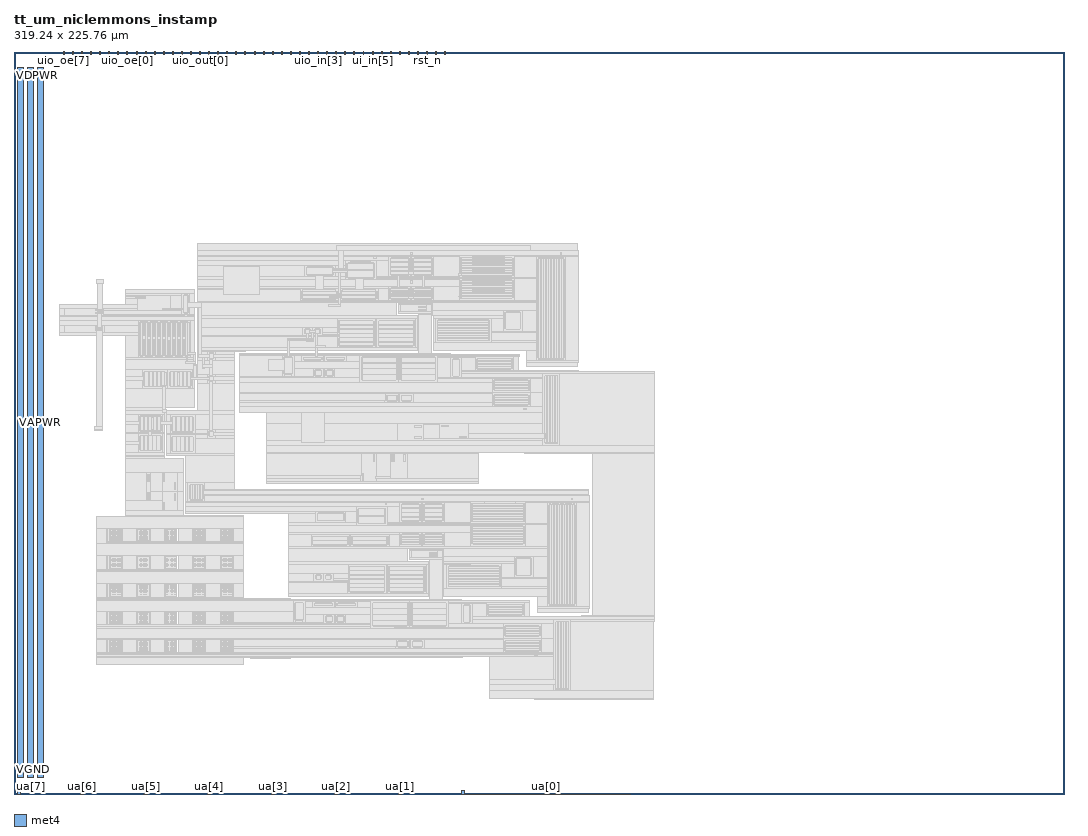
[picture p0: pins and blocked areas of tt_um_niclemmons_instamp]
MACRO tt_um_niclemmons_instamp
  CLASS BLOCK ;
  FOREIGN tt_um_niclemmons_instamp ;
  ORIGIN 0.000 0.000 ;
  SIZE 319.240 BY 225.760 ;
  PIN clk
    DIRECTION INPUT ;
    USE SIGNAL ;
    PORT
      LAYER met4 ;
        RECT 128.190 224.760 128.490 225.760 ;
    END
  END clk
  PIN ena
    DIRECTION INPUT ;
    USE SIGNAL ;
    PORT
      LAYER met4 ;
        RECT 130.950 224.760 131.250 225.760 ;
    END
  END ena
  PIN rst_n
    DIRECTION INPUT ;
    USE SIGNAL ;
    PORT
      LAYER met4 ;
        RECT 125.430 224.760 125.730 225.760 ;
    END
  END rst_n
  PIN ua[0]
    DIRECTION INOUT ;
    USE SIGNAL ;
    ANTENNADIFFAREA 69.599998 ;
    PORT
      LAYER met4 ;
        RECT 136.170 0.000 137.070 1.000 ;
        RECT 136.270 -0.020 187.300 0.000 ;
        RECT 185.690 -0.060 187.300 -0.020 ;
    END
  END ua[0]
  PIN ua[1]
    DIRECTION INOUT ;
    USE SIGNAL ;
    ANTENNAGATEAREA 60.000000 ;
    PORT
      LAYER met4 ;
        RECT 116.850 0.000 117.750 1.000 ;
    END
  END ua[1]
  PIN ua[2]
    DIRECTION INOUT ;
    USE SIGNAL ;
    ANTENNAGATEAREA 60.000000 ;
    PORT
      LAYER met4 ;
        RECT 97.530 0.000 98.430 1.000 ;
    END
  END ua[2]
  PIN ua[3]
    DIRECTION INOUT ;
    USE SIGNAL ;
    ANTENNAGATEAREA 60.000000 ;
    PORT
      LAYER met4 ;
        RECT 78.210 0.000 79.110 1.000 ;
    END
  END ua[3]
  PIN ua[4]
    DIRECTION INOUT ;
    USE SIGNAL ;
    ANTENNAGATEAREA 60.000000 ;
    PORT
      LAYER met4 ;
        RECT 58.890 0.000 59.790 1.000 ;
        RECT 58.850 -0.110 59.820 0.000 ;
    END
  END ua[4]
  PIN ua[5]
    DIRECTION INOUT ;
    USE SIGNAL ;
    ANTENNAGATEAREA 45.000000 ;
    ANTENNADIFFAREA 3.480000 ;
    PORT
      LAYER met4 ;
        RECT 39.570 0.000 40.470 1.000 ;
        RECT 39.510 -0.020 40.370 0.000 ;
    END
  END ua[5]
  PIN ua[6]
    DIRECTION INOUT ;
    USE SIGNAL ;
    PORT
      LAYER met4 ;
        RECT 20.250 0.000 21.150 1.000 ;
    END
  END ua[6]
  PIN ua[7]
    DIRECTION INOUT ;
    USE SIGNAL ;
    PORT
      LAYER met4 ;
        RECT 0.930 0.000 1.830 1.000 ;
    END
  END ua[7]
  PIN ui_in[0]
    DIRECTION INPUT ;
    USE SIGNAL ;
    PORT
      LAYER met4 ;
        RECT 122.670 224.760 122.970 225.760 ;
    END
  END ui_in[0]
  PIN ui_in[1]
    DIRECTION INPUT ;
    USE SIGNAL ;
    PORT
      LAYER met4 ;
        RECT 119.910 224.760 120.210 225.760 ;
    END
  END ui_in[1]
  PIN ui_in[2]
    DIRECTION INPUT ;
    USE SIGNAL ;
    PORT
      LAYER met4 ;
        RECT 117.150 224.760 117.450 225.760 ;
    END
  END ui_in[2]
  PIN ui_in[3]
    DIRECTION INPUT ;
    USE SIGNAL ;
    PORT
      LAYER met4 ;
        RECT 114.390 224.760 114.690 225.760 ;
    END
  END ui_in[3]
  PIN ui_in[4]
    DIRECTION INPUT ;
    USE SIGNAL ;
    PORT
      LAYER met4 ;
        RECT 111.630 224.760 111.930 225.760 ;
    END
  END ui_in[4]
  PIN ui_in[5]
    DIRECTION INPUT ;
    USE SIGNAL ;
    PORT
      LAYER met4 ;
        RECT 108.870 224.760 109.170 225.760 ;
    END
  END ui_in[5]
  PIN ui_in[6]
    DIRECTION INPUT ;
    USE SIGNAL ;
    PORT
      LAYER met4 ;
        RECT 106.110 224.760 106.410 225.760 ;
    END
  END ui_in[6]
  PIN ui_in[7]
    DIRECTION INPUT ;
    USE SIGNAL ;
    PORT
      LAYER met4 ;
        RECT 103.350 224.760 103.650 225.760 ;
    END
  END ui_in[7]
  PIN uio_in[0]
    DIRECTION INPUT ;
    USE SIGNAL ;
    PORT
      LAYER met4 ;
        RECT 100.590 224.760 100.890 225.760 ;
    END
  END uio_in[0]
  PIN uio_in[1]
    DIRECTION INPUT ;
    USE SIGNAL ;
    PORT
      LAYER met4 ;
        RECT 97.830 224.760 98.130 225.760 ;
    END
  END uio_in[1]
  PIN uio_in[2]
    DIRECTION INPUT ;
    USE SIGNAL ;
    PORT
      LAYER met4 ;
        RECT 95.070 224.760 95.370 225.760 ;
    END
  END uio_in[2]
  PIN uio_in[3]
    DIRECTION INPUT ;
    USE SIGNAL ;
    PORT
      LAYER met4 ;
        RECT 92.310 224.760 92.610 225.760 ;
    END
  END uio_in[3]
  PIN uio_in[4]
    DIRECTION INPUT ;
    USE SIGNAL ;
    PORT
      LAYER met4 ;
        RECT 89.550 224.760 89.850 225.760 ;
    END
  END uio_in[4]
  PIN uio_in[5]
    DIRECTION INPUT ;
    USE SIGNAL ;
    PORT
      LAYER met4 ;
        RECT 86.790 224.760 87.090 225.760 ;
    END
  END uio_in[5]
  PIN uio_in[6]
    DIRECTION INPUT ;
    USE SIGNAL ;
    PORT
      LAYER met4 ;
        RECT 84.030 224.760 84.330 225.760 ;
    END
  END uio_in[6]
  PIN uio_in[7]
    DIRECTION INPUT ;
    USE SIGNAL ;
    PORT
      LAYER met4 ;
        RECT 81.270 224.760 81.570 225.760 ;
    END
  END uio_in[7]
  PIN uio_oe[0]
    DIRECTION OUTPUT ;
    USE SIGNAL ;
    ANTENNAGATEAREA 668.222473 ;
    ANTENNADIFFAREA 820.115173 ;
    PORT
      LAYER met4 ;
        RECT 34.350 224.760 34.650 225.760 ;
    END
  END uio_oe[0]
  PIN uio_oe[1]
    DIRECTION OUTPUT ;
    USE SIGNAL ;
    ANTENNAGATEAREA 668.222473 ;
    ANTENNADIFFAREA 820.115173 ;
    PORT
      LAYER met4 ;
        RECT 31.590 224.760 31.890 225.760 ;
    END
  END uio_oe[1]
  PIN uio_oe[2]
    DIRECTION OUTPUT ;
    USE SIGNAL ;
    ANTENNAGATEAREA 668.222473 ;
    ANTENNADIFFAREA 820.115173 ;
    PORT
      LAYER met4 ;
        RECT 28.830 224.760 29.130 225.760 ;
    END
  END uio_oe[2]
  PIN uio_oe[3]
    DIRECTION OUTPUT ;
    USE SIGNAL ;
    ANTENNAGATEAREA 668.222473 ;
    ANTENNADIFFAREA 820.115173 ;
    PORT
      LAYER met4 ;
        RECT 26.070 224.760 26.370 225.760 ;
    END
  END uio_oe[3]
  PIN uio_oe[4]
    DIRECTION OUTPUT ;
    USE SIGNAL ;
    ANTENNAGATEAREA 668.222473 ;
    ANTENNADIFFAREA 820.115173 ;
    PORT
      LAYER met4 ;
        RECT 23.310 224.760 23.610 225.760 ;
    END
  END uio_oe[4]
  PIN uio_oe[5]
    DIRECTION OUTPUT ;
    USE SIGNAL ;
    ANTENNAGATEAREA 668.222473 ;
    ANTENNADIFFAREA 820.115173 ;
    PORT
      LAYER met4 ;
        RECT 20.550 224.760 20.850 225.760 ;
    END
  END uio_oe[5]
  PIN uio_oe[6]
    DIRECTION OUTPUT ;
    USE SIGNAL ;
    ANTENNAGATEAREA 668.222473 ;
    ANTENNADIFFAREA 820.115173 ;
    PORT
      LAYER met4 ;
        RECT 17.790 224.760 18.090 225.760 ;
    END
  END uio_oe[6]
  PIN uio_oe[7]
    DIRECTION OUTPUT ;
    USE SIGNAL ;
    ANTENNAGATEAREA 668.222473 ;
    ANTENNADIFFAREA 820.115173 ;
    PORT
      LAYER met4 ;
        RECT 15.030 224.760 15.330 225.760 ;
    END
  END uio_oe[7]
  PIN uio_out[0]
    DIRECTION OUTPUT ;
    USE SIGNAL ;
    ANTENNAGATEAREA 668.222473 ;
    ANTENNADIFFAREA 820.115173 ;
    PORT
      LAYER met4 ;
        RECT 56.430 224.760 56.730 225.760 ;
    END
  END uio_out[0]
  PIN uio_out[1]
    DIRECTION OUTPUT ;
    USE SIGNAL ;
    ANTENNAGATEAREA 668.222473 ;
    ANTENNADIFFAREA 820.115173 ;
    PORT
      LAYER met4 ;
        RECT 53.670 224.760 53.970 225.760 ;
    END
  END uio_out[1]
  PIN uio_out[2]
    DIRECTION OUTPUT ;
    USE SIGNAL ;
    ANTENNAGATEAREA 668.222473 ;
    ANTENNADIFFAREA 820.115173 ;
    PORT
      LAYER met4 ;
        RECT 50.910 224.760 51.210 225.760 ;
    END
  END uio_out[2]
  PIN uio_out[3]
    DIRECTION OUTPUT ;
    USE SIGNAL ;
    ANTENNAGATEAREA 668.222473 ;
    ANTENNADIFFAREA 820.115173 ;
    PORT
      LAYER met4 ;
        RECT 48.150 224.760 48.450 225.760 ;
    END
  END uio_out[3]
  PIN uio_out[4]
    DIRECTION OUTPUT ;
    USE SIGNAL ;
    ANTENNAGATEAREA 668.222473 ;
    ANTENNADIFFAREA 820.115173 ;
    PORT
      LAYER met4 ;
        RECT 45.390 224.760 45.690 225.760 ;
    END
  END uio_out[4]
  PIN uio_out[5]
    DIRECTION OUTPUT ;
    USE SIGNAL ;
    ANTENNAGATEAREA 668.222473 ;
    ANTENNADIFFAREA 820.115173 ;
    PORT
      LAYER met4 ;
        RECT 42.630 224.760 42.930 225.760 ;
    END
  END uio_out[5]
  PIN uio_out[6]
    DIRECTION OUTPUT ;
    USE SIGNAL ;
    ANTENNAGATEAREA 668.222473 ;
    ANTENNADIFFAREA 820.115173 ;
    PORT
      LAYER met4 ;
        RECT 39.870 224.760 40.170 225.760 ;
    END
  END uio_out[6]
  PIN uio_out[7]
    DIRECTION OUTPUT ;
    USE SIGNAL ;
    ANTENNAGATEAREA 668.222473 ;
    ANTENNADIFFAREA 820.115173 ;
    PORT
      LAYER met4 ;
        RECT 37.110 224.760 37.410 225.760 ;
    END
  END uio_out[7]
  PIN uo_out[0]
    DIRECTION OUTPUT ;
    USE SIGNAL ;
    ANTENNAGATEAREA 668.222473 ;
    ANTENNADIFFAREA 820.115173 ;
    PORT
      LAYER met4 ;
        RECT 78.510 224.760 78.810 225.760 ;
    END
  END uo_out[0]
  PIN uo_out[1]
    DIRECTION OUTPUT ;
    USE SIGNAL ;
    ANTENNAGATEAREA 668.222473 ;
    ANTENNADIFFAREA 820.115173 ;
    PORT
      LAYER met4 ;
        RECT 75.750 224.760 76.050 225.760 ;
    END
  END uo_out[1]
  PIN uo_out[2]
    DIRECTION OUTPUT ;
    USE SIGNAL ;
    ANTENNAGATEAREA 668.222473 ;
    ANTENNADIFFAREA 820.115173 ;
    PORT
      LAYER met4 ;
        RECT 72.990 224.760 73.290 225.760 ;
    END
  END uo_out[2]
  PIN uo_out[3]
    DIRECTION OUTPUT ;
    USE SIGNAL ;
    ANTENNAGATEAREA 668.222473 ;
    ANTENNADIFFAREA 820.115173 ;
    PORT
      LAYER met4 ;
        RECT 70.230 224.760 70.530 225.760 ;
    END
  END uo_out[3]
  PIN uo_out[4]
    DIRECTION OUTPUT ;
    USE SIGNAL ;
    ANTENNAGATEAREA 668.222473 ;
    ANTENNADIFFAREA 820.115173 ;
    PORT
      LAYER met4 ;
        RECT 67.470 224.760 67.770 225.760 ;
    END
  END uo_out[4]
  PIN uo_out[5]
    DIRECTION OUTPUT ;
    USE SIGNAL ;
    ANTENNAGATEAREA 668.222473 ;
    ANTENNADIFFAREA 820.115173 ;
    PORT
      LAYER met4 ;
        RECT 64.710 224.760 65.010 225.760 ;
    END
  END uo_out[5]
  PIN uo_out[6]
    DIRECTION OUTPUT ;
    USE SIGNAL ;
    ANTENNAGATEAREA 668.222473 ;
    ANTENNADIFFAREA 820.115173 ;
    PORT
      LAYER met4 ;
        RECT 61.950 224.760 62.250 225.760 ;
    END
  END uo_out[6]
  PIN uo_out[7]
    DIRECTION OUTPUT ;
    USE SIGNAL ;
    ANTENNAGATEAREA 668.222473 ;
    ANTENNADIFFAREA 820.115173 ;
    PORT
      LAYER met4 ;
        RECT 59.190 224.760 59.490 225.760 ;
    END
  END uo_out[7]
  PIN VDPWR
    DIRECTION INOUT ;
    USE POWER ;
    PORT
      LAYER met4 ;
        RECT 1.000 5.000 3.000 220.760 ;
    END
  END VDPWR
  PIN VGND
    DIRECTION INOUT ;
    USE GROUND ;
    PORT
      LAYER met4 ;
        RECT 4.000 5.000 6.000 220.760 ;
    END
  END VGND
  PIN VAPWR
    DIRECTION INOUT ;
    USE POWER ;
    PORT
      LAYER met4 ;
        RECT 7.000 5.000 9.000 220.760 ;
    END
  END VAPWR
  OBS
      LAYER nwell ;
        RECT 87.760 156.750 98.230 161.330 ;
        RECT 100.230 155.830 110.700 162.700 ;
        RECT 113.290 156.600 128.280 164.050 ;
      LAYER pwell ;
        RECT 14.880 145.220 27.720 148.060 ;
        RECT 37.030 146.530 48.020 151.860 ;
        RECT 50.540 145.200 53.840 152.780 ;
      LAYER nwell ;
        RECT 86.340 149.320 111.330 154.190 ;
        RECT 113.260 149.405 128.250 154.855 ;
        RECT 134.885 149.535 152.855 164.225 ;
      LAYER pwell ;
        RECT 117.170 146.230 125.910 149.070 ;
        RECT 14.940 140.020 27.780 142.860 ;
        RECT 37.230 132.240 54.020 144.540 ;
      LAYER nwell ;
        RECT 87.270 138.830 94.260 142.410 ;
        RECT 58.220 131.220 61.800 135.190 ;
        RECT 97.590 135.060 122.580 145.090 ;
        RECT 127.630 136.670 145.600 145.280 ;
        RECT 148.140 140.090 155.110 147.670 ;
      LAYER pwell ;
        RECT 38.565 122.905 54.835 129.485 ;
      LAYER nwell ;
        RECT 58.210 124.340 61.790 128.310 ;
      LAYER pwell ;
        RECT 81.100 126.620 85.680 133.920 ;
        RECT 87.020 130.980 101.530 133.780 ;
        RECT 90.480 126.080 97.990 129.880 ;
        RECT 104.710 124.750 129.220 133.920 ;
        RECT 132.330 125.940 136.410 133.240 ;
        RECT 139.760 128.210 152.340 133.380 ;
      LAYER nwell ;
        RECT 158.220 131.100 168.410 164.070 ;
      LAYER pwell ;
        RECT 112.340 118.410 121.850 122.210 ;
        RECT 144.960 117.190 157.540 126.880 ;
        RECT 37.190 103.430 45.650 115.940 ;
      LAYER nwell ;
        RECT 46.935 102.915 55.675 115.905 ;
        RECT 58.175 107.565 61.755 111.535 ;
      LAYER pwell ;
        RECT 116.280 107.120 124.760 112.980 ;
        RECT 129.090 107.610 138.550 112.940 ;
        RECT 160.330 105.620 166.290 128.200 ;
        RECT 39.870 88.800 41.880 98.120 ;
        RECT 44.670 85.760 50.000 98.150 ;
      LAYER nwell ;
        RECT 52.300 88.260 58.540 95.230 ;
      LAYER pwell ;
        RECT 105.110 94.570 110.440 104.030 ;
        RECT 114.090 95.620 119.950 104.100 ;
        RECT 27.590 81.385 34.290 82.150 ;
        RECT 27.590 76.215 28.355 81.385 ;
        RECT 33.525 76.215 34.290 81.385 ;
        RECT 27.590 75.450 34.290 76.215 ;
        RECT 36.030 81.385 42.730 82.150 ;
        RECT 36.030 76.215 36.795 81.385 ;
        RECT 41.965 76.215 42.730 81.385 ;
        RECT 36.030 75.450 42.730 76.215 ;
        RECT 44.470 81.385 51.170 82.150 ;
        RECT 44.470 76.215 45.235 81.385 ;
        RECT 50.405 76.215 51.170 81.385 ;
        RECT 44.470 75.450 51.170 76.215 ;
        RECT 52.910 81.385 59.610 82.150 ;
        RECT 52.910 76.215 53.675 81.385 ;
        RECT 58.845 76.215 59.610 81.385 ;
        RECT 52.910 75.450 59.610 76.215 ;
        RECT 61.350 81.385 68.050 82.150 ;
      LAYER nwell ;
        RECT 91.070 82.010 101.540 86.590 ;
      LAYER pwell ;
        RECT 61.350 76.215 62.115 81.385 ;
        RECT 67.285 76.215 68.050 81.385 ;
      LAYER nwell ;
        RECT 103.540 81.090 114.010 87.960 ;
        RECT 116.600 81.860 131.590 89.310 ;
      LAYER pwell ;
        RECT 61.350 75.450 68.050 76.215 ;
      LAYER nwell ;
        RECT 89.650 74.580 114.640 79.450 ;
        RECT 116.570 74.665 131.560 80.115 ;
        RECT 138.195 74.795 156.165 89.485 ;
      LAYER pwell ;
        RECT 27.590 72.945 34.290 73.710 ;
        RECT 27.590 67.775 28.355 72.945 ;
        RECT 33.525 67.775 34.290 72.945 ;
        RECT 27.590 67.010 34.290 67.775 ;
        RECT 36.030 72.945 42.730 73.710 ;
        RECT 36.030 67.775 36.795 72.945 ;
        RECT 41.965 67.775 42.730 72.945 ;
        RECT 36.030 67.010 42.730 67.775 ;
        RECT 44.470 72.945 51.170 73.710 ;
        RECT 44.470 67.775 45.235 72.945 ;
        RECT 50.405 67.775 51.170 72.945 ;
        RECT 44.470 67.010 51.170 67.775 ;
        RECT 52.910 72.945 59.610 73.710 ;
        RECT 52.910 67.775 53.675 72.945 ;
        RECT 58.845 67.775 59.610 72.945 ;
        RECT 52.910 67.010 59.610 67.775 ;
        RECT 61.350 72.945 68.050 73.710 ;
        RECT 61.350 67.775 62.115 72.945 ;
        RECT 67.285 67.775 68.050 72.945 ;
        RECT 120.480 71.490 129.220 74.330 ;
        RECT 61.350 67.010 68.050 67.775 ;
        RECT 27.590 64.505 34.290 65.270 ;
        RECT 27.590 59.335 28.355 64.505 ;
        RECT 33.525 59.335 34.290 64.505 ;
        RECT 27.590 58.570 34.290 59.335 ;
        RECT 36.030 64.505 42.730 65.270 ;
        RECT 36.030 59.335 36.795 64.505 ;
        RECT 41.965 59.335 42.730 64.505 ;
        RECT 36.030 58.570 42.730 59.335 ;
        RECT 44.470 64.505 51.170 65.270 ;
        RECT 44.470 59.335 45.235 64.505 ;
        RECT 50.405 59.335 51.170 64.505 ;
        RECT 44.470 58.570 51.170 59.335 ;
        RECT 52.910 64.505 59.610 65.270 ;
        RECT 52.910 59.335 53.675 64.505 ;
        RECT 58.845 59.335 59.610 64.505 ;
        RECT 52.910 58.570 59.610 59.335 ;
        RECT 61.350 64.505 68.050 65.270 ;
        RECT 61.350 59.335 62.115 64.505 ;
        RECT 67.285 59.335 68.050 64.505 ;
      LAYER nwell ;
        RECT 90.580 64.090 97.570 67.670 ;
        RECT 100.900 60.320 125.890 70.350 ;
        RECT 130.940 61.930 148.910 70.540 ;
        RECT 151.450 65.350 158.420 72.930 ;
      LAYER pwell ;
        RECT 61.350 58.570 68.050 59.335 ;
        RECT 27.590 56.065 34.290 56.830 ;
        RECT 27.590 50.895 28.355 56.065 ;
        RECT 33.525 50.895 34.290 56.065 ;
        RECT 27.590 50.130 34.290 50.895 ;
        RECT 36.030 56.065 42.730 56.830 ;
        RECT 36.030 50.895 36.795 56.065 ;
        RECT 41.965 50.895 42.730 56.065 ;
        RECT 36.030 50.130 42.730 50.895 ;
        RECT 44.470 56.065 51.170 56.830 ;
        RECT 44.470 50.895 45.235 56.065 ;
        RECT 50.405 50.895 51.170 56.065 ;
        RECT 44.470 50.130 51.170 50.895 ;
        RECT 52.910 56.065 59.610 56.830 ;
        RECT 52.910 50.895 53.675 56.065 ;
        RECT 58.845 50.895 59.610 56.065 ;
        RECT 52.910 50.130 59.610 50.895 ;
        RECT 61.350 56.065 68.050 56.830 ;
        RECT 61.350 50.895 62.115 56.065 ;
        RECT 67.285 50.895 68.050 56.065 ;
        RECT 84.410 51.880 88.990 59.180 ;
        RECT 90.330 56.240 104.840 59.040 ;
        RECT 93.790 51.340 101.300 55.140 ;
        RECT 61.350 50.130 68.050 50.895 ;
        RECT 108.020 50.010 132.530 59.180 ;
        RECT 135.640 51.200 139.720 58.500 ;
        RECT 143.070 53.470 155.650 58.640 ;
      LAYER nwell ;
        RECT 161.530 56.360 171.720 89.330 ;
      LAYER pwell ;
        RECT 27.590 47.625 34.290 48.390 ;
        RECT 27.590 42.455 28.355 47.625 ;
        RECT 33.525 42.455 34.290 47.625 ;
        RECT 27.590 41.690 34.290 42.455 ;
        RECT 36.030 47.625 42.730 48.390 ;
        RECT 36.030 42.455 36.795 47.625 ;
        RECT 41.965 42.455 42.730 47.625 ;
        RECT 36.030 41.690 42.730 42.455 ;
        RECT 44.470 47.625 51.170 48.390 ;
        RECT 44.470 42.455 45.235 47.625 ;
        RECT 50.405 42.455 51.170 47.625 ;
        RECT 44.470 41.690 51.170 42.455 ;
        RECT 52.910 47.625 59.610 48.390 ;
        RECT 52.910 42.455 53.675 47.625 ;
        RECT 58.845 42.455 59.610 47.625 ;
        RECT 52.910 41.690 59.610 42.455 ;
        RECT 61.350 47.625 68.050 48.390 ;
        RECT 61.350 42.455 62.115 47.625 ;
        RECT 67.285 42.455 68.050 47.625 ;
        RECT 115.650 43.670 125.160 47.470 ;
        RECT 61.350 41.690 68.050 42.455 ;
        RECT 148.270 42.450 160.850 52.140 ;
        RECT 163.640 30.880 169.600 53.460 ;
      LAYER li1 ;
        RECT 55.800 167.340 85.940 167.480 ;
        RECT 55.800 165.390 171.430 167.340 ;
        RECT 55.800 163.590 171.520 165.390 ;
        RECT 55.800 163.400 135.590 163.590 ;
        RECT 55.800 162.060 113.850 163.400 ;
        RECT 114.755 162.820 119.795 162.990 ;
        RECT 55.800 160.710 100.820 162.060 ;
        RECT 101.695 161.470 109.235 161.640 ;
        RECT 101.310 161.390 101.480 161.410 ;
        RECT 55.800 157.350 88.400 160.710 ;
        RECT 92.170 160.270 94.020 160.710 ;
        RECT 89.225 160.100 96.765 160.270 ;
        RECT 92.170 160.080 94.020 160.100 ;
        RECT 88.840 158.040 89.010 160.040 ;
        RECT 96.980 158.040 97.150 160.040 ;
        RECT 89.225 157.810 96.765 157.980 ;
        RECT 97.600 157.350 100.800 160.710 ;
        RECT 101.080 159.410 101.480 161.390 ;
        RECT 109.450 159.410 109.620 161.410 ;
        RECT 101.080 159.120 101.450 159.410 ;
        RECT 101.695 159.180 109.235 159.350 ;
        RECT 25.050 155.260 27.290 156.480 ;
        RECT 55.800 156.400 100.820 157.350 ;
        RECT 101.080 157.140 101.480 159.120 ;
        RECT 101.310 157.120 101.480 157.140 ;
        RECT 109.450 157.120 109.620 159.120 ;
        RECT 110.130 157.230 113.850 162.060 ;
        RECT 114.370 161.760 114.540 162.760 ;
        RECT 120.010 162.690 120.180 162.760 ;
        RECT 120.010 161.760 120.380 162.690 ;
        RECT 114.755 161.530 119.795 161.700 ;
        RECT 120.020 161.470 120.380 161.760 ;
        RECT 114.370 160.470 114.540 161.470 ;
        RECT 120.010 160.470 120.380 161.470 ;
        RECT 114.755 160.240 119.795 160.410 ;
        RECT 120.020 160.180 120.380 160.470 ;
        RECT 114.370 159.180 114.540 160.180 ;
        RECT 120.010 159.180 120.380 160.180 ;
        RECT 114.755 158.950 119.795 159.120 ;
        RECT 120.020 158.890 120.380 159.180 ;
        RECT 114.370 157.890 114.540 158.890 ;
        RECT 120.010 157.950 120.380 158.890 ;
        RECT 120.010 157.890 120.180 157.950 ;
        RECT 114.755 157.660 119.795 157.830 ;
        RECT 120.700 157.230 120.870 163.400 ;
        RECT 121.775 162.820 126.815 162.990 ;
        RECT 121.390 162.710 121.560 162.760 ;
        RECT 121.130 161.760 121.560 162.710 ;
        RECT 127.030 161.760 127.200 162.760 ;
        RECT 121.130 161.470 121.490 161.760 ;
        RECT 121.775 161.530 126.815 161.700 ;
        RECT 121.130 160.470 121.560 161.470 ;
        RECT 127.030 160.470 127.200 161.470 ;
        RECT 121.130 160.180 121.490 160.470 ;
        RECT 121.775 160.240 126.815 160.410 ;
        RECT 121.130 159.180 121.560 160.180 ;
        RECT 127.030 159.180 127.200 160.180 ;
        RECT 121.130 158.890 121.490 159.180 ;
        RECT 121.775 158.950 126.815 159.120 ;
        RECT 121.130 157.970 121.560 158.890 ;
        RECT 121.390 157.890 121.560 157.970 ;
        RECT 127.030 157.890 127.200 158.890 ;
        RECT 121.775 157.660 126.815 157.830 ;
        RECT 127.650 157.230 135.590 163.400 ;
        RECT 139.610 163.165 149.210 163.590 ;
        RECT 152.230 163.510 171.520 163.590 ;
        RECT 135.860 157.650 136.140 163.130 ;
        RECT 136.350 162.995 151.390 163.165 ;
        RECT 139.610 162.960 149.210 162.995 ;
        RECT 151.605 162.435 151.775 162.935 ;
        RECT 136.350 162.205 151.390 162.375 ;
        RECT 151.605 161.645 151.775 162.145 ;
        RECT 136.350 161.415 151.390 161.585 ;
        RECT 151.605 160.855 151.775 161.355 ;
        RECT 136.350 160.625 151.390 160.795 ;
        RECT 151.605 160.065 151.775 160.565 ;
        RECT 136.350 159.835 151.390 160.005 ;
        RECT 151.605 159.275 151.775 159.775 ;
        RECT 136.350 159.045 151.390 159.215 ;
        RECT 151.605 158.485 151.775 158.985 ;
        RECT 136.350 158.255 151.390 158.425 ;
        RECT 151.605 157.695 151.775 158.195 ;
        RECT 136.350 157.465 151.390 157.635 ;
        RECT 101.695 156.890 109.235 157.060 ;
        RECT 110.130 156.965 135.590 157.230 ;
        RECT 152.230 156.965 158.850 163.510 ;
        RECT 159.500 162.850 167.140 163.220 ;
        RECT 159.510 162.820 160.010 162.850 ;
        RECT 160.300 162.820 160.800 162.850 ;
        RECT 161.090 162.820 161.590 162.850 ;
        RECT 161.880 162.820 162.380 162.850 ;
        RECT 162.670 162.820 163.170 162.850 ;
        RECT 163.460 162.820 163.960 162.850 ;
        RECT 164.250 162.820 164.750 162.850 ;
        RECT 165.040 162.820 165.540 162.850 ;
        RECT 165.830 162.820 166.330 162.850 ;
        RECT 166.620 162.820 167.120 162.850 ;
        RECT 110.130 156.795 158.850 156.965 ;
        RECT 110.130 156.400 135.590 156.795 ;
        RECT 55.800 154.230 135.590 156.400 ;
        RECT 55.800 153.580 113.850 154.230 ;
        RECT 114.725 153.625 119.765 153.795 ;
        RECT 55.800 153.400 87.000 153.580 ;
        RECT 33.940 152.220 54.900 153.400 ;
        RECT 33.940 151.460 51.020 152.220 ;
        RECT 51.690 151.680 52.690 151.850 ;
        RECT 33.940 151.140 40.020 151.460 ;
        RECT 33.940 150.690 40.100 151.140 ;
        RECT 33.940 148.700 37.580 150.690 ;
        RECT 37.780 150.530 40.100 150.690 ;
        RECT 13.860 148.680 15.250 148.700 ;
        RECT 28.290 148.680 37.580 148.700 ;
        RECT 13.860 147.640 37.580 148.680 ;
        RECT 13.860 145.590 15.250 147.640 ;
        RECT 24.730 146.880 26.890 147.230 ;
        RECT 27.330 146.910 37.580 147.640 ;
        RECT 45.030 147.360 47.190 147.710 ;
        RECT 47.600 146.910 51.020 151.460 ;
        RECT 24.730 146.050 26.890 146.400 ;
        RECT 27.330 145.640 51.020 146.910 ;
        RECT 51.460 146.470 51.630 151.510 ;
        RECT 52.750 146.470 52.920 151.510 ;
        RECT 51.690 146.130 52.690 146.300 ;
        RECT 53.280 145.640 54.900 152.220 ;
        RECT 27.330 145.590 54.900 145.640 ;
        RECT 13.860 145.030 54.900 145.590 ;
        RECT 55.790 149.880 87.000 153.400 ;
        RECT 87.805 152.960 97.845 153.130 ;
        RECT 98.150 152.900 98.400 152.930 ;
        RECT 87.420 151.900 87.590 152.900 ;
        RECT 98.060 151.900 98.400 152.900 ;
        RECT 87.805 151.670 97.845 151.840 ;
        RECT 98.150 151.610 98.400 151.900 ;
        RECT 87.420 150.610 87.590 151.610 ;
        RECT 98.060 150.630 98.400 151.610 ;
        RECT 98.060 150.610 98.230 150.630 ;
        RECT 87.805 150.380 97.845 150.550 ;
        RECT 98.750 149.950 98.920 153.580 ;
        RECT 99.825 152.960 109.865 153.130 ;
        RECT 99.180 152.900 99.570 152.950 ;
        RECT 110.170 152.900 110.420 152.930 ;
        RECT 99.180 151.900 99.610 152.900 ;
        RECT 110.080 151.900 110.420 152.900 ;
        RECT 99.180 151.610 99.570 151.900 ;
        RECT 99.825 151.670 109.865 151.840 ;
        RECT 110.170 151.610 110.420 151.900 ;
        RECT 99.180 150.610 99.610 151.610 ;
        RECT 110.080 150.630 110.420 151.610 ;
        RECT 110.080 150.610 110.250 150.630 ;
        RECT 99.180 150.560 99.570 150.610 ;
        RECT 99.825 150.380 109.865 150.550 ;
        RECT 110.740 149.965 113.850 153.580 ;
        RECT 120.020 153.565 120.240 153.650 ;
        RECT 114.340 153.065 114.510 153.565 ;
        RECT 119.980 153.065 120.240 153.565 ;
        RECT 114.725 152.835 119.765 153.005 ;
        RECT 120.020 152.775 120.240 153.065 ;
        RECT 114.340 152.275 114.510 152.775 ;
        RECT 119.980 152.275 120.240 152.775 ;
        RECT 114.725 152.045 119.765 152.215 ;
        RECT 120.020 151.985 120.240 152.275 ;
        RECT 114.340 151.485 114.510 151.985 ;
        RECT 119.980 151.485 120.240 151.985 ;
        RECT 114.725 151.255 119.765 151.425 ;
        RECT 120.020 151.195 120.240 151.485 ;
        RECT 114.340 150.695 114.510 151.195 ;
        RECT 119.980 150.695 120.240 151.195 ;
        RECT 120.020 150.670 120.240 150.695 ;
        RECT 114.725 150.465 119.765 150.635 ;
        RECT 120.670 149.970 120.840 154.230 ;
        RECT 121.250 153.565 121.470 153.700 ;
        RECT 121.745 153.625 126.785 153.795 ;
        RECT 121.250 153.065 121.530 153.565 ;
        RECT 127.000 153.065 127.170 153.565 ;
        RECT 121.250 152.775 121.470 153.065 ;
        RECT 121.745 152.835 126.785 153.005 ;
        RECT 121.250 152.275 121.530 152.775 ;
        RECT 127.000 152.275 127.170 152.775 ;
        RECT 121.250 151.985 121.470 152.275 ;
        RECT 121.745 152.045 126.785 152.215 ;
        RECT 121.250 151.485 121.530 151.985 ;
        RECT 127.000 151.485 127.170 151.985 ;
        RECT 121.250 151.195 121.470 151.485 ;
        RECT 121.745 151.255 126.785 151.425 ;
        RECT 121.250 150.720 121.530 151.195 ;
        RECT 121.360 150.695 121.530 150.720 ;
        RECT 127.000 150.695 127.170 151.195 ;
        RECT 121.745 150.465 126.785 150.635 ;
        RECT 127.650 150.120 135.590 154.230 ;
        RECT 135.830 156.065 136.110 156.270 ;
        RECT 136.350 156.125 151.390 156.295 ;
        RECT 135.830 155.565 136.135 156.065 ;
        RECT 151.605 155.565 151.775 156.065 ;
        RECT 135.830 155.275 136.110 155.565 ;
        RECT 136.350 155.335 151.390 155.505 ;
        RECT 135.830 154.775 136.135 155.275 ;
        RECT 151.605 154.775 151.775 155.275 ;
        RECT 135.830 154.485 136.110 154.775 ;
        RECT 136.350 154.545 151.390 154.715 ;
        RECT 135.830 153.985 136.135 154.485 ;
        RECT 151.605 153.985 151.775 154.485 ;
        RECT 135.830 153.695 136.110 153.985 ;
        RECT 136.350 153.755 151.390 153.925 ;
        RECT 135.830 153.195 136.135 153.695 ;
        RECT 151.605 153.195 151.775 153.695 ;
        RECT 135.830 152.905 136.110 153.195 ;
        RECT 136.350 152.965 151.390 153.135 ;
        RECT 135.830 152.405 136.135 152.905 ;
        RECT 151.605 152.405 151.775 152.905 ;
        RECT 135.830 152.115 136.110 152.405 ;
        RECT 136.350 152.175 151.390 152.345 ;
        RECT 135.830 151.615 136.135 152.115 ;
        RECT 151.605 151.615 151.775 152.115 ;
        RECT 135.830 151.325 136.110 151.615 ;
        RECT 136.350 151.385 151.390 151.555 ;
        RECT 135.830 150.825 136.135 151.325 ;
        RECT 151.605 150.825 151.775 151.325 ;
        RECT 135.830 150.790 136.110 150.825 ;
        RECT 136.350 150.595 151.390 150.765 ;
        RECT 152.230 150.140 158.850 156.795 ;
        RECT 148.350 150.120 158.850 150.140 ;
        RECT 127.650 150.010 158.850 150.120 ;
        RECT 126.400 149.970 158.850 150.010 ;
        RECT 117.190 149.965 158.850 149.970 ;
        RECT 110.740 149.950 158.850 149.965 ;
        RECT 97.470 149.900 158.850 149.950 ;
        RECT 87.250 149.880 158.850 149.900 ;
        RECT 55.790 149.290 158.850 149.880 ;
        RECT 55.790 145.540 116.350 149.290 ;
        RECT 116.940 148.710 127.070 149.080 ;
        RECT 116.940 146.630 117.530 148.710 ;
        RECT 122.920 147.890 125.080 148.240 ;
        RECT 122.920 147.060 125.080 147.410 ;
        RECT 125.540 146.630 127.070 148.710 ;
        RECT 116.940 146.150 127.070 146.630 ;
        RECT 116.950 145.980 127.070 146.150 ;
        RECT 122.970 145.930 127.070 145.980 ;
        RECT 127.370 147.010 158.850 149.290 ;
        RECT 13.860 144.070 54.890 145.030 ;
        RECT 55.790 144.500 122.710 145.540 ;
        RECT 55.790 144.480 117.530 144.500 ;
        RECT 13.860 142.510 37.710 144.070 ;
        RECT 38.530 143.620 38.910 143.670 ;
        RECT 38.500 143.450 38.980 143.620 ;
        RECT 40.030 143.450 40.510 143.620 ;
        RECT 41.560 143.450 42.040 143.620 ;
        RECT 43.090 143.450 43.570 143.620 ;
        RECT 44.620 143.450 45.100 143.620 ;
        RECT 46.150 143.450 46.630 143.620 ;
        RECT 47.680 143.450 48.160 143.620 ;
        RECT 49.210 143.450 49.690 143.620 ;
        RECT 50.740 143.450 51.220 143.620 ;
        RECT 52.270 143.450 52.750 143.620 ;
        RECT 13.860 140.420 15.290 142.510 ;
        RECT 24.790 141.680 26.950 142.030 ;
        RECT 24.790 140.850 26.950 141.200 ;
        RECT 27.430 140.420 37.710 142.510 ;
        RECT 13.820 139.530 37.710 140.420 ;
        RECT 13.820 139.510 28.680 139.530 ;
        RECT 33.940 132.730 37.710 139.530 ;
        RECT 38.160 133.390 38.330 143.390 ;
        RECT 39.150 133.390 39.320 143.390 ;
        RECT 39.690 133.390 39.860 143.390 ;
        RECT 40.680 133.390 40.850 143.390 ;
        RECT 41.220 133.390 41.390 143.390 ;
        RECT 42.210 133.390 42.380 143.390 ;
        RECT 42.750 133.390 42.920 143.390 ;
        RECT 43.740 133.390 43.910 143.390 ;
        RECT 44.280 133.390 44.450 143.390 ;
        RECT 45.270 133.390 45.440 143.390 ;
        RECT 45.810 133.390 45.980 143.390 ;
        RECT 46.800 133.390 46.970 143.390 ;
        RECT 47.340 133.390 47.510 143.390 ;
        RECT 48.330 133.390 48.500 143.390 ;
        RECT 48.870 133.390 49.040 143.390 ;
        RECT 49.860 133.390 50.030 143.390 ;
        RECT 50.400 133.390 50.570 143.390 ;
        RECT 51.390 133.390 51.560 143.390 ;
        RECT 51.930 133.390 52.100 143.390 ;
        RECT 52.920 133.390 53.090 143.390 ;
        RECT 38.500 133.160 38.980 133.330 ;
        RECT 40.030 133.160 40.510 133.330 ;
        RECT 41.560 133.160 42.040 133.330 ;
        RECT 43.090 133.160 43.570 133.330 ;
        RECT 44.620 133.160 45.100 133.330 ;
        RECT 46.150 133.160 46.630 133.330 ;
        RECT 47.680 133.160 48.160 133.330 ;
        RECT 49.210 133.160 49.690 133.330 ;
        RECT 50.740 133.160 51.220 133.330 ;
        RECT 52.270 133.160 52.750 133.330 ;
        RECT 38.520 132.730 38.950 133.160 ;
        RECT 53.520 132.730 54.850 144.070 ;
        RECT 33.940 132.220 54.850 132.730 ;
        RECT 55.790 141.780 98.250 144.480 ;
        RECT 99.055 143.860 109.095 144.030 ;
        RECT 55.790 139.470 87.840 141.780 ;
        RECT 88.750 141.350 89.760 141.780 ;
        RECT 88.735 141.180 89.775 141.350 ;
        RECT 88.350 140.120 88.520 141.120 ;
        RECT 89.990 140.120 90.160 141.120 ;
        RECT 88.735 139.890 89.775 140.060 ;
        RECT 90.680 139.470 90.850 141.780 ;
        RECT 91.770 141.350 92.780 141.780 ;
        RECT 91.755 141.180 92.795 141.350 ;
        RECT 91.370 140.120 91.540 141.120 ;
        RECT 93.010 140.120 93.180 141.120 ;
        RECT 93.680 140.350 98.250 141.780 ;
        RECT 91.755 139.890 92.795 140.060 ;
        RECT 93.680 139.760 98.240 140.350 ;
        RECT 93.680 139.470 98.250 139.760 ;
        RECT 55.790 139.050 98.250 139.470 ;
        RECT 55.790 135.650 98.230 139.050 ;
        RECT 98.430 136.310 98.840 143.840 ;
        RECT 109.310 142.800 109.480 143.800 ;
        RECT 99.055 142.570 109.095 142.740 ;
        RECT 109.310 141.510 109.480 142.510 ;
        RECT 99.055 141.280 109.095 141.450 ;
        RECT 109.310 140.220 109.480 141.220 ;
        RECT 99.055 139.990 109.095 140.160 ;
        RECT 109.310 138.930 109.480 139.930 ;
        RECT 99.055 138.700 109.095 138.870 ;
        RECT 109.310 137.640 109.480 138.640 ;
        RECT 99.055 137.410 109.095 137.580 ;
        RECT 109.310 136.350 109.480 137.350 ;
        RECT 99.055 136.120 109.095 136.290 ;
        RECT 110.000 135.650 110.170 144.480 ;
        RECT 110.430 144.460 117.530 144.480 ;
        RECT 111.075 143.860 121.115 144.030 ;
        RECT 121.390 143.800 121.680 143.820 ;
        RECT 110.690 142.800 110.860 143.800 ;
        RECT 121.330 142.800 121.680 143.800 ;
        RECT 111.075 142.570 121.115 142.740 ;
        RECT 121.390 142.510 121.680 142.800 ;
        RECT 110.690 141.510 110.860 142.510 ;
        RECT 121.330 141.510 121.680 142.510 ;
        RECT 111.075 141.280 121.115 141.450 ;
        RECT 121.390 141.220 121.680 141.510 ;
        RECT 110.690 140.220 110.860 141.220 ;
        RECT 121.330 140.220 121.680 141.220 ;
        RECT 111.075 139.990 121.115 140.160 ;
        RECT 121.390 139.930 121.680 140.220 ;
        RECT 110.690 138.930 110.860 139.930 ;
        RECT 121.330 138.930 121.680 139.930 ;
        RECT 111.075 138.700 121.115 138.870 ;
        RECT 121.390 138.640 121.680 138.930 ;
        RECT 110.690 137.640 110.860 138.640 ;
        RECT 121.330 137.640 121.680 138.640 ;
        RECT 111.075 137.410 121.115 137.580 ;
        RECT 121.390 137.350 121.680 137.640 ;
        RECT 110.690 136.350 110.860 137.350 ;
        RECT 121.330 136.370 121.680 137.350 ;
        RECT 121.330 136.350 121.500 136.370 ;
        RECT 111.075 136.120 121.115 136.290 ;
        RECT 122.000 135.650 122.710 144.500 ;
        RECT 55.790 134.870 122.710 135.650 ;
        RECT 55.790 134.780 85.940 134.870 ;
        RECT 55.790 134.650 70.410 134.780 ;
        RECT 55.790 134.570 67.080 134.650 ;
        RECT 33.940 129.000 54.840 132.220 ;
        RECT 33.940 126.910 39.070 129.000 ;
        RECT 39.715 128.385 40.715 128.555 ;
        RECT 41.005 128.385 42.005 128.555 ;
        RECT 42.295 128.385 43.295 128.555 ;
        RECT 43.585 128.385 44.585 128.555 ;
        RECT 44.875 128.385 45.875 128.555 ;
        RECT 39.485 128.190 39.655 128.215 ;
        RECT 39.390 126.910 39.655 128.190 ;
        RECT 33.940 125.800 39.655 126.910 ;
        RECT 33.940 123.410 39.070 125.800 ;
        RECT 39.390 124.190 39.655 125.800 ;
        RECT 39.485 124.175 39.655 124.190 ;
        RECT 40.775 124.175 40.945 128.215 ;
        RECT 42.065 124.175 42.235 128.215 ;
        RECT 43.355 124.175 43.525 128.215 ;
        RECT 44.645 124.175 44.815 128.215 ;
        RECT 45.935 124.175 46.105 128.215 ;
        RECT 39.715 123.835 40.715 124.005 ;
        RECT 41.005 123.835 42.005 124.005 ;
        RECT 42.295 123.835 43.295 124.005 ;
        RECT 43.585 123.835 44.585 124.005 ;
        RECT 44.875 123.835 45.875 124.005 ;
        RECT 46.615 123.410 46.785 129.000 ;
        RECT 47.525 128.385 48.525 128.555 ;
        RECT 48.815 128.385 49.815 128.555 ;
        RECT 50.105 128.385 51.105 128.555 ;
        RECT 51.395 128.385 52.395 128.555 ;
        RECT 52.685 128.385 53.685 128.555 ;
        RECT 47.295 124.175 47.465 128.215 ;
        RECT 48.585 124.175 48.755 128.215 ;
        RECT 49.875 124.175 50.045 128.215 ;
        RECT 51.165 124.175 51.335 128.215 ;
        RECT 52.455 124.175 52.625 128.215 ;
        RECT 53.745 124.175 53.915 128.215 ;
        RECT 47.525 123.835 48.525 124.005 ;
        RECT 48.815 123.835 49.815 124.005 ;
        RECT 50.105 123.835 51.105 124.005 ;
        RECT 51.395 123.835 52.395 124.005 ;
        RECT 52.685 123.835 53.685 124.005 ;
        RECT 54.350 123.410 54.840 129.000 ;
        RECT 33.940 117.620 54.840 123.410 ;
        RECT 55.790 131.930 58.870 134.570 ;
        RECT 59.510 133.940 60.510 134.110 ;
        RECT 59.280 132.685 59.450 133.725 ;
        RECT 60.570 133.700 60.740 133.725 ;
        RECT 61.180 133.700 67.080 134.570 ;
        RECT 60.560 132.690 67.080 133.700 ;
        RECT 60.570 132.685 60.740 132.690 ;
        RECT 59.510 132.300 60.510 132.470 ;
        RECT 61.180 131.930 67.080 132.690 ;
        RECT 55.790 127.650 67.080 131.930 ;
        RECT 55.790 124.940 58.870 127.650 ;
        RECT 59.500 127.060 60.500 127.230 ;
        RECT 59.270 125.805 59.440 126.845 ;
        RECT 60.560 126.810 60.730 126.845 ;
        RECT 61.180 126.810 67.080 127.650 ;
        RECT 60.550 125.800 67.080 126.810 ;
        RECT 59.500 125.420 60.500 125.590 ;
        RECT 61.180 124.940 67.080 125.800 ;
        RECT 33.940 116.720 45.710 117.620 ;
        RECT 55.790 116.740 67.080 124.940 ;
        RECT 55.020 116.720 67.080 116.740 ;
        RECT 33.940 115.480 45.770 116.720 ;
        RECT 33.940 113.130 37.710 115.480 ;
        RECT 38.340 114.840 39.340 115.010 ;
        RECT 39.630 114.840 40.630 115.010 ;
        RECT 40.920 114.840 41.920 115.010 ;
        RECT 42.210 114.840 43.210 115.010 ;
        RECT 43.500 114.840 44.500 115.010 ;
        RECT 38.110 114.650 38.280 114.670 ;
        RECT 38.050 114.630 38.290 114.650 ;
        RECT 37.930 113.130 38.290 114.630 ;
        RECT 33.940 112.420 38.290 113.130 ;
        RECT 33.940 109.770 37.710 112.420 ;
        RECT 37.930 110.650 38.290 112.420 ;
        RECT 37.930 110.630 38.280 110.650 ;
        RECT 39.400 110.630 39.570 114.670 ;
        RECT 40.690 110.630 40.860 114.670 ;
        RECT 41.980 110.630 42.150 114.670 ;
        RECT 43.270 110.630 43.440 114.670 ;
        RECT 44.560 110.630 44.730 114.670 ;
        RECT 38.340 110.290 39.340 110.460 ;
        RECT 39.630 110.290 40.630 110.460 ;
        RECT 40.920 110.290 41.920 110.460 ;
        RECT 42.210 110.290 43.210 110.460 ;
        RECT 43.500 110.290 44.500 110.460 ;
        RECT 45.160 109.770 45.770 115.480 ;
        RECT 33.940 109.600 45.770 109.770 ;
        RECT 33.940 107.040 37.710 109.600 ;
        RECT 38.340 108.910 39.340 109.080 ;
        RECT 39.630 108.910 40.630 109.080 ;
        RECT 40.920 108.910 41.920 109.080 ;
        RECT 42.210 108.910 43.210 109.080 ;
        RECT 43.500 108.910 44.500 109.080 ;
        RECT 38.010 107.040 38.310 108.740 ;
        RECT 33.940 106.330 38.310 107.040 ;
        RECT 33.940 103.900 37.710 106.330 ;
        RECT 38.010 104.740 38.310 106.330 ;
        RECT 38.040 104.730 38.310 104.740 ;
        RECT 38.110 104.700 38.280 104.730 ;
        RECT 39.400 104.700 39.570 108.740 ;
        RECT 40.690 104.700 40.860 108.740 ;
        RECT 41.980 104.700 42.150 108.740 ;
        RECT 43.270 104.700 43.440 108.740 ;
        RECT 44.560 104.700 44.730 108.740 ;
        RECT 38.340 104.360 39.340 104.530 ;
        RECT 39.630 104.360 40.630 104.530 ;
        RECT 40.920 104.360 41.920 104.530 ;
        RECT 42.210 104.360 43.210 104.530 ;
        RECT 43.500 104.360 44.500 104.530 ;
        RECT 45.160 103.900 45.770 109.600 ;
        RECT 46.450 115.290 67.080 116.720 ;
        RECT 68.690 134.010 80.770 134.050 ;
        RECT 122.970 134.010 127.060 145.930 ;
        RECT 127.370 145.380 148.750 147.010 ;
        RECT 150.600 146.610 152.880 147.010 ;
        RECT 149.605 146.440 153.645 146.610 ;
        RECT 150.600 146.430 152.880 146.440 ;
        RECT 127.400 144.700 148.750 145.380 ;
        RECT 127.400 144.610 135.590 144.700 ;
        RECT 127.400 137.230 128.190 144.610 ;
        RECT 129.095 144.050 144.135 144.220 ;
        RECT 128.710 143.490 128.880 143.990 ;
        RECT 144.350 143.930 144.520 143.990 ;
        RECT 129.095 143.260 144.135 143.430 ;
        RECT 128.710 142.700 128.880 143.200 ;
        RECT 129.095 142.470 144.135 142.640 ;
        RECT 128.710 141.910 128.880 142.410 ;
        RECT 129.095 141.680 144.135 141.850 ;
        RECT 128.710 141.120 128.880 141.620 ;
        RECT 129.095 140.890 144.135 141.060 ;
        RECT 128.710 140.330 128.880 140.830 ;
        RECT 129.095 140.100 144.135 140.270 ;
        RECT 128.710 139.540 128.880 140.040 ;
        RECT 129.095 139.310 144.135 139.480 ;
        RECT 128.710 138.750 128.880 139.250 ;
        RECT 129.095 138.520 144.135 138.690 ;
        RECT 128.710 137.960 128.880 138.460 ;
        RECT 144.330 137.970 144.680 143.930 ;
        RECT 145.040 140.710 148.750 144.700 ;
        RECT 149.220 141.380 149.390 146.380 ;
        RECT 153.860 141.380 154.030 146.380 ;
        RECT 149.605 141.150 153.645 141.320 ;
        RECT 154.540 140.710 158.850 147.010 ;
        RECT 145.040 140.330 158.850 140.710 ;
        RECT 144.350 137.960 144.520 137.970 ;
        RECT 129.095 137.730 144.135 137.900 ;
        RECT 145.040 137.850 158.800 140.330 ;
        RECT 145.040 137.230 158.840 137.850 ;
        RECT 127.400 134.880 158.840 137.230 ;
        RECT 127.400 134.850 153.010 134.880 ;
        RECT 155.890 134.850 158.840 134.880 ;
        RECT 68.690 133.990 81.620 134.010 ;
        RECT 104.640 133.990 132.840 134.010 ;
        RECT 68.690 133.720 132.840 133.990 ;
        RECT 68.690 133.460 153.550 133.720 ;
        RECT 68.690 133.440 105.240 133.460 ;
        RECT 68.690 127.030 81.620 133.440 ;
        RECT 85.240 133.370 105.150 133.440 ;
        RECT 82.370 132.830 84.410 133.000 ;
        RECT 82.030 127.770 82.200 132.770 ;
        RECT 84.580 127.770 84.750 132.770 ;
        RECT 85.240 131.390 87.510 133.370 ;
        RECT 88.290 132.690 93.330 132.860 ;
        RECT 87.950 132.130 88.120 132.630 ;
        RECT 93.500 132.130 93.670 132.630 ;
        RECT 88.290 131.900 93.330 132.070 ;
        RECT 94.190 131.420 94.360 133.370 ;
        RECT 95.220 132.690 100.260 132.860 ;
        RECT 94.880 132.130 95.050 132.630 ;
        RECT 100.430 132.130 100.600 132.630 ;
        RECT 95.220 131.900 100.260 132.070 ;
        RECT 101.090 131.420 105.150 133.370 ;
        RECT 106.120 133.000 115.980 133.060 ;
        RECT 105.980 132.830 116.020 133.000 ;
        RECT 116.200 132.770 116.600 132.880 ;
        RECT 90.700 131.390 105.190 131.420 ;
        RECT 85.240 129.450 105.190 131.390 ;
        RECT 105.640 131.270 105.810 132.770 ;
        RECT 116.190 131.270 116.600 132.770 ;
        RECT 105.980 131.040 116.020 131.210 ;
        RECT 116.200 130.980 116.600 131.270 ;
        RECT 105.640 129.480 105.810 130.980 ;
        RECT 116.190 129.480 116.600 130.980 ;
        RECT 82.370 127.640 84.410 127.710 ;
        RECT 82.360 127.540 84.410 127.640 ;
        RECT 82.360 127.030 84.380 127.540 ;
        RECT 85.240 127.030 90.910 129.450 ;
        RECT 91.750 128.790 93.290 128.960 ;
        RECT 91.410 127.230 91.580 128.730 ;
        RECT 93.460 127.230 93.630 128.730 ;
        RECT 91.750 127.150 93.290 127.170 ;
        RECT 68.690 126.590 90.910 127.030 ;
        RECT 91.740 126.880 93.310 127.150 ;
        RECT 91.920 126.590 93.090 126.880 ;
        RECT 94.150 126.590 94.320 129.450 ;
        RECT 95.180 128.790 96.720 128.960 ;
        RECT 94.840 127.230 95.010 128.730 ;
        RECT 96.890 127.230 97.060 128.730 ;
        RECT 95.180 127.150 96.720 127.170 ;
        RECT 95.170 126.880 96.740 127.150 ;
        RECT 95.350 126.590 96.520 126.880 ;
        RECT 97.510 126.590 105.180 129.450 ;
        RECT 105.980 129.250 116.020 129.420 ;
        RECT 116.200 129.190 116.600 129.480 ;
        RECT 105.640 127.690 105.810 129.190 ;
        RECT 116.190 127.690 116.600 129.190 ;
        RECT 105.980 127.460 116.020 127.630 ;
        RECT 116.200 127.400 116.600 127.690 ;
        RECT 68.690 125.170 105.180 126.590 ;
        RECT 105.640 125.900 105.810 127.400 ;
        RECT 116.190 125.950 116.600 127.400 ;
        RECT 116.190 125.900 116.360 125.950 ;
        RECT 105.980 125.670 116.020 125.840 ;
        RECT 116.880 125.260 117.050 133.460 ;
        RECT 118.000 133.000 127.860 133.030 ;
        RECT 117.270 132.770 117.670 132.880 ;
        RECT 117.910 132.830 127.950 133.000 ;
        RECT 128.740 132.930 153.550 133.460 ;
        RECT 118.000 132.820 127.860 132.830 ;
        RECT 128.740 132.800 140.260 132.930 ;
        RECT 117.270 131.270 117.740 132.770 ;
        RECT 128.120 131.270 128.290 132.770 ;
        RECT 117.270 130.980 117.670 131.270 ;
        RECT 117.910 131.040 127.950 131.210 ;
        RECT 117.270 129.480 117.740 130.980 ;
        RECT 128.120 129.480 128.290 130.980 ;
        RECT 117.270 129.190 117.670 129.480 ;
        RECT 117.910 129.250 127.950 129.420 ;
        RECT 117.270 127.690 117.740 129.190 ;
        RECT 128.120 127.690 128.290 129.190 ;
        RECT 117.270 127.400 117.670 127.690 ;
        RECT 117.910 127.460 127.950 127.630 ;
        RECT 117.270 125.950 117.740 127.400 ;
        RECT 117.570 125.900 117.740 125.950 ;
        RECT 128.120 125.900 128.290 127.400 ;
        RECT 128.740 126.480 132.800 132.800 ;
        RECT 133.600 132.150 135.140 132.320 ;
        RECT 133.260 127.090 133.430 132.090 ;
        RECT 135.310 127.090 135.480 132.090 ;
        RECT 135.960 128.620 140.240 132.800 ;
        RECT 141.030 132.290 151.070 132.460 ;
        RECT 151.320 132.230 151.660 132.280 ;
        RECT 140.690 131.730 140.860 132.230 ;
        RECT 151.240 131.730 151.660 132.230 ;
        RECT 141.030 131.500 151.070 131.670 ;
        RECT 151.320 131.440 151.660 131.730 ;
        RECT 140.690 130.940 140.860 131.440 ;
        RECT 151.240 130.940 151.660 131.440 ;
        RECT 141.030 130.710 151.070 130.880 ;
        RECT 151.320 130.650 151.660 130.940 ;
        RECT 140.690 130.150 140.860 130.650 ;
        RECT 151.240 130.150 151.660 130.650 ;
        RECT 141.030 129.920 151.070 130.090 ;
        RECT 151.320 129.860 151.660 130.150 ;
        RECT 140.690 129.360 140.860 129.860 ;
        RECT 151.240 129.360 151.660 129.860 ;
        RECT 151.320 129.350 151.660 129.360 ;
        RECT 141.030 129.130 151.070 129.300 ;
        RECT 151.920 128.650 153.520 132.930 ;
        RECT 155.890 131.710 158.800 134.850 ;
        RECT 159.280 132.565 159.450 162.605 ;
        RECT 160.070 132.565 160.240 162.605 ;
        RECT 160.860 132.565 161.030 162.605 ;
        RECT 161.650 132.565 161.820 162.605 ;
        RECT 162.440 132.565 162.610 162.605 ;
        RECT 163.230 132.565 163.400 162.605 ;
        RECT 164.020 132.565 164.190 162.605 ;
        RECT 164.810 132.565 164.980 162.605 ;
        RECT 165.600 132.565 165.770 162.605 ;
        RECT 166.390 132.565 166.560 162.605 ;
        RECT 167.180 132.565 167.350 162.605 ;
        RECT 159.510 132.180 160.010 132.350 ;
        RECT 160.300 132.180 160.800 132.350 ;
        RECT 161.090 132.180 161.590 132.350 ;
        RECT 161.880 132.180 162.380 132.350 ;
        RECT 162.670 132.180 163.170 132.350 ;
        RECT 163.460 132.180 163.960 132.350 ;
        RECT 164.250 132.180 164.750 132.350 ;
        RECT 165.040 132.180 165.540 132.350 ;
        RECT 165.830 132.180 166.330 132.350 ;
        RECT 166.620 132.180 167.120 132.350 ;
        RECT 167.820 131.710 171.520 163.510 ;
        RECT 155.890 131.250 171.520 131.710 ;
        RECT 155.890 129.990 171.350 131.250 ;
        RECT 141.250 128.620 145.390 128.630 ;
        RECT 151.920 128.620 171.620 128.650 ;
        RECT 135.960 128.570 171.620 128.620 ;
        RECT 135.960 127.740 194.790 128.570 ;
        RECT 133.600 126.990 135.140 127.030 ;
        RECT 133.590 126.480 135.140 126.990 ;
        RECT 135.960 126.480 160.770 127.740 ;
        RECT 161.480 127.100 161.980 127.270 ;
        RECT 162.270 127.100 162.770 127.270 ;
        RECT 163.060 127.100 163.560 127.270 ;
        RECT 163.850 127.100 164.350 127.270 ;
        RECT 164.640 127.100 165.140 127.270 ;
        RECT 128.740 126.450 160.770 126.480 ;
        RECT 117.910 125.670 127.950 125.840 ;
        RECT 128.740 125.260 145.390 126.450 ;
        RECT 146.230 125.790 156.270 125.960 ;
        RECT 156.460 125.730 156.820 125.780 ;
        RECT 112.510 125.170 145.390 125.260 ;
        RECT 145.890 125.230 146.060 125.730 ;
        RECT 156.440 125.230 156.820 125.730 ;
        RECT 68.690 122.120 145.390 125.170 ;
        RECT 146.230 125.000 156.270 125.170 ;
        RECT 156.460 124.940 156.820 125.230 ;
        RECT 145.890 124.440 146.060 124.940 ;
        RECT 156.440 124.440 156.820 124.940 ;
        RECT 146.230 124.210 156.270 124.380 ;
        RECT 156.460 124.150 156.820 124.440 ;
        RECT 145.890 123.650 146.060 124.150 ;
        RECT 156.440 123.650 156.820 124.150 ;
        RECT 146.230 123.420 156.270 123.590 ;
        RECT 156.460 123.360 156.820 123.650 ;
        RECT 145.890 122.860 146.060 123.360 ;
        RECT 156.440 122.860 156.820 123.360 ;
        RECT 156.460 122.810 156.820 122.860 ;
        RECT 146.230 122.630 156.270 122.800 ;
        RECT 157.020 122.120 160.770 126.450 ;
        RECT 68.690 121.950 160.770 122.120 ;
        RECT 68.690 121.700 145.390 121.950 ;
        RECT 68.690 119.590 112.860 121.700 ;
        RECT 113.610 121.120 116.150 121.290 ;
        RECT 68.690 118.910 112.780 119.590 ;
        RECT 113.270 119.560 113.440 121.060 ;
        RECT 116.320 119.560 116.490 121.060 ;
        RECT 113.610 119.450 116.150 119.500 ;
        RECT 113.600 119.220 116.160 119.450 ;
        RECT 114.210 118.910 115.440 119.220 ;
        RECT 117.010 118.910 117.180 121.700 ;
        RECT 118.040 121.120 120.580 121.290 ;
        RECT 117.700 119.560 117.870 121.060 ;
        RECT 120.750 119.560 120.920 121.060 ;
        RECT 118.040 119.450 120.580 119.500 ;
        RECT 118.030 119.220 120.590 119.450 ;
        RECT 118.640 118.910 119.870 119.220 ;
        RECT 121.440 118.910 145.390 121.700 ;
        RECT 146.230 121.270 156.270 121.440 ;
        RECT 156.470 121.210 156.830 121.310 ;
        RECT 145.890 120.710 146.060 121.210 ;
        RECT 156.440 120.710 156.830 121.210 ;
        RECT 146.230 120.480 156.270 120.650 ;
        RECT 156.470 120.420 156.830 120.710 ;
        RECT 145.890 119.920 146.060 120.420 ;
        RECT 156.440 119.920 156.830 120.420 ;
        RECT 146.230 119.690 156.270 119.860 ;
        RECT 156.470 119.630 156.830 119.920 ;
        RECT 145.890 119.130 146.060 119.630 ;
        RECT 156.440 119.130 156.830 119.630 ;
        RECT 68.690 117.720 145.390 118.910 ;
        RECT 146.230 118.900 156.270 119.070 ;
        RECT 156.470 118.840 156.830 119.130 ;
        RECT 145.890 118.340 146.060 118.840 ;
        RECT 156.440 118.340 156.830 118.840 ;
        RECT 146.230 118.110 156.270 118.280 ;
        RECT 157.020 117.720 160.770 121.950 ;
        RECT 68.690 116.030 160.770 117.720 ;
        RECT 46.450 109.495 47.540 115.290 ;
        RECT 48.225 114.655 49.225 114.825 ;
        RECT 49.515 114.655 50.515 114.825 ;
        RECT 50.805 114.655 51.805 114.825 ;
        RECT 52.095 114.655 53.095 114.825 ;
        RECT 53.385 114.655 54.385 114.825 ;
        RECT 47.995 110.400 48.165 114.440 ;
        RECT 49.285 110.400 49.455 114.440 ;
        RECT 50.575 110.400 50.745 114.440 ;
        RECT 51.865 110.400 52.035 114.440 ;
        RECT 53.155 110.400 53.325 114.440 ;
        RECT 54.445 110.400 54.615 114.440 ;
        RECT 55.060 110.890 67.080 115.290 ;
        RECT 48.225 110.015 49.225 110.185 ;
        RECT 49.515 110.015 50.515 110.185 ;
        RECT 50.805 110.015 51.805 110.185 ;
        RECT 52.095 110.015 53.095 110.185 ;
        RECT 53.385 110.015 54.385 110.185 ;
        RECT 55.060 109.495 58.870 110.890 ;
        RECT 59.465 110.285 60.465 110.455 ;
        RECT 46.450 109.325 58.870 109.495 ;
        RECT 33.940 102.920 45.800 103.900 ;
        RECT 46.450 103.480 47.540 109.325 ;
        RECT 48.225 108.635 49.225 108.805 ;
        RECT 49.515 108.635 50.515 108.805 ;
        RECT 50.805 108.635 51.805 108.805 ;
        RECT 52.095 108.635 53.095 108.805 ;
        RECT 53.385 108.635 54.385 108.805 ;
        RECT 47.995 104.380 48.165 108.420 ;
        RECT 49.285 104.380 49.455 108.420 ;
        RECT 50.575 104.380 50.745 108.420 ;
        RECT 51.865 104.380 52.035 108.420 ;
        RECT 53.155 104.380 53.325 108.420 ;
        RECT 54.445 104.380 54.615 108.420 ;
        RECT 55.060 108.180 58.870 109.325 ;
        RECT 59.235 109.030 59.405 110.070 ;
        RECT 60.525 110.050 60.695 110.070 ;
        RECT 61.180 110.050 67.080 110.890 ;
        RECT 60.525 109.040 67.080 110.050 ;
        RECT 60.525 109.030 60.695 109.040 ;
        RECT 59.465 108.645 60.465 108.815 ;
        RECT 61.180 108.180 67.080 109.040 ;
        RECT 48.225 103.995 49.225 104.165 ;
        RECT 49.515 103.995 50.515 104.165 ;
        RECT 50.805 103.995 51.805 104.165 ;
        RECT 52.095 103.995 53.095 104.165 ;
        RECT 53.385 103.995 54.385 104.165 ;
        RECT 55.060 103.480 67.080 108.180 ;
        RECT 33.940 102.650 45.820 102.920 ;
        RECT 46.450 102.790 67.080 103.480 ;
        RECT 33.940 102.000 45.770 102.650 ;
        RECT 33.940 97.800 51.450 102.000 ;
        RECT 33.940 97.760 45.820 97.800 ;
        RECT 33.940 89.160 40.230 97.760 ;
        RECT 40.700 95.130 41.050 97.290 ;
        RECT 41.510 92.040 45.070 97.760 ;
        RECT 45.500 95.160 45.850 97.320 ;
        RECT 48.820 92.520 49.170 94.680 ;
        RECT 49.630 92.040 51.450 97.800 ;
        RECT 41.510 91.870 51.450 92.040 ;
        RECT 40.700 89.630 41.050 91.790 ;
        RECT 41.510 89.160 45.070 91.870 ;
        RECT 48.820 89.230 49.170 91.390 ;
        RECT 33.940 86.110 45.070 89.160 ;
        RECT 45.500 86.590 45.850 88.750 ;
        RECT 49.630 86.110 51.450 91.870 ;
        RECT 33.940 84.740 51.450 86.110 ;
        RECT 52.220 94.590 67.080 102.790 ;
        RECT 52.220 88.990 52.890 94.590 ;
        RECT 53.590 93.980 54.090 94.150 ;
        RECT 54.380 93.980 54.880 94.150 ;
        RECT 55.170 93.980 55.670 94.150 ;
        RECT 55.960 93.980 56.460 94.150 ;
        RECT 56.750 93.980 57.250 94.150 ;
        RECT 53.360 89.725 53.530 93.765 ;
        RECT 54.150 89.725 54.320 93.765 ;
        RECT 54.940 89.725 55.110 93.765 ;
        RECT 55.730 89.725 55.900 93.765 ;
        RECT 56.520 89.725 56.690 93.765 ;
        RECT 57.310 93.740 57.480 93.765 ;
        RECT 57.290 92.220 57.710 93.740 ;
        RECT 57.890 92.600 67.080 94.590 ;
        RECT 76.820 112.530 160.770 116.030 ;
        RECT 76.820 112.510 129.470 112.530 ;
        RECT 76.820 107.470 116.680 112.510 ;
        RECT 124.380 112.370 129.470 112.510 ;
        RECT 121.770 111.460 123.930 112.150 ;
        RECT 121.770 107.950 123.930 108.640 ;
        RECT 124.380 108.030 129.440 112.370 ;
        RECT 129.920 111.760 132.080 112.110 ;
        RECT 138.200 109.500 160.770 112.530 ;
        RECT 161.250 109.500 161.420 126.930 ;
        RECT 135.560 108.440 137.720 108.790 ;
        RECT 124.380 108.000 137.380 108.030 ;
        RECT 138.200 108.000 161.470 109.500 ;
        RECT 124.380 107.990 161.470 108.000 ;
        RECT 124.380 107.470 160.770 107.990 ;
        RECT 76.820 106.090 160.770 107.470 ;
        RECT 161.250 106.890 161.420 107.990 ;
        RECT 162.040 106.890 162.210 126.930 ;
        RECT 162.830 106.890 163.000 126.930 ;
        RECT 163.620 106.890 163.790 126.930 ;
        RECT 164.410 106.890 164.580 126.930 ;
        RECT 165.200 106.890 165.370 126.930 ;
        RECT 161.460 106.440 165.200 106.720 ;
        RECT 165.830 106.090 194.790 127.740 ;
        RECT 76.820 103.890 194.790 106.090 ;
        RECT 76.820 103.670 141.290 103.890 ;
        RECT 76.820 103.600 114.530 103.670 ;
        RECT 76.820 96.800 105.510 103.600 ;
        RECT 109.260 101.040 109.610 103.200 ;
        RECT 76.820 95.870 105.460 96.800 ;
        RECT 76.820 95.050 105.480 95.870 ;
        RECT 105.940 95.400 106.290 97.560 ;
        RECT 110.080 96.560 114.530 103.600 ;
        RECT 114.920 101.110 115.610 103.270 ;
        RECT 118.430 101.110 119.120 103.270 ;
        RECT 110.030 96.010 114.530 96.560 ;
        RECT 119.520 96.010 141.290 103.670 ;
        RECT 155.090 103.400 194.790 103.890 ;
        RECT 110.030 95.890 141.290 96.010 ;
        RECT 110.090 95.050 141.290 95.890 ;
        RECT 76.820 94.470 141.290 95.050 ;
        RECT 76.820 94.380 97.100 94.470 ;
        RECT 57.890 92.220 174.740 92.600 ;
        RECT 57.290 91.150 174.740 92.220 ;
        RECT 57.290 89.750 57.710 91.150 ;
        RECT 57.890 90.650 174.740 91.150 ;
        RECT 57.310 89.725 57.480 89.750 ;
        RECT 53.590 89.340 54.090 89.510 ;
        RECT 54.380 89.340 54.880 89.510 ;
        RECT 55.170 89.340 55.670 89.510 ;
        RECT 55.960 89.340 56.460 89.510 ;
        RECT 56.750 89.340 57.250 89.510 ;
        RECT 57.890 88.990 174.830 90.650 ;
        RECT 52.220 88.850 174.830 88.990 ;
        RECT 52.220 88.660 138.900 88.850 ;
        RECT 52.220 87.320 117.160 88.660 ;
        RECT 118.065 88.080 123.105 88.250 ;
        RECT 52.220 85.970 104.130 87.320 ;
        RECT 105.005 86.730 112.545 86.900 ;
        RECT 104.620 86.650 104.790 86.670 ;
        RECT 52.220 85.390 91.710 85.970 ;
        RECT 95.480 85.530 97.330 85.970 ;
        RECT 52.220 85.320 67.080 85.390 ;
        RECT 33.940 84.660 51.900 84.740 ;
        RECT 33.940 84.430 69.740 84.660 ;
        RECT 25.000 80.860 69.740 84.430 ;
        RECT 25.000 76.180 28.215 80.860 ;
        RECT 28.535 80.845 69.740 80.860 ;
        RECT 28.535 76.755 28.895 80.845 ;
        RECT 29.205 77.065 32.675 80.535 ;
        RECT 32.880 76.890 37.370 80.845 ;
        RECT 41.425 80.840 69.740 80.845 ;
        RECT 37.645 77.065 41.115 80.535 ;
        RECT 41.425 76.890 45.820 80.840 ;
        RECT 46.085 77.065 49.555 80.535 ;
        RECT 49.865 76.890 54.230 80.840 ;
        RECT 54.525 77.065 57.995 80.535 ;
        RECT 58.305 76.890 62.720 80.840 ;
        RECT 62.965 77.065 66.435 80.535 ;
        RECT 66.745 76.890 69.740 80.840 ;
        RECT 32.880 76.755 69.740 76.890 ;
        RECT 28.535 76.395 69.740 76.755 ;
        RECT 32.880 76.180 69.740 76.395 ;
        RECT 25.000 72.410 69.740 76.180 ;
        RECT 25.000 68.310 28.215 72.410 ;
        RECT 28.535 72.405 69.740 72.410 ;
        RECT 28.535 68.315 28.895 72.405 ;
        RECT 29.205 68.625 32.675 72.095 ;
        RECT 32.880 68.315 37.370 72.405 ;
        RECT 37.645 68.625 41.115 72.095 ;
        RECT 41.425 68.315 45.820 72.405 ;
        RECT 46.085 68.625 49.555 72.095 ;
        RECT 49.865 68.315 54.230 72.405 ;
        RECT 54.525 68.625 57.995 72.095 ;
        RECT 58.305 68.315 62.720 72.405 ;
        RECT 62.965 68.625 66.435 72.095 ;
        RECT 66.745 68.315 69.740 72.405 ;
        RECT 28.535 68.310 69.740 68.315 ;
        RECT 25.000 67.955 69.740 68.310 ;
        RECT 25.000 67.700 62.720 67.955 ;
        RECT 66.770 67.700 69.740 67.955 ;
        RECT 25.000 63.920 69.740 67.700 ;
        RECT 25.000 59.860 28.215 63.920 ;
        RECT 28.535 59.875 28.895 63.920 ;
        RECT 29.205 60.185 32.675 63.655 ;
        RECT 32.880 59.875 37.370 63.920 ;
        RECT 37.645 60.185 41.115 63.655 ;
        RECT 41.425 59.875 45.820 63.920 ;
        RECT 46.085 60.185 49.555 63.655 ;
        RECT 49.865 59.875 54.230 63.920 ;
        RECT 54.525 60.185 57.995 63.655 ;
        RECT 58.305 59.875 62.720 63.920 ;
        RECT 62.965 60.185 66.435 63.655 ;
        RECT 66.745 59.875 69.740 63.920 ;
        RECT 83.490 82.610 91.710 85.390 ;
        RECT 92.535 85.360 100.075 85.530 ;
        RECT 95.480 85.340 97.330 85.360 ;
        RECT 92.150 83.300 92.320 85.300 ;
        RECT 100.290 83.300 100.460 85.300 ;
        RECT 92.535 83.070 100.075 83.240 ;
        RECT 100.910 82.610 104.110 85.970 ;
        RECT 104.390 84.670 104.790 86.650 ;
        RECT 112.760 84.670 112.930 86.670 ;
        RECT 104.390 84.380 104.760 84.670 ;
        RECT 105.005 84.440 112.545 84.610 ;
        RECT 83.490 81.660 104.130 82.610 ;
        RECT 104.390 82.400 104.790 84.380 ;
        RECT 104.620 82.380 104.790 82.400 ;
        RECT 112.760 82.380 112.930 84.380 ;
        RECT 113.440 82.490 117.160 87.320 ;
        RECT 117.680 87.020 117.850 88.020 ;
        RECT 123.320 87.950 123.490 88.020 ;
        RECT 123.320 87.020 123.690 87.950 ;
        RECT 118.065 86.790 123.105 86.960 ;
        RECT 123.330 86.730 123.690 87.020 ;
        RECT 117.680 85.730 117.850 86.730 ;
        RECT 123.320 85.730 123.690 86.730 ;
        RECT 118.065 85.500 123.105 85.670 ;
        RECT 123.330 85.440 123.690 85.730 ;
        RECT 117.680 84.440 117.850 85.440 ;
        RECT 123.320 84.440 123.690 85.440 ;
        RECT 118.065 84.210 123.105 84.380 ;
        RECT 123.330 84.150 123.690 84.440 ;
        RECT 117.680 83.150 117.850 84.150 ;
        RECT 123.320 83.210 123.690 84.150 ;
        RECT 123.320 83.150 123.490 83.210 ;
        RECT 118.065 82.920 123.105 83.090 ;
        RECT 124.010 82.490 124.180 88.660 ;
        RECT 125.085 88.080 130.125 88.250 ;
        RECT 124.700 87.970 124.870 88.020 ;
        RECT 124.440 87.020 124.870 87.970 ;
        RECT 130.340 87.020 130.510 88.020 ;
        RECT 124.440 86.730 124.800 87.020 ;
        RECT 125.085 86.790 130.125 86.960 ;
        RECT 124.440 85.730 124.870 86.730 ;
        RECT 130.340 85.730 130.510 86.730 ;
        RECT 124.440 85.440 124.800 85.730 ;
        RECT 125.085 85.500 130.125 85.670 ;
        RECT 124.440 84.440 124.870 85.440 ;
        RECT 130.340 84.440 130.510 85.440 ;
        RECT 124.440 84.150 124.800 84.440 ;
        RECT 125.085 84.210 130.125 84.380 ;
        RECT 124.440 83.230 124.870 84.150 ;
        RECT 124.700 83.150 124.870 83.230 ;
        RECT 130.340 83.150 130.510 84.150 ;
        RECT 125.085 82.920 130.125 83.090 ;
        RECT 130.960 82.490 138.900 88.660 ;
        RECT 142.920 88.425 152.520 88.850 ;
        RECT 155.540 88.770 174.830 88.850 ;
        RECT 139.170 82.910 139.450 88.390 ;
        RECT 139.660 88.255 154.700 88.425 ;
        RECT 142.920 88.220 152.520 88.255 ;
        RECT 154.915 87.695 155.085 88.195 ;
        RECT 139.660 87.465 154.700 87.635 ;
        RECT 154.915 86.905 155.085 87.405 ;
        RECT 139.660 86.675 154.700 86.845 ;
        RECT 154.915 86.115 155.085 86.615 ;
        RECT 139.660 85.885 154.700 86.055 ;
        RECT 154.915 85.325 155.085 85.825 ;
        RECT 139.660 85.095 154.700 85.265 ;
        RECT 154.915 84.535 155.085 85.035 ;
        RECT 139.660 84.305 154.700 84.475 ;
        RECT 154.915 83.745 155.085 84.245 ;
        RECT 139.660 83.515 154.700 83.685 ;
        RECT 154.915 82.955 155.085 83.455 ;
        RECT 139.660 82.725 154.700 82.895 ;
        RECT 105.005 82.150 112.545 82.320 ;
        RECT 113.440 82.225 138.900 82.490 ;
        RECT 155.540 82.225 162.160 88.770 ;
        RECT 162.810 88.110 170.450 88.480 ;
        RECT 162.820 88.080 163.320 88.110 ;
        RECT 163.610 88.080 164.110 88.110 ;
        RECT 164.400 88.080 164.900 88.110 ;
        RECT 165.190 88.080 165.690 88.110 ;
        RECT 165.980 88.080 166.480 88.110 ;
        RECT 166.770 88.080 167.270 88.110 ;
        RECT 167.560 88.080 168.060 88.110 ;
        RECT 168.350 88.080 168.850 88.110 ;
        RECT 169.140 88.080 169.640 88.110 ;
        RECT 169.930 88.080 170.430 88.110 ;
        RECT 113.440 82.055 162.160 82.225 ;
        RECT 113.440 81.660 138.900 82.055 ;
        RECT 83.490 79.490 138.900 81.660 ;
        RECT 83.490 78.840 117.160 79.490 ;
        RECT 118.035 78.885 123.075 79.055 ;
        RECT 83.490 75.140 90.310 78.840 ;
        RECT 91.115 78.220 101.155 78.390 ;
        RECT 101.460 78.160 101.710 78.190 ;
        RECT 90.730 77.160 90.900 78.160 ;
        RECT 101.370 77.160 101.710 78.160 ;
        RECT 91.115 76.930 101.155 77.100 ;
        RECT 101.460 76.870 101.710 77.160 ;
        RECT 90.730 75.870 90.900 76.870 ;
        RECT 101.370 75.890 101.710 76.870 ;
        RECT 101.370 75.870 101.540 75.890 ;
        RECT 91.115 75.640 101.155 75.810 ;
        RECT 102.060 75.210 102.230 78.840 ;
        RECT 103.135 78.220 113.175 78.390 ;
        RECT 102.490 78.160 102.880 78.210 ;
        RECT 113.480 78.160 113.730 78.190 ;
        RECT 102.490 77.160 102.920 78.160 ;
        RECT 113.390 77.160 113.730 78.160 ;
        RECT 102.490 76.870 102.880 77.160 ;
        RECT 103.135 76.930 113.175 77.100 ;
        RECT 113.480 76.870 113.730 77.160 ;
        RECT 102.490 75.870 102.920 76.870 ;
        RECT 113.390 75.890 113.730 76.870 ;
        RECT 113.390 75.870 113.560 75.890 ;
        RECT 102.490 75.820 102.880 75.870 ;
        RECT 103.135 75.640 113.175 75.810 ;
        RECT 114.050 75.225 117.160 78.840 ;
        RECT 123.330 78.825 123.550 78.910 ;
        RECT 117.650 78.325 117.820 78.825 ;
        RECT 123.290 78.325 123.550 78.825 ;
        RECT 118.035 78.095 123.075 78.265 ;
        RECT 123.330 78.035 123.550 78.325 ;
        RECT 117.650 77.535 117.820 78.035 ;
        RECT 123.290 77.535 123.550 78.035 ;
        RECT 118.035 77.305 123.075 77.475 ;
        RECT 123.330 77.245 123.550 77.535 ;
        RECT 117.650 76.745 117.820 77.245 ;
        RECT 123.290 76.745 123.550 77.245 ;
        RECT 118.035 76.515 123.075 76.685 ;
        RECT 123.330 76.455 123.550 76.745 ;
        RECT 117.650 75.955 117.820 76.455 ;
        RECT 123.290 75.955 123.550 76.455 ;
        RECT 123.330 75.930 123.550 75.955 ;
        RECT 118.035 75.725 123.075 75.895 ;
        RECT 123.980 75.230 124.150 79.490 ;
        RECT 124.560 78.825 124.780 78.960 ;
        RECT 125.055 78.885 130.095 79.055 ;
        RECT 124.560 78.325 124.840 78.825 ;
        RECT 130.310 78.325 130.480 78.825 ;
        RECT 124.560 78.035 124.780 78.325 ;
        RECT 125.055 78.095 130.095 78.265 ;
        RECT 124.560 77.535 124.840 78.035 ;
        RECT 130.310 77.535 130.480 78.035 ;
        RECT 124.560 77.245 124.780 77.535 ;
        RECT 125.055 77.305 130.095 77.475 ;
        RECT 124.560 76.745 124.840 77.245 ;
        RECT 130.310 76.745 130.480 77.245 ;
        RECT 124.560 76.455 124.780 76.745 ;
        RECT 125.055 76.515 130.095 76.685 ;
        RECT 124.560 75.980 124.840 76.455 ;
        RECT 124.670 75.955 124.840 75.980 ;
        RECT 130.310 75.955 130.480 76.455 ;
        RECT 125.055 75.725 130.095 75.895 ;
        RECT 130.960 75.380 138.900 79.490 ;
        RECT 139.140 81.325 139.420 81.530 ;
        RECT 139.660 81.385 154.700 81.555 ;
        RECT 139.140 80.825 139.445 81.325 ;
        RECT 154.915 80.825 155.085 81.325 ;
        RECT 139.140 80.535 139.420 80.825 ;
        RECT 139.660 80.595 154.700 80.765 ;
        RECT 139.140 80.035 139.445 80.535 ;
        RECT 154.915 80.035 155.085 80.535 ;
        RECT 139.140 79.745 139.420 80.035 ;
        RECT 139.660 79.805 154.700 79.975 ;
        RECT 139.140 79.245 139.445 79.745 ;
        RECT 154.915 79.245 155.085 79.745 ;
        RECT 139.140 78.955 139.420 79.245 ;
        RECT 139.660 79.015 154.700 79.185 ;
        RECT 139.140 78.455 139.445 78.955 ;
        RECT 154.915 78.455 155.085 78.955 ;
        RECT 139.140 78.165 139.420 78.455 ;
        RECT 139.660 78.225 154.700 78.395 ;
        RECT 139.140 77.665 139.445 78.165 ;
        RECT 154.915 77.665 155.085 78.165 ;
        RECT 139.140 77.375 139.420 77.665 ;
        RECT 139.660 77.435 154.700 77.605 ;
        RECT 139.140 76.875 139.445 77.375 ;
        RECT 154.915 76.875 155.085 77.375 ;
        RECT 139.140 76.585 139.420 76.875 ;
        RECT 139.660 76.645 154.700 76.815 ;
        RECT 139.140 76.085 139.445 76.585 ;
        RECT 154.915 76.085 155.085 76.585 ;
        RECT 139.140 76.050 139.420 76.085 ;
        RECT 139.660 75.855 154.700 76.025 ;
        RECT 155.540 75.400 162.160 82.055 ;
        RECT 151.660 75.380 162.160 75.400 ;
        RECT 130.960 75.270 162.160 75.380 ;
        RECT 129.710 75.230 162.160 75.270 ;
        RECT 120.500 75.225 162.160 75.230 ;
        RECT 114.050 75.210 162.160 75.225 ;
        RECT 100.780 75.160 162.160 75.210 ;
        RECT 90.560 75.140 162.160 75.160 ;
        RECT 83.490 74.550 162.160 75.140 ;
        RECT 83.490 70.800 119.660 74.550 ;
        RECT 120.250 73.970 130.380 74.340 ;
        RECT 120.250 71.890 120.840 73.970 ;
        RECT 126.230 73.150 128.390 73.500 ;
        RECT 126.230 72.320 128.390 72.670 ;
        RECT 128.850 71.890 130.380 73.970 ;
        RECT 120.250 71.410 130.380 71.890 ;
        RECT 120.260 71.240 130.380 71.410 ;
        RECT 126.280 71.190 130.380 71.240 ;
        RECT 130.680 72.270 162.160 74.550 ;
        RECT 83.490 69.760 126.020 70.800 ;
        RECT 83.490 69.740 120.840 69.760 ;
        RECT 83.490 67.040 101.560 69.740 ;
        RECT 102.365 69.120 112.405 69.290 ;
        RECT 83.490 64.730 91.150 67.040 ;
        RECT 92.060 66.610 93.070 67.040 ;
        RECT 92.045 66.440 93.085 66.610 ;
        RECT 91.660 65.380 91.830 66.380 ;
        RECT 93.300 65.380 93.470 66.380 ;
        RECT 92.045 65.150 93.085 65.320 ;
        RECT 93.990 64.730 94.160 67.040 ;
        RECT 95.080 66.610 96.090 67.040 ;
        RECT 95.065 66.440 96.105 66.610 ;
        RECT 94.680 65.380 94.850 66.380 ;
        RECT 96.320 65.380 96.490 66.380 ;
        RECT 96.990 65.610 101.560 67.040 ;
        RECT 95.065 65.150 96.105 65.320 ;
        RECT 96.990 65.020 101.550 65.610 ;
        RECT 96.990 64.730 101.560 65.020 ;
        RECT 83.490 64.310 101.560 64.730 ;
        RECT 83.490 60.910 101.540 64.310 ;
        RECT 101.740 61.570 102.150 69.100 ;
        RECT 112.620 68.060 112.790 69.060 ;
        RECT 102.365 67.830 112.405 68.000 ;
        RECT 112.620 66.770 112.790 67.770 ;
        RECT 102.365 66.540 112.405 66.710 ;
        RECT 112.620 65.480 112.790 66.480 ;
        RECT 102.365 65.250 112.405 65.420 ;
        RECT 112.620 64.190 112.790 65.190 ;
        RECT 102.365 63.960 112.405 64.130 ;
        RECT 112.620 62.900 112.790 63.900 ;
        RECT 102.365 62.670 112.405 62.840 ;
        RECT 112.620 61.610 112.790 62.610 ;
        RECT 102.365 61.380 112.405 61.550 ;
        RECT 113.310 60.910 113.480 69.740 ;
        RECT 113.740 69.720 120.840 69.740 ;
        RECT 114.385 69.120 124.425 69.290 ;
        RECT 124.700 69.060 124.990 69.080 ;
        RECT 114.000 68.060 114.170 69.060 ;
        RECT 124.640 68.060 124.990 69.060 ;
        RECT 114.385 67.830 124.425 68.000 ;
        RECT 124.700 67.770 124.990 68.060 ;
        RECT 114.000 66.770 114.170 67.770 ;
        RECT 124.640 66.770 124.990 67.770 ;
        RECT 114.385 66.540 124.425 66.710 ;
        RECT 124.700 66.480 124.990 66.770 ;
        RECT 114.000 65.480 114.170 66.480 ;
        RECT 124.640 65.480 124.990 66.480 ;
        RECT 114.385 65.250 124.425 65.420 ;
        RECT 124.700 65.190 124.990 65.480 ;
        RECT 114.000 64.190 114.170 65.190 ;
        RECT 124.640 64.190 124.990 65.190 ;
        RECT 114.385 63.960 124.425 64.130 ;
        RECT 124.700 63.900 124.990 64.190 ;
        RECT 114.000 62.900 114.170 63.900 ;
        RECT 124.640 62.900 124.990 63.900 ;
        RECT 114.385 62.670 124.425 62.840 ;
        RECT 124.700 62.610 124.990 62.900 ;
        RECT 114.000 61.610 114.170 62.610 ;
        RECT 124.640 61.630 124.990 62.610 ;
        RECT 124.640 61.610 124.810 61.630 ;
        RECT 114.385 61.380 124.425 61.550 ;
        RECT 125.310 60.910 126.020 69.760 ;
        RECT 83.490 60.130 126.020 60.910 ;
        RECT 28.535 59.860 69.740 59.875 ;
        RECT 25.000 59.515 69.740 59.860 ;
        RECT 25.000 59.270 62.720 59.515 ;
        RECT 66.770 59.380 69.740 59.515 ;
        RECT 66.770 59.310 79.060 59.380 ;
        RECT 66.770 59.270 84.080 59.310 ;
        RECT 126.280 59.270 130.370 71.190 ;
        RECT 130.680 70.640 152.060 72.270 ;
        RECT 153.910 71.870 156.190 72.270 ;
        RECT 152.915 71.700 156.955 71.870 ;
        RECT 153.910 71.690 156.190 71.700 ;
        RECT 130.710 69.960 152.060 70.640 ;
        RECT 130.710 69.870 138.900 69.960 ;
        RECT 130.710 62.490 131.500 69.870 ;
        RECT 132.405 69.310 147.445 69.480 ;
        RECT 132.020 68.750 132.190 69.250 ;
        RECT 147.660 69.190 147.830 69.250 ;
        RECT 132.405 68.520 147.445 68.690 ;
        RECT 132.020 67.960 132.190 68.460 ;
        RECT 132.405 67.730 147.445 67.900 ;
        RECT 132.020 67.170 132.190 67.670 ;
        RECT 132.405 66.940 147.445 67.110 ;
        RECT 132.020 66.380 132.190 66.880 ;
        RECT 132.405 66.150 147.445 66.320 ;
        RECT 132.020 65.590 132.190 66.090 ;
        RECT 132.405 65.360 147.445 65.530 ;
        RECT 132.020 64.800 132.190 65.300 ;
        RECT 132.405 64.570 147.445 64.740 ;
        RECT 132.020 64.010 132.190 64.510 ;
        RECT 132.405 63.780 147.445 63.950 ;
        RECT 132.020 63.220 132.190 63.720 ;
        RECT 147.640 63.230 147.990 69.190 ;
        RECT 148.350 65.970 152.060 69.960 ;
        RECT 152.530 66.640 152.700 71.640 ;
        RECT 157.170 66.640 157.340 71.640 ;
        RECT 152.915 66.410 156.955 66.580 ;
        RECT 157.850 65.970 162.160 72.270 ;
        RECT 148.350 65.590 162.160 65.970 ;
        RECT 147.660 63.220 147.830 63.230 ;
        RECT 132.405 62.990 147.445 63.160 ;
        RECT 148.350 63.110 162.110 65.590 ;
        RECT 148.350 62.490 162.150 63.110 ;
        RECT 130.710 60.140 162.150 62.490 ;
        RECT 130.710 60.110 156.320 60.140 ;
        RECT 159.200 60.110 162.150 60.140 ;
        RECT 25.000 59.250 84.930 59.270 ;
        RECT 107.950 59.250 136.150 59.270 ;
        RECT 25.000 58.980 136.150 59.250 ;
        RECT 25.000 58.720 156.860 58.980 ;
        RECT 25.000 58.700 108.550 58.720 ;
        RECT 25.000 55.510 84.930 58.700 ;
        RECT 88.550 58.630 108.460 58.700 ;
        RECT 85.680 58.090 87.720 58.260 ;
        RECT 25.000 51.450 28.215 55.510 ;
        RECT 28.535 51.450 28.895 55.510 ;
        RECT 29.205 51.745 32.675 55.215 ;
        RECT 32.880 51.450 37.370 55.510 ;
        RECT 37.645 51.745 41.115 55.215 ;
        RECT 41.425 51.450 45.820 55.510 ;
        RECT 46.085 51.745 49.555 55.215 ;
        RECT 49.865 51.450 54.230 55.510 ;
        RECT 54.525 51.745 57.995 55.215 ;
        RECT 58.305 51.450 62.720 55.510 ;
        RECT 62.965 51.745 66.435 55.215 ;
        RECT 66.745 52.290 84.930 55.510 ;
        RECT 85.340 53.030 85.510 58.030 ;
        RECT 87.890 53.030 88.060 58.030 ;
        RECT 88.550 56.650 90.820 58.630 ;
        RECT 91.600 57.950 96.640 58.120 ;
        RECT 91.260 57.390 91.430 57.890 ;
        RECT 96.810 57.390 96.980 57.890 ;
        RECT 91.600 57.160 96.640 57.330 ;
        RECT 97.500 56.680 97.670 58.630 ;
        RECT 98.530 57.950 103.570 58.120 ;
        RECT 98.190 57.390 98.360 57.890 ;
        RECT 103.740 57.390 103.910 57.890 ;
        RECT 98.530 57.160 103.570 57.330 ;
        RECT 104.400 56.680 108.460 58.630 ;
        RECT 109.430 58.260 119.290 58.320 ;
        RECT 109.290 58.090 119.330 58.260 ;
        RECT 119.510 58.030 119.910 58.140 ;
        RECT 94.010 56.650 108.500 56.680 ;
        RECT 88.550 54.710 108.500 56.650 ;
        RECT 108.950 56.530 109.120 58.030 ;
        RECT 119.500 56.530 119.910 58.030 ;
        RECT 109.290 56.300 119.330 56.470 ;
        RECT 119.510 56.240 119.910 56.530 ;
        RECT 108.950 54.740 109.120 56.240 ;
        RECT 119.500 54.740 119.910 56.240 ;
        RECT 85.680 52.900 87.720 52.970 ;
        RECT 85.670 52.800 87.720 52.900 ;
        RECT 85.670 52.290 87.690 52.800 ;
        RECT 88.550 52.290 94.220 54.710 ;
        RECT 95.060 54.050 96.600 54.220 ;
        RECT 94.720 52.490 94.890 53.990 ;
        RECT 96.770 52.490 96.940 53.990 ;
        RECT 95.060 52.410 96.600 52.430 ;
        RECT 66.745 51.850 94.220 52.290 ;
        RECT 95.050 52.140 96.620 52.410 ;
        RECT 95.230 51.850 96.400 52.140 ;
        RECT 97.460 51.850 97.630 54.710 ;
        RECT 98.490 54.050 100.030 54.220 ;
        RECT 98.150 52.490 98.320 53.990 ;
        RECT 100.200 52.490 100.370 53.990 ;
        RECT 98.490 52.410 100.030 52.430 ;
        RECT 98.480 52.140 100.050 52.410 ;
        RECT 98.660 51.850 99.830 52.140 ;
        RECT 100.820 51.850 108.490 54.710 ;
        RECT 109.290 54.510 119.330 54.680 ;
        RECT 119.510 54.450 119.910 54.740 ;
        RECT 108.950 52.950 109.120 54.450 ;
        RECT 119.500 52.950 119.910 54.450 ;
        RECT 109.290 52.720 119.330 52.890 ;
        RECT 119.510 52.660 119.910 52.950 ;
        RECT 25.000 51.435 62.720 51.450 ;
        RECT 66.745 51.435 108.490 51.850 ;
        RECT 25.000 51.075 108.490 51.435 ;
        RECT 108.950 51.160 109.120 52.660 ;
        RECT 119.500 51.210 119.910 52.660 ;
        RECT 119.500 51.160 119.670 51.210 ;
        RECT 25.000 50.790 62.720 51.075 ;
        RECT 66.770 50.790 108.490 51.075 ;
        RECT 109.290 50.930 119.330 51.100 ;
        RECT 25.000 50.430 108.490 50.790 ;
        RECT 120.190 50.520 120.360 58.720 ;
        RECT 121.310 58.260 131.170 58.290 ;
        RECT 120.580 58.030 120.980 58.140 ;
        RECT 121.220 58.090 131.260 58.260 ;
        RECT 132.050 58.190 156.860 58.720 ;
        RECT 121.310 58.080 131.170 58.090 ;
        RECT 132.050 58.060 143.570 58.190 ;
        RECT 120.580 56.530 121.050 58.030 ;
        RECT 131.430 56.530 131.600 58.030 ;
        RECT 120.580 56.240 120.980 56.530 ;
        RECT 121.220 56.300 131.260 56.470 ;
        RECT 120.580 54.740 121.050 56.240 ;
        RECT 131.430 54.740 131.600 56.240 ;
        RECT 120.580 54.450 120.980 54.740 ;
        RECT 121.220 54.510 131.260 54.680 ;
        RECT 120.580 52.950 121.050 54.450 ;
        RECT 131.430 52.950 131.600 54.450 ;
        RECT 120.580 52.660 120.980 52.950 ;
        RECT 121.220 52.720 131.260 52.890 ;
        RECT 120.580 51.210 121.050 52.660 ;
        RECT 120.880 51.160 121.050 51.210 ;
        RECT 131.430 51.160 131.600 52.660 ;
        RECT 132.050 51.740 136.110 58.060 ;
        RECT 136.910 57.410 138.450 57.580 ;
        RECT 136.570 52.350 136.740 57.350 ;
        RECT 138.620 52.350 138.790 57.350 ;
        RECT 139.270 53.880 143.550 58.060 ;
        RECT 144.340 57.550 154.380 57.720 ;
        RECT 154.630 57.490 154.970 57.540 ;
        RECT 144.000 56.990 144.170 57.490 ;
        RECT 154.550 56.990 154.970 57.490 ;
        RECT 144.340 56.760 154.380 56.930 ;
        RECT 154.630 56.700 154.970 56.990 ;
        RECT 144.000 56.200 144.170 56.700 ;
        RECT 154.550 56.200 154.970 56.700 ;
        RECT 144.340 55.970 154.380 56.140 ;
        RECT 154.630 55.910 154.970 56.200 ;
        RECT 144.000 55.410 144.170 55.910 ;
        RECT 154.550 55.410 154.970 55.910 ;
        RECT 144.340 55.180 154.380 55.350 ;
        RECT 154.630 55.120 154.970 55.410 ;
        RECT 144.000 54.620 144.170 55.120 ;
        RECT 154.550 54.620 154.970 55.120 ;
        RECT 154.630 54.610 154.970 54.620 ;
        RECT 144.340 54.390 154.380 54.560 ;
        RECT 155.230 53.910 156.830 58.190 ;
        RECT 159.200 56.970 162.110 60.110 ;
        RECT 162.590 57.825 162.760 87.865 ;
        RECT 163.380 57.825 163.550 87.865 ;
        RECT 164.170 57.825 164.340 87.865 ;
        RECT 164.960 57.825 165.130 87.865 ;
        RECT 165.750 57.825 165.920 87.865 ;
        RECT 166.540 57.825 166.710 87.865 ;
        RECT 167.330 57.825 167.500 87.865 ;
        RECT 168.120 57.825 168.290 87.865 ;
        RECT 168.910 57.825 169.080 87.865 ;
        RECT 169.700 57.825 169.870 87.865 ;
        RECT 170.490 57.825 170.660 87.865 ;
        RECT 162.820 57.440 163.320 57.610 ;
        RECT 163.610 57.440 164.110 57.610 ;
        RECT 164.400 57.440 164.900 57.610 ;
        RECT 165.190 57.440 165.690 57.610 ;
        RECT 165.980 57.440 166.480 57.610 ;
        RECT 166.770 57.440 167.270 57.610 ;
        RECT 167.560 57.440 168.060 57.610 ;
        RECT 168.350 57.440 168.850 57.610 ;
        RECT 169.140 57.440 169.640 57.610 ;
        RECT 169.930 57.440 170.430 57.610 ;
        RECT 171.130 56.970 174.830 88.770 ;
        RECT 159.200 56.510 174.830 56.970 ;
        RECT 159.200 55.250 174.660 56.510 ;
        RECT 175.890 54.140 194.790 103.400 ;
        RECT 172.590 53.910 194.790 54.140 ;
        RECT 144.560 53.880 148.700 53.890 ;
        RECT 155.230 53.880 194.790 53.910 ;
        RECT 139.270 53.000 194.790 53.880 ;
        RECT 136.910 52.250 138.450 52.290 ;
        RECT 136.900 51.740 138.450 52.250 ;
        RECT 139.270 51.740 164.080 53.000 ;
        RECT 164.790 52.360 165.290 52.530 ;
        RECT 165.580 52.360 166.080 52.530 ;
        RECT 166.370 52.360 166.870 52.530 ;
        RECT 167.160 52.360 167.660 52.530 ;
        RECT 167.950 52.360 168.450 52.530 ;
        RECT 169.140 52.440 194.790 53.000 ;
        RECT 132.050 51.710 164.080 51.740 ;
        RECT 121.220 50.930 131.260 51.100 ;
        RECT 132.050 50.520 148.700 51.710 ;
        RECT 149.540 51.050 159.580 51.220 ;
        RECT 159.770 50.990 160.130 51.040 ;
        RECT 115.820 50.430 148.700 50.520 ;
        RECT 149.200 50.490 149.370 50.990 ;
        RECT 159.750 50.490 160.130 50.990 ;
        RECT 25.000 47.380 148.700 50.430 ;
        RECT 149.540 50.260 159.580 50.430 ;
        RECT 159.770 50.200 160.130 50.490 ;
        RECT 149.200 49.700 149.370 50.200 ;
        RECT 159.750 49.700 160.130 50.200 ;
        RECT 149.540 49.470 159.580 49.640 ;
        RECT 159.770 49.410 160.130 49.700 ;
        RECT 149.200 48.910 149.370 49.410 ;
        RECT 159.750 48.910 160.130 49.410 ;
        RECT 149.540 48.680 159.580 48.850 ;
        RECT 159.770 48.620 160.130 48.910 ;
        RECT 149.200 48.120 149.370 48.620 ;
        RECT 159.750 48.120 160.130 48.620 ;
        RECT 159.770 48.070 160.130 48.120 ;
        RECT 149.540 47.890 159.580 48.060 ;
        RECT 160.330 47.380 164.080 51.710 ;
        RECT 25.000 47.210 164.080 47.380 ;
        RECT 25.000 47.060 148.700 47.210 ;
        RECT 25.000 43.040 28.215 47.060 ;
        RECT 28.535 43.040 28.895 47.060 ;
        RECT 29.205 43.305 32.675 46.775 ;
        RECT 32.880 43.040 37.370 47.060 ;
        RECT 37.645 43.305 41.115 46.775 ;
        RECT 41.425 43.040 45.820 47.060 ;
        RECT 46.085 43.305 49.555 46.775 ;
        RECT 49.865 43.040 54.230 47.060 ;
        RECT 54.525 43.305 57.995 46.775 ;
        RECT 58.305 43.040 62.720 47.060 ;
        RECT 66.745 46.960 148.700 47.060 ;
        RECT 62.965 43.305 66.435 46.775 ;
        RECT 66.745 44.850 116.170 46.960 ;
        RECT 116.920 46.380 119.460 46.550 ;
        RECT 66.745 44.170 116.090 44.850 ;
        RECT 116.580 44.820 116.750 46.320 ;
        RECT 119.630 44.820 119.800 46.320 ;
        RECT 116.920 44.710 119.460 44.760 ;
        RECT 116.910 44.480 119.470 44.710 ;
        RECT 117.520 44.170 118.750 44.480 ;
        RECT 120.320 44.170 120.490 46.960 ;
        RECT 121.350 46.380 123.890 46.550 ;
        RECT 121.010 44.820 121.180 46.320 ;
        RECT 124.060 44.820 124.230 46.320 ;
        RECT 121.350 44.710 123.890 44.760 ;
        RECT 121.340 44.480 123.900 44.710 ;
        RECT 121.950 44.170 123.180 44.480 ;
        RECT 124.750 44.170 148.700 46.960 ;
        RECT 149.540 46.530 159.580 46.700 ;
        RECT 159.780 46.470 160.140 46.570 ;
        RECT 149.200 45.970 149.370 46.470 ;
        RECT 159.750 45.970 160.140 46.470 ;
        RECT 149.540 45.740 159.580 45.910 ;
        RECT 159.780 45.680 160.140 45.970 ;
        RECT 149.200 45.180 149.370 45.680 ;
        RECT 159.750 45.180 160.140 45.680 ;
        RECT 149.540 44.950 159.580 45.120 ;
        RECT 159.780 44.890 160.140 45.180 ;
        RECT 149.200 44.390 149.370 44.890 ;
        RECT 159.750 44.390 160.140 44.890 ;
        RECT 25.000 42.995 62.720 43.040 ;
        RECT 66.745 42.995 148.700 44.170 ;
        RECT 149.540 44.160 159.580 44.330 ;
        RECT 159.780 44.100 160.140 44.390 ;
        RECT 149.200 43.600 149.370 44.100 ;
        RECT 159.750 43.600 160.140 44.100 ;
        RECT 149.540 43.370 159.580 43.540 ;
        RECT 25.000 42.980 148.700 42.995 ;
        RECT 160.330 42.980 164.080 47.210 ;
        RECT 25.000 42.635 164.080 42.980 ;
        RECT 25.000 42.460 62.720 42.635 ;
        RECT 66.770 42.460 164.080 42.635 ;
        RECT 25.000 41.680 164.080 42.460 ;
        RECT 25.000 41.640 136.250 41.680 ;
        RECT 25.000 41.590 95.340 41.640 ;
        RECT 25.000 41.350 84.080 41.590 ;
        RECT 25.000 39.350 69.740 41.350 ;
        RECT 72.000 41.290 84.080 41.350 ;
        RECT 144.560 34.760 164.080 41.680 ;
        RECT 164.560 34.760 164.730 52.190 ;
        RECT 144.560 33.250 164.780 34.760 ;
        RECT 144.560 31.350 164.080 33.250 ;
        RECT 164.560 32.150 164.730 33.250 ;
        RECT 165.350 32.150 165.520 52.190 ;
        RECT 166.140 32.150 166.310 52.190 ;
        RECT 166.930 32.150 167.100 52.190 ;
        RECT 167.720 32.150 167.890 52.190 ;
        RECT 168.510 32.150 168.680 52.190 ;
        RECT 164.770 31.700 168.510 31.980 ;
        RECT 169.140 31.350 194.570 52.440 ;
        RECT 144.560 29.150 194.570 31.350 ;
        RECT 158.400 28.660 194.570 29.150 ;
        RECT 172.590 28.650 194.570 28.660 ;
      LAYER mcon ;
        RECT 120.600 164.150 121.170 164.570 ;
        RECT 166.230 164.180 166.580 164.680 ;
        RECT 109.540 162.790 110.050 163.360 ;
        RECT 114.835 162.820 119.715 162.990 ;
        RECT 101.775 161.470 109.155 161.640 ;
        RECT 89.305 160.100 96.685 160.270 ;
        RECT 25.530 155.610 26.850 156.110 ;
        RECT 65.790 153.770 72.390 158.400 ;
        RECT 88.840 158.120 89.010 159.960 ;
        RECT 96.980 158.120 97.150 159.960 ;
        RECT 89.305 157.810 96.685 157.980 ;
        RECT 101.310 159.490 101.480 161.330 ;
        RECT 109.450 159.490 109.620 161.330 ;
        RECT 101.775 159.180 109.155 159.350 ;
        RECT 101.310 157.200 101.480 159.040 ;
        RECT 109.450 157.200 109.620 159.040 ;
        RECT 114.370 161.840 114.540 162.680 ;
        RECT 120.010 161.840 120.180 162.680 ;
        RECT 114.835 161.530 119.715 161.700 ;
        RECT 114.370 160.550 114.540 161.390 ;
        RECT 120.010 160.550 120.180 161.390 ;
        RECT 114.835 160.240 119.715 160.410 ;
        RECT 114.370 159.260 114.540 160.100 ;
        RECT 120.010 159.260 120.180 160.100 ;
        RECT 114.835 158.950 119.715 159.120 ;
        RECT 114.370 157.970 114.540 158.810 ;
        RECT 120.010 157.970 120.180 158.810 ;
        RECT 114.835 157.660 119.715 157.830 ;
        RECT 121.855 162.820 126.735 162.990 ;
        RECT 121.390 161.840 121.560 162.680 ;
        RECT 127.030 161.840 127.200 162.680 ;
        RECT 121.855 161.530 126.735 161.700 ;
        RECT 121.390 160.550 121.560 161.390 ;
        RECT 127.030 160.550 127.200 161.390 ;
        RECT 121.855 160.240 126.735 160.410 ;
        RECT 121.390 159.260 121.560 160.100 ;
        RECT 127.030 159.260 127.200 160.100 ;
        RECT 121.855 158.950 126.735 159.120 ;
        RECT 121.390 157.970 121.560 158.810 ;
        RECT 127.030 157.970 127.200 158.810 ;
        RECT 121.855 157.660 126.735 157.830 ;
        RECT 136.430 162.995 151.310 163.165 ;
        RECT 135.965 162.515 136.135 162.855 ;
        RECT 151.605 162.515 151.775 162.855 ;
        RECT 136.430 162.205 151.310 162.375 ;
        RECT 135.965 161.725 136.135 162.065 ;
        RECT 151.605 161.725 151.775 162.065 ;
        RECT 136.430 161.415 151.310 161.585 ;
        RECT 135.965 160.935 136.135 161.275 ;
        RECT 151.605 160.935 151.775 161.275 ;
        RECT 136.430 160.625 151.310 160.795 ;
        RECT 135.965 160.145 136.135 160.485 ;
        RECT 151.605 160.145 151.775 160.485 ;
        RECT 136.430 159.835 151.310 160.005 ;
        RECT 135.965 159.355 136.135 159.695 ;
        RECT 151.605 159.355 151.775 159.695 ;
        RECT 136.430 159.045 151.310 159.215 ;
        RECT 135.965 158.565 136.135 158.905 ;
        RECT 151.605 158.565 151.775 158.905 ;
        RECT 136.430 158.255 151.310 158.425 ;
        RECT 135.965 157.775 136.135 158.115 ;
        RECT 151.605 157.775 151.775 158.115 ;
        RECT 136.430 157.465 151.310 157.635 ;
        RECT 101.775 156.890 109.155 157.060 ;
        RECT 159.590 162.820 159.930 162.990 ;
        RECT 160.380 162.820 160.720 162.990 ;
        RECT 161.170 162.820 161.510 162.990 ;
        RECT 161.960 162.820 162.300 162.990 ;
        RECT 162.750 162.820 163.090 162.990 ;
        RECT 163.540 162.820 163.880 162.990 ;
        RECT 164.330 162.820 164.670 162.990 ;
        RECT 165.120 162.820 165.460 162.990 ;
        RECT 165.910 162.820 166.250 162.990 ;
        RECT 166.700 162.820 167.040 162.990 ;
        RECT 114.805 153.625 119.685 153.795 ;
        RECT 51.770 151.680 52.610 151.850 ;
        RECT 37.950 150.760 39.935 150.950 ;
        RECT 24.815 146.960 26.800 147.150 ;
        RECT 45.115 147.440 47.100 147.630 ;
        RECT 24.815 146.130 26.800 146.320 ;
        RECT 51.460 146.550 51.630 151.430 ;
        RECT 52.750 146.550 52.920 151.430 ;
        RECT 51.770 146.130 52.610 146.300 ;
        RECT 87.885 152.960 97.765 153.130 ;
        RECT 87.420 151.980 87.590 152.820 ;
        RECT 98.060 151.980 98.230 152.820 ;
        RECT 87.885 151.670 97.765 151.840 ;
        RECT 87.420 150.690 87.590 151.530 ;
        RECT 98.060 150.690 98.230 151.530 ;
        RECT 87.885 150.380 97.765 150.550 ;
        RECT 99.905 152.960 109.785 153.130 ;
        RECT 99.440 151.980 99.610 152.820 ;
        RECT 110.080 151.980 110.250 152.820 ;
        RECT 99.905 151.670 109.785 151.840 ;
        RECT 99.440 150.690 99.610 151.530 ;
        RECT 110.080 150.690 110.250 151.530 ;
        RECT 99.905 150.380 109.785 150.550 ;
        RECT 114.340 153.145 114.510 153.485 ;
        RECT 119.980 153.145 120.150 153.485 ;
        RECT 114.805 152.835 119.685 153.005 ;
        RECT 114.340 152.355 114.510 152.695 ;
        RECT 119.980 152.355 120.150 152.695 ;
        RECT 114.805 152.045 119.685 152.215 ;
        RECT 114.340 151.565 114.510 151.905 ;
        RECT 119.980 151.565 120.150 151.905 ;
        RECT 114.805 151.255 119.685 151.425 ;
        RECT 114.340 150.775 114.510 151.115 ;
        RECT 119.980 150.775 120.150 151.115 ;
        RECT 114.805 150.465 119.685 150.635 ;
        RECT 121.825 153.625 126.705 153.795 ;
        RECT 121.360 153.145 121.530 153.485 ;
        RECT 127.000 153.145 127.170 153.485 ;
        RECT 121.825 152.835 126.705 153.005 ;
        RECT 121.360 152.355 121.530 152.695 ;
        RECT 127.000 152.355 127.170 152.695 ;
        RECT 121.825 152.045 126.705 152.215 ;
        RECT 121.360 151.565 121.530 151.905 ;
        RECT 127.000 151.565 127.170 151.905 ;
        RECT 121.825 151.255 126.705 151.425 ;
        RECT 121.360 150.775 121.530 151.115 ;
        RECT 127.000 150.775 127.170 151.115 ;
        RECT 121.825 150.465 126.705 150.635 ;
        RECT 136.430 156.125 151.310 156.295 ;
        RECT 135.965 155.645 136.135 155.985 ;
        RECT 151.605 155.645 151.775 155.985 ;
        RECT 136.430 155.335 151.310 155.505 ;
        RECT 135.965 154.855 136.135 155.195 ;
        RECT 151.605 154.855 151.775 155.195 ;
        RECT 136.430 154.545 151.310 154.715 ;
        RECT 135.965 154.065 136.135 154.405 ;
        RECT 151.605 154.065 151.775 154.405 ;
        RECT 136.430 153.755 151.310 153.925 ;
        RECT 135.965 153.275 136.135 153.615 ;
        RECT 151.605 153.275 151.775 153.615 ;
        RECT 136.430 152.965 151.310 153.135 ;
        RECT 135.965 152.485 136.135 152.825 ;
        RECT 151.605 152.485 151.775 152.825 ;
        RECT 136.430 152.175 151.310 152.345 ;
        RECT 135.965 151.695 136.135 152.035 ;
        RECT 151.605 151.695 151.775 152.035 ;
        RECT 136.430 151.385 151.310 151.555 ;
        RECT 135.965 150.905 136.135 151.245 ;
        RECT 151.605 150.905 151.775 151.245 ;
        RECT 136.430 150.595 151.310 150.765 ;
        RECT 123.005 147.970 124.990 148.160 ;
        RECT 123.005 147.140 124.990 147.330 ;
        RECT 38.580 143.450 38.900 143.620 ;
        RECT 40.110 143.450 40.430 143.620 ;
        RECT 41.640 143.450 41.960 143.620 ;
        RECT 43.170 143.450 43.490 143.620 ;
        RECT 44.700 143.450 45.020 143.620 ;
        RECT 46.230 143.450 46.550 143.620 ;
        RECT 47.760 143.450 48.080 143.620 ;
        RECT 49.290 143.450 49.610 143.620 ;
        RECT 50.820 143.450 51.140 143.620 ;
        RECT 52.350 143.450 52.670 143.620 ;
        RECT 24.875 141.760 26.860 141.950 ;
        RECT 24.875 140.930 26.860 141.120 ;
        RECT 38.160 133.470 38.330 143.310 ;
        RECT 39.150 133.470 39.320 143.310 ;
        RECT 39.690 133.470 39.860 143.310 ;
        RECT 40.680 133.470 40.850 143.310 ;
        RECT 41.220 133.470 41.390 143.310 ;
        RECT 42.210 133.470 42.380 143.310 ;
        RECT 42.750 133.470 42.920 143.310 ;
        RECT 43.740 133.470 43.910 143.310 ;
        RECT 44.280 133.470 44.450 143.310 ;
        RECT 45.270 133.470 45.440 143.310 ;
        RECT 45.810 133.470 45.980 143.310 ;
        RECT 46.800 133.470 46.970 143.310 ;
        RECT 47.340 133.470 47.510 143.310 ;
        RECT 48.330 133.470 48.500 143.310 ;
        RECT 48.870 133.470 49.040 143.310 ;
        RECT 49.860 133.470 50.030 143.310 ;
        RECT 50.400 133.470 50.570 143.310 ;
        RECT 51.390 133.470 51.560 143.310 ;
        RECT 51.930 133.470 52.100 143.310 ;
        RECT 52.920 133.470 53.090 143.310 ;
        RECT 38.580 133.160 38.900 133.330 ;
        RECT 40.110 133.160 40.430 133.330 ;
        RECT 41.640 133.160 41.960 133.330 ;
        RECT 43.170 133.160 43.490 133.330 ;
        RECT 44.700 133.160 45.020 133.330 ;
        RECT 46.230 133.160 46.550 133.330 ;
        RECT 47.760 133.160 48.080 133.330 ;
        RECT 49.290 133.160 49.610 133.330 ;
        RECT 50.820 133.160 51.140 133.330 ;
        RECT 52.350 133.160 52.670 133.330 ;
        RECT 99.135 143.860 109.015 144.030 ;
        RECT 88.815 141.180 89.695 141.350 ;
        RECT 88.350 140.200 88.520 141.040 ;
        RECT 89.990 140.200 90.160 141.040 ;
        RECT 88.815 139.890 89.695 140.060 ;
        RECT 91.835 141.180 92.715 141.350 ;
        RECT 91.370 140.200 91.540 141.040 ;
        RECT 93.010 140.200 93.180 141.040 ;
        RECT 98.670 142.880 98.840 143.720 ;
        RECT 109.310 142.880 109.480 143.720 ;
        RECT 99.135 142.570 109.015 142.740 ;
        RECT 98.670 141.590 98.840 142.430 ;
        RECT 109.310 141.590 109.480 142.430 ;
        RECT 99.135 141.280 109.015 141.450 ;
        RECT 91.835 139.890 92.715 140.060 ;
        RECT 98.670 140.300 98.840 141.140 ;
        RECT 109.310 140.300 109.480 141.140 ;
        RECT 99.135 139.990 109.015 140.160 ;
        RECT 98.670 139.010 98.840 139.850 ;
        RECT 109.310 139.010 109.480 139.850 ;
        RECT 99.135 138.700 109.015 138.870 ;
        RECT 98.670 137.720 98.840 138.560 ;
        RECT 109.310 137.720 109.480 138.560 ;
        RECT 99.135 137.410 109.015 137.580 ;
        RECT 98.670 136.430 98.840 137.270 ;
        RECT 109.310 136.430 109.480 137.270 ;
        RECT 99.135 136.120 109.015 136.290 ;
        RECT 111.155 143.860 121.035 144.030 ;
        RECT 110.690 142.880 110.860 143.720 ;
        RECT 121.330 142.880 121.500 143.720 ;
        RECT 111.155 142.570 121.035 142.740 ;
        RECT 110.690 141.590 110.860 142.430 ;
        RECT 121.330 141.590 121.500 142.430 ;
        RECT 111.155 141.280 121.035 141.450 ;
        RECT 110.690 140.300 110.860 141.140 ;
        RECT 121.330 140.300 121.500 141.140 ;
        RECT 111.155 139.990 121.035 140.160 ;
        RECT 110.690 139.010 110.860 139.850 ;
        RECT 121.330 139.010 121.500 139.850 ;
        RECT 111.155 138.700 121.035 138.870 ;
        RECT 110.690 137.720 110.860 138.560 ;
        RECT 121.330 137.720 121.500 138.560 ;
        RECT 111.155 137.410 121.035 137.580 ;
        RECT 110.690 136.430 110.860 137.270 ;
        RECT 121.330 136.430 121.500 137.270 ;
        RECT 111.155 136.120 121.035 136.290 ;
        RECT 39.795 128.385 40.635 128.555 ;
        RECT 41.085 128.385 41.925 128.555 ;
        RECT 42.375 128.385 43.215 128.555 ;
        RECT 43.665 128.385 44.505 128.555 ;
        RECT 44.955 128.385 45.795 128.555 ;
        RECT 39.485 124.255 39.655 128.135 ;
        RECT 40.775 124.255 40.945 128.135 ;
        RECT 42.065 124.255 42.235 128.135 ;
        RECT 43.355 124.255 43.525 128.135 ;
        RECT 44.645 124.255 44.815 128.135 ;
        RECT 45.935 124.255 46.105 128.135 ;
        RECT 39.795 123.835 40.635 124.005 ;
        RECT 41.085 123.835 41.925 124.005 ;
        RECT 42.375 123.835 43.215 124.005 ;
        RECT 43.665 123.835 44.505 124.005 ;
        RECT 44.955 123.835 45.795 124.005 ;
        RECT 47.605 128.385 48.445 128.555 ;
        RECT 48.895 128.385 49.735 128.555 ;
        RECT 50.185 128.385 51.025 128.555 ;
        RECT 51.475 128.385 52.315 128.555 ;
        RECT 52.765 128.385 53.605 128.555 ;
        RECT 47.295 124.255 47.465 128.135 ;
        RECT 48.585 124.255 48.755 128.135 ;
        RECT 49.875 124.255 50.045 128.135 ;
        RECT 51.165 124.255 51.335 128.135 ;
        RECT 52.455 124.255 52.625 128.135 ;
        RECT 53.745 124.255 53.915 128.135 ;
        RECT 47.605 123.835 48.445 124.005 ;
        RECT 48.895 123.835 49.735 124.005 ;
        RECT 50.185 123.835 51.025 124.005 ;
        RECT 51.475 123.835 52.315 124.005 ;
        RECT 52.765 123.835 53.605 124.005 ;
        RECT 59.590 133.940 60.430 134.110 ;
        RECT 59.280 132.765 59.450 133.645 ;
        RECT 60.570 132.765 60.740 133.645 ;
        RECT 59.590 132.300 60.430 132.470 ;
        RECT 59.580 127.060 60.420 127.230 ;
        RECT 59.270 125.885 59.440 126.765 ;
        RECT 60.560 125.885 60.730 126.765 ;
        RECT 59.580 125.420 60.420 125.590 ;
        RECT 38.420 114.840 39.260 115.010 ;
        RECT 39.710 114.840 40.550 115.010 ;
        RECT 41.000 114.840 41.840 115.010 ;
        RECT 42.290 114.840 43.130 115.010 ;
        RECT 43.580 114.840 44.420 115.010 ;
        RECT 38.110 110.710 38.280 114.590 ;
        RECT 39.400 110.710 39.570 114.590 ;
        RECT 40.690 110.710 40.860 114.590 ;
        RECT 41.980 110.710 42.150 114.590 ;
        RECT 43.270 110.710 43.440 114.590 ;
        RECT 44.560 110.710 44.730 114.590 ;
        RECT 38.420 110.290 39.260 110.460 ;
        RECT 39.710 110.290 40.550 110.460 ;
        RECT 41.000 110.290 41.840 110.460 ;
        RECT 42.290 110.290 43.130 110.460 ;
        RECT 43.580 110.290 44.420 110.460 ;
        RECT 38.420 108.910 39.260 109.080 ;
        RECT 39.710 108.910 40.550 109.080 ;
        RECT 41.000 108.910 41.840 109.080 ;
        RECT 42.290 108.910 43.130 109.080 ;
        RECT 43.580 108.910 44.420 109.080 ;
        RECT 38.110 104.780 38.280 108.660 ;
        RECT 39.400 104.780 39.570 108.660 ;
        RECT 40.690 104.780 40.860 108.660 ;
        RECT 41.980 104.780 42.150 108.660 ;
        RECT 43.270 104.780 43.440 108.660 ;
        RECT 44.560 104.780 44.730 108.660 ;
        RECT 38.420 104.360 39.260 104.530 ;
        RECT 39.710 104.360 40.550 104.530 ;
        RECT 41.000 104.360 41.840 104.530 ;
        RECT 42.290 104.360 43.130 104.530 ;
        RECT 43.580 104.360 44.420 104.530 ;
        RECT 149.685 146.440 153.565 146.610 ;
        RECT 129.175 144.050 144.055 144.220 ;
        RECT 128.710 143.570 128.880 143.910 ;
        RECT 144.350 143.570 144.520 143.910 ;
        RECT 129.175 143.260 144.055 143.430 ;
        RECT 128.710 142.780 128.880 143.120 ;
        RECT 144.350 142.780 144.520 143.120 ;
        RECT 129.175 142.470 144.055 142.640 ;
        RECT 128.710 141.990 128.880 142.330 ;
        RECT 144.350 141.990 144.520 142.330 ;
        RECT 129.175 141.680 144.055 141.850 ;
        RECT 128.710 141.200 128.880 141.540 ;
        RECT 144.350 141.200 144.520 141.540 ;
        RECT 129.175 140.890 144.055 141.060 ;
        RECT 128.710 140.410 128.880 140.750 ;
        RECT 144.350 140.410 144.520 140.750 ;
        RECT 129.175 140.100 144.055 140.270 ;
        RECT 128.710 139.620 128.880 139.960 ;
        RECT 144.350 139.620 144.520 139.960 ;
        RECT 129.175 139.310 144.055 139.480 ;
        RECT 128.710 138.830 128.880 139.170 ;
        RECT 144.350 138.830 144.520 139.170 ;
        RECT 129.175 138.520 144.055 138.690 ;
        RECT 128.710 138.040 128.880 138.380 ;
        RECT 144.350 138.040 144.520 138.380 ;
        RECT 149.220 141.460 149.390 146.300 ;
        RECT 153.860 141.460 154.030 146.300 ;
        RECT 149.685 141.150 153.565 141.320 ;
        RECT 129.175 137.730 144.055 137.900 ;
        RECT 82.450 132.830 84.330 133.000 ;
        RECT 82.030 127.850 82.200 132.690 ;
        RECT 84.580 127.850 84.750 132.690 ;
        RECT 88.370 132.690 93.250 132.860 ;
        RECT 87.950 132.210 88.120 132.550 ;
        RECT 93.500 132.210 93.670 132.550 ;
        RECT 88.370 131.900 93.250 132.070 ;
        RECT 95.300 132.690 100.180 132.860 ;
        RECT 94.880 132.210 95.050 132.550 ;
        RECT 100.430 132.210 100.600 132.550 ;
        RECT 95.300 131.900 100.180 132.070 ;
        RECT 106.120 132.850 115.980 133.060 ;
        RECT 105.640 131.350 105.810 132.690 ;
        RECT 116.190 131.350 116.360 132.690 ;
        RECT 106.060 131.040 115.940 131.210 ;
        RECT 105.640 129.560 105.810 130.900 ;
        RECT 116.190 129.560 116.360 130.900 ;
        RECT 82.450 127.540 84.330 127.710 ;
        RECT 91.830 128.790 93.210 128.960 ;
        RECT 91.410 127.310 91.580 128.650 ;
        RECT 93.460 127.310 93.630 128.650 ;
        RECT 91.830 127.000 93.210 127.170 ;
        RECT 95.260 128.790 96.640 128.960 ;
        RECT 94.840 127.310 95.010 128.650 ;
        RECT 96.890 127.310 97.060 128.650 ;
        RECT 95.260 127.000 96.640 127.170 ;
        RECT 106.060 129.250 115.940 129.420 ;
        RECT 105.640 127.770 105.810 129.110 ;
        RECT 116.190 127.770 116.360 129.110 ;
        RECT 106.060 127.460 115.940 127.630 ;
        RECT 105.640 125.980 105.810 127.320 ;
        RECT 116.190 125.980 116.360 127.320 ;
        RECT 106.060 125.670 115.940 125.840 ;
        RECT 117.570 131.350 117.740 132.690 ;
        RECT 128.120 131.350 128.290 132.690 ;
        RECT 117.990 131.040 127.870 131.210 ;
        RECT 117.570 129.560 117.740 130.900 ;
        RECT 128.120 129.560 128.290 130.900 ;
        RECT 117.990 129.250 127.870 129.420 ;
        RECT 117.570 127.770 117.740 129.110 ;
        RECT 128.120 127.770 128.290 129.110 ;
        RECT 117.990 127.460 127.870 127.630 ;
        RECT 117.570 125.980 117.740 127.320 ;
        RECT 128.120 125.980 128.290 127.320 ;
        RECT 133.680 132.150 135.060 132.320 ;
        RECT 133.260 127.170 133.430 132.010 ;
        RECT 135.310 127.170 135.480 132.010 ;
        RECT 141.110 132.290 150.990 132.460 ;
        RECT 140.690 131.810 140.860 132.150 ;
        RECT 151.240 131.810 151.410 132.150 ;
        RECT 141.110 131.500 150.990 131.670 ;
        RECT 140.690 131.020 140.860 131.360 ;
        RECT 151.240 131.020 151.410 131.360 ;
        RECT 141.110 130.710 150.990 130.880 ;
        RECT 140.690 130.230 140.860 130.570 ;
        RECT 151.240 130.230 151.410 130.570 ;
        RECT 141.110 129.920 150.990 130.090 ;
        RECT 140.690 129.440 140.860 129.780 ;
        RECT 151.240 129.440 151.410 129.780 ;
        RECT 141.110 129.130 150.990 129.300 ;
        RECT 159.280 132.645 159.450 162.525 ;
        RECT 160.070 132.645 160.240 162.525 ;
        RECT 160.860 132.645 161.030 162.525 ;
        RECT 161.650 132.645 161.820 162.525 ;
        RECT 162.440 132.645 162.610 162.525 ;
        RECT 163.230 132.645 163.400 162.525 ;
        RECT 164.020 132.645 164.190 162.525 ;
        RECT 164.810 132.645 164.980 162.525 ;
        RECT 165.600 132.645 165.770 162.525 ;
        RECT 166.390 132.645 166.560 162.525 ;
        RECT 167.180 132.645 167.350 162.525 ;
        RECT 159.590 132.180 159.930 132.350 ;
        RECT 160.380 132.180 160.720 132.350 ;
        RECT 161.170 132.180 161.510 132.350 ;
        RECT 161.960 132.180 162.300 132.350 ;
        RECT 162.750 132.180 163.090 132.350 ;
        RECT 163.540 132.180 163.880 132.350 ;
        RECT 164.330 132.180 164.670 132.350 ;
        RECT 165.120 132.180 165.460 132.350 ;
        RECT 165.910 132.180 166.250 132.350 ;
        RECT 166.700 132.180 167.040 132.350 ;
        RECT 133.680 126.860 135.060 127.030 ;
        RECT 161.560 127.100 161.900 127.270 ;
        RECT 162.350 127.100 162.690 127.270 ;
        RECT 163.140 127.100 163.480 127.270 ;
        RECT 163.930 127.100 164.270 127.270 ;
        RECT 164.720 127.100 165.060 127.270 ;
        RECT 117.990 125.670 127.870 125.840 ;
        RECT 146.310 125.790 156.190 125.960 ;
        RECT 145.890 125.310 146.060 125.650 ;
        RECT 156.440 125.310 156.610 125.650 ;
        RECT 146.310 125.000 156.190 125.170 ;
        RECT 145.890 124.520 146.060 124.860 ;
        RECT 156.440 124.520 156.610 124.860 ;
        RECT 146.310 124.210 156.190 124.380 ;
        RECT 145.890 123.730 146.060 124.070 ;
        RECT 156.440 123.730 156.610 124.070 ;
        RECT 146.310 123.420 156.190 123.590 ;
        RECT 145.890 122.940 146.060 123.280 ;
        RECT 156.440 122.940 156.610 123.280 ;
        RECT 146.310 122.630 156.190 122.800 ;
        RECT 113.690 121.120 116.070 121.290 ;
        RECT 113.270 119.640 113.440 120.980 ;
        RECT 116.320 119.640 116.490 120.980 ;
        RECT 113.690 119.330 116.070 119.500 ;
        RECT 118.120 121.120 120.500 121.290 ;
        RECT 117.700 119.640 117.870 120.980 ;
        RECT 120.750 119.640 120.920 120.980 ;
        RECT 118.120 119.330 120.500 119.500 ;
        RECT 146.310 121.270 156.190 121.440 ;
        RECT 145.890 120.790 146.060 121.130 ;
        RECT 156.440 120.790 156.610 121.130 ;
        RECT 146.310 120.480 156.190 120.650 ;
        RECT 145.890 120.000 146.060 120.340 ;
        RECT 156.440 120.000 156.610 120.340 ;
        RECT 146.310 119.690 156.190 119.860 ;
        RECT 145.890 119.210 146.060 119.550 ;
        RECT 156.440 119.210 156.610 119.550 ;
        RECT 146.310 118.900 156.190 119.070 ;
        RECT 145.890 118.420 146.060 118.760 ;
        RECT 156.440 118.420 156.610 118.760 ;
        RECT 146.310 118.110 156.190 118.280 ;
        RECT 154.950 116.930 155.850 117.270 ;
        RECT 48.305 114.655 49.145 114.825 ;
        RECT 49.595 114.655 50.435 114.825 ;
        RECT 50.885 114.655 51.725 114.825 ;
        RECT 52.175 114.655 53.015 114.825 ;
        RECT 53.465 114.655 54.305 114.825 ;
        RECT 47.995 110.480 48.165 114.360 ;
        RECT 49.285 110.480 49.455 114.360 ;
        RECT 50.575 110.480 50.745 114.360 ;
        RECT 51.865 110.480 52.035 114.360 ;
        RECT 53.155 110.480 53.325 114.360 ;
        RECT 54.445 110.480 54.615 114.360 ;
        RECT 48.305 110.015 49.145 110.185 ;
        RECT 49.595 110.015 50.435 110.185 ;
        RECT 50.885 110.015 51.725 110.185 ;
        RECT 52.175 110.015 53.015 110.185 ;
        RECT 53.465 110.015 54.305 110.185 ;
        RECT 59.545 110.285 60.385 110.455 ;
        RECT 48.305 108.635 49.145 108.805 ;
        RECT 49.595 108.635 50.435 108.805 ;
        RECT 50.885 108.635 51.725 108.805 ;
        RECT 52.175 108.635 53.015 108.805 ;
        RECT 53.465 108.635 54.305 108.805 ;
        RECT 47.995 104.460 48.165 108.340 ;
        RECT 49.285 104.460 49.455 108.340 ;
        RECT 50.575 104.460 50.745 108.340 ;
        RECT 51.865 104.460 52.035 108.340 ;
        RECT 53.155 104.460 53.325 108.340 ;
        RECT 54.445 104.460 54.615 108.340 ;
        RECT 59.235 109.110 59.405 109.990 ;
        RECT 60.525 109.110 60.695 109.990 ;
        RECT 59.545 108.645 60.385 108.815 ;
        RECT 48.305 103.995 49.145 104.165 ;
        RECT 49.595 103.995 50.435 104.165 ;
        RECT 50.885 103.995 51.725 104.165 ;
        RECT 52.175 103.995 53.015 104.165 ;
        RECT 53.465 103.995 54.305 104.165 ;
        RECT 40.780 95.215 40.970 97.200 ;
        RECT 45.580 95.245 45.770 97.235 ;
        RECT 48.900 92.610 49.090 94.595 ;
        RECT 40.780 89.720 40.970 91.705 ;
        RECT 48.900 89.315 49.090 91.305 ;
        RECT 45.580 86.680 45.770 88.665 ;
        RECT 53.670 93.980 54.010 94.150 ;
        RECT 54.460 93.980 54.800 94.150 ;
        RECT 55.250 93.980 55.590 94.150 ;
        RECT 56.040 93.980 56.380 94.150 ;
        RECT 56.830 93.980 57.170 94.150 ;
        RECT 53.360 89.805 53.530 93.685 ;
        RECT 54.150 89.805 54.320 93.685 ;
        RECT 54.940 89.805 55.110 93.685 ;
        RECT 55.730 89.805 55.900 93.685 ;
        RECT 56.520 89.805 56.690 93.685 ;
        RECT 57.310 89.805 57.480 93.685 ;
        RECT 87.510 107.000 94.550 115.880 ;
        RECT 121.855 111.540 123.840 112.070 ;
        RECT 121.855 108.030 123.840 108.560 ;
        RECT 130.010 111.840 131.995 112.030 ;
        RECT 135.645 108.520 137.630 108.710 ;
        RECT 161.250 106.970 161.420 126.850 ;
        RECT 162.040 106.970 162.210 126.850 ;
        RECT 162.830 106.970 163.000 126.850 ;
        RECT 163.620 106.970 163.790 126.850 ;
        RECT 164.410 106.970 164.580 126.850 ;
        RECT 165.200 106.970 165.370 126.850 ;
        RECT 161.560 106.550 161.900 106.720 ;
        RECT 162.350 106.550 162.690 106.720 ;
        RECT 163.140 106.550 163.480 106.720 ;
        RECT 163.930 106.550 164.270 106.720 ;
        RECT 164.720 106.550 165.060 106.720 ;
        RECT 109.340 101.125 109.530 103.110 ;
        RECT 106.020 95.490 106.210 97.475 ;
        RECT 115.000 101.195 115.530 103.180 ;
        RECT 118.510 101.195 119.040 103.180 ;
        RECT 53.670 89.340 54.010 89.510 ;
        RECT 54.460 89.340 54.800 89.510 ;
        RECT 55.250 89.340 55.590 89.510 ;
        RECT 56.040 89.340 56.380 89.510 ;
        RECT 56.830 89.340 57.170 89.510 ;
        RECT 123.910 89.410 124.480 89.830 ;
        RECT 169.540 89.440 169.890 89.940 ;
        RECT 112.850 88.050 113.360 88.620 ;
        RECT 118.145 88.080 123.025 88.250 ;
        RECT 105.085 86.730 112.465 86.900 ;
        RECT 29.570 80.000 29.740 80.170 ;
        RECT 30.070 80.000 30.240 80.170 ;
        RECT 30.570 80.000 30.740 80.170 ;
        RECT 31.070 80.000 31.240 80.170 ;
        RECT 31.570 80.000 31.740 80.170 ;
        RECT 32.070 80.000 32.240 80.170 ;
        RECT 29.570 79.500 29.740 79.670 ;
        RECT 30.070 79.500 30.240 79.670 ;
        RECT 30.570 79.500 30.740 79.670 ;
        RECT 31.070 79.500 31.240 79.670 ;
        RECT 31.570 79.500 31.740 79.670 ;
        RECT 32.070 79.500 32.240 79.670 ;
        RECT 29.570 79.000 29.740 79.170 ;
        RECT 30.070 79.000 30.240 79.170 ;
        RECT 30.570 79.000 30.740 79.170 ;
        RECT 31.070 79.000 31.240 79.170 ;
        RECT 31.570 79.000 31.740 79.170 ;
        RECT 32.070 79.000 32.240 79.170 ;
        RECT 29.570 78.500 29.740 78.670 ;
        RECT 30.070 78.500 30.240 78.670 ;
        RECT 30.570 78.500 30.740 78.670 ;
        RECT 31.070 78.500 31.240 78.670 ;
        RECT 31.570 78.500 31.740 78.670 ;
        RECT 32.070 78.500 32.240 78.670 ;
        RECT 29.570 78.000 29.740 78.170 ;
        RECT 30.070 78.000 30.240 78.170 ;
        RECT 30.570 78.000 30.740 78.170 ;
        RECT 31.070 78.000 31.240 78.170 ;
        RECT 31.570 78.000 31.740 78.170 ;
        RECT 32.070 78.000 32.240 78.170 ;
        RECT 29.570 77.500 29.740 77.670 ;
        RECT 30.070 77.500 30.240 77.670 ;
        RECT 30.570 77.500 30.740 77.670 ;
        RECT 31.070 77.500 31.240 77.670 ;
        RECT 31.570 77.500 31.740 77.670 ;
        RECT 32.070 77.500 32.240 77.670 ;
        RECT 38.010 80.000 38.180 80.170 ;
        RECT 38.510 80.000 38.680 80.170 ;
        RECT 39.010 80.000 39.180 80.170 ;
        RECT 39.510 80.000 39.680 80.170 ;
        RECT 40.010 80.000 40.180 80.170 ;
        RECT 40.510 80.000 40.680 80.170 ;
        RECT 38.010 79.500 38.180 79.670 ;
        RECT 38.510 79.500 38.680 79.670 ;
        RECT 39.010 79.500 39.180 79.670 ;
        RECT 39.510 79.500 39.680 79.670 ;
        RECT 40.010 79.500 40.180 79.670 ;
        RECT 40.510 79.500 40.680 79.670 ;
        RECT 38.010 79.000 38.180 79.170 ;
        RECT 38.510 79.000 38.680 79.170 ;
        RECT 39.010 79.000 39.180 79.170 ;
        RECT 39.510 79.000 39.680 79.170 ;
        RECT 40.010 79.000 40.180 79.170 ;
        RECT 40.510 79.000 40.680 79.170 ;
        RECT 38.010 78.500 38.180 78.670 ;
        RECT 38.510 78.500 38.680 78.670 ;
        RECT 39.010 78.500 39.180 78.670 ;
        RECT 39.510 78.500 39.680 78.670 ;
        RECT 40.010 78.500 40.180 78.670 ;
        RECT 40.510 78.500 40.680 78.670 ;
        RECT 38.010 78.000 38.180 78.170 ;
        RECT 38.510 78.000 38.680 78.170 ;
        RECT 39.010 78.000 39.180 78.170 ;
        RECT 39.510 78.000 39.680 78.170 ;
        RECT 40.010 78.000 40.180 78.170 ;
        RECT 40.510 78.000 40.680 78.170 ;
        RECT 38.010 77.500 38.180 77.670 ;
        RECT 38.510 77.500 38.680 77.670 ;
        RECT 39.010 77.500 39.180 77.670 ;
        RECT 39.510 77.500 39.680 77.670 ;
        RECT 40.010 77.500 40.180 77.670 ;
        RECT 40.510 77.500 40.680 77.670 ;
        RECT 46.450 80.000 46.620 80.170 ;
        RECT 46.950 80.000 47.120 80.170 ;
        RECT 47.450 80.000 47.620 80.170 ;
        RECT 47.950 80.000 48.120 80.170 ;
        RECT 48.450 80.000 48.620 80.170 ;
        RECT 48.950 80.000 49.120 80.170 ;
        RECT 46.450 79.500 46.620 79.670 ;
        RECT 46.950 79.500 47.120 79.670 ;
        RECT 47.450 79.500 47.620 79.670 ;
        RECT 47.950 79.500 48.120 79.670 ;
        RECT 48.450 79.500 48.620 79.670 ;
        RECT 48.950 79.500 49.120 79.670 ;
        RECT 46.450 79.000 46.620 79.170 ;
        RECT 46.950 79.000 47.120 79.170 ;
        RECT 47.450 79.000 47.620 79.170 ;
        RECT 47.950 79.000 48.120 79.170 ;
        RECT 48.450 79.000 48.620 79.170 ;
        RECT 48.950 79.000 49.120 79.170 ;
        RECT 46.450 78.500 46.620 78.670 ;
        RECT 46.950 78.500 47.120 78.670 ;
        RECT 47.450 78.500 47.620 78.670 ;
        RECT 47.950 78.500 48.120 78.670 ;
        RECT 48.450 78.500 48.620 78.670 ;
        RECT 48.950 78.500 49.120 78.670 ;
        RECT 46.450 78.000 46.620 78.170 ;
        RECT 46.950 78.000 47.120 78.170 ;
        RECT 47.450 78.000 47.620 78.170 ;
        RECT 47.950 78.000 48.120 78.170 ;
        RECT 48.450 78.000 48.620 78.170 ;
        RECT 48.950 78.000 49.120 78.170 ;
        RECT 46.450 77.500 46.620 77.670 ;
        RECT 46.950 77.500 47.120 77.670 ;
        RECT 47.450 77.500 47.620 77.670 ;
        RECT 47.950 77.500 48.120 77.670 ;
        RECT 48.450 77.500 48.620 77.670 ;
        RECT 48.950 77.500 49.120 77.670 ;
        RECT 54.890 80.000 55.060 80.170 ;
        RECT 55.390 80.000 55.560 80.170 ;
        RECT 55.890 80.000 56.060 80.170 ;
        RECT 56.390 80.000 56.560 80.170 ;
        RECT 56.890 80.000 57.060 80.170 ;
        RECT 57.390 80.000 57.560 80.170 ;
        RECT 54.890 79.500 55.060 79.670 ;
        RECT 55.390 79.500 55.560 79.670 ;
        RECT 55.890 79.500 56.060 79.670 ;
        RECT 56.390 79.500 56.560 79.670 ;
        RECT 56.890 79.500 57.060 79.670 ;
        RECT 57.390 79.500 57.560 79.670 ;
        RECT 54.890 79.000 55.060 79.170 ;
        RECT 55.390 79.000 55.560 79.170 ;
        RECT 55.890 79.000 56.060 79.170 ;
        RECT 56.390 79.000 56.560 79.170 ;
        RECT 56.890 79.000 57.060 79.170 ;
        RECT 57.390 79.000 57.560 79.170 ;
        RECT 54.890 78.500 55.060 78.670 ;
        RECT 55.390 78.500 55.560 78.670 ;
        RECT 55.890 78.500 56.060 78.670 ;
        RECT 56.390 78.500 56.560 78.670 ;
        RECT 56.890 78.500 57.060 78.670 ;
        RECT 57.390 78.500 57.560 78.670 ;
        RECT 54.890 78.000 55.060 78.170 ;
        RECT 55.390 78.000 55.560 78.170 ;
        RECT 55.890 78.000 56.060 78.170 ;
        RECT 56.390 78.000 56.560 78.170 ;
        RECT 56.890 78.000 57.060 78.170 ;
        RECT 57.390 78.000 57.560 78.170 ;
        RECT 54.890 77.500 55.060 77.670 ;
        RECT 55.390 77.500 55.560 77.670 ;
        RECT 55.890 77.500 56.060 77.670 ;
        RECT 56.390 77.500 56.560 77.670 ;
        RECT 56.890 77.500 57.060 77.670 ;
        RECT 57.390 77.500 57.560 77.670 ;
        RECT 63.330 80.000 63.500 80.170 ;
        RECT 63.830 80.000 64.000 80.170 ;
        RECT 64.330 80.000 64.500 80.170 ;
        RECT 64.830 80.000 65.000 80.170 ;
        RECT 65.330 80.000 65.500 80.170 ;
        RECT 65.830 80.000 66.000 80.170 ;
        RECT 63.330 79.500 63.500 79.670 ;
        RECT 63.830 79.500 64.000 79.670 ;
        RECT 64.330 79.500 64.500 79.670 ;
        RECT 64.830 79.500 65.000 79.670 ;
        RECT 65.330 79.500 65.500 79.670 ;
        RECT 65.830 79.500 66.000 79.670 ;
        RECT 63.330 79.000 63.500 79.170 ;
        RECT 63.830 79.000 64.000 79.170 ;
        RECT 64.330 79.000 64.500 79.170 ;
        RECT 64.830 79.000 65.000 79.170 ;
        RECT 65.330 79.000 65.500 79.170 ;
        RECT 65.830 79.000 66.000 79.170 ;
        RECT 63.330 78.500 63.500 78.670 ;
        RECT 63.830 78.500 64.000 78.670 ;
        RECT 64.330 78.500 64.500 78.670 ;
        RECT 64.830 78.500 65.000 78.670 ;
        RECT 65.330 78.500 65.500 78.670 ;
        RECT 65.830 78.500 66.000 78.670 ;
        RECT 63.330 78.000 63.500 78.170 ;
        RECT 63.830 78.000 64.000 78.170 ;
        RECT 64.330 78.000 64.500 78.170 ;
        RECT 64.830 78.000 65.000 78.170 ;
        RECT 65.330 78.000 65.500 78.170 ;
        RECT 65.830 78.000 66.000 78.170 ;
        RECT 63.330 77.500 63.500 77.670 ;
        RECT 63.830 77.500 64.000 77.670 ;
        RECT 64.330 77.500 64.500 77.670 ;
        RECT 64.830 77.500 65.000 77.670 ;
        RECT 65.330 77.500 65.500 77.670 ;
        RECT 65.830 77.500 66.000 77.670 ;
        RECT 29.570 71.560 29.740 71.730 ;
        RECT 30.070 71.560 30.240 71.730 ;
        RECT 30.570 71.560 30.740 71.730 ;
        RECT 31.070 71.560 31.240 71.730 ;
        RECT 31.570 71.560 31.740 71.730 ;
        RECT 32.070 71.560 32.240 71.730 ;
        RECT 29.570 71.060 29.740 71.230 ;
        RECT 30.070 71.060 30.240 71.230 ;
        RECT 30.570 71.060 30.740 71.230 ;
        RECT 31.070 71.060 31.240 71.230 ;
        RECT 31.570 71.060 31.740 71.230 ;
        RECT 32.070 71.060 32.240 71.230 ;
        RECT 29.570 70.560 29.740 70.730 ;
        RECT 30.070 70.560 30.240 70.730 ;
        RECT 30.570 70.560 30.740 70.730 ;
        RECT 31.070 70.560 31.240 70.730 ;
        RECT 31.570 70.560 31.740 70.730 ;
        RECT 32.070 70.560 32.240 70.730 ;
        RECT 29.570 70.060 29.740 70.230 ;
        RECT 30.070 70.060 30.240 70.230 ;
        RECT 30.570 70.060 30.740 70.230 ;
        RECT 31.070 70.060 31.240 70.230 ;
        RECT 31.570 70.060 31.740 70.230 ;
        RECT 32.070 70.060 32.240 70.230 ;
        RECT 29.570 69.560 29.740 69.730 ;
        RECT 30.070 69.560 30.240 69.730 ;
        RECT 30.570 69.560 30.740 69.730 ;
        RECT 31.070 69.560 31.240 69.730 ;
        RECT 31.570 69.560 31.740 69.730 ;
        RECT 32.070 69.560 32.240 69.730 ;
        RECT 29.570 69.060 29.740 69.230 ;
        RECT 30.070 69.060 30.240 69.230 ;
        RECT 30.570 69.060 30.740 69.230 ;
        RECT 31.070 69.060 31.240 69.230 ;
        RECT 31.570 69.060 31.740 69.230 ;
        RECT 32.070 69.060 32.240 69.230 ;
        RECT 38.010 71.560 38.180 71.730 ;
        RECT 38.510 71.560 38.680 71.730 ;
        RECT 39.010 71.560 39.180 71.730 ;
        RECT 39.510 71.560 39.680 71.730 ;
        RECT 40.010 71.560 40.180 71.730 ;
        RECT 40.510 71.560 40.680 71.730 ;
        RECT 38.010 71.060 38.180 71.230 ;
        RECT 38.510 71.060 38.680 71.230 ;
        RECT 39.010 71.060 39.180 71.230 ;
        RECT 39.510 71.060 39.680 71.230 ;
        RECT 40.010 71.060 40.180 71.230 ;
        RECT 40.510 71.060 40.680 71.230 ;
        RECT 38.010 70.560 38.180 70.730 ;
        RECT 38.510 70.560 38.680 70.730 ;
        RECT 39.010 70.560 39.180 70.730 ;
        RECT 39.510 70.560 39.680 70.730 ;
        RECT 40.010 70.560 40.180 70.730 ;
        RECT 40.510 70.560 40.680 70.730 ;
        RECT 38.010 70.060 38.180 70.230 ;
        RECT 38.510 70.060 38.680 70.230 ;
        RECT 39.010 70.060 39.180 70.230 ;
        RECT 39.510 70.060 39.680 70.230 ;
        RECT 40.010 70.060 40.180 70.230 ;
        RECT 40.510 70.060 40.680 70.230 ;
        RECT 38.010 69.560 38.180 69.730 ;
        RECT 38.510 69.560 38.680 69.730 ;
        RECT 39.010 69.560 39.180 69.730 ;
        RECT 39.510 69.560 39.680 69.730 ;
        RECT 40.010 69.560 40.180 69.730 ;
        RECT 40.510 69.560 40.680 69.730 ;
        RECT 38.010 69.060 38.180 69.230 ;
        RECT 38.510 69.060 38.680 69.230 ;
        RECT 39.010 69.060 39.180 69.230 ;
        RECT 39.510 69.060 39.680 69.230 ;
        RECT 40.010 69.060 40.180 69.230 ;
        RECT 40.510 69.060 40.680 69.230 ;
        RECT 46.450 71.560 46.620 71.730 ;
        RECT 46.950 71.560 47.120 71.730 ;
        RECT 47.450 71.560 47.620 71.730 ;
        RECT 47.950 71.560 48.120 71.730 ;
        RECT 48.450 71.560 48.620 71.730 ;
        RECT 48.950 71.560 49.120 71.730 ;
        RECT 46.450 71.060 46.620 71.230 ;
        RECT 46.950 71.060 47.120 71.230 ;
        RECT 47.450 71.060 47.620 71.230 ;
        RECT 47.950 71.060 48.120 71.230 ;
        RECT 48.450 71.060 48.620 71.230 ;
        RECT 48.950 71.060 49.120 71.230 ;
        RECT 46.450 70.560 46.620 70.730 ;
        RECT 46.950 70.560 47.120 70.730 ;
        RECT 47.450 70.560 47.620 70.730 ;
        RECT 47.950 70.560 48.120 70.730 ;
        RECT 48.450 70.560 48.620 70.730 ;
        RECT 48.950 70.560 49.120 70.730 ;
        RECT 46.450 70.060 46.620 70.230 ;
        RECT 46.950 70.060 47.120 70.230 ;
        RECT 47.450 70.060 47.620 70.230 ;
        RECT 47.950 70.060 48.120 70.230 ;
        RECT 48.450 70.060 48.620 70.230 ;
        RECT 48.950 70.060 49.120 70.230 ;
        RECT 46.450 69.560 46.620 69.730 ;
        RECT 46.950 69.560 47.120 69.730 ;
        RECT 47.450 69.560 47.620 69.730 ;
        RECT 47.950 69.560 48.120 69.730 ;
        RECT 48.450 69.560 48.620 69.730 ;
        RECT 48.950 69.560 49.120 69.730 ;
        RECT 46.450 69.060 46.620 69.230 ;
        RECT 46.950 69.060 47.120 69.230 ;
        RECT 47.450 69.060 47.620 69.230 ;
        RECT 47.950 69.060 48.120 69.230 ;
        RECT 48.450 69.060 48.620 69.230 ;
        RECT 48.950 69.060 49.120 69.230 ;
        RECT 54.890 71.560 55.060 71.730 ;
        RECT 55.390 71.560 55.560 71.730 ;
        RECT 55.890 71.560 56.060 71.730 ;
        RECT 56.390 71.560 56.560 71.730 ;
        RECT 56.890 71.560 57.060 71.730 ;
        RECT 57.390 71.560 57.560 71.730 ;
        RECT 54.890 71.060 55.060 71.230 ;
        RECT 55.390 71.060 55.560 71.230 ;
        RECT 55.890 71.060 56.060 71.230 ;
        RECT 56.390 71.060 56.560 71.230 ;
        RECT 56.890 71.060 57.060 71.230 ;
        RECT 57.390 71.060 57.560 71.230 ;
        RECT 54.890 70.560 55.060 70.730 ;
        RECT 55.390 70.560 55.560 70.730 ;
        RECT 55.890 70.560 56.060 70.730 ;
        RECT 56.390 70.560 56.560 70.730 ;
        RECT 56.890 70.560 57.060 70.730 ;
        RECT 57.390 70.560 57.560 70.730 ;
        RECT 54.890 70.060 55.060 70.230 ;
        RECT 55.390 70.060 55.560 70.230 ;
        RECT 55.890 70.060 56.060 70.230 ;
        RECT 56.390 70.060 56.560 70.230 ;
        RECT 56.890 70.060 57.060 70.230 ;
        RECT 57.390 70.060 57.560 70.230 ;
        RECT 54.890 69.560 55.060 69.730 ;
        RECT 55.390 69.560 55.560 69.730 ;
        RECT 55.890 69.560 56.060 69.730 ;
        RECT 56.390 69.560 56.560 69.730 ;
        RECT 56.890 69.560 57.060 69.730 ;
        RECT 57.390 69.560 57.560 69.730 ;
        RECT 54.890 69.060 55.060 69.230 ;
        RECT 55.390 69.060 55.560 69.230 ;
        RECT 55.890 69.060 56.060 69.230 ;
        RECT 56.390 69.060 56.560 69.230 ;
        RECT 56.890 69.060 57.060 69.230 ;
        RECT 57.390 69.060 57.560 69.230 ;
        RECT 63.330 71.560 63.500 71.730 ;
        RECT 63.830 71.560 64.000 71.730 ;
        RECT 64.330 71.560 64.500 71.730 ;
        RECT 64.830 71.560 65.000 71.730 ;
        RECT 65.330 71.560 65.500 71.730 ;
        RECT 65.830 71.560 66.000 71.730 ;
        RECT 63.330 71.060 63.500 71.230 ;
        RECT 63.830 71.060 64.000 71.230 ;
        RECT 64.330 71.060 64.500 71.230 ;
        RECT 64.830 71.060 65.000 71.230 ;
        RECT 65.330 71.060 65.500 71.230 ;
        RECT 65.830 71.060 66.000 71.230 ;
        RECT 63.330 70.560 63.500 70.730 ;
        RECT 63.830 70.560 64.000 70.730 ;
        RECT 64.330 70.560 64.500 70.730 ;
        RECT 64.830 70.560 65.000 70.730 ;
        RECT 65.330 70.560 65.500 70.730 ;
        RECT 65.830 70.560 66.000 70.730 ;
        RECT 63.330 70.060 63.500 70.230 ;
        RECT 63.830 70.060 64.000 70.230 ;
        RECT 64.330 70.060 64.500 70.230 ;
        RECT 64.830 70.060 65.000 70.230 ;
        RECT 65.330 70.060 65.500 70.230 ;
        RECT 65.830 70.060 66.000 70.230 ;
        RECT 63.330 69.560 63.500 69.730 ;
        RECT 63.830 69.560 64.000 69.730 ;
        RECT 64.330 69.560 64.500 69.730 ;
        RECT 64.830 69.560 65.000 69.730 ;
        RECT 65.330 69.560 65.500 69.730 ;
        RECT 65.830 69.560 66.000 69.730 ;
        RECT 63.330 69.060 63.500 69.230 ;
        RECT 63.830 69.060 64.000 69.230 ;
        RECT 64.330 69.060 64.500 69.230 ;
        RECT 64.830 69.060 65.000 69.230 ;
        RECT 65.330 69.060 65.500 69.230 ;
        RECT 65.830 69.060 66.000 69.230 ;
        RECT 29.570 63.120 29.740 63.290 ;
        RECT 30.070 63.120 30.240 63.290 ;
        RECT 30.570 63.120 30.740 63.290 ;
        RECT 31.070 63.120 31.240 63.290 ;
        RECT 31.570 63.120 31.740 63.290 ;
        RECT 32.070 63.120 32.240 63.290 ;
        RECT 29.570 62.620 29.740 62.790 ;
        RECT 30.070 62.620 30.240 62.790 ;
        RECT 30.570 62.620 30.740 62.790 ;
        RECT 31.070 62.620 31.240 62.790 ;
        RECT 31.570 62.620 31.740 62.790 ;
        RECT 32.070 62.620 32.240 62.790 ;
        RECT 29.570 62.120 29.740 62.290 ;
        RECT 30.070 62.120 30.240 62.290 ;
        RECT 30.570 62.120 30.740 62.290 ;
        RECT 31.070 62.120 31.240 62.290 ;
        RECT 31.570 62.120 31.740 62.290 ;
        RECT 32.070 62.120 32.240 62.290 ;
        RECT 29.570 61.620 29.740 61.790 ;
        RECT 30.070 61.620 30.240 61.790 ;
        RECT 30.570 61.620 30.740 61.790 ;
        RECT 31.070 61.620 31.240 61.790 ;
        RECT 31.570 61.620 31.740 61.790 ;
        RECT 32.070 61.620 32.240 61.790 ;
        RECT 29.570 61.120 29.740 61.290 ;
        RECT 30.070 61.120 30.240 61.290 ;
        RECT 30.570 61.120 30.740 61.290 ;
        RECT 31.070 61.120 31.240 61.290 ;
        RECT 31.570 61.120 31.740 61.290 ;
        RECT 32.070 61.120 32.240 61.290 ;
        RECT 29.570 60.620 29.740 60.790 ;
        RECT 30.070 60.620 30.240 60.790 ;
        RECT 30.570 60.620 30.740 60.790 ;
        RECT 31.070 60.620 31.240 60.790 ;
        RECT 31.570 60.620 31.740 60.790 ;
        RECT 32.070 60.620 32.240 60.790 ;
        RECT 38.010 63.120 38.180 63.290 ;
        RECT 38.510 63.120 38.680 63.290 ;
        RECT 39.010 63.120 39.180 63.290 ;
        RECT 39.510 63.120 39.680 63.290 ;
        RECT 40.010 63.120 40.180 63.290 ;
        RECT 40.510 63.120 40.680 63.290 ;
        RECT 38.010 62.620 38.180 62.790 ;
        RECT 38.510 62.620 38.680 62.790 ;
        RECT 39.010 62.620 39.180 62.790 ;
        RECT 39.510 62.620 39.680 62.790 ;
        RECT 40.010 62.620 40.180 62.790 ;
        RECT 40.510 62.620 40.680 62.790 ;
        RECT 38.010 62.120 38.180 62.290 ;
        RECT 38.510 62.120 38.680 62.290 ;
        RECT 39.010 62.120 39.180 62.290 ;
        RECT 39.510 62.120 39.680 62.290 ;
        RECT 40.010 62.120 40.180 62.290 ;
        RECT 40.510 62.120 40.680 62.290 ;
        RECT 38.010 61.620 38.180 61.790 ;
        RECT 38.510 61.620 38.680 61.790 ;
        RECT 39.010 61.620 39.180 61.790 ;
        RECT 39.510 61.620 39.680 61.790 ;
        RECT 40.010 61.620 40.180 61.790 ;
        RECT 40.510 61.620 40.680 61.790 ;
        RECT 38.010 61.120 38.180 61.290 ;
        RECT 38.510 61.120 38.680 61.290 ;
        RECT 39.010 61.120 39.180 61.290 ;
        RECT 39.510 61.120 39.680 61.290 ;
        RECT 40.010 61.120 40.180 61.290 ;
        RECT 40.510 61.120 40.680 61.290 ;
        RECT 38.010 60.620 38.180 60.790 ;
        RECT 38.510 60.620 38.680 60.790 ;
        RECT 39.010 60.620 39.180 60.790 ;
        RECT 39.510 60.620 39.680 60.790 ;
        RECT 40.010 60.620 40.180 60.790 ;
        RECT 40.510 60.620 40.680 60.790 ;
        RECT 46.450 63.120 46.620 63.290 ;
        RECT 46.950 63.120 47.120 63.290 ;
        RECT 47.450 63.120 47.620 63.290 ;
        RECT 47.950 63.120 48.120 63.290 ;
        RECT 48.450 63.120 48.620 63.290 ;
        RECT 48.950 63.120 49.120 63.290 ;
        RECT 46.450 62.620 46.620 62.790 ;
        RECT 46.950 62.620 47.120 62.790 ;
        RECT 47.450 62.620 47.620 62.790 ;
        RECT 47.950 62.620 48.120 62.790 ;
        RECT 48.450 62.620 48.620 62.790 ;
        RECT 48.950 62.620 49.120 62.790 ;
        RECT 46.450 62.120 46.620 62.290 ;
        RECT 46.950 62.120 47.120 62.290 ;
        RECT 47.450 62.120 47.620 62.290 ;
        RECT 47.950 62.120 48.120 62.290 ;
        RECT 48.450 62.120 48.620 62.290 ;
        RECT 48.950 62.120 49.120 62.290 ;
        RECT 46.450 61.620 46.620 61.790 ;
        RECT 46.950 61.620 47.120 61.790 ;
        RECT 47.450 61.620 47.620 61.790 ;
        RECT 47.950 61.620 48.120 61.790 ;
        RECT 48.450 61.620 48.620 61.790 ;
        RECT 48.950 61.620 49.120 61.790 ;
        RECT 46.450 61.120 46.620 61.290 ;
        RECT 46.950 61.120 47.120 61.290 ;
        RECT 47.450 61.120 47.620 61.290 ;
        RECT 47.950 61.120 48.120 61.290 ;
        RECT 48.450 61.120 48.620 61.290 ;
        RECT 48.950 61.120 49.120 61.290 ;
        RECT 46.450 60.620 46.620 60.790 ;
        RECT 46.950 60.620 47.120 60.790 ;
        RECT 47.450 60.620 47.620 60.790 ;
        RECT 47.950 60.620 48.120 60.790 ;
        RECT 48.450 60.620 48.620 60.790 ;
        RECT 48.950 60.620 49.120 60.790 ;
        RECT 54.890 63.120 55.060 63.290 ;
        RECT 55.390 63.120 55.560 63.290 ;
        RECT 55.890 63.120 56.060 63.290 ;
        RECT 56.390 63.120 56.560 63.290 ;
        RECT 56.890 63.120 57.060 63.290 ;
        RECT 57.390 63.120 57.560 63.290 ;
        RECT 54.890 62.620 55.060 62.790 ;
        RECT 55.390 62.620 55.560 62.790 ;
        RECT 55.890 62.620 56.060 62.790 ;
        RECT 56.390 62.620 56.560 62.790 ;
        RECT 56.890 62.620 57.060 62.790 ;
        RECT 57.390 62.620 57.560 62.790 ;
        RECT 54.890 62.120 55.060 62.290 ;
        RECT 55.390 62.120 55.560 62.290 ;
        RECT 55.890 62.120 56.060 62.290 ;
        RECT 56.390 62.120 56.560 62.290 ;
        RECT 56.890 62.120 57.060 62.290 ;
        RECT 57.390 62.120 57.560 62.290 ;
        RECT 54.890 61.620 55.060 61.790 ;
        RECT 55.390 61.620 55.560 61.790 ;
        RECT 55.890 61.620 56.060 61.790 ;
        RECT 56.390 61.620 56.560 61.790 ;
        RECT 56.890 61.620 57.060 61.790 ;
        RECT 57.390 61.620 57.560 61.790 ;
        RECT 54.890 61.120 55.060 61.290 ;
        RECT 55.390 61.120 55.560 61.290 ;
        RECT 55.890 61.120 56.060 61.290 ;
        RECT 56.390 61.120 56.560 61.290 ;
        RECT 56.890 61.120 57.060 61.290 ;
        RECT 57.390 61.120 57.560 61.290 ;
        RECT 54.890 60.620 55.060 60.790 ;
        RECT 55.390 60.620 55.560 60.790 ;
        RECT 55.890 60.620 56.060 60.790 ;
        RECT 56.390 60.620 56.560 60.790 ;
        RECT 56.890 60.620 57.060 60.790 ;
        RECT 57.390 60.620 57.560 60.790 ;
        RECT 63.330 63.120 63.500 63.290 ;
        RECT 63.830 63.120 64.000 63.290 ;
        RECT 64.330 63.120 64.500 63.290 ;
        RECT 64.830 63.120 65.000 63.290 ;
        RECT 65.330 63.120 65.500 63.290 ;
        RECT 65.830 63.120 66.000 63.290 ;
        RECT 63.330 62.620 63.500 62.790 ;
        RECT 63.830 62.620 64.000 62.790 ;
        RECT 64.330 62.620 64.500 62.790 ;
        RECT 64.830 62.620 65.000 62.790 ;
        RECT 65.330 62.620 65.500 62.790 ;
        RECT 65.830 62.620 66.000 62.790 ;
        RECT 63.330 62.120 63.500 62.290 ;
        RECT 63.830 62.120 64.000 62.290 ;
        RECT 64.330 62.120 64.500 62.290 ;
        RECT 64.830 62.120 65.000 62.290 ;
        RECT 65.330 62.120 65.500 62.290 ;
        RECT 65.830 62.120 66.000 62.290 ;
        RECT 63.330 61.620 63.500 61.790 ;
        RECT 63.830 61.620 64.000 61.790 ;
        RECT 64.330 61.620 64.500 61.790 ;
        RECT 64.830 61.620 65.000 61.790 ;
        RECT 65.330 61.620 65.500 61.790 ;
        RECT 65.830 61.620 66.000 61.790 ;
        RECT 63.330 61.120 63.500 61.290 ;
        RECT 63.830 61.120 64.000 61.290 ;
        RECT 64.330 61.120 64.500 61.290 ;
        RECT 64.830 61.120 65.000 61.290 ;
        RECT 65.330 61.120 65.500 61.290 ;
        RECT 65.830 61.120 66.000 61.290 ;
        RECT 63.330 60.620 63.500 60.790 ;
        RECT 63.830 60.620 64.000 60.790 ;
        RECT 64.330 60.620 64.500 60.790 ;
        RECT 64.830 60.620 65.000 60.790 ;
        RECT 65.330 60.620 65.500 60.790 ;
        RECT 65.830 60.620 66.000 60.790 ;
        RECT 92.615 85.360 99.995 85.530 ;
        RECT 92.150 83.380 92.320 85.220 ;
        RECT 100.290 83.380 100.460 85.220 ;
        RECT 92.615 83.070 99.995 83.240 ;
        RECT 104.620 84.750 104.790 86.590 ;
        RECT 112.760 84.750 112.930 86.590 ;
        RECT 105.085 84.440 112.465 84.610 ;
        RECT 104.620 82.460 104.790 84.300 ;
        RECT 112.760 82.460 112.930 84.300 ;
        RECT 117.680 87.100 117.850 87.940 ;
        RECT 123.320 87.100 123.490 87.940 ;
        RECT 118.145 86.790 123.025 86.960 ;
        RECT 117.680 85.810 117.850 86.650 ;
        RECT 123.320 85.810 123.490 86.650 ;
        RECT 118.145 85.500 123.025 85.670 ;
        RECT 117.680 84.520 117.850 85.360 ;
        RECT 123.320 84.520 123.490 85.360 ;
        RECT 118.145 84.210 123.025 84.380 ;
        RECT 117.680 83.230 117.850 84.070 ;
        RECT 123.320 83.230 123.490 84.070 ;
        RECT 118.145 82.920 123.025 83.090 ;
        RECT 125.165 88.080 130.045 88.250 ;
        RECT 124.700 87.100 124.870 87.940 ;
        RECT 130.340 87.100 130.510 87.940 ;
        RECT 125.165 86.790 130.045 86.960 ;
        RECT 124.700 85.810 124.870 86.650 ;
        RECT 130.340 85.810 130.510 86.650 ;
        RECT 125.165 85.500 130.045 85.670 ;
        RECT 124.700 84.520 124.870 85.360 ;
        RECT 130.340 84.520 130.510 85.360 ;
        RECT 125.165 84.210 130.045 84.380 ;
        RECT 124.700 83.230 124.870 84.070 ;
        RECT 130.340 83.230 130.510 84.070 ;
        RECT 125.165 82.920 130.045 83.090 ;
        RECT 139.740 88.255 154.620 88.425 ;
        RECT 139.275 87.775 139.445 88.115 ;
        RECT 154.915 87.775 155.085 88.115 ;
        RECT 139.740 87.465 154.620 87.635 ;
        RECT 139.275 86.985 139.445 87.325 ;
        RECT 154.915 86.985 155.085 87.325 ;
        RECT 139.740 86.675 154.620 86.845 ;
        RECT 139.275 86.195 139.445 86.535 ;
        RECT 154.915 86.195 155.085 86.535 ;
        RECT 139.740 85.885 154.620 86.055 ;
        RECT 139.275 85.405 139.445 85.745 ;
        RECT 154.915 85.405 155.085 85.745 ;
        RECT 139.740 85.095 154.620 85.265 ;
        RECT 139.275 84.615 139.445 84.955 ;
        RECT 154.915 84.615 155.085 84.955 ;
        RECT 139.740 84.305 154.620 84.475 ;
        RECT 139.275 83.825 139.445 84.165 ;
        RECT 154.915 83.825 155.085 84.165 ;
        RECT 139.740 83.515 154.620 83.685 ;
        RECT 139.275 83.035 139.445 83.375 ;
        RECT 154.915 83.035 155.085 83.375 ;
        RECT 139.740 82.725 154.620 82.895 ;
        RECT 105.085 82.150 112.465 82.320 ;
        RECT 162.900 88.080 163.240 88.250 ;
        RECT 163.690 88.080 164.030 88.250 ;
        RECT 164.480 88.080 164.820 88.250 ;
        RECT 165.270 88.080 165.610 88.250 ;
        RECT 166.060 88.080 166.400 88.250 ;
        RECT 166.850 88.080 167.190 88.250 ;
        RECT 167.640 88.080 167.980 88.250 ;
        RECT 168.430 88.080 168.770 88.250 ;
        RECT 169.220 88.080 169.560 88.250 ;
        RECT 170.010 88.080 170.350 88.250 ;
        RECT 118.115 78.885 122.995 79.055 ;
        RECT 91.195 78.220 101.075 78.390 ;
        RECT 90.730 77.240 90.900 78.080 ;
        RECT 101.370 77.240 101.540 78.080 ;
        RECT 91.195 76.930 101.075 77.100 ;
        RECT 90.730 75.950 90.900 76.790 ;
        RECT 101.370 75.950 101.540 76.790 ;
        RECT 91.195 75.640 101.075 75.810 ;
        RECT 103.215 78.220 113.095 78.390 ;
        RECT 102.750 77.240 102.920 78.080 ;
        RECT 113.390 77.240 113.560 78.080 ;
        RECT 103.215 76.930 113.095 77.100 ;
        RECT 102.750 75.950 102.920 76.790 ;
        RECT 113.390 75.950 113.560 76.790 ;
        RECT 103.215 75.640 113.095 75.810 ;
        RECT 117.650 78.405 117.820 78.745 ;
        RECT 123.290 78.405 123.460 78.745 ;
        RECT 118.115 78.095 122.995 78.265 ;
        RECT 117.650 77.615 117.820 77.955 ;
        RECT 123.290 77.615 123.460 77.955 ;
        RECT 118.115 77.305 122.995 77.475 ;
        RECT 117.650 76.825 117.820 77.165 ;
        RECT 123.290 76.825 123.460 77.165 ;
        RECT 118.115 76.515 122.995 76.685 ;
        RECT 117.650 76.035 117.820 76.375 ;
        RECT 123.290 76.035 123.460 76.375 ;
        RECT 118.115 75.725 122.995 75.895 ;
        RECT 125.135 78.885 130.015 79.055 ;
        RECT 124.670 78.405 124.840 78.745 ;
        RECT 130.310 78.405 130.480 78.745 ;
        RECT 125.135 78.095 130.015 78.265 ;
        RECT 124.670 77.615 124.840 77.955 ;
        RECT 130.310 77.615 130.480 77.955 ;
        RECT 125.135 77.305 130.015 77.475 ;
        RECT 124.670 76.825 124.840 77.165 ;
        RECT 130.310 76.825 130.480 77.165 ;
        RECT 125.135 76.515 130.015 76.685 ;
        RECT 124.670 76.035 124.840 76.375 ;
        RECT 130.310 76.035 130.480 76.375 ;
        RECT 125.135 75.725 130.015 75.895 ;
        RECT 139.740 81.385 154.620 81.555 ;
        RECT 139.275 80.905 139.445 81.245 ;
        RECT 154.915 80.905 155.085 81.245 ;
        RECT 139.740 80.595 154.620 80.765 ;
        RECT 139.275 80.115 139.445 80.455 ;
        RECT 154.915 80.115 155.085 80.455 ;
        RECT 139.740 79.805 154.620 79.975 ;
        RECT 139.275 79.325 139.445 79.665 ;
        RECT 154.915 79.325 155.085 79.665 ;
        RECT 139.740 79.015 154.620 79.185 ;
        RECT 139.275 78.535 139.445 78.875 ;
        RECT 154.915 78.535 155.085 78.875 ;
        RECT 139.740 78.225 154.620 78.395 ;
        RECT 139.275 77.745 139.445 78.085 ;
        RECT 154.915 77.745 155.085 78.085 ;
        RECT 139.740 77.435 154.620 77.605 ;
        RECT 139.275 76.955 139.445 77.295 ;
        RECT 154.915 76.955 155.085 77.295 ;
        RECT 139.740 76.645 154.620 76.815 ;
        RECT 139.275 76.165 139.445 76.505 ;
        RECT 154.915 76.165 155.085 76.505 ;
        RECT 139.740 75.855 154.620 76.025 ;
        RECT 126.315 73.230 128.300 73.420 ;
        RECT 126.315 72.400 128.300 72.590 ;
        RECT 102.445 69.120 112.325 69.290 ;
        RECT 92.125 66.440 93.005 66.610 ;
        RECT 91.660 65.460 91.830 66.300 ;
        RECT 93.300 65.460 93.470 66.300 ;
        RECT 92.125 65.150 93.005 65.320 ;
        RECT 95.145 66.440 96.025 66.610 ;
        RECT 94.680 65.460 94.850 66.300 ;
        RECT 96.320 65.460 96.490 66.300 ;
        RECT 101.980 68.140 102.150 68.980 ;
        RECT 112.620 68.140 112.790 68.980 ;
        RECT 102.445 67.830 112.325 68.000 ;
        RECT 101.980 66.850 102.150 67.690 ;
        RECT 112.620 66.850 112.790 67.690 ;
        RECT 102.445 66.540 112.325 66.710 ;
        RECT 95.145 65.150 96.025 65.320 ;
        RECT 101.980 65.560 102.150 66.400 ;
        RECT 112.620 65.560 112.790 66.400 ;
        RECT 102.445 65.250 112.325 65.420 ;
        RECT 101.980 64.270 102.150 65.110 ;
        RECT 112.620 64.270 112.790 65.110 ;
        RECT 102.445 63.960 112.325 64.130 ;
        RECT 101.980 62.980 102.150 63.820 ;
        RECT 112.620 62.980 112.790 63.820 ;
        RECT 102.445 62.670 112.325 62.840 ;
        RECT 101.980 61.690 102.150 62.530 ;
        RECT 112.620 61.690 112.790 62.530 ;
        RECT 102.445 61.380 112.325 61.550 ;
        RECT 114.465 69.120 124.345 69.290 ;
        RECT 114.000 68.140 114.170 68.980 ;
        RECT 124.640 68.140 124.810 68.980 ;
        RECT 114.465 67.830 124.345 68.000 ;
        RECT 114.000 66.850 114.170 67.690 ;
        RECT 124.640 66.850 124.810 67.690 ;
        RECT 114.465 66.540 124.345 66.710 ;
        RECT 114.000 65.560 114.170 66.400 ;
        RECT 124.640 65.560 124.810 66.400 ;
        RECT 114.465 65.250 124.345 65.420 ;
        RECT 114.000 64.270 114.170 65.110 ;
        RECT 124.640 64.270 124.810 65.110 ;
        RECT 114.465 63.960 124.345 64.130 ;
        RECT 114.000 62.980 114.170 63.820 ;
        RECT 124.640 62.980 124.810 63.820 ;
        RECT 114.465 62.670 124.345 62.840 ;
        RECT 114.000 61.690 114.170 62.530 ;
        RECT 124.640 61.690 124.810 62.530 ;
        RECT 114.465 61.380 124.345 61.550 ;
        RECT 152.995 71.700 156.875 71.870 ;
        RECT 132.485 69.310 147.365 69.480 ;
        RECT 132.020 68.830 132.190 69.170 ;
        RECT 147.660 68.830 147.830 69.170 ;
        RECT 132.485 68.520 147.365 68.690 ;
        RECT 132.020 68.040 132.190 68.380 ;
        RECT 147.660 68.040 147.830 68.380 ;
        RECT 132.485 67.730 147.365 67.900 ;
        RECT 132.020 67.250 132.190 67.590 ;
        RECT 147.660 67.250 147.830 67.590 ;
        RECT 132.485 66.940 147.365 67.110 ;
        RECT 132.020 66.460 132.190 66.800 ;
        RECT 147.660 66.460 147.830 66.800 ;
        RECT 132.485 66.150 147.365 66.320 ;
        RECT 132.020 65.670 132.190 66.010 ;
        RECT 147.660 65.670 147.830 66.010 ;
        RECT 132.485 65.360 147.365 65.530 ;
        RECT 132.020 64.880 132.190 65.220 ;
        RECT 147.660 64.880 147.830 65.220 ;
        RECT 132.485 64.570 147.365 64.740 ;
        RECT 132.020 64.090 132.190 64.430 ;
        RECT 147.660 64.090 147.830 64.430 ;
        RECT 132.485 63.780 147.365 63.950 ;
        RECT 132.020 63.300 132.190 63.640 ;
        RECT 147.660 63.300 147.830 63.640 ;
        RECT 152.530 66.720 152.700 71.560 ;
        RECT 157.170 66.720 157.340 71.560 ;
        RECT 152.995 66.410 156.875 66.580 ;
        RECT 132.485 62.990 147.365 63.160 ;
        RECT 85.760 58.090 87.640 58.260 ;
        RECT 29.570 54.680 29.740 54.850 ;
        RECT 30.070 54.680 30.240 54.850 ;
        RECT 30.570 54.680 30.740 54.850 ;
        RECT 31.070 54.680 31.240 54.850 ;
        RECT 31.570 54.680 31.740 54.850 ;
        RECT 32.070 54.680 32.240 54.850 ;
        RECT 29.570 54.180 29.740 54.350 ;
        RECT 30.070 54.180 30.240 54.350 ;
        RECT 30.570 54.180 30.740 54.350 ;
        RECT 31.070 54.180 31.240 54.350 ;
        RECT 31.570 54.180 31.740 54.350 ;
        RECT 32.070 54.180 32.240 54.350 ;
        RECT 29.570 53.680 29.740 53.850 ;
        RECT 30.070 53.680 30.240 53.850 ;
        RECT 30.570 53.680 30.740 53.850 ;
        RECT 31.070 53.680 31.240 53.850 ;
        RECT 31.570 53.680 31.740 53.850 ;
        RECT 32.070 53.680 32.240 53.850 ;
        RECT 29.570 53.180 29.740 53.350 ;
        RECT 30.070 53.180 30.240 53.350 ;
        RECT 30.570 53.180 30.740 53.350 ;
        RECT 31.070 53.180 31.240 53.350 ;
        RECT 31.570 53.180 31.740 53.350 ;
        RECT 32.070 53.180 32.240 53.350 ;
        RECT 29.570 52.680 29.740 52.850 ;
        RECT 30.070 52.680 30.240 52.850 ;
        RECT 30.570 52.680 30.740 52.850 ;
        RECT 31.070 52.680 31.240 52.850 ;
        RECT 31.570 52.680 31.740 52.850 ;
        RECT 32.070 52.680 32.240 52.850 ;
        RECT 29.570 52.180 29.740 52.350 ;
        RECT 30.070 52.180 30.240 52.350 ;
        RECT 30.570 52.180 30.740 52.350 ;
        RECT 31.070 52.180 31.240 52.350 ;
        RECT 31.570 52.180 31.740 52.350 ;
        RECT 32.070 52.180 32.240 52.350 ;
        RECT 38.010 54.680 38.180 54.850 ;
        RECT 38.510 54.680 38.680 54.850 ;
        RECT 39.010 54.680 39.180 54.850 ;
        RECT 39.510 54.680 39.680 54.850 ;
        RECT 40.010 54.680 40.180 54.850 ;
        RECT 40.510 54.680 40.680 54.850 ;
        RECT 38.010 54.180 38.180 54.350 ;
        RECT 38.510 54.180 38.680 54.350 ;
        RECT 39.010 54.180 39.180 54.350 ;
        RECT 39.510 54.180 39.680 54.350 ;
        RECT 40.010 54.180 40.180 54.350 ;
        RECT 40.510 54.180 40.680 54.350 ;
        RECT 38.010 53.680 38.180 53.850 ;
        RECT 38.510 53.680 38.680 53.850 ;
        RECT 39.010 53.680 39.180 53.850 ;
        RECT 39.510 53.680 39.680 53.850 ;
        RECT 40.010 53.680 40.180 53.850 ;
        RECT 40.510 53.680 40.680 53.850 ;
        RECT 38.010 53.180 38.180 53.350 ;
        RECT 38.510 53.180 38.680 53.350 ;
        RECT 39.010 53.180 39.180 53.350 ;
        RECT 39.510 53.180 39.680 53.350 ;
        RECT 40.010 53.180 40.180 53.350 ;
        RECT 40.510 53.180 40.680 53.350 ;
        RECT 38.010 52.680 38.180 52.850 ;
        RECT 38.510 52.680 38.680 52.850 ;
        RECT 39.010 52.680 39.180 52.850 ;
        RECT 39.510 52.680 39.680 52.850 ;
        RECT 40.010 52.680 40.180 52.850 ;
        RECT 40.510 52.680 40.680 52.850 ;
        RECT 38.010 52.180 38.180 52.350 ;
        RECT 38.510 52.180 38.680 52.350 ;
        RECT 39.010 52.180 39.180 52.350 ;
        RECT 39.510 52.180 39.680 52.350 ;
        RECT 40.010 52.180 40.180 52.350 ;
        RECT 40.510 52.180 40.680 52.350 ;
        RECT 46.450 54.680 46.620 54.850 ;
        RECT 46.950 54.680 47.120 54.850 ;
        RECT 47.450 54.680 47.620 54.850 ;
        RECT 47.950 54.680 48.120 54.850 ;
        RECT 48.450 54.680 48.620 54.850 ;
        RECT 48.950 54.680 49.120 54.850 ;
        RECT 46.450 54.180 46.620 54.350 ;
        RECT 46.950 54.180 47.120 54.350 ;
        RECT 47.450 54.180 47.620 54.350 ;
        RECT 47.950 54.180 48.120 54.350 ;
        RECT 48.450 54.180 48.620 54.350 ;
        RECT 48.950 54.180 49.120 54.350 ;
        RECT 46.450 53.680 46.620 53.850 ;
        RECT 46.950 53.680 47.120 53.850 ;
        RECT 47.450 53.680 47.620 53.850 ;
        RECT 47.950 53.680 48.120 53.850 ;
        RECT 48.450 53.680 48.620 53.850 ;
        RECT 48.950 53.680 49.120 53.850 ;
        RECT 46.450 53.180 46.620 53.350 ;
        RECT 46.950 53.180 47.120 53.350 ;
        RECT 47.450 53.180 47.620 53.350 ;
        RECT 47.950 53.180 48.120 53.350 ;
        RECT 48.450 53.180 48.620 53.350 ;
        RECT 48.950 53.180 49.120 53.350 ;
        RECT 46.450 52.680 46.620 52.850 ;
        RECT 46.950 52.680 47.120 52.850 ;
        RECT 47.450 52.680 47.620 52.850 ;
        RECT 47.950 52.680 48.120 52.850 ;
        RECT 48.450 52.680 48.620 52.850 ;
        RECT 48.950 52.680 49.120 52.850 ;
        RECT 46.450 52.180 46.620 52.350 ;
        RECT 46.950 52.180 47.120 52.350 ;
        RECT 47.450 52.180 47.620 52.350 ;
        RECT 47.950 52.180 48.120 52.350 ;
        RECT 48.450 52.180 48.620 52.350 ;
        RECT 48.950 52.180 49.120 52.350 ;
        RECT 54.890 54.680 55.060 54.850 ;
        RECT 55.390 54.680 55.560 54.850 ;
        RECT 55.890 54.680 56.060 54.850 ;
        RECT 56.390 54.680 56.560 54.850 ;
        RECT 56.890 54.680 57.060 54.850 ;
        RECT 57.390 54.680 57.560 54.850 ;
        RECT 54.890 54.180 55.060 54.350 ;
        RECT 55.390 54.180 55.560 54.350 ;
        RECT 55.890 54.180 56.060 54.350 ;
        RECT 56.390 54.180 56.560 54.350 ;
        RECT 56.890 54.180 57.060 54.350 ;
        RECT 57.390 54.180 57.560 54.350 ;
        RECT 54.890 53.680 55.060 53.850 ;
        RECT 55.390 53.680 55.560 53.850 ;
        RECT 55.890 53.680 56.060 53.850 ;
        RECT 56.390 53.680 56.560 53.850 ;
        RECT 56.890 53.680 57.060 53.850 ;
        RECT 57.390 53.680 57.560 53.850 ;
        RECT 54.890 53.180 55.060 53.350 ;
        RECT 55.390 53.180 55.560 53.350 ;
        RECT 55.890 53.180 56.060 53.350 ;
        RECT 56.390 53.180 56.560 53.350 ;
        RECT 56.890 53.180 57.060 53.350 ;
        RECT 57.390 53.180 57.560 53.350 ;
        RECT 54.890 52.680 55.060 52.850 ;
        RECT 55.390 52.680 55.560 52.850 ;
        RECT 55.890 52.680 56.060 52.850 ;
        RECT 56.390 52.680 56.560 52.850 ;
        RECT 56.890 52.680 57.060 52.850 ;
        RECT 57.390 52.680 57.560 52.850 ;
        RECT 54.890 52.180 55.060 52.350 ;
        RECT 55.390 52.180 55.560 52.350 ;
        RECT 55.890 52.180 56.060 52.350 ;
        RECT 56.390 52.180 56.560 52.350 ;
        RECT 56.890 52.180 57.060 52.350 ;
        RECT 57.390 52.180 57.560 52.350 ;
        RECT 63.330 54.680 63.500 54.850 ;
        RECT 63.830 54.680 64.000 54.850 ;
        RECT 64.330 54.680 64.500 54.850 ;
        RECT 64.830 54.680 65.000 54.850 ;
        RECT 65.330 54.680 65.500 54.850 ;
        RECT 65.830 54.680 66.000 54.850 ;
        RECT 63.330 54.180 63.500 54.350 ;
        RECT 63.830 54.180 64.000 54.350 ;
        RECT 64.330 54.180 64.500 54.350 ;
        RECT 64.830 54.180 65.000 54.350 ;
        RECT 65.330 54.180 65.500 54.350 ;
        RECT 65.830 54.180 66.000 54.350 ;
        RECT 63.330 53.680 63.500 53.850 ;
        RECT 63.830 53.680 64.000 53.850 ;
        RECT 64.330 53.680 64.500 53.850 ;
        RECT 64.830 53.680 65.000 53.850 ;
        RECT 65.330 53.680 65.500 53.850 ;
        RECT 65.830 53.680 66.000 53.850 ;
        RECT 63.330 53.180 63.500 53.350 ;
        RECT 63.830 53.180 64.000 53.350 ;
        RECT 64.330 53.180 64.500 53.350 ;
        RECT 64.830 53.180 65.000 53.350 ;
        RECT 65.330 53.180 65.500 53.350 ;
        RECT 65.830 53.180 66.000 53.350 ;
        RECT 63.330 52.680 63.500 52.850 ;
        RECT 63.830 52.680 64.000 52.850 ;
        RECT 64.330 52.680 64.500 52.850 ;
        RECT 64.830 52.680 65.000 52.850 ;
        RECT 65.330 52.680 65.500 52.850 ;
        RECT 65.830 52.680 66.000 52.850 ;
        RECT 63.330 52.180 63.500 52.350 ;
        RECT 63.830 52.180 64.000 52.350 ;
        RECT 64.330 52.180 64.500 52.350 ;
        RECT 64.830 52.180 65.000 52.350 ;
        RECT 65.330 52.180 65.500 52.350 ;
        RECT 65.830 52.180 66.000 52.350 ;
        RECT 85.340 53.110 85.510 57.950 ;
        RECT 87.890 53.110 88.060 57.950 ;
        RECT 91.680 57.950 96.560 58.120 ;
        RECT 91.260 57.470 91.430 57.810 ;
        RECT 96.810 57.470 96.980 57.810 ;
        RECT 91.680 57.160 96.560 57.330 ;
        RECT 98.610 57.950 103.490 58.120 ;
        RECT 98.190 57.470 98.360 57.810 ;
        RECT 103.740 57.470 103.910 57.810 ;
        RECT 98.610 57.160 103.490 57.330 ;
        RECT 109.430 58.110 119.290 58.320 ;
        RECT 108.950 56.610 109.120 57.950 ;
        RECT 119.500 56.610 119.670 57.950 ;
        RECT 109.370 56.300 119.250 56.470 ;
        RECT 108.950 54.820 109.120 56.160 ;
        RECT 119.500 54.820 119.670 56.160 ;
        RECT 85.760 52.800 87.640 52.970 ;
        RECT 95.140 54.050 96.520 54.220 ;
        RECT 94.720 52.570 94.890 53.910 ;
        RECT 96.770 52.570 96.940 53.910 ;
        RECT 95.140 52.260 96.520 52.430 ;
        RECT 98.570 54.050 99.950 54.220 ;
        RECT 98.150 52.570 98.320 53.910 ;
        RECT 100.200 52.570 100.370 53.910 ;
        RECT 98.570 52.260 99.950 52.430 ;
        RECT 109.370 54.510 119.250 54.680 ;
        RECT 108.950 53.030 109.120 54.370 ;
        RECT 119.500 53.030 119.670 54.370 ;
        RECT 109.370 52.720 119.250 52.890 ;
        RECT 108.950 51.240 109.120 52.580 ;
        RECT 119.500 51.240 119.670 52.580 ;
        RECT 109.370 50.930 119.250 51.100 ;
        RECT 120.880 56.610 121.050 57.950 ;
        RECT 131.430 56.610 131.600 57.950 ;
        RECT 121.300 56.300 131.180 56.470 ;
        RECT 120.880 54.820 121.050 56.160 ;
        RECT 131.430 54.820 131.600 56.160 ;
        RECT 121.300 54.510 131.180 54.680 ;
        RECT 120.880 53.030 121.050 54.370 ;
        RECT 131.430 53.030 131.600 54.370 ;
        RECT 121.300 52.720 131.180 52.890 ;
        RECT 120.880 51.240 121.050 52.580 ;
        RECT 131.430 51.240 131.600 52.580 ;
        RECT 136.990 57.410 138.370 57.580 ;
        RECT 136.570 52.430 136.740 57.270 ;
        RECT 138.620 52.430 138.790 57.270 ;
        RECT 144.420 57.550 154.300 57.720 ;
        RECT 144.000 57.070 144.170 57.410 ;
        RECT 154.550 57.070 154.720 57.410 ;
        RECT 144.420 56.760 154.300 56.930 ;
        RECT 144.000 56.280 144.170 56.620 ;
        RECT 154.550 56.280 154.720 56.620 ;
        RECT 144.420 55.970 154.300 56.140 ;
        RECT 144.000 55.490 144.170 55.830 ;
        RECT 154.550 55.490 154.720 55.830 ;
        RECT 144.420 55.180 154.300 55.350 ;
        RECT 144.000 54.700 144.170 55.040 ;
        RECT 154.550 54.700 154.720 55.040 ;
        RECT 144.420 54.390 154.300 54.560 ;
        RECT 162.590 57.905 162.760 87.785 ;
        RECT 163.380 57.905 163.550 87.785 ;
        RECT 164.170 57.905 164.340 87.785 ;
        RECT 164.960 57.905 165.130 87.785 ;
        RECT 165.750 57.905 165.920 87.785 ;
        RECT 166.540 57.905 166.710 87.785 ;
        RECT 167.330 57.905 167.500 87.785 ;
        RECT 168.120 57.905 168.290 87.785 ;
        RECT 168.910 57.905 169.080 87.785 ;
        RECT 169.700 57.905 169.870 87.785 ;
        RECT 170.490 57.905 170.660 87.785 ;
        RECT 162.900 57.440 163.240 57.610 ;
        RECT 163.690 57.440 164.030 57.610 ;
        RECT 164.480 57.440 164.820 57.610 ;
        RECT 165.270 57.440 165.610 57.610 ;
        RECT 166.060 57.440 166.400 57.610 ;
        RECT 166.850 57.440 167.190 57.610 ;
        RECT 167.640 57.440 167.980 57.610 ;
        RECT 168.430 57.440 168.770 57.610 ;
        RECT 169.220 57.440 169.560 57.610 ;
        RECT 170.010 57.440 170.350 57.610 ;
        RECT 136.990 52.120 138.370 52.290 ;
        RECT 164.870 52.360 165.210 52.530 ;
        RECT 165.660 52.360 166.000 52.530 ;
        RECT 166.450 52.360 166.790 52.530 ;
        RECT 167.240 52.360 167.580 52.530 ;
        RECT 168.030 52.360 168.370 52.530 ;
        RECT 121.300 50.930 131.180 51.100 ;
        RECT 149.620 51.050 159.500 51.220 ;
        RECT 149.200 50.570 149.370 50.910 ;
        RECT 159.750 50.570 159.920 50.910 ;
        RECT 149.620 50.260 159.500 50.430 ;
        RECT 149.200 49.780 149.370 50.120 ;
        RECT 159.750 49.780 159.920 50.120 ;
        RECT 149.620 49.470 159.500 49.640 ;
        RECT 149.200 48.990 149.370 49.330 ;
        RECT 159.750 48.990 159.920 49.330 ;
        RECT 149.620 48.680 159.500 48.850 ;
        RECT 149.200 48.200 149.370 48.540 ;
        RECT 159.750 48.200 159.920 48.540 ;
        RECT 149.620 47.890 159.500 48.060 ;
        RECT 29.570 46.240 29.740 46.410 ;
        RECT 30.070 46.240 30.240 46.410 ;
        RECT 30.570 46.240 30.740 46.410 ;
        RECT 31.070 46.240 31.240 46.410 ;
        RECT 31.570 46.240 31.740 46.410 ;
        RECT 32.070 46.240 32.240 46.410 ;
        RECT 29.570 45.740 29.740 45.910 ;
        RECT 30.070 45.740 30.240 45.910 ;
        RECT 30.570 45.740 30.740 45.910 ;
        RECT 31.070 45.740 31.240 45.910 ;
        RECT 31.570 45.740 31.740 45.910 ;
        RECT 32.070 45.740 32.240 45.910 ;
        RECT 29.570 45.240 29.740 45.410 ;
        RECT 30.070 45.240 30.240 45.410 ;
        RECT 30.570 45.240 30.740 45.410 ;
        RECT 31.070 45.240 31.240 45.410 ;
        RECT 31.570 45.240 31.740 45.410 ;
        RECT 32.070 45.240 32.240 45.410 ;
        RECT 29.570 44.740 29.740 44.910 ;
        RECT 30.070 44.740 30.240 44.910 ;
        RECT 30.570 44.740 30.740 44.910 ;
        RECT 31.070 44.740 31.240 44.910 ;
        RECT 31.570 44.740 31.740 44.910 ;
        RECT 32.070 44.740 32.240 44.910 ;
        RECT 29.570 44.240 29.740 44.410 ;
        RECT 30.070 44.240 30.240 44.410 ;
        RECT 30.570 44.240 30.740 44.410 ;
        RECT 31.070 44.240 31.240 44.410 ;
        RECT 31.570 44.240 31.740 44.410 ;
        RECT 32.070 44.240 32.240 44.410 ;
        RECT 29.570 43.740 29.740 43.910 ;
        RECT 30.070 43.740 30.240 43.910 ;
        RECT 30.570 43.740 30.740 43.910 ;
        RECT 31.070 43.740 31.240 43.910 ;
        RECT 31.570 43.740 31.740 43.910 ;
        RECT 32.070 43.740 32.240 43.910 ;
        RECT 38.010 46.240 38.180 46.410 ;
        RECT 38.510 46.240 38.680 46.410 ;
        RECT 39.010 46.240 39.180 46.410 ;
        RECT 39.510 46.240 39.680 46.410 ;
        RECT 40.010 46.240 40.180 46.410 ;
        RECT 40.510 46.240 40.680 46.410 ;
        RECT 38.010 45.740 38.180 45.910 ;
        RECT 38.510 45.740 38.680 45.910 ;
        RECT 39.010 45.740 39.180 45.910 ;
        RECT 39.510 45.740 39.680 45.910 ;
        RECT 40.010 45.740 40.180 45.910 ;
        RECT 40.510 45.740 40.680 45.910 ;
        RECT 38.010 45.240 38.180 45.410 ;
        RECT 38.510 45.240 38.680 45.410 ;
        RECT 39.010 45.240 39.180 45.410 ;
        RECT 39.510 45.240 39.680 45.410 ;
        RECT 40.010 45.240 40.180 45.410 ;
        RECT 40.510 45.240 40.680 45.410 ;
        RECT 38.010 44.740 38.180 44.910 ;
        RECT 38.510 44.740 38.680 44.910 ;
        RECT 39.010 44.740 39.180 44.910 ;
        RECT 39.510 44.740 39.680 44.910 ;
        RECT 40.010 44.740 40.180 44.910 ;
        RECT 40.510 44.740 40.680 44.910 ;
        RECT 38.010 44.240 38.180 44.410 ;
        RECT 38.510 44.240 38.680 44.410 ;
        RECT 39.010 44.240 39.180 44.410 ;
        RECT 39.510 44.240 39.680 44.410 ;
        RECT 40.010 44.240 40.180 44.410 ;
        RECT 40.510 44.240 40.680 44.410 ;
        RECT 38.010 43.740 38.180 43.910 ;
        RECT 38.510 43.740 38.680 43.910 ;
        RECT 39.010 43.740 39.180 43.910 ;
        RECT 39.510 43.740 39.680 43.910 ;
        RECT 40.010 43.740 40.180 43.910 ;
        RECT 40.510 43.740 40.680 43.910 ;
        RECT 46.450 46.240 46.620 46.410 ;
        RECT 46.950 46.240 47.120 46.410 ;
        RECT 47.450 46.240 47.620 46.410 ;
        RECT 47.950 46.240 48.120 46.410 ;
        RECT 48.450 46.240 48.620 46.410 ;
        RECT 48.950 46.240 49.120 46.410 ;
        RECT 46.450 45.740 46.620 45.910 ;
        RECT 46.950 45.740 47.120 45.910 ;
        RECT 47.450 45.740 47.620 45.910 ;
        RECT 47.950 45.740 48.120 45.910 ;
        RECT 48.450 45.740 48.620 45.910 ;
        RECT 48.950 45.740 49.120 45.910 ;
        RECT 46.450 45.240 46.620 45.410 ;
        RECT 46.950 45.240 47.120 45.410 ;
        RECT 47.450 45.240 47.620 45.410 ;
        RECT 47.950 45.240 48.120 45.410 ;
        RECT 48.450 45.240 48.620 45.410 ;
        RECT 48.950 45.240 49.120 45.410 ;
        RECT 46.450 44.740 46.620 44.910 ;
        RECT 46.950 44.740 47.120 44.910 ;
        RECT 47.450 44.740 47.620 44.910 ;
        RECT 47.950 44.740 48.120 44.910 ;
        RECT 48.450 44.740 48.620 44.910 ;
        RECT 48.950 44.740 49.120 44.910 ;
        RECT 46.450 44.240 46.620 44.410 ;
        RECT 46.950 44.240 47.120 44.410 ;
        RECT 47.450 44.240 47.620 44.410 ;
        RECT 47.950 44.240 48.120 44.410 ;
        RECT 48.450 44.240 48.620 44.410 ;
        RECT 48.950 44.240 49.120 44.410 ;
        RECT 46.450 43.740 46.620 43.910 ;
        RECT 46.950 43.740 47.120 43.910 ;
        RECT 47.450 43.740 47.620 43.910 ;
        RECT 47.950 43.740 48.120 43.910 ;
        RECT 48.450 43.740 48.620 43.910 ;
        RECT 48.950 43.740 49.120 43.910 ;
        RECT 54.890 46.240 55.060 46.410 ;
        RECT 55.390 46.240 55.560 46.410 ;
        RECT 55.890 46.240 56.060 46.410 ;
        RECT 56.390 46.240 56.560 46.410 ;
        RECT 56.890 46.240 57.060 46.410 ;
        RECT 57.390 46.240 57.560 46.410 ;
        RECT 54.890 45.740 55.060 45.910 ;
        RECT 55.390 45.740 55.560 45.910 ;
        RECT 55.890 45.740 56.060 45.910 ;
        RECT 56.390 45.740 56.560 45.910 ;
        RECT 56.890 45.740 57.060 45.910 ;
        RECT 57.390 45.740 57.560 45.910 ;
        RECT 54.890 45.240 55.060 45.410 ;
        RECT 55.390 45.240 55.560 45.410 ;
        RECT 55.890 45.240 56.060 45.410 ;
        RECT 56.390 45.240 56.560 45.410 ;
        RECT 56.890 45.240 57.060 45.410 ;
        RECT 57.390 45.240 57.560 45.410 ;
        RECT 54.890 44.740 55.060 44.910 ;
        RECT 55.390 44.740 55.560 44.910 ;
        RECT 55.890 44.740 56.060 44.910 ;
        RECT 56.390 44.740 56.560 44.910 ;
        RECT 56.890 44.740 57.060 44.910 ;
        RECT 57.390 44.740 57.560 44.910 ;
        RECT 54.890 44.240 55.060 44.410 ;
        RECT 55.390 44.240 55.560 44.410 ;
        RECT 55.890 44.240 56.060 44.410 ;
        RECT 56.390 44.240 56.560 44.410 ;
        RECT 56.890 44.240 57.060 44.410 ;
        RECT 57.390 44.240 57.560 44.410 ;
        RECT 54.890 43.740 55.060 43.910 ;
        RECT 55.390 43.740 55.560 43.910 ;
        RECT 55.890 43.740 56.060 43.910 ;
        RECT 56.390 43.740 56.560 43.910 ;
        RECT 56.890 43.740 57.060 43.910 ;
        RECT 57.390 43.740 57.560 43.910 ;
        RECT 63.330 46.240 63.500 46.410 ;
        RECT 63.830 46.240 64.000 46.410 ;
        RECT 64.330 46.240 64.500 46.410 ;
        RECT 64.830 46.240 65.000 46.410 ;
        RECT 65.330 46.240 65.500 46.410 ;
        RECT 65.830 46.240 66.000 46.410 ;
        RECT 63.330 45.740 63.500 45.910 ;
        RECT 63.830 45.740 64.000 45.910 ;
        RECT 64.330 45.740 64.500 45.910 ;
        RECT 64.830 45.740 65.000 45.910 ;
        RECT 65.330 45.740 65.500 45.910 ;
        RECT 65.830 45.740 66.000 45.910 ;
        RECT 63.330 45.240 63.500 45.410 ;
        RECT 63.830 45.240 64.000 45.410 ;
        RECT 64.330 45.240 64.500 45.410 ;
        RECT 64.830 45.240 65.000 45.410 ;
        RECT 65.330 45.240 65.500 45.410 ;
        RECT 65.830 45.240 66.000 45.410 ;
        RECT 63.330 44.740 63.500 44.910 ;
        RECT 63.830 44.740 64.000 44.910 ;
        RECT 64.330 44.740 64.500 44.910 ;
        RECT 64.830 44.740 65.000 44.910 ;
        RECT 65.330 44.740 65.500 44.910 ;
        RECT 65.830 44.740 66.000 44.910 ;
        RECT 63.330 44.240 63.500 44.410 ;
        RECT 63.830 44.240 64.000 44.410 ;
        RECT 64.330 44.240 64.500 44.410 ;
        RECT 64.830 44.240 65.000 44.410 ;
        RECT 65.330 44.240 65.500 44.410 ;
        RECT 65.830 44.240 66.000 44.410 ;
        RECT 63.330 43.740 63.500 43.910 ;
        RECT 63.830 43.740 64.000 43.910 ;
        RECT 64.330 43.740 64.500 43.910 ;
        RECT 64.830 43.740 65.000 43.910 ;
        RECT 65.330 43.740 65.500 43.910 ;
        RECT 65.830 43.740 66.000 43.910 ;
        RECT 117.000 46.380 119.380 46.550 ;
        RECT 116.580 44.900 116.750 46.240 ;
        RECT 119.630 44.900 119.800 46.240 ;
        RECT 117.000 44.590 119.380 44.760 ;
        RECT 121.430 46.380 123.810 46.550 ;
        RECT 121.010 44.900 121.180 46.240 ;
        RECT 124.060 44.900 124.230 46.240 ;
        RECT 121.430 44.590 123.810 44.760 ;
        RECT 149.620 46.530 159.500 46.700 ;
        RECT 149.200 46.050 149.370 46.390 ;
        RECT 159.750 46.050 159.920 46.390 ;
        RECT 149.620 45.740 159.500 45.910 ;
        RECT 149.200 45.260 149.370 45.600 ;
        RECT 159.750 45.260 159.920 45.600 ;
        RECT 149.620 44.950 159.500 45.120 ;
        RECT 149.200 44.470 149.370 44.810 ;
        RECT 159.750 44.470 159.920 44.810 ;
        RECT 149.620 44.160 159.500 44.330 ;
        RECT 149.200 43.680 149.370 44.020 ;
        RECT 159.750 43.680 159.920 44.020 ;
        RECT 149.620 43.370 159.500 43.540 ;
        RECT 158.260 42.190 159.160 42.530 ;
        RECT 164.560 32.230 164.730 52.110 ;
        RECT 165.350 32.230 165.520 52.110 ;
        RECT 166.140 32.230 166.310 52.110 ;
        RECT 166.930 32.230 167.100 52.110 ;
        RECT 167.720 32.230 167.890 52.110 ;
        RECT 168.510 32.230 168.680 52.110 ;
        RECT 164.870 31.810 165.210 31.980 ;
        RECT 165.660 31.810 166.000 31.980 ;
        RECT 166.450 31.810 166.790 31.980 ;
        RECT 167.240 31.810 167.580 31.980 ;
        RECT 168.030 31.810 168.370 31.980 ;
      LAYER met1 ;
        RECT 98.170 165.320 157.140 166.660 ;
        RECT 25.050 155.260 27.290 156.480 ;
        RECT 25.310 147.180 26.960 155.260 ;
        RECT 63.710 151.940 74.730 160.230 ;
        RECT 89.245 160.070 96.745 160.300 ;
        RECT 88.810 158.060 89.040 160.020 ;
        RECT 96.950 159.900 97.180 160.020 ;
        RECT 98.650 159.900 100.210 165.320 ;
        RECT 120.460 164.040 121.300 164.690 ;
        RECT 109.420 162.710 110.150 163.480 ;
        RECT 139.510 163.195 149.240 163.340 ;
        RECT 114.790 163.020 119.750 163.100 ;
        RECT 121.810 163.020 126.770 163.100 ;
        RECT 114.775 162.790 119.775 163.020 ;
        RECT 121.795 162.790 126.795 163.020 ;
        RECT 136.370 162.965 151.370 163.195 ;
        RECT 139.510 162.950 149.240 162.965 ;
        RECT 114.790 162.750 119.750 162.790 ;
        RECT 121.810 162.750 126.770 162.790 ;
        RECT 114.340 161.780 114.570 162.740 ;
        RECT 102.330 161.670 108.400 161.760 ;
        RECT 114.780 161.730 119.740 161.820 ;
        RECT 119.980 161.780 120.210 162.740 ;
        RECT 121.360 161.780 121.590 162.740 ;
        RECT 121.800 161.730 126.760 161.820 ;
        RECT 127.000 161.780 127.230 162.740 ;
        RECT 135.935 162.455 136.165 162.915 ;
        RECT 139.510 162.405 149.240 162.550 ;
        RECT 151.575 162.455 151.805 162.915 ;
        RECT 136.370 162.175 151.370 162.405 ;
        RECT 139.510 162.160 149.240 162.175 ;
        RECT 101.715 161.440 109.215 161.670 ;
        RECT 114.775 161.500 119.775 161.730 ;
        RECT 121.795 161.500 126.795 161.730 ;
        RECT 135.935 161.665 136.165 162.125 ;
        RECT 139.530 161.615 149.260 161.750 ;
        RECT 151.575 161.665 151.805 162.125 ;
        RECT 114.780 161.470 119.740 161.500 ;
        RECT 121.800 161.470 126.760 161.500 ;
        RECT 101.280 159.900 101.510 161.390 ;
        RECT 96.950 159.430 101.510 159.900 ;
        RECT 96.950 159.100 101.490 159.430 ;
        RECT 102.300 159.380 108.370 159.460 ;
        RECT 109.420 159.430 109.650 161.390 ;
        RECT 114.340 160.490 114.570 161.450 ;
        RECT 114.790 160.440 119.760 160.530 ;
        RECT 119.980 160.490 120.210 161.450 ;
        RECT 121.360 160.490 121.590 161.450 ;
        RECT 121.810 160.440 126.780 160.530 ;
        RECT 127.000 160.490 127.230 161.450 ;
        RECT 136.370 161.385 151.370 161.615 ;
        RECT 139.530 161.360 149.260 161.385 ;
        RECT 135.935 160.875 136.165 161.335 ;
        RECT 139.500 160.825 149.230 160.940 ;
        RECT 151.575 160.875 151.805 161.335 ;
        RECT 136.370 160.595 151.370 160.825 ;
        RECT 139.500 160.550 149.230 160.595 ;
        RECT 114.775 160.210 119.775 160.440 ;
        RECT 121.795 160.210 126.795 160.440 ;
        RECT 114.790 160.190 119.760 160.210 ;
        RECT 121.810 160.190 126.780 160.210 ;
        RECT 101.715 159.150 109.215 159.380 ;
        RECT 114.340 159.200 114.570 160.160 ;
        RECT 114.790 159.150 119.760 159.240 ;
        RECT 119.980 159.200 120.210 160.160 ;
        RECT 121.360 159.200 121.590 160.160 ;
        RECT 121.810 159.150 126.780 159.240 ;
        RECT 127.000 159.200 127.230 160.160 ;
        RECT 135.935 160.085 136.165 160.545 ;
        RECT 139.480 160.035 149.210 160.170 ;
        RECT 151.575 160.085 151.805 160.545 ;
        RECT 136.370 159.805 151.370 160.035 ;
        RECT 139.480 159.780 149.210 159.805 ;
        RECT 135.935 159.295 136.165 159.755 ;
        RECT 139.450 159.245 149.180 159.330 ;
        RECT 151.575 159.295 151.805 159.755 ;
        RECT 96.950 158.650 101.510 159.100 ;
        RECT 96.950 158.060 97.180 158.650 ;
        RECT 89.245 157.780 96.745 158.010 ;
        RECT 91.670 153.280 94.090 157.780 ;
        RECT 87.390 151.920 87.620 152.880 ;
        RECT 87.780 152.850 97.850 153.280 ;
        RECT 91.670 152.840 94.090 152.850 ;
        RECT 98.030 152.260 98.260 152.880 ;
        RECT 98.540 152.260 99.140 158.650 ;
        RECT 101.280 157.140 101.510 158.650 ;
        RECT 102.500 157.090 108.570 157.160 ;
        RECT 109.420 157.140 109.650 159.100 ;
        RECT 114.775 158.920 119.775 159.150 ;
        RECT 121.795 158.920 126.795 159.150 ;
        RECT 136.370 159.015 151.370 159.245 ;
        RECT 114.790 158.880 119.760 158.920 ;
        RECT 121.810 158.880 126.780 158.920 ;
        RECT 114.340 157.910 114.570 158.870 ;
        RECT 119.980 158.720 120.210 158.870 ;
        RECT 121.360 158.720 121.590 158.870 ;
        RECT 119.980 157.950 121.590 158.720 ;
        RECT 119.980 157.910 120.210 157.950 ;
        RECT 114.790 157.860 119.740 157.910 ;
        RECT 114.775 157.630 119.775 157.860 ;
        RECT 114.790 157.570 119.740 157.630 ;
        RECT 101.715 156.860 109.215 157.090 ;
        RECT 103.800 153.280 106.260 156.860 ;
        RECT 116.660 153.930 117.350 157.570 ;
        RECT 120.560 156.240 120.990 157.950 ;
        RECT 121.360 157.910 121.590 157.950 ;
        RECT 127.000 157.910 127.230 158.870 ;
        RECT 135.935 158.505 136.165 158.965 ;
        RECT 139.450 158.940 149.180 159.015 ;
        RECT 139.430 158.455 149.160 158.580 ;
        RECT 151.575 158.505 151.805 158.965 ;
        RECT 136.370 158.225 151.370 158.455 ;
        RECT 139.430 158.190 149.160 158.225 ;
        RECT 135.935 158.170 136.165 158.175 ;
        RECT 135.170 158.160 136.180 158.170 ;
        RECT 121.810 157.860 126.760 157.910 ;
        RECT 121.795 157.630 126.795 157.860 ;
        RECT 135.060 157.670 136.180 158.160 ;
        RECT 121.810 157.570 126.760 157.630 ;
        RECT 120.530 155.330 121.040 156.240 ;
        RECT 124.160 153.930 124.850 157.570 ;
        RECT 135.060 157.060 135.420 157.670 ;
        RECT 139.460 157.665 149.190 157.780 ;
        RECT 151.575 157.715 151.805 158.175 ;
        RECT 136.370 157.435 151.370 157.665 ;
        RECT 139.460 157.390 149.190 157.435 ;
        RECT 142.860 157.060 146.060 157.390 ;
        RECT 135.060 156.670 146.060 157.060 ;
        RECT 142.860 156.470 146.060 156.670 ;
        RECT 139.510 156.325 149.240 156.470 ;
        RECT 136.370 156.095 151.370 156.325 ;
        RECT 139.510 156.080 149.240 156.095 ;
        RECT 135.935 155.585 136.165 156.045 ;
        RECT 139.510 155.535 149.240 155.680 ;
        RECT 151.575 155.585 151.805 156.045 ;
        RECT 136.370 155.305 151.370 155.535 ;
        RECT 139.510 155.290 149.240 155.305 ;
        RECT 135.935 154.795 136.165 155.255 ;
        RECT 139.530 154.745 149.260 154.880 ;
        RECT 151.575 154.795 151.805 155.255 ;
        RECT 136.370 154.515 151.370 154.745 ;
        RECT 139.530 154.490 149.260 154.515 ;
        RECT 135.935 154.005 136.165 154.465 ;
        RECT 139.500 153.955 149.230 154.070 ;
        RECT 151.575 154.005 151.805 154.465 ;
        RECT 114.910 153.825 119.590 153.930 ;
        RECT 121.930 153.825 126.610 153.930 ;
        RECT 114.745 153.595 119.745 153.825 ;
        RECT 121.765 153.595 126.765 153.825 ;
        RECT 136.370 153.725 151.370 153.955 ;
        RECT 139.500 153.680 149.230 153.725 ;
        RECT 114.910 153.590 119.590 153.595 ;
        RECT 121.930 153.590 126.610 153.595 ;
        RECT 116.660 153.580 117.350 153.590 ;
        RECT 99.410 152.260 99.640 152.880 ;
        RECT 99.800 152.850 109.870 153.280 ;
        RECT 114.310 153.085 114.540 153.545 ;
        RECT 114.910 153.035 119.590 153.130 ;
        RECT 119.950 153.085 120.180 153.545 ;
        RECT 121.330 153.085 121.560 153.545 ;
        RECT 121.930 153.035 126.610 153.130 ;
        RECT 126.970 153.085 127.200 153.545 ;
        RECT 135.935 153.215 136.165 153.675 ;
        RECT 139.480 153.165 149.210 153.300 ;
        RECT 151.575 153.215 151.805 153.675 ;
        RECT 51.710 151.650 52.670 151.880 ;
        RECT 87.770 151.590 97.860 151.950 ;
        RECT 98.030 151.920 99.640 152.260 ;
        RECT 98.080 151.590 99.640 151.920 ;
        RECT 99.790 151.590 109.880 151.950 ;
        RECT 110.050 151.920 110.280 152.880 ;
        RECT 114.745 152.805 119.745 153.035 ;
        RECT 121.765 152.805 126.765 153.035 ;
        RECT 136.370 152.935 151.370 153.165 ;
        RECT 139.480 152.910 149.210 152.935 ;
        RECT 114.910 152.790 119.590 152.805 ;
        RECT 121.930 152.790 126.610 152.805 ;
        RECT 114.310 152.295 114.540 152.755 ;
        RECT 114.940 152.245 119.620 152.340 ;
        RECT 119.950 152.295 120.180 152.755 ;
        RECT 121.330 152.295 121.560 152.755 ;
        RECT 121.960 152.245 126.640 152.340 ;
        RECT 126.970 152.295 127.200 152.755 ;
        RECT 135.935 152.425 136.165 152.885 ;
        RECT 139.450 152.375 149.180 152.460 ;
        RECT 151.575 152.425 151.805 152.885 ;
        RECT 114.745 152.015 119.745 152.245 ;
        RECT 121.765 152.015 126.765 152.245 ;
        RECT 136.370 152.145 151.370 152.375 ;
        RECT 114.940 152.000 119.620 152.015 ;
        RECT 121.960 152.000 126.640 152.015 ;
        RECT 36.910 150.980 39.990 151.100 ;
        RECT 36.910 150.730 39.995 150.980 ;
        RECT 36.910 150.690 39.990 150.730 ;
        RECT 51.430 147.700 51.660 151.490 ;
        RECT 52.720 151.460 52.950 151.490 ;
        RECT 45.010 147.340 51.660 147.700 ;
        RECT 24.755 146.930 26.960 147.180 ;
        RECT 25.310 146.850 26.960 146.930 ;
        RECT 51.430 146.490 51.660 147.340 ;
        RECT 52.710 149.460 53.070 151.460 ;
        RECT 87.390 150.630 87.620 151.590 ;
        RECT 95.960 151.270 96.630 151.590 ;
        RECT 98.030 151.270 99.640 151.590 ;
        RECT 95.960 151.000 99.640 151.270 ;
        RECT 87.780 150.260 97.860 150.680 ;
        RECT 98.030 150.630 98.260 151.000 ;
        RECT 52.710 147.980 57.050 149.460 ;
        RECT 98.530 148.900 99.150 151.000 ;
        RECT 99.410 150.630 99.640 151.000 ;
        RECT 99.800 150.260 109.880 150.680 ;
        RECT 110.050 150.630 110.280 151.590 ;
        RECT 114.310 151.505 114.540 151.965 ;
        RECT 114.890 151.455 119.570 151.550 ;
        RECT 119.950 151.505 120.180 151.965 ;
        RECT 121.330 151.505 121.560 151.965 ;
        RECT 121.910 151.455 126.590 151.550 ;
        RECT 126.970 151.505 127.200 151.965 ;
        RECT 135.935 151.635 136.165 152.095 ;
        RECT 139.450 152.070 149.180 152.145 ;
        RECT 139.430 151.585 149.160 151.710 ;
        RECT 151.575 151.635 151.805 152.095 ;
        RECT 114.745 151.225 119.745 151.455 ;
        RECT 121.765 151.225 126.765 151.455 ;
        RECT 136.370 151.355 151.370 151.585 ;
        RECT 135.140 151.250 135.560 151.330 ;
        RECT 139.430 151.320 149.160 151.355 ;
        RECT 135.935 151.250 136.165 151.305 ;
        RECT 114.890 151.210 119.570 151.225 ;
        RECT 121.910 151.210 126.590 151.225 ;
        RECT 114.310 150.715 114.540 151.175 ;
        RECT 119.950 151.170 120.180 151.175 ;
        RECT 121.330 151.170 121.560 151.175 ;
        RECT 114.900 150.665 119.580 150.770 ;
        RECT 119.950 150.715 121.560 151.170 ;
        RECT 120.010 150.690 121.520 150.715 ;
        RECT 114.745 150.435 119.745 150.665 ;
        RECT 114.900 150.430 119.580 150.435 ;
        RECT 52.710 146.520 53.070 147.980 ;
        RECT 52.720 146.490 52.950 146.520 ;
        RECT 24.755 146.100 26.860 146.350 ;
        RECT 51.710 146.100 52.670 146.330 ;
        RECT 25.400 141.980 26.640 146.100 ;
        RECT 51.740 145.930 52.650 146.100 ;
        RECT 51.750 145.270 52.650 145.930 ;
        RECT 38.500 143.530 40.510 143.830 ;
        RECT 41.530 143.650 43.530 143.830 ;
        RECT 44.580 143.650 46.580 143.810 ;
        RECT 41.530 143.540 43.550 143.650 ;
        RECT 38.520 143.420 38.960 143.530 ;
        RECT 40.050 143.420 40.490 143.530 ;
        RECT 41.580 143.420 42.020 143.540 ;
        RECT 43.110 143.420 43.550 143.540 ;
        RECT 44.580 143.520 46.610 143.650 ;
        RECT 44.640 143.420 45.080 143.520 ;
        RECT 46.170 143.420 46.610 143.520 ;
        RECT 47.700 143.540 49.700 143.830 ;
        RECT 50.730 143.540 52.730 143.830 ;
        RECT 47.700 143.420 48.140 143.540 ;
        RECT 49.230 143.420 49.670 143.540 ;
        RECT 50.760 143.420 51.200 143.540 ;
        RECT 52.290 143.420 52.730 143.540 ;
        RECT 24.815 141.730 26.920 141.980 ;
        RECT 25.400 141.680 26.640 141.730 ;
        RECT 24.815 140.900 26.920 141.150 ;
        RECT 25.040 111.610 26.810 140.900 ;
        RECT 38.130 133.410 38.360 143.370 ;
        RECT 39.120 139.290 39.350 143.370 ;
        RECT 39.660 139.290 39.890 143.370 ;
        RECT 39.120 138.300 39.890 139.290 ;
        RECT 39.120 133.410 39.350 138.300 ;
        RECT 39.660 133.410 39.890 138.300 ;
        RECT 40.650 139.230 40.880 143.370 ;
        RECT 41.190 139.230 41.420 143.370 ;
        RECT 40.650 138.240 41.420 139.230 ;
        RECT 40.650 133.410 40.880 138.240 ;
        RECT 41.190 133.410 41.420 138.240 ;
        RECT 42.180 139.140 42.410 143.370 ;
        RECT 42.720 139.140 42.950 143.370 ;
        RECT 42.180 138.150 42.950 139.140 ;
        RECT 42.180 133.410 42.410 138.150 ;
        RECT 42.720 133.410 42.950 138.150 ;
        RECT 43.710 139.040 43.940 143.370 ;
        RECT 44.250 139.040 44.480 143.370 ;
        RECT 43.710 138.050 44.480 139.040 ;
        RECT 43.710 133.410 43.940 138.050 ;
        RECT 44.250 133.410 44.480 138.050 ;
        RECT 45.240 139.040 45.470 143.370 ;
        RECT 45.780 139.040 46.010 143.370 ;
        RECT 45.240 138.050 46.010 139.040 ;
        RECT 45.240 133.410 45.470 138.050 ;
        RECT 45.780 133.410 46.010 138.050 ;
        RECT 46.770 139.000 47.000 143.370 ;
        RECT 47.310 139.000 47.540 143.370 ;
        RECT 46.770 138.010 47.540 139.000 ;
        RECT 46.770 133.410 47.000 138.010 ;
        RECT 47.310 133.410 47.540 138.010 ;
        RECT 48.300 139.040 48.530 143.370 ;
        RECT 48.840 139.040 49.070 143.370 ;
        RECT 48.300 138.050 49.070 139.040 ;
        RECT 48.300 133.410 48.530 138.050 ;
        RECT 48.840 133.410 49.070 138.050 ;
        RECT 49.830 139.040 50.060 143.370 ;
        RECT 50.370 139.040 50.600 143.370 ;
        RECT 49.830 138.050 50.600 139.040 ;
        RECT 49.830 133.410 50.060 138.050 ;
        RECT 50.370 133.410 50.600 138.050 ;
        RECT 51.360 139.040 51.590 143.370 ;
        RECT 51.900 139.040 52.130 143.370 ;
        RECT 51.360 138.050 52.130 139.040 ;
        RECT 51.360 133.410 51.590 138.050 ;
        RECT 51.900 133.410 52.130 138.050 ;
        RECT 52.890 143.340 53.120 143.370 ;
        RECT 52.890 134.370 53.230 143.340 ;
        RECT 52.890 134.340 55.280 134.370 ;
        RECT 52.890 133.560 55.310 134.340 ;
        RECT 52.890 133.410 53.230 133.560 ;
        RECT 38.520 133.130 38.960 133.360 ;
        RECT 40.050 133.220 40.490 133.360 ;
        RECT 41.580 133.220 42.020 133.360 ;
        RECT 43.110 133.220 43.550 133.360 ;
        RECT 44.640 133.220 45.080 133.360 ;
        RECT 46.170 133.230 46.610 133.360 ;
        RECT 47.700 133.230 48.140 133.360 ;
        RECT 49.230 133.250 49.670 133.360 ;
        RECT 50.760 133.250 51.200 133.360 ;
        RECT 38.550 133.000 38.930 133.130 ;
        RECT 40.020 132.920 42.030 133.220 ;
        RECT 43.080 132.920 45.090 133.220 ;
        RECT 46.170 133.130 48.200 133.230 ;
        RECT 46.190 132.930 48.200 133.130 ;
        RECT 49.220 132.960 51.220 133.250 ;
        RECT 52.290 133.130 52.730 133.360 ;
        RECT 52.320 133.000 52.700 133.130 ;
        RECT 52.340 131.350 52.660 133.000 ;
        RECT 54.670 131.350 55.310 133.560 ;
        RECT 56.140 133.550 57.050 147.980 ;
        RECT 95.480 148.190 99.400 148.900 ;
        RECT 88.755 141.150 89.755 141.380 ;
        RECT 91.775 141.150 92.775 141.380 ;
        RECT 88.320 140.140 88.550 141.100 ;
        RECT 89.960 141.020 90.190 141.100 ;
        RECT 91.340 141.020 91.570 141.100 ;
        RECT 89.960 140.200 91.570 141.020 ;
        RECT 89.960 140.140 90.190 140.200 ;
        RECT 88.755 139.860 89.755 140.090 ;
        RECT 89.070 138.340 89.490 139.860 ;
        RECT 90.470 138.340 91.060 140.200 ;
        RECT 91.340 140.140 91.570 140.200 ;
        RECT 92.980 140.140 93.210 141.100 ;
        RECT 91.775 140.080 92.775 140.090 ;
        RECT 83.110 138.320 91.060 138.340 ;
        RECT 83.090 137.780 91.060 138.320 ;
        RECT 59.530 133.910 60.490 134.140 ;
        RECT 59.250 133.670 59.480 133.705 ;
        RECT 57.330 133.550 57.990 133.570 ;
        RECT 59.140 133.550 59.480 133.670 ;
        RECT 56.140 132.840 59.480 133.550 ;
        RECT 52.290 130.930 55.310 131.350 ;
        RECT 54.670 130.470 55.310 130.930 ;
        RECT 57.330 130.530 57.990 132.840 ;
        RECT 59.140 132.730 59.480 132.840 ;
        RECT 59.250 132.705 59.480 132.730 ;
        RECT 60.540 132.705 60.770 133.705 ;
        RECT 83.090 133.030 83.890 137.780 ;
        RECT 89.070 137.680 91.060 137.780 ;
        RECT 90.470 137.620 91.060 137.680 ;
        RECT 91.750 139.860 92.775 140.080 ;
        RECT 91.750 136.260 92.390 139.860 ;
        RECT 93.980 136.260 94.550 136.270 ;
        RECT 91.740 135.830 94.600 136.260 ;
        RECT 82.390 132.800 84.390 133.030 ;
        RECT 91.750 132.890 92.390 135.830 ;
        RECT 83.090 132.780 83.890 132.800 ;
        RECT 59.540 132.500 60.460 132.510 ;
        RECT 59.530 132.270 60.490 132.500 ;
        RECT 59.540 132.180 60.460 132.270 ;
        RECT 59.590 130.530 60.400 132.180 ;
        RECT 82.000 131.970 82.230 132.750 ;
        RECT 54.670 130.430 55.340 130.470 ;
        RECT 39.735 128.550 40.695 128.585 ;
        RECT 41.025 128.550 41.985 128.585 ;
        RECT 42.315 128.550 43.275 128.585 ;
        RECT 43.605 128.550 44.565 128.585 ;
        RECT 44.895 128.550 45.855 128.585 ;
        RECT 39.735 128.390 45.855 128.550 ;
        RECT 39.735 128.355 40.695 128.390 ;
        RECT 41.025 128.355 41.985 128.390 ;
        RECT 42.315 128.355 43.275 128.390 ;
        RECT 43.605 128.355 44.565 128.390 ;
        RECT 44.895 128.355 45.855 128.390 ;
        RECT 47.545 128.570 48.505 128.585 ;
        RECT 48.835 128.570 49.795 128.585 ;
        RECT 50.125 128.570 51.085 128.585 ;
        RECT 51.415 128.570 52.375 128.585 ;
        RECT 52.705 128.570 53.665 128.585 ;
        RECT 47.545 128.370 53.680 128.570 ;
        RECT 47.545 128.355 48.505 128.370 ;
        RECT 48.835 128.355 49.795 128.370 ;
        RECT 50.125 128.355 51.085 128.370 ;
        RECT 51.415 128.355 52.375 128.370 ;
        RECT 52.705 128.355 53.665 128.370 ;
        RECT 39.455 128.160 39.685 128.195 ;
        RECT 40.745 128.160 40.975 128.195 ;
        RECT 42.035 128.160 42.265 128.195 ;
        RECT 43.325 128.160 43.555 128.195 ;
        RECT 44.615 128.160 44.845 128.195 ;
        RECT 45.905 128.160 46.135 128.195 ;
        RECT 47.265 128.160 47.495 128.195 ;
        RECT 48.555 128.160 48.785 128.195 ;
        RECT 49.845 128.160 50.075 128.195 ;
        RECT 51.135 128.160 51.365 128.195 ;
        RECT 52.425 128.160 52.655 128.195 ;
        RECT 53.715 128.160 53.945 128.195 ;
        RECT 39.455 124.210 39.790 128.160 ;
        RECT 40.745 124.210 41.080 128.160 ;
        RECT 42.035 124.210 42.370 128.160 ;
        RECT 43.325 124.210 43.660 128.160 ;
        RECT 44.615 124.210 44.950 128.160 ;
        RECT 45.905 124.210 46.240 128.160 ;
        RECT 47.265 124.210 47.600 128.160 ;
        RECT 48.555 124.210 48.890 128.160 ;
        RECT 49.845 124.210 50.180 128.160 ;
        RECT 51.135 124.210 51.470 128.160 ;
        RECT 52.425 124.210 52.760 128.160 ;
        RECT 53.715 126.690 54.050 128.160 ;
        RECT 54.690 126.690 55.340 130.430 ;
        RECT 57.330 129.570 60.400 130.530 ;
        RECT 57.330 129.480 57.990 129.570 ;
        RECT 59.590 127.350 60.400 129.570 ;
        RECT 77.310 128.810 82.230 131.970 ;
        RECT 59.530 127.260 60.450 127.350 ;
        RECT 59.520 127.030 60.480 127.260 ;
        RECT 59.530 127.020 60.450 127.030 ;
        RECT 59.150 126.690 59.500 126.830 ;
        RECT 53.715 125.950 59.500 126.690 ;
        RECT 53.715 124.210 54.050 125.950 ;
        RECT 59.150 125.840 59.500 125.950 ;
        RECT 59.240 125.825 59.470 125.840 ;
        RECT 60.530 125.825 60.760 126.825 ;
        RECT 59.540 125.620 60.450 125.630 ;
        RECT 59.520 125.390 60.480 125.620 ;
        RECT 59.540 125.310 60.450 125.390 ;
        RECT 39.455 124.195 39.685 124.210 ;
        RECT 40.745 124.195 40.975 124.210 ;
        RECT 42.035 124.195 42.265 124.210 ;
        RECT 43.325 124.195 43.555 124.210 ;
        RECT 44.615 124.195 44.845 124.210 ;
        RECT 45.905 124.195 46.135 124.210 ;
        RECT 47.265 124.195 47.495 124.210 ;
        RECT 48.555 124.195 48.785 124.210 ;
        RECT 49.845 124.195 50.075 124.210 ;
        RECT 51.135 124.195 51.365 124.210 ;
        RECT 52.425 124.195 52.655 124.210 ;
        RECT 53.715 124.195 53.945 124.210 ;
        RECT 45.170 124.035 46.010 124.050 ;
        RECT 52.910 124.035 53.690 124.040 ;
        RECT 39.735 124.010 40.695 124.035 ;
        RECT 41.025 124.010 41.985 124.035 ;
        RECT 42.315 124.010 43.275 124.035 ;
        RECT 43.605 124.010 44.565 124.035 ;
        RECT 44.895 124.010 46.010 124.035 ;
        RECT 39.735 123.850 46.010 124.010 ;
        RECT 39.735 123.805 40.695 123.850 ;
        RECT 41.025 123.805 41.985 123.850 ;
        RECT 42.315 123.805 43.275 123.850 ;
        RECT 43.605 123.805 44.565 123.850 ;
        RECT 44.895 123.805 46.010 123.850 ;
        RECT 47.545 124.010 48.505 124.035 ;
        RECT 48.835 124.010 49.795 124.035 ;
        RECT 50.125 124.010 51.085 124.035 ;
        RECT 51.415 124.010 52.375 124.035 ;
        RECT 52.705 124.010 53.690 124.035 ;
        RECT 47.545 123.810 53.690 124.010 ;
        RECT 47.545 123.805 48.505 123.810 ;
        RECT 48.835 123.805 49.795 123.810 ;
        RECT 50.125 123.805 51.085 123.810 ;
        RECT 51.415 123.805 52.375 123.810 ;
        RECT 52.705 123.805 53.690 123.810 ;
        RECT 45.170 116.920 46.010 123.805 ;
        RECT 52.910 123.650 53.690 123.805 ;
        RECT 45.170 116.080 46.490 116.920 ;
        RECT 45.390 116.060 46.490 116.080 ;
        RECT 38.360 114.830 44.480 115.040 ;
        RECT 38.360 114.810 39.320 114.830 ;
        RECT 39.650 114.810 40.610 114.830 ;
        RECT 40.940 114.810 41.900 114.830 ;
        RECT 42.230 114.810 43.190 114.830 ;
        RECT 43.520 114.810 44.480 114.830 ;
        RECT 38.080 114.620 38.310 114.650 ;
        RECT 39.370 114.620 39.600 114.650 ;
        RECT 40.660 114.620 40.890 114.650 ;
        RECT 41.950 114.620 42.180 114.650 ;
        RECT 43.240 114.620 43.470 114.650 ;
        RECT 44.530 114.620 44.760 114.650 ;
        RECT 24.460 110.770 26.810 111.610 ;
        RECT 24.460 110.400 26.760 110.770 ;
        RECT 38.070 110.670 38.400 114.620 ;
        RECT 39.360 110.670 39.690 114.620 ;
        RECT 40.650 110.670 40.980 114.620 ;
        RECT 41.940 110.670 42.270 114.620 ;
        RECT 43.230 110.670 43.560 114.620 ;
        RECT 44.520 113.140 44.850 114.620 ;
        RECT 45.810 113.160 46.490 116.060 ;
        RECT 48.245 114.820 49.205 114.855 ;
        RECT 49.535 114.820 50.495 114.855 ;
        RECT 50.825 114.820 51.785 114.855 ;
        RECT 52.115 114.820 53.075 114.855 ;
        RECT 53.405 114.820 54.365 114.855 ;
        RECT 48.230 114.650 54.370 114.820 ;
        RECT 48.245 114.625 49.205 114.650 ;
        RECT 49.535 114.625 50.495 114.650 ;
        RECT 50.825 114.625 51.785 114.650 ;
        RECT 52.115 114.625 53.075 114.650 ;
        RECT 53.405 114.625 54.365 114.650 ;
        RECT 47.965 114.410 48.195 114.420 ;
        RECT 47.890 113.160 48.220 114.410 ;
        RECT 49.255 114.390 49.485 114.420 ;
        RECT 50.545 114.390 50.775 114.420 ;
        RECT 51.835 114.390 52.065 114.420 ;
        RECT 53.125 114.390 53.355 114.420 ;
        RECT 45.810 113.140 48.220 113.160 ;
        RECT 44.520 112.450 48.220 113.140 ;
        RECT 44.520 112.040 44.840 112.450 ;
        RECT 46.480 112.400 48.220 112.450 ;
        RECT 44.520 110.670 44.850 112.040 ;
        RECT 38.080 110.650 38.310 110.670 ;
        RECT 39.370 110.650 39.600 110.670 ;
        RECT 40.660 110.650 40.890 110.670 ;
        RECT 41.950 110.650 42.180 110.670 ;
        RECT 43.240 110.650 43.470 110.670 ;
        RECT 44.530 110.650 44.760 110.670 ;
        RECT 38.360 110.470 39.320 110.490 ;
        RECT 39.650 110.470 40.610 110.490 ;
        RECT 40.940 110.470 41.900 110.490 ;
        RECT 42.230 110.470 43.190 110.490 ;
        RECT 43.520 110.470 44.480 110.490 ;
        RECT 38.360 110.260 44.490 110.470 ;
        RECT 47.890 110.400 48.220 112.400 ;
        RECT 49.230 110.440 49.510 114.390 ;
        RECT 50.520 110.440 50.800 114.390 ;
        RECT 51.810 110.440 52.090 114.390 ;
        RECT 53.100 110.440 53.380 114.390 ;
        RECT 54.390 112.790 54.670 114.440 ;
        RECT 54.390 111.950 54.680 112.790 ;
        RECT 49.255 110.420 49.485 110.440 ;
        RECT 50.545 110.420 50.775 110.440 ;
        RECT 51.835 110.420 52.065 110.440 ;
        RECT 53.125 110.420 53.355 110.440 ;
        RECT 54.390 110.420 54.670 111.950 ;
        RECT 59.580 110.590 60.370 125.310 ;
        RECT 59.510 110.485 60.420 110.590 ;
        RECT 41.040 109.110 41.810 110.260 ;
        RECT 59.485 110.255 60.445 110.485 ;
        RECT 59.510 110.240 60.420 110.255 ;
        RECT 53.660 110.215 54.350 110.220 ;
        RECT 48.245 110.190 49.205 110.215 ;
        RECT 49.535 110.190 50.495 110.215 ;
        RECT 50.825 110.190 51.785 110.215 ;
        RECT 52.115 110.190 53.075 110.215 ;
        RECT 53.405 110.190 54.365 110.215 ;
        RECT 48.220 110.020 54.365 110.190 ;
        RECT 48.245 109.985 49.205 110.020 ;
        RECT 49.535 109.985 50.495 110.020 ;
        RECT 50.825 109.985 51.785 110.020 ;
        RECT 52.115 109.985 53.075 110.020 ;
        RECT 53.405 109.985 54.365 110.020 ;
        RECT 59.140 110.050 59.430 110.070 ;
        RECT 59.140 110.030 59.435 110.050 ;
        RECT 53.660 109.820 54.350 109.985 ;
        RECT 43.540 109.490 46.130 109.500 ;
        RECT 43.540 109.110 46.150 109.490 ;
        RECT 38.360 109.070 39.320 109.110 ;
        RECT 39.650 109.070 40.610 109.110 ;
        RECT 40.940 109.070 41.900 109.110 ;
        RECT 42.230 109.070 43.190 109.110 ;
        RECT 43.520 109.070 46.150 109.110 ;
        RECT 38.330 109.060 46.150 109.070 ;
        RECT 38.330 108.890 44.490 109.060 ;
        RECT 38.360 108.880 39.320 108.890 ;
        RECT 39.650 108.880 40.610 108.890 ;
        RECT 40.940 108.880 41.900 108.890 ;
        RECT 42.230 108.880 43.190 108.890 ;
        RECT 43.520 108.880 44.480 108.890 ;
        RECT 38.080 108.690 38.310 108.720 ;
        RECT 39.370 108.690 39.600 108.720 ;
        RECT 40.660 108.690 40.890 108.720 ;
        RECT 41.950 108.690 42.180 108.720 ;
        RECT 43.240 108.690 43.470 108.720 ;
        RECT 44.530 108.690 44.760 108.720 ;
        RECT 38.070 104.740 38.400 108.690 ;
        RECT 39.360 104.740 39.690 108.690 ;
        RECT 40.650 104.740 40.980 108.690 ;
        RECT 41.940 104.740 42.270 108.690 ;
        RECT 43.230 104.740 43.560 108.690 ;
        RECT 44.520 106.820 44.850 108.690 ;
        RECT 45.660 106.820 46.150 109.060 ;
        RECT 59.140 109.080 59.480 110.030 ;
        RECT 59.140 109.050 59.435 109.080 ;
        RECT 60.495 109.050 60.725 110.050 ;
        RECT 48.180 108.610 54.410 108.840 ;
        RECT 59.485 108.615 60.445 108.845 ;
        RECT 48.245 108.605 49.205 108.610 ;
        RECT 49.535 108.605 50.495 108.610 ;
        RECT 50.825 108.605 51.785 108.610 ;
        RECT 52.115 108.605 53.075 108.610 ;
        RECT 53.405 108.605 54.365 108.610 ;
        RECT 47.880 106.820 48.220 108.400 ;
        RECT 49.255 108.370 49.485 108.400 ;
        RECT 50.545 108.370 50.775 108.400 ;
        RECT 51.835 108.370 52.065 108.400 ;
        RECT 53.125 108.370 53.355 108.400 ;
        RECT 54.415 108.370 54.645 108.400 ;
        RECT 44.520 106.160 48.220 106.820 ;
        RECT 44.520 104.740 44.850 106.160 ;
        RECT 38.080 104.720 38.310 104.740 ;
        RECT 39.370 104.720 39.600 104.740 ;
        RECT 40.660 104.720 40.890 104.740 ;
        RECT 41.950 104.720 42.180 104.740 ;
        RECT 43.240 104.720 43.470 104.740 ;
        RECT 44.530 104.720 44.760 104.740 ;
        RECT 38.360 104.530 39.320 104.560 ;
        RECT 39.650 104.530 40.610 104.560 ;
        RECT 40.940 104.530 41.900 104.560 ;
        RECT 42.230 104.530 43.190 104.560 ;
        RECT 43.520 104.530 44.480 104.560 ;
        RECT 38.360 104.350 44.570 104.530 ;
        RECT 47.880 104.390 48.220 106.160 ;
        RECT 49.230 104.420 49.510 108.370 ;
        RECT 50.520 104.420 50.800 108.370 ;
        RECT 51.810 104.420 52.090 108.370 ;
        RECT 53.100 104.420 53.380 108.370 ;
        RECT 54.390 106.630 54.670 108.370 ;
        RECT 54.390 105.790 54.680 106.630 ;
        RECT 54.390 104.420 54.670 105.790 ;
        RECT 49.255 104.400 49.485 104.420 ;
        RECT 50.545 104.400 50.775 104.420 ;
        RECT 51.835 104.400 52.065 104.420 ;
        RECT 53.125 104.400 53.355 104.420 ;
        RECT 54.415 104.400 54.645 104.420 ;
        RECT 38.360 104.330 39.320 104.350 ;
        RECT 39.650 104.330 40.610 104.350 ;
        RECT 40.940 104.330 41.900 104.350 ;
        RECT 42.230 104.330 43.190 104.350 ;
        RECT 43.520 104.330 44.480 104.350 ;
        RECT 48.245 104.180 49.205 104.195 ;
        RECT 49.535 104.180 50.495 104.195 ;
        RECT 50.825 104.180 51.785 104.195 ;
        RECT 52.115 104.180 53.075 104.195 ;
        RECT 53.405 104.180 54.365 104.195 ;
        RECT 48.230 103.950 54.460 104.180 ;
        RECT 48.330 102.280 49.040 103.950 ;
        RECT 43.000 101.150 49.040 102.280 ;
        RECT 40.660 95.080 41.180 97.340 ;
        RECT 43.000 96.780 43.870 101.150 ;
        RECT 48.330 101.110 49.040 101.150 ;
        RECT 45.410 97.320 45.870 97.390 ;
        RECT 42.960 95.670 43.930 96.780 ;
        RECT 40.670 91.300 41.240 91.830 ;
        RECT 40.630 89.600 41.240 91.300 ;
        RECT 40.630 80.325 41.080 89.600 ;
        RECT 43.000 88.210 43.870 95.670 ;
        RECT 45.410 95.140 46.060 97.320 ;
        RECT 45.410 95.120 45.870 95.140 ;
        RECT 48.780 92.460 49.300 94.710 ;
        RECT 53.610 94.150 54.070 94.180 ;
        RECT 54.400 94.150 54.860 94.180 ;
        RECT 55.190 94.150 55.650 94.180 ;
        RECT 55.980 94.150 56.440 94.180 ;
        RECT 56.770 94.150 57.230 94.180 ;
        RECT 53.610 93.980 57.230 94.150 ;
        RECT 53.610 93.950 54.070 93.980 ;
        RECT 54.400 93.950 54.860 93.980 ;
        RECT 55.190 93.950 55.650 93.980 ;
        RECT 55.980 93.950 56.440 93.980 ;
        RECT 56.770 93.950 57.230 93.980 ;
        RECT 53.330 93.720 53.560 93.745 ;
        RECT 54.120 93.720 54.350 93.745 ;
        RECT 54.910 93.720 55.140 93.745 ;
        RECT 55.700 93.720 55.930 93.745 ;
        RECT 56.490 93.720 56.720 93.745 ;
        RECT 57.280 93.720 57.510 93.745 ;
        RECT 48.740 90.620 49.380 91.420 ;
        RECT 48.740 89.630 49.390 90.620 ;
        RECT 53.320 89.770 53.660 93.720 ;
        RECT 54.110 89.770 54.450 93.720 ;
        RECT 54.900 89.770 55.240 93.720 ;
        RECT 55.690 89.770 56.030 93.720 ;
        RECT 56.480 89.770 56.820 93.720 ;
        RECT 57.270 91.960 57.610 93.720 ;
        RECT 57.270 91.750 58.190 91.960 ;
        RECT 57.270 89.770 57.610 91.750 ;
        RECT 53.330 89.745 53.560 89.770 ;
        RECT 54.120 89.745 54.350 89.770 ;
        RECT 54.910 89.745 55.140 89.770 ;
        RECT 55.700 89.745 55.930 89.770 ;
        RECT 56.490 89.745 56.720 89.770 ;
        RECT 57.280 89.745 57.510 89.770 ;
        RECT 48.740 89.180 49.380 89.630 ;
        RECT 56.890 89.540 57.330 89.550 ;
        RECT 53.610 89.520 54.070 89.540 ;
        RECT 54.400 89.520 54.860 89.540 ;
        RECT 55.190 89.520 55.650 89.540 ;
        RECT 55.980 89.520 56.440 89.540 ;
        RECT 56.770 89.520 57.330 89.540 ;
        RECT 53.610 89.350 57.330 89.520 ;
        RECT 53.610 89.310 54.070 89.350 ;
        RECT 54.400 89.310 54.860 89.350 ;
        RECT 55.190 89.310 55.650 89.350 ;
        RECT 55.980 89.310 56.440 89.350 ;
        RECT 56.770 89.310 57.330 89.350 ;
        RECT 56.890 89.210 57.330 89.310 ;
        RECT 45.470 88.210 46.090 88.780 ;
        RECT 42.970 87.980 46.090 88.210 ;
        RECT 29.415 77.275 32.465 80.325 ;
        RECT 37.855 79.900 41.080 80.325 ;
        RECT 42.930 87.040 46.090 87.980 ;
        RECT 37.855 77.275 40.905 79.900 ;
        RECT 30.130 71.885 31.370 77.275 ;
        RECT 38.590 71.885 39.830 77.275 ;
        RECT 29.415 68.835 32.465 71.885 ;
        RECT 37.855 68.835 40.905 71.885 ;
        RECT 30.320 63.445 31.560 68.835 ;
        RECT 38.700 63.445 39.940 68.835 ;
        RECT 29.415 60.395 32.465 63.445 ;
        RECT 37.855 60.395 40.905 63.445 ;
        RECT 42.930 62.580 44.060 87.040 ;
        RECT 45.470 86.560 46.090 87.040 ;
        RECT 78.720 86.750 80.010 128.810 ;
        RECT 82.000 127.790 82.230 128.810 ;
        RECT 84.550 127.790 84.780 132.750 ;
        RECT 88.310 132.660 93.310 132.890 ;
        RECT 91.750 132.650 92.390 132.660 ;
        RECT 87.920 132.150 88.150 132.610 ;
        RECT 93.470 132.580 93.700 132.610 ;
        RECT 93.980 132.580 94.550 135.830 ;
        RECT 95.480 132.890 96.580 148.190 ;
        RECT 98.530 148.160 99.150 148.190 ;
        RECT 120.550 147.410 121.070 150.690 ;
        RECT 121.920 150.665 126.600 150.770 ;
        RECT 126.970 150.715 127.200 151.175 ;
        RECT 135.140 150.845 136.165 151.250 ;
        RECT 135.140 150.830 136.150 150.845 ;
        RECT 121.765 150.435 126.765 150.665 ;
        RECT 121.920 150.430 126.600 150.435 ;
        RECT 135.140 150.010 135.560 150.830 ;
        RECT 139.460 150.795 149.190 150.910 ;
        RECT 151.575 150.845 151.805 151.305 ;
        RECT 136.370 150.565 151.370 150.795 ;
        RECT 139.460 150.520 149.190 150.565 ;
        RECT 144.390 150.010 145.070 150.520 ;
        RECT 135.140 149.680 145.070 150.010 ;
        RECT 135.140 149.650 135.560 149.680 ;
        RECT 122.860 147.850 125.140 148.400 ;
        RECT 120.550 147.360 123.930 147.410 ;
        RECT 124.250 147.360 125.070 147.400 ;
        RECT 120.550 147.110 125.070 147.360 ;
        RECT 120.550 147.030 123.930 147.110 ;
        RECT 124.250 146.040 125.070 147.110 ;
        RECT 124.180 144.830 125.440 146.040 ;
        RECT 144.390 145.270 145.070 149.680 ;
        RECT 149.625 146.410 153.625 146.640 ;
        RECT 131.130 144.250 141.750 144.410 ;
        RECT 98.640 142.820 98.870 143.780 ;
        RECT 99.050 143.760 109.130 144.150 ;
        RECT 98.640 141.530 98.870 142.490 ;
        RECT 99.050 142.460 109.080 142.890 ;
        RECT 109.280 142.820 109.510 143.780 ;
        RECT 110.660 142.820 110.890 143.780 ;
        RECT 111.070 143.760 121.150 144.150 ;
        RECT 129.115 144.020 144.115 144.250 ;
        RECT 131.130 143.990 141.750 144.020 ;
        RECT 144.370 143.970 145.070 145.270 ;
        RECT 99.040 141.480 109.070 141.600 ;
        RECT 109.280 141.530 109.510 142.490 ;
        RECT 110.660 141.530 110.890 142.490 ;
        RECT 111.070 142.460 121.100 142.890 ;
        RECT 121.300 142.820 121.530 143.780 ;
        RECT 128.680 143.510 128.910 143.970 ;
        RECT 131.120 143.460 141.740 143.610 ;
        RECT 144.320 143.520 145.070 143.970 ;
        RECT 144.320 143.510 145.050 143.520 ;
        RECT 129.115 143.230 144.115 143.460 ;
        RECT 131.120 143.190 141.740 143.230 ;
        RECT 144.370 143.180 145.050 143.510 ;
        RECT 128.680 142.720 128.910 143.180 ;
        RECT 131.120 142.670 141.740 142.800 ;
        RECT 144.320 142.720 145.050 143.180 ;
        RECT 111.060 141.480 121.090 141.600 ;
        RECT 121.300 141.530 121.530 142.490 ;
        RECT 129.115 142.440 144.115 142.670 ;
        RECT 128.680 141.930 128.910 142.390 ;
        RECT 131.120 142.380 141.740 142.440 ;
        RECT 144.370 142.390 145.050 142.720 ;
        RECT 131.030 141.880 141.650 142.020 ;
        RECT 144.320 141.930 145.050 142.390 ;
        RECT 129.115 141.650 144.115 141.880 ;
        RECT 131.030 141.600 141.650 141.650 ;
        RECT 144.370 141.600 145.050 141.930 ;
        RECT 99.040 141.250 109.075 141.480 ;
        RECT 111.060 141.250 121.095 141.480 ;
        RECT 98.640 140.860 98.870 141.200 ;
        RECT 99.040 141.170 109.070 141.250 ;
        RECT 97.420 140.240 98.870 140.860 ;
        RECT 97.420 139.910 98.820 140.240 ;
        RECT 97.420 139.290 98.870 139.910 ;
        RECT 99.050 139.900 109.080 140.330 ;
        RECT 109.280 140.240 109.510 141.200 ;
        RECT 110.660 140.240 110.890 141.200 ;
        RECT 111.060 141.170 121.090 141.250 ;
        RECT 121.390 141.200 123.410 141.220 ;
        RECT 98.640 138.950 98.870 139.290 ;
        RECT 98.640 137.660 98.870 138.620 ;
        RECT 99.050 138.600 109.080 139.030 ;
        RECT 109.280 138.950 109.510 139.910 ;
        RECT 110.660 138.950 110.890 139.910 ;
        RECT 111.070 139.900 121.100 140.330 ;
        RECT 121.300 140.240 123.410 141.200 ;
        RECT 128.680 141.140 128.910 141.600 ;
        RECT 131.030 141.090 141.650 141.250 ;
        RECT 144.320 141.210 145.050 141.600 ;
        RECT 149.190 141.400 149.420 146.360 ;
        RECT 153.830 144.720 154.060 146.360 ;
        RECT 155.630 144.720 157.140 165.320 ;
        RECT 166.150 164.080 166.660 164.810 ;
        RECT 159.430 162.810 160.070 163.200 ;
        RECT 159.530 162.790 159.990 162.810 ;
        RECT 160.320 162.790 160.780 163.020 ;
        RECT 161.110 162.790 161.570 163.020 ;
        RECT 161.900 162.790 162.360 163.020 ;
        RECT 162.690 162.790 163.150 163.020 ;
        RECT 163.480 162.790 163.940 163.020 ;
        RECT 164.270 162.790 164.730 163.020 ;
        RECT 165.060 162.790 165.520 163.020 ;
        RECT 165.850 162.790 166.310 163.020 ;
        RECT 166.640 162.790 167.100 163.020 ;
        RECT 159.250 160.040 159.480 162.585 ;
        RECT 160.040 160.070 160.270 162.585 ;
        RECT 153.830 143.660 157.140 144.720 ;
        RECT 153.830 143.610 157.090 143.660 ;
        RECT 153.830 141.400 154.060 143.610 ;
        RECT 151.250 141.350 152.160 141.360 ;
        RECT 144.320 141.140 145.100 141.210 ;
        RECT 129.115 140.860 144.115 141.090 ;
        RECT 131.030 140.830 141.650 140.860 ;
        RECT 144.370 140.810 145.100 141.140 ;
        RECT 149.625 141.120 153.625 141.350 ;
        RECT 128.680 140.350 128.910 140.810 ;
        RECT 131.040 140.300 141.660 140.460 ;
        RECT 144.320 140.350 145.100 140.810 ;
        RECT 121.390 140.180 123.410 140.240 ;
        RECT 125.780 140.180 126.690 140.200 ;
        RECT 121.390 139.910 126.690 140.180 ;
        RECT 129.115 140.070 144.115 140.300 ;
        RECT 131.040 140.040 141.660 140.070 ;
        RECT 144.370 140.020 145.100 140.350 ;
        RECT 121.300 139.290 126.690 139.910 ;
        RECT 128.680 139.560 128.910 140.020 ;
        RECT 131.120 139.510 141.740 139.640 ;
        RECT 144.320 139.560 145.100 140.020 ;
        RECT 121.300 139.050 123.410 139.290 ;
        RECT 98.640 136.370 98.870 137.330 ;
        RECT 99.050 137.300 109.080 137.730 ;
        RECT 109.280 137.660 109.510 138.620 ;
        RECT 110.660 137.660 110.890 138.620 ;
        RECT 111.070 138.600 121.100 139.030 ;
        RECT 121.300 138.950 121.530 139.050 ;
        RECT 99.040 136.320 109.070 136.430 ;
        RECT 109.280 136.370 109.510 137.330 ;
        RECT 110.660 136.370 110.890 137.330 ;
        RECT 111.070 137.300 121.100 137.730 ;
        RECT 121.300 137.660 121.530 138.620 ;
        RECT 122.630 137.390 123.810 138.440 ;
        RECT 111.060 136.320 121.090 136.430 ;
        RECT 121.300 136.370 121.530 137.330 ;
        RECT 99.040 136.090 109.075 136.320 ;
        RECT 111.060 136.090 121.095 136.320 ;
        RECT 99.040 136.000 109.070 136.090 ;
        RECT 111.060 136.000 121.090 136.090 ;
        RECT 102.820 134.880 103.800 134.920 ;
        RECT 102.780 134.860 114.880 134.880 ;
        RECT 102.780 134.730 116.760 134.860 ;
        RECT 122.760 134.730 123.710 137.390 ;
        RECT 125.780 134.880 126.690 139.290 ;
        RECT 129.115 139.280 144.115 139.510 ;
        RECT 128.680 138.770 128.910 139.230 ;
        RECT 131.120 139.220 141.740 139.280 ;
        RECT 144.370 139.230 145.100 139.560 ;
        RECT 131.110 138.720 141.730 138.860 ;
        RECT 144.320 138.770 145.100 139.230 ;
        RECT 129.115 138.490 144.115 138.720 ;
        RECT 131.110 138.440 141.730 138.490 ;
        RECT 144.370 138.440 145.100 138.770 ;
        RECT 128.680 137.980 128.910 138.440 ;
        RECT 131.120 137.930 141.740 138.070 ;
        RECT 144.320 137.980 145.100 138.440 ;
        RECT 129.115 137.700 144.115 137.930 ;
        RECT 131.120 137.650 141.740 137.700 ;
        RECT 102.780 133.860 123.740 134.730 ;
        RECT 125.780 134.080 131.450 134.880 ;
        RECT 144.420 134.730 145.100 137.980 ;
        RECT 95.240 132.660 100.240 132.890 ;
        RECT 95.480 132.640 96.580 132.660 ;
        RECT 94.850 132.580 95.080 132.610 ;
        RECT 93.470 132.150 95.080 132.580 ;
        RECT 100.400 132.150 100.630 132.610 ;
        RECT 93.490 132.140 95.050 132.150 ;
        RECT 88.310 131.870 93.310 132.100 ;
        RECT 91.840 128.990 92.350 131.870 ;
        RECT 91.770 128.760 93.270 128.990 ;
        RECT 91.840 128.750 92.350 128.760 ;
        RECT 82.390 127.510 84.390 127.740 ;
        RECT 91.380 127.250 91.610 128.710 ;
        RECT 93.430 128.650 93.660 128.710 ;
        RECT 93.850 128.650 94.670 132.140 ;
        RECT 95.240 131.870 100.240 132.100 ;
        RECT 95.990 128.990 96.500 131.870 ;
        RECT 95.200 128.760 96.700 128.990 ;
        RECT 94.810 128.650 95.040 128.710 ;
        RECT 93.430 127.320 95.040 128.650 ;
        RECT 93.430 127.250 93.660 127.320 ;
        RECT 94.810 127.250 95.040 127.320 ;
        RECT 96.860 127.250 97.090 128.710 ;
        RECT 91.770 126.970 93.270 127.200 ;
        RECT 95.200 126.970 96.700 127.200 ;
        RECT 102.820 123.790 103.800 133.860 ;
        RECT 116.170 133.730 123.740 133.860 ;
        RECT 105.980 132.755 116.020 133.125 ;
        RECT 117.910 132.755 127.950 133.125 ;
        RECT 105.610 131.290 105.840 132.750 ;
        RECT 105.980 130.980 116.020 131.350 ;
        RECT 116.160 131.290 116.390 132.750 ;
        RECT 117.540 131.290 117.770 132.750 ;
        RECT 117.910 130.980 127.950 131.350 ;
        RECT 128.090 131.290 128.320 132.750 ;
        RECT 105.610 129.500 105.840 130.960 ;
        RECT 105.610 127.710 105.840 129.170 ;
        RECT 105.980 129.160 116.020 129.530 ;
        RECT 116.160 129.500 116.390 130.960 ;
        RECT 117.540 129.500 117.770 130.960 ;
        RECT 105.610 125.920 105.840 127.380 ;
        RECT 105.980 127.370 116.020 127.740 ;
        RECT 116.160 127.710 116.390 129.170 ;
        RECT 117.540 127.710 117.770 129.170 ;
        RECT 117.910 129.160 127.950 129.530 ;
        RECT 128.090 129.500 128.320 130.960 ;
        RECT 116.160 126.920 116.390 127.380 ;
        RECT 117.540 126.920 117.770 127.380 ;
        RECT 117.910 127.370 127.950 127.740 ;
        RECT 128.090 127.710 128.320 129.170 ;
        RECT 116.160 126.110 117.770 126.920 ;
        RECT 105.980 125.610 116.020 125.980 ;
        RECT 116.160 125.920 116.390 126.110 ;
        RECT 113.670 123.790 114.720 125.610 ;
        RECT 102.820 122.840 114.780 123.790 ;
        RECT 113.670 121.320 114.720 122.840 ;
        RECT 113.630 121.090 116.130 121.320 ;
        RECT 113.240 119.580 113.470 121.040 ;
        RECT 116.290 120.650 116.520 121.040 ;
        RECT 116.710 120.650 117.270 126.110 ;
        RECT 117.540 125.920 117.770 126.110 ;
        RECT 117.910 125.610 127.950 125.980 ;
        RECT 128.090 125.920 128.320 127.380 ;
        RECT 119.290 123.750 120.340 125.610 ;
        RECT 119.180 122.770 120.470 123.750 ;
        RECT 119.290 122.600 120.390 122.770 ;
        RECT 119.290 121.320 120.340 122.600 ;
        RECT 118.060 121.090 120.560 121.320 ;
        RECT 117.670 120.650 117.900 121.040 ;
        RECT 116.290 119.810 117.900 120.650 ;
        RECT 116.290 119.580 116.520 119.810 ;
        RECT 113.630 119.300 116.130 119.530 ;
        RECT 116.780 117.850 117.470 119.810 ;
        RECT 117.670 119.580 117.900 119.810 ;
        RECT 120.720 119.580 120.950 121.040 ;
        RECT 118.060 119.300 120.560 119.530 ;
        RECT 85.710 105.650 96.190 117.350 ;
        RECT 116.560 116.870 117.640 117.850 ;
        RECT 125.360 115.250 128.150 116.310 ;
        RECT 130.380 115.250 131.440 134.080 ;
        RECT 133.690 133.920 145.120 134.730 ;
        RECT 133.860 132.350 135.000 133.920 ;
        RECT 142.800 132.490 148.480 132.580 ;
        RECT 133.620 132.120 135.120 132.350 ;
        RECT 141.050 132.260 151.050 132.490 ;
        RECT 151.250 132.420 152.160 141.120 ;
        RECT 159.030 134.950 159.500 160.040 ;
        RECT 159.850 134.980 160.320 160.070 ;
        RECT 160.830 160.040 161.060 162.585 ;
        RECT 161.620 160.040 161.850 162.585 ;
        RECT 162.410 160.070 162.640 162.585 ;
        RECT 163.200 160.070 163.430 162.585 ;
        RECT 163.990 160.090 164.220 162.585 ;
        RECT 159.250 132.585 159.480 134.950 ;
        RECT 160.040 132.585 160.270 134.980 ;
        RECT 160.630 134.950 161.100 160.040 ;
        RECT 161.400 134.950 161.870 160.040 ;
        RECT 162.190 134.980 162.660 160.070 ;
        RECT 163.000 134.980 163.470 160.070 ;
        RECT 163.760 135.000 164.230 160.090 ;
        RECT 164.780 160.040 165.010 162.585 ;
        RECT 165.570 160.040 165.800 162.585 ;
        RECT 160.830 132.585 161.060 134.950 ;
        RECT 161.620 132.585 161.850 134.950 ;
        RECT 162.410 132.585 162.640 134.980 ;
        RECT 163.200 132.585 163.430 134.980 ;
        RECT 163.990 132.585 164.220 135.000 ;
        RECT 164.580 134.950 165.050 160.040 ;
        RECT 165.370 134.950 165.840 160.040 ;
        RECT 166.360 160.010 166.590 162.585 ;
        RECT 164.780 132.585 165.010 134.950 ;
        RECT 165.570 132.585 165.800 134.950 ;
        RECT 166.160 134.920 166.630 160.010 ;
        RECT 167.150 159.990 167.380 162.585 ;
        RECT 166.950 135.110 167.420 159.990 ;
        RECT 174.970 135.150 178.900 135.170 ;
        RECT 174.970 135.110 188.730 135.150 ;
        RECT 166.360 132.585 166.590 134.920 ;
        RECT 166.950 134.900 188.730 135.110 ;
        RECT 167.110 133.520 188.730 134.900 ;
        RECT 167.150 133.290 188.730 133.520 ;
        RECT 167.150 132.585 167.380 133.290 ;
        RECT 151.250 132.210 152.270 132.420 ;
        RECT 133.860 132.090 135.000 132.120 ;
        RECT 133.230 131.350 133.460 132.070 ;
        RECT 133.140 127.700 133.540 131.350 ;
        RECT 133.230 127.110 133.460 127.700 ;
        RECT 135.280 127.110 135.510 132.070 ;
        RECT 140.660 131.750 140.890 132.210 ;
        RECT 142.810 131.700 148.490 131.790 ;
        RECT 151.210 131.750 152.270 132.210 ;
        RECT 159.530 132.150 159.990 132.380 ;
        RECT 160.320 132.150 160.780 132.380 ;
        RECT 161.110 132.150 161.570 132.380 ;
        RECT 161.900 132.150 162.360 132.380 ;
        RECT 162.690 132.150 163.150 132.380 ;
        RECT 163.480 132.150 163.940 132.380 ;
        RECT 164.270 132.150 164.730 132.380 ;
        RECT 165.060 132.150 165.520 132.380 ;
        RECT 165.850 132.150 166.310 132.380 ;
        RECT 166.640 132.150 167.100 132.380 ;
        RECT 141.050 131.470 151.050 131.700 ;
        RECT 151.300 131.420 152.270 131.750 ;
        RECT 140.660 130.960 140.890 131.420 ;
        RECT 142.810 130.910 148.490 131.030 ;
        RECT 151.210 130.960 152.270 131.420 ;
        RECT 141.050 130.680 151.050 130.910 ;
        RECT 151.300 130.630 152.270 130.960 ;
        RECT 140.660 130.170 140.890 130.630 ;
        RECT 142.840 130.120 148.520 130.210 ;
        RECT 151.210 130.170 152.270 130.630 ;
        RECT 141.050 129.890 151.050 130.120 ;
        RECT 151.300 129.840 152.270 130.170 ;
        RECT 140.660 129.380 140.890 129.840 ;
        RECT 142.820 129.330 148.500 129.450 ;
        RECT 151.210 129.380 152.270 129.840 ;
        RECT 141.050 129.100 151.050 129.330 ;
        RECT 151.300 127.700 152.270 129.380 ;
        RECT 156.530 127.700 156.950 127.730 ;
        RECT 133.620 126.830 135.120 127.060 ;
        RECT 151.300 126.920 156.950 127.700 ;
        RECT 161.500 127.070 161.960 127.300 ;
        RECT 162.290 127.070 162.750 127.300 ;
        RECT 163.080 127.070 163.540 127.300 ;
        RECT 163.870 127.070 164.330 127.300 ;
        RECT 164.660 127.070 165.120 127.300 ;
        RECT 151.300 126.080 152.270 126.920 ;
        RECT 148.000 125.990 153.680 126.080 ;
        RECT 146.250 125.760 156.250 125.990 ;
        RECT 151.300 125.720 152.270 125.760 ;
        RECT 156.530 125.710 156.950 126.920 ;
        RECT 145.860 125.250 146.090 125.710 ;
        RECT 148.010 125.200 153.690 125.290 ;
        RECT 156.410 125.270 156.950 125.710 ;
        RECT 156.410 125.250 156.640 125.270 ;
        RECT 146.250 124.970 156.250 125.200 ;
        RECT 145.860 124.460 146.090 124.920 ;
        RECT 148.010 124.410 153.690 124.530 ;
        RECT 156.410 124.460 156.640 124.920 ;
        RECT 161.220 124.700 161.450 126.910 ;
        RECT 146.250 124.180 156.250 124.410 ;
        RECT 145.860 123.670 146.090 124.130 ;
        RECT 148.040 123.620 153.720 123.710 ;
        RECT 156.410 123.670 156.640 124.130 ;
        RECT 146.250 123.390 156.250 123.620 ;
        RECT 145.860 122.880 146.090 123.340 ;
        RECT 148.020 122.830 153.700 122.950 ;
        RECT 156.410 122.880 156.640 123.340 ;
        RECT 146.250 122.600 156.250 122.830 ;
        RECT 148.000 121.470 153.680 121.560 ;
        RECT 146.250 121.240 156.250 121.470 ;
        RECT 145.860 120.730 146.090 121.190 ;
        RECT 148.010 120.680 153.690 120.770 ;
        RECT 156.410 120.730 156.970 121.310 ;
        RECT 146.250 120.450 156.250 120.680 ;
        RECT 145.860 119.940 146.090 120.400 ;
        RECT 148.010 119.890 153.690 120.010 ;
        RECT 156.410 119.940 156.640 120.400 ;
        RECT 146.250 119.660 156.250 119.890 ;
        RECT 145.860 119.150 146.090 119.610 ;
        RECT 148.040 119.100 153.720 119.190 ;
        RECT 156.410 119.150 156.640 119.610 ;
        RECT 146.250 118.870 156.250 119.100 ;
        RECT 145.860 118.360 146.090 118.820 ;
        RECT 148.020 118.310 153.700 118.430 ;
        RECT 156.410 118.360 156.640 118.820 ;
        RECT 146.250 118.080 156.250 118.310 ;
        RECT 154.710 116.770 156.030 117.390 ;
        RECT 122.230 114.160 131.440 115.250 ;
        RECT 122.230 113.930 131.610 114.160 ;
        RECT 122.310 112.100 123.800 113.930 ;
        RECT 125.360 113.900 128.150 113.930 ;
        RECT 130.420 113.140 131.610 113.930 ;
        RECT 121.795 111.510 123.900 112.100 ;
        RECT 130.420 112.060 131.430 113.140 ;
        RECT 129.950 111.810 132.055 112.060 ;
        RECT 130.420 111.570 131.430 111.810 ;
        RECT 110.070 104.860 113.850 108.640 ;
        RECT 121.795 108.000 123.900 108.590 ;
        RECT 135.585 108.490 137.690 108.740 ;
        RECT 135.360 108.000 137.560 108.490 ;
        RECT 109.310 102.850 109.560 103.170 ;
        RECT 111.160 102.850 112.460 104.860 ;
        RECT 109.310 102.840 112.460 102.850 ;
        RECT 114.970 102.840 115.560 103.240 ;
        RECT 98.390 98.950 102.710 102.330 ;
        RECT 109.310 101.520 115.560 102.840 ;
        RECT 109.310 101.065 109.560 101.520 ;
        RECT 111.170 101.390 115.560 101.520 ;
        RECT 114.970 101.135 115.560 101.390 ;
        RECT 118.480 103.190 119.070 103.240 ;
        RECT 122.310 103.190 123.710 108.000 ;
        RECT 135.360 104.900 136.350 108.000 ;
        RECT 161.040 107.990 161.470 124.700 ;
        RECT 162.010 124.690 162.240 126.910 ;
        RECT 161.220 106.910 161.450 107.990 ;
        RECT 161.860 107.980 162.290 124.690 ;
        RECT 162.800 124.640 163.030 126.910 ;
        RECT 162.010 106.910 162.240 107.980 ;
        RECT 162.640 107.930 163.070 124.640 ;
        RECT 163.590 124.570 163.820 126.910 ;
        RECT 162.800 106.910 163.030 107.930 ;
        RECT 163.450 107.860 163.880 124.570 ;
        RECT 164.380 124.510 164.610 126.910 ;
        RECT 165.170 125.490 165.400 126.910 ;
        RECT 174.970 125.490 188.730 133.290 ;
        RECT 165.170 124.510 188.730 125.490 ;
        RECT 163.590 106.910 163.820 107.860 ;
        RECT 164.220 107.800 164.650 124.510 ;
        RECT 164.980 123.780 188.730 124.510 ;
        RECT 164.980 107.800 165.410 123.780 ;
        RECT 164.380 106.910 164.610 107.800 ;
        RECT 165.170 106.910 165.400 107.800 ;
        RECT 161.500 106.730 161.960 106.750 ;
        RECT 161.420 106.450 162.050 106.730 ;
        RECT 162.290 106.520 162.750 106.750 ;
        RECT 163.080 106.520 163.540 106.750 ;
        RECT 163.870 106.520 164.330 106.750 ;
        RECT 164.660 106.520 165.120 106.750 ;
        RECT 171.200 104.900 172.690 123.780 ;
        RECT 175.600 123.770 188.730 123.780 ;
        RECT 135.360 103.940 172.690 104.900 ;
        RECT 171.200 103.850 172.690 103.940 ;
        RECT 118.480 101.340 127.820 103.190 ;
        RECT 118.480 101.135 119.070 101.340 ;
        RECT 98.390 96.970 106.290 98.950 ;
        RECT 104.100 95.430 106.240 96.970 ;
        RECT 104.100 95.170 106.140 95.430 ;
        RECT 125.920 94.440 127.720 101.340 ;
        RECT 125.920 92.850 176.190 94.440 ;
        RECT 101.480 90.580 160.450 91.920 ;
        RECT 76.960 85.000 81.180 86.750 ;
        RECT 92.555 85.330 100.055 85.560 ;
        RECT 51.140 84.920 83.220 85.000 ;
        RECT 51.060 83.900 83.220 84.920 ;
        RECT 51.060 83.890 51.890 83.900 ;
        RECT 76.960 83.860 81.180 83.900 ;
        RECT 78.720 83.840 80.010 83.860 ;
        RECT 46.295 79.190 49.345 80.325 ;
        RECT 54.735 79.190 57.785 80.325 ;
        RECT 46.295 79.070 57.785 79.190 ;
        RECT 63.175 79.070 66.225 80.325 ;
        RECT 46.295 78.240 66.225 79.070 ;
        RECT 46.295 77.275 49.345 78.240 ;
        RECT 54.735 78.120 66.225 78.240 ;
        RECT 54.735 77.275 57.785 78.120 ;
        RECT 63.175 77.275 66.225 78.120 ;
        RECT 47.080 71.885 48.210 77.275 ;
        RECT 55.690 71.885 56.820 77.275 ;
        RECT 64.180 71.885 65.310 77.275 ;
        RECT 46.295 68.835 49.345 71.885 ;
        RECT 54.735 68.835 57.785 71.885 ;
        RECT 63.175 68.835 66.225 71.885 ;
        RECT 55.650 63.445 56.780 68.835 ;
        RECT 63.880 63.445 65.010 68.835 ;
        RECT 46.295 62.580 49.345 63.445 ;
        RECT 42.890 61.110 49.345 62.580 ;
        RECT 46.295 60.395 49.345 61.110 ;
        RECT 54.735 60.395 57.785 63.445 ;
        RECT 63.175 60.395 66.225 63.445 ;
        RECT 30.250 55.005 31.490 60.395 ;
        RECT 38.590 55.005 39.830 60.395 ;
        RECT 55.690 55.005 56.820 60.395 ;
        RECT 64.070 55.005 65.200 60.395 ;
        RECT 82.300 57.230 83.220 83.900 ;
        RECT 92.120 83.320 92.350 85.280 ;
        RECT 100.260 85.160 100.490 85.280 ;
        RECT 101.960 85.160 103.520 90.580 ;
        RECT 123.770 89.300 124.610 89.950 ;
        RECT 112.730 87.970 113.460 88.740 ;
        RECT 142.820 88.455 152.550 88.600 ;
        RECT 118.100 88.280 123.060 88.360 ;
        RECT 125.120 88.280 130.080 88.360 ;
        RECT 118.085 88.050 123.085 88.280 ;
        RECT 125.105 88.050 130.105 88.280 ;
        RECT 118.100 88.010 123.060 88.050 ;
        RECT 125.120 88.010 130.080 88.050 ;
        RECT 117.650 87.040 117.880 88.000 ;
        RECT 105.640 86.930 111.710 87.020 ;
        RECT 118.090 86.990 123.050 87.080 ;
        RECT 123.290 87.040 123.520 88.000 ;
        RECT 124.670 87.040 124.900 88.000 ;
        RECT 125.110 86.990 130.070 87.080 ;
        RECT 130.310 87.040 130.540 88.000 ;
        RECT 105.025 86.700 112.525 86.930 ;
        RECT 118.085 86.760 123.085 86.990 ;
        RECT 125.105 86.760 130.105 86.990 ;
        RECT 118.090 86.730 123.050 86.760 ;
        RECT 125.110 86.730 130.070 86.760 ;
        RECT 104.590 85.160 104.820 86.650 ;
        RECT 100.260 84.690 104.820 85.160 ;
        RECT 100.260 84.360 104.800 84.690 ;
        RECT 105.610 84.640 111.680 84.720 ;
        RECT 112.730 84.690 112.960 86.650 ;
        RECT 117.650 85.750 117.880 86.710 ;
        RECT 118.100 85.700 123.070 85.790 ;
        RECT 123.290 85.750 123.520 86.710 ;
        RECT 124.670 85.750 124.900 86.710 ;
        RECT 125.120 85.700 130.090 85.790 ;
        RECT 130.310 85.750 130.540 86.710 ;
        RECT 118.085 85.470 123.085 85.700 ;
        RECT 125.105 85.470 130.105 85.700 ;
        RECT 118.100 85.450 123.070 85.470 ;
        RECT 125.120 85.450 130.090 85.470 ;
        RECT 105.025 84.410 112.525 84.640 ;
        RECT 117.650 84.460 117.880 85.420 ;
        RECT 118.100 84.410 123.070 84.500 ;
        RECT 123.290 84.460 123.520 85.420 ;
        RECT 124.670 84.460 124.900 85.420 ;
        RECT 125.120 84.410 130.090 84.500 ;
        RECT 130.310 84.460 130.540 85.420 ;
        RECT 100.260 83.910 104.820 84.360 ;
        RECT 100.260 83.320 100.490 83.910 ;
        RECT 92.555 83.040 100.055 83.270 ;
        RECT 94.980 78.540 97.400 83.040 ;
        RECT 90.700 77.180 90.930 78.140 ;
        RECT 91.090 78.110 101.160 78.540 ;
        RECT 94.980 78.100 97.400 78.110 ;
        RECT 101.340 77.520 101.570 78.140 ;
        RECT 101.850 77.520 102.450 83.910 ;
        RECT 104.590 82.400 104.820 83.910 ;
        RECT 105.810 82.350 111.880 82.420 ;
        RECT 112.730 82.400 112.960 84.360 ;
        RECT 118.085 84.180 123.085 84.410 ;
        RECT 125.105 84.180 130.105 84.410 ;
        RECT 118.100 84.140 123.070 84.180 ;
        RECT 125.120 84.140 130.090 84.180 ;
        RECT 117.650 83.170 117.880 84.130 ;
        RECT 123.290 83.980 123.520 84.130 ;
        RECT 124.670 83.980 124.900 84.130 ;
        RECT 123.290 83.210 124.900 83.980 ;
        RECT 123.290 83.170 123.520 83.210 ;
        RECT 118.100 83.120 123.050 83.170 ;
        RECT 118.085 82.890 123.085 83.120 ;
        RECT 118.100 82.830 123.050 82.890 ;
        RECT 105.025 82.120 112.525 82.350 ;
        RECT 107.110 78.540 109.570 82.120 ;
        RECT 119.970 79.190 120.660 82.830 ;
        RECT 123.870 81.500 124.300 83.210 ;
        RECT 124.670 83.170 124.900 83.210 ;
        RECT 130.310 83.170 130.540 84.130 ;
        RECT 125.120 83.120 130.070 83.170 ;
        RECT 125.105 82.890 130.105 83.120 ;
        RECT 125.120 82.830 130.070 82.890 ;
        RECT 123.840 80.590 124.350 81.500 ;
        RECT 127.470 79.190 128.160 82.830 ;
        RECT 118.220 79.085 122.900 79.190 ;
        RECT 125.240 79.085 129.920 79.190 ;
        RECT 118.055 78.855 123.055 79.085 ;
        RECT 125.075 78.855 130.075 79.085 ;
        RECT 118.220 78.850 122.900 78.855 ;
        RECT 125.240 78.850 129.920 78.855 ;
        RECT 119.970 78.840 120.660 78.850 ;
        RECT 102.720 77.520 102.950 78.140 ;
        RECT 103.110 78.110 113.180 78.540 ;
        RECT 117.620 78.345 117.850 78.805 ;
        RECT 118.220 78.295 122.900 78.390 ;
        RECT 123.260 78.345 123.490 78.805 ;
        RECT 124.640 78.345 124.870 78.805 ;
        RECT 125.240 78.295 129.920 78.390 ;
        RECT 130.280 78.345 130.510 78.805 ;
        RECT 91.080 76.850 101.170 77.210 ;
        RECT 101.340 77.180 102.950 77.520 ;
        RECT 101.390 76.850 102.950 77.180 ;
        RECT 103.100 76.850 113.190 77.210 ;
        RECT 113.360 77.180 113.590 78.140 ;
        RECT 118.055 78.065 123.055 78.295 ;
        RECT 125.075 78.065 130.075 78.295 ;
        RECT 118.220 78.050 122.900 78.065 ;
        RECT 125.240 78.050 129.920 78.065 ;
        RECT 117.620 77.555 117.850 78.015 ;
        RECT 118.250 77.505 122.930 77.600 ;
        RECT 123.260 77.555 123.490 78.015 ;
        RECT 124.640 77.555 124.870 78.015 ;
        RECT 125.270 77.505 129.950 77.600 ;
        RECT 130.280 77.555 130.510 78.015 ;
        RECT 118.055 77.275 123.055 77.505 ;
        RECT 125.075 77.275 130.075 77.505 ;
        RECT 118.250 77.260 122.930 77.275 ;
        RECT 125.270 77.260 129.950 77.275 ;
        RECT 90.700 75.890 90.930 76.850 ;
        RECT 99.270 76.530 99.940 76.850 ;
        RECT 101.340 76.530 102.950 76.850 ;
        RECT 99.270 76.260 102.950 76.530 ;
        RECT 91.090 75.520 101.170 75.940 ;
        RECT 101.340 75.890 101.570 76.260 ;
        RECT 101.840 74.160 102.460 76.260 ;
        RECT 102.720 75.890 102.950 76.260 ;
        RECT 103.110 75.520 113.190 75.940 ;
        RECT 113.360 75.890 113.590 76.850 ;
        RECT 117.620 76.765 117.850 77.225 ;
        RECT 118.200 76.715 122.880 76.810 ;
        RECT 123.260 76.765 123.490 77.225 ;
        RECT 124.640 76.765 124.870 77.225 ;
        RECT 125.220 76.715 129.900 76.810 ;
        RECT 130.280 76.765 130.510 77.225 ;
        RECT 118.055 76.485 123.055 76.715 ;
        RECT 125.075 76.485 130.075 76.715 ;
        RECT 118.200 76.470 122.880 76.485 ;
        RECT 125.220 76.470 129.900 76.485 ;
        RECT 117.620 75.975 117.850 76.435 ;
        RECT 123.260 76.430 123.490 76.435 ;
        RECT 124.640 76.430 124.870 76.435 ;
        RECT 118.210 75.925 122.890 76.030 ;
        RECT 123.260 75.975 124.870 76.430 ;
        RECT 123.320 75.950 124.830 75.975 ;
        RECT 118.055 75.695 123.055 75.925 ;
        RECT 118.210 75.690 122.890 75.695 ;
        RECT 98.790 73.450 102.710 74.160 ;
        RECT 92.065 66.410 93.065 66.640 ;
        RECT 95.085 66.410 96.085 66.640 ;
        RECT 91.630 65.400 91.860 66.360 ;
        RECT 93.270 66.280 93.500 66.360 ;
        RECT 94.650 66.280 94.880 66.360 ;
        RECT 93.270 65.460 94.880 66.280 ;
        RECT 93.270 65.400 93.500 65.460 ;
        RECT 92.065 65.120 93.065 65.350 ;
        RECT 92.380 63.600 92.800 65.120 ;
        RECT 93.780 63.600 94.370 65.460 ;
        RECT 94.650 65.400 94.880 65.460 ;
        RECT 96.290 65.400 96.520 66.360 ;
        RECT 95.085 65.340 96.085 65.350 ;
        RECT 86.420 63.580 94.370 63.600 ;
        RECT 86.400 63.040 94.370 63.580 ;
        RECT 86.400 58.290 87.200 63.040 ;
        RECT 92.380 62.940 94.370 63.040 ;
        RECT 93.780 62.880 94.370 62.940 ;
        RECT 95.060 65.120 96.085 65.340 ;
        RECT 95.060 61.520 95.700 65.120 ;
        RECT 97.290 61.520 97.860 61.530 ;
        RECT 95.050 61.090 97.910 61.520 ;
        RECT 85.700 58.060 87.700 58.290 ;
        RECT 95.060 58.150 95.700 61.090 ;
        RECT 86.400 58.040 87.200 58.060 ;
        RECT 85.310 57.230 85.540 58.010 ;
        RECT 29.415 51.955 32.465 55.005 ;
        RECT 37.855 51.955 40.905 55.005 ;
        RECT 46.295 51.955 49.345 55.005 ;
        RECT 54.735 51.955 57.785 55.005 ;
        RECT 63.175 51.955 66.225 55.005 ;
        RECT 80.620 54.070 85.540 57.230 ;
        RECT 85.310 53.050 85.540 54.070 ;
        RECT 87.860 53.050 88.090 58.010 ;
        RECT 91.620 57.920 96.620 58.150 ;
        RECT 95.060 57.910 95.700 57.920 ;
        RECT 91.230 57.410 91.460 57.870 ;
        RECT 96.780 57.840 97.010 57.870 ;
        RECT 97.290 57.840 97.860 61.090 ;
        RECT 98.790 58.150 99.890 73.450 ;
        RECT 101.840 73.420 102.460 73.450 ;
        RECT 123.860 72.670 124.380 75.950 ;
        RECT 125.230 75.925 129.910 76.030 ;
        RECT 130.280 75.975 130.510 76.435 ;
        RECT 125.075 75.695 130.075 75.925 ;
        RECT 125.230 75.690 129.910 75.695 ;
        RECT 126.170 73.110 128.450 73.660 ;
        RECT 123.860 72.620 127.240 72.670 ;
        RECT 127.560 72.620 128.380 72.660 ;
        RECT 123.860 72.370 128.380 72.620 ;
        RECT 123.860 72.290 127.240 72.370 ;
        RECT 127.560 71.300 128.380 72.370 ;
        RECT 133.370 71.700 134.670 88.310 ;
        RECT 139.680 88.225 154.680 88.455 ;
        RECT 142.820 88.210 152.550 88.225 ;
        RECT 139.245 87.715 139.475 88.175 ;
        RECT 142.820 87.665 152.550 87.810 ;
        RECT 154.885 87.715 155.115 88.175 ;
        RECT 139.680 87.435 154.680 87.665 ;
        RECT 142.820 87.420 152.550 87.435 ;
        RECT 139.245 86.925 139.475 87.385 ;
        RECT 142.840 86.875 152.570 87.010 ;
        RECT 154.885 86.925 155.115 87.385 ;
        RECT 139.680 86.645 154.680 86.875 ;
        RECT 142.840 86.620 152.570 86.645 ;
        RECT 139.245 86.135 139.475 86.595 ;
        RECT 142.810 86.085 152.540 86.200 ;
        RECT 154.885 86.135 155.115 86.595 ;
        RECT 139.680 85.855 154.680 86.085 ;
        RECT 142.810 85.810 152.540 85.855 ;
        RECT 139.245 85.345 139.475 85.805 ;
        RECT 142.790 85.295 152.520 85.430 ;
        RECT 154.885 85.345 155.115 85.805 ;
        RECT 139.680 85.065 154.680 85.295 ;
        RECT 142.790 85.040 152.520 85.065 ;
        RECT 139.245 84.555 139.475 85.015 ;
        RECT 142.760 84.505 152.490 84.590 ;
        RECT 154.885 84.555 155.115 85.015 ;
        RECT 139.680 84.275 154.680 84.505 ;
        RECT 139.245 83.765 139.475 84.225 ;
        RECT 142.760 84.200 152.490 84.275 ;
        RECT 142.740 83.715 152.470 83.840 ;
        RECT 154.885 83.765 155.115 84.225 ;
        RECT 139.680 83.485 154.680 83.715 ;
        RECT 142.740 83.450 152.470 83.485 ;
        RECT 139.245 83.430 139.475 83.435 ;
        RECT 138.480 83.420 139.490 83.430 ;
        RECT 138.370 82.930 139.490 83.420 ;
        RECT 138.370 82.320 138.730 82.930 ;
        RECT 142.770 82.925 152.500 83.040 ;
        RECT 154.885 82.975 155.115 83.435 ;
        RECT 139.680 82.695 154.680 82.925 ;
        RECT 142.770 82.650 152.500 82.695 ;
        RECT 146.170 82.320 149.370 82.650 ;
        RECT 138.370 81.930 149.370 82.320 ;
        RECT 146.170 81.730 149.370 81.930 ;
        RECT 142.820 81.585 152.550 81.730 ;
        RECT 139.680 81.355 154.680 81.585 ;
        RECT 142.820 81.340 152.550 81.355 ;
        RECT 139.245 80.845 139.475 81.305 ;
        RECT 142.820 80.795 152.550 80.940 ;
        RECT 154.885 80.845 155.115 81.305 ;
        RECT 139.680 80.565 154.680 80.795 ;
        RECT 142.820 80.550 152.550 80.565 ;
        RECT 139.245 80.055 139.475 80.515 ;
        RECT 142.840 80.005 152.570 80.140 ;
        RECT 154.885 80.055 155.115 80.515 ;
        RECT 139.680 79.775 154.680 80.005 ;
        RECT 142.840 79.750 152.570 79.775 ;
        RECT 139.245 79.265 139.475 79.725 ;
        RECT 142.810 79.215 152.540 79.330 ;
        RECT 154.885 79.265 155.115 79.725 ;
        RECT 139.680 78.985 154.680 79.215 ;
        RECT 142.810 78.940 152.540 78.985 ;
        RECT 139.245 78.475 139.475 78.935 ;
        RECT 142.790 78.425 152.520 78.560 ;
        RECT 154.885 78.475 155.115 78.935 ;
        RECT 139.680 78.195 154.680 78.425 ;
        RECT 142.790 78.170 152.520 78.195 ;
        RECT 139.245 77.685 139.475 78.145 ;
        RECT 142.760 77.635 152.490 77.720 ;
        RECT 154.885 77.685 155.115 78.145 ;
        RECT 139.680 77.405 154.680 77.635 ;
        RECT 139.245 76.895 139.475 77.355 ;
        RECT 142.760 77.330 152.490 77.405 ;
        RECT 142.740 76.845 152.470 76.970 ;
        RECT 154.885 76.895 155.115 77.355 ;
        RECT 139.680 76.615 154.680 76.845 ;
        RECT 138.450 76.510 138.870 76.590 ;
        RECT 142.740 76.580 152.470 76.615 ;
        RECT 139.245 76.510 139.475 76.565 ;
        RECT 138.450 76.105 139.475 76.510 ;
        RECT 138.450 76.090 139.460 76.105 ;
        RECT 138.450 75.270 138.870 76.090 ;
        RECT 142.770 76.055 152.500 76.170 ;
        RECT 154.885 76.105 155.115 76.565 ;
        RECT 139.680 75.825 154.680 76.055 ;
        RECT 142.770 75.780 152.500 75.825 ;
        RECT 147.700 75.270 148.380 75.780 ;
        RECT 138.450 74.940 148.380 75.270 ;
        RECT 138.450 74.910 138.870 74.940 ;
        RECT 127.490 70.090 128.750 71.300 ;
        RECT 129.180 70.610 134.670 71.700 ;
        RECT 101.950 68.080 102.180 69.040 ;
        RECT 102.360 69.020 112.440 69.410 ;
        RECT 101.950 66.790 102.180 67.750 ;
        RECT 102.360 67.720 112.390 68.150 ;
        RECT 112.590 68.080 112.820 69.040 ;
        RECT 113.970 68.080 114.200 69.040 ;
        RECT 114.380 69.020 124.460 69.410 ;
        RECT 102.350 66.740 112.380 66.860 ;
        RECT 112.590 66.790 112.820 67.750 ;
        RECT 113.970 66.790 114.200 67.750 ;
        RECT 114.380 67.720 124.410 68.150 ;
        RECT 124.610 68.080 124.840 69.040 ;
        RECT 114.370 66.740 124.400 66.860 ;
        RECT 124.610 66.790 124.840 67.750 ;
        RECT 102.350 66.510 112.385 66.740 ;
        RECT 114.370 66.510 124.405 66.740 ;
        RECT 101.950 66.120 102.180 66.460 ;
        RECT 102.350 66.430 112.380 66.510 ;
        RECT 100.730 65.500 102.180 66.120 ;
        RECT 100.730 65.170 102.130 65.500 ;
        RECT 100.730 64.550 102.180 65.170 ;
        RECT 102.360 65.160 112.390 65.590 ;
        RECT 112.590 65.500 112.820 66.460 ;
        RECT 113.970 65.500 114.200 66.460 ;
        RECT 114.370 66.430 124.400 66.510 ;
        RECT 124.700 66.460 126.720 66.480 ;
        RECT 124.610 65.850 126.720 66.460 ;
        RECT 129.280 65.850 130.470 70.610 ;
        RECT 133.370 70.560 134.670 70.610 ;
        RECT 147.700 70.530 148.380 74.940 ;
        RECT 152.935 71.670 156.935 71.900 ;
        RECT 134.440 69.510 145.060 69.670 ;
        RECT 132.425 69.280 147.425 69.510 ;
        RECT 134.440 69.250 145.060 69.280 ;
        RECT 147.680 69.230 148.380 70.530 ;
        RECT 131.990 68.770 132.220 69.230 ;
        RECT 134.430 68.720 145.050 68.870 ;
        RECT 147.630 68.780 148.380 69.230 ;
        RECT 147.630 68.770 148.360 68.780 ;
        RECT 132.425 68.490 147.425 68.720 ;
        RECT 134.430 68.450 145.050 68.490 ;
        RECT 147.680 68.440 148.360 68.770 ;
        RECT 131.990 67.980 132.220 68.440 ;
        RECT 134.430 67.930 145.050 68.060 ;
        RECT 147.630 67.980 148.360 68.440 ;
        RECT 132.425 67.700 147.425 67.930 ;
        RECT 131.990 67.190 132.220 67.650 ;
        RECT 134.430 67.640 145.050 67.700 ;
        RECT 147.680 67.650 148.360 67.980 ;
        RECT 134.340 67.140 144.960 67.280 ;
        RECT 147.630 67.190 148.360 67.650 ;
        RECT 132.425 66.910 147.425 67.140 ;
        RECT 134.340 66.860 144.960 66.910 ;
        RECT 147.680 66.860 148.360 67.190 ;
        RECT 131.990 66.400 132.220 66.860 ;
        RECT 134.340 66.350 144.960 66.510 ;
        RECT 147.630 66.470 148.360 66.860 ;
        RECT 152.500 66.660 152.730 71.620 ;
        RECT 157.140 69.980 157.370 71.620 ;
        RECT 158.940 69.980 160.450 90.580 ;
        RECT 169.460 89.340 169.970 90.070 ;
        RECT 162.740 88.070 163.380 88.460 ;
        RECT 162.840 88.050 163.300 88.070 ;
        RECT 163.630 88.050 164.090 88.280 ;
        RECT 164.420 88.050 164.880 88.280 ;
        RECT 165.210 88.050 165.670 88.280 ;
        RECT 166.000 88.050 166.460 88.280 ;
        RECT 166.790 88.050 167.250 88.280 ;
        RECT 167.580 88.050 168.040 88.280 ;
        RECT 168.370 88.050 168.830 88.280 ;
        RECT 169.160 88.050 169.620 88.280 ;
        RECT 169.950 88.050 170.410 88.280 ;
        RECT 162.560 85.300 162.790 87.845 ;
        RECT 163.350 85.330 163.580 87.845 ;
        RECT 157.140 68.920 160.450 69.980 ;
        RECT 157.140 68.870 160.400 68.920 ;
        RECT 157.140 66.660 157.370 68.870 ;
        RECT 154.560 66.610 155.470 66.620 ;
        RECT 147.630 66.400 148.410 66.470 ;
        RECT 132.425 66.120 147.425 66.350 ;
        RECT 134.340 66.090 144.960 66.120 ;
        RECT 147.680 66.070 148.410 66.400 ;
        RECT 152.935 66.380 156.935 66.610 ;
        RECT 101.950 64.210 102.180 64.550 ;
        RECT 101.950 62.920 102.180 63.880 ;
        RECT 102.360 63.860 112.390 64.290 ;
        RECT 112.590 64.210 112.820 65.170 ;
        RECT 113.970 64.210 114.200 65.170 ;
        RECT 114.380 65.160 124.410 65.590 ;
        RECT 124.610 65.500 130.470 65.850 ;
        RECT 131.990 65.610 132.220 66.070 ;
        RECT 134.350 65.560 144.970 65.720 ;
        RECT 147.630 65.610 148.410 66.070 ;
        RECT 124.700 65.170 130.470 65.500 ;
        RECT 132.425 65.330 147.425 65.560 ;
        RECT 134.350 65.300 144.970 65.330 ;
        RECT 147.680 65.280 148.410 65.610 ;
        RECT 124.610 64.560 130.470 65.170 ;
        RECT 131.990 64.820 132.220 65.280 ;
        RECT 134.430 64.770 145.050 64.900 ;
        RECT 147.630 64.820 148.410 65.280 ;
        RECT 124.610 64.510 130.210 64.560 ;
        RECT 132.425 64.540 147.425 64.770 ;
        RECT 124.610 64.310 126.720 64.510 ;
        RECT 101.950 61.630 102.180 62.590 ;
        RECT 102.360 62.560 112.390 62.990 ;
        RECT 112.590 62.920 112.820 63.880 ;
        RECT 113.970 62.920 114.200 63.880 ;
        RECT 114.380 63.860 124.410 64.290 ;
        RECT 124.610 64.210 124.840 64.310 ;
        RECT 131.990 64.030 132.220 64.490 ;
        RECT 134.430 64.480 145.050 64.540 ;
        RECT 147.680 64.490 148.410 64.820 ;
        RECT 134.420 63.980 145.040 64.120 ;
        RECT 147.630 64.030 148.410 64.490 ;
        RECT 102.350 61.580 112.380 61.690 ;
        RECT 112.590 61.630 112.820 62.590 ;
        RECT 113.970 61.630 114.200 62.590 ;
        RECT 114.380 62.560 124.410 62.990 ;
        RECT 124.610 62.920 124.840 63.880 ;
        RECT 132.425 63.750 147.425 63.980 ;
        RECT 134.420 63.700 145.040 63.750 ;
        RECT 147.680 63.700 148.410 64.030 ;
        RECT 125.940 62.650 127.120 63.700 ;
        RECT 131.990 63.240 132.220 63.700 ;
        RECT 134.430 63.190 145.050 63.330 ;
        RECT 147.630 63.240 148.410 63.700 ;
        RECT 132.425 62.960 147.425 63.190 ;
        RECT 134.430 62.910 145.050 62.960 ;
        RECT 114.370 61.580 124.400 61.690 ;
        RECT 124.610 61.630 124.840 62.590 ;
        RECT 102.350 61.350 112.385 61.580 ;
        RECT 114.370 61.350 124.405 61.580 ;
        RECT 102.350 61.260 112.380 61.350 ;
        RECT 114.370 61.260 124.400 61.350 ;
        RECT 106.130 60.140 107.110 60.180 ;
        RECT 106.090 60.120 118.190 60.140 ;
        RECT 106.090 59.990 120.070 60.120 ;
        RECT 126.070 59.990 127.020 62.650 ;
        RECT 147.730 59.990 148.410 63.240 ;
        RECT 106.090 59.120 127.050 59.990 ;
        RECT 137.000 59.180 148.430 59.990 ;
        RECT 98.550 57.920 103.550 58.150 ;
        RECT 98.790 57.900 99.890 57.920 ;
        RECT 98.160 57.840 98.390 57.870 ;
        RECT 96.780 57.410 98.390 57.840 ;
        RECT 103.710 57.410 103.940 57.870 ;
        RECT 96.800 57.400 98.360 57.410 ;
        RECT 91.620 57.130 96.620 57.360 ;
        RECT 95.150 54.250 95.660 57.130 ;
        RECT 95.080 54.020 96.580 54.250 ;
        RECT 95.150 54.010 95.660 54.020 ;
        RECT 85.700 52.770 87.700 53.000 ;
        RECT 94.690 52.510 94.920 53.970 ;
        RECT 96.740 53.910 96.970 53.970 ;
        RECT 97.160 53.910 97.980 57.400 ;
        RECT 98.550 57.130 103.550 57.360 ;
        RECT 99.300 54.250 99.810 57.130 ;
        RECT 98.510 54.020 100.010 54.250 ;
        RECT 98.120 53.910 98.350 53.970 ;
        RECT 96.740 52.580 98.350 53.910 ;
        RECT 96.740 52.510 96.970 52.580 ;
        RECT 98.120 52.510 98.350 52.580 ;
        RECT 100.170 52.510 100.400 53.970 ;
        RECT 95.080 52.230 96.580 52.460 ;
        RECT 98.510 52.230 100.010 52.460 ;
        RECT 30.250 46.565 31.490 51.955 ;
        RECT 38.660 46.565 39.900 51.955 ;
        RECT 47.230 46.565 48.360 51.955 ;
        RECT 55.720 46.565 56.850 51.955 ;
        RECT 64.180 46.565 65.310 51.955 ;
        RECT 106.130 49.050 107.110 59.120 ;
        RECT 119.480 58.990 127.050 59.120 ;
        RECT 109.290 58.015 119.330 58.385 ;
        RECT 121.220 58.015 131.260 58.385 ;
        RECT 108.920 56.550 109.150 58.010 ;
        RECT 109.290 56.240 119.330 56.610 ;
        RECT 119.470 56.550 119.700 58.010 ;
        RECT 120.850 56.550 121.080 58.010 ;
        RECT 121.220 56.240 131.260 56.610 ;
        RECT 131.400 56.550 131.630 58.010 ;
        RECT 137.170 57.610 138.310 59.180 ;
        RECT 146.110 57.750 151.790 57.840 ;
        RECT 136.930 57.380 138.430 57.610 ;
        RECT 144.360 57.520 154.360 57.750 ;
        RECT 154.560 57.680 155.470 66.380 ;
        RECT 162.340 60.210 162.810 85.300 ;
        RECT 163.160 60.240 163.630 85.330 ;
        RECT 164.140 85.300 164.370 87.845 ;
        RECT 164.930 85.300 165.160 87.845 ;
        RECT 165.720 85.330 165.950 87.845 ;
        RECT 166.510 85.330 166.740 87.845 ;
        RECT 167.300 85.350 167.530 87.845 ;
        RECT 162.560 57.845 162.790 60.210 ;
        RECT 163.350 57.845 163.580 60.240 ;
        RECT 163.940 60.210 164.410 85.300 ;
        RECT 164.710 60.210 165.180 85.300 ;
        RECT 165.500 60.240 165.970 85.330 ;
        RECT 166.310 60.240 166.780 85.330 ;
        RECT 167.070 60.260 167.540 85.350 ;
        RECT 168.090 85.300 168.320 87.845 ;
        RECT 168.880 85.300 169.110 87.845 ;
        RECT 164.140 57.845 164.370 60.210 ;
        RECT 164.930 57.845 165.160 60.210 ;
        RECT 165.720 57.845 165.950 60.240 ;
        RECT 166.510 57.845 166.740 60.240 ;
        RECT 167.300 57.845 167.530 60.260 ;
        RECT 167.890 60.210 168.360 85.300 ;
        RECT 168.680 60.210 169.150 85.300 ;
        RECT 169.670 85.270 169.900 87.845 ;
        RECT 168.090 57.845 168.320 60.210 ;
        RECT 168.880 57.845 169.110 60.210 ;
        RECT 169.470 60.180 169.940 85.270 ;
        RECT 170.460 85.250 170.690 87.845 ;
        RECT 170.260 60.370 170.730 85.250 ;
        RECT 174.640 60.370 176.190 92.850 ;
        RECT 178.280 60.410 182.210 60.430 ;
        RECT 178.280 60.370 192.040 60.410 ;
        RECT 169.670 57.845 169.900 60.180 ;
        RECT 170.260 60.160 192.040 60.370 ;
        RECT 170.420 58.780 192.040 60.160 ;
        RECT 170.460 58.550 192.040 58.780 ;
        RECT 170.460 57.845 170.690 58.550 ;
        RECT 154.560 57.470 155.580 57.680 ;
        RECT 137.170 57.350 138.310 57.380 ;
        RECT 136.540 56.610 136.770 57.330 ;
        RECT 108.920 54.760 109.150 56.220 ;
        RECT 108.920 52.970 109.150 54.430 ;
        RECT 109.290 54.420 119.330 54.790 ;
        RECT 119.470 54.760 119.700 56.220 ;
        RECT 120.850 54.760 121.080 56.220 ;
        RECT 108.920 51.180 109.150 52.640 ;
        RECT 109.290 52.630 119.330 53.000 ;
        RECT 119.470 52.970 119.700 54.430 ;
        RECT 120.850 52.970 121.080 54.430 ;
        RECT 121.220 54.420 131.260 54.790 ;
        RECT 131.400 54.760 131.630 56.220 ;
        RECT 119.470 52.180 119.700 52.640 ;
        RECT 120.850 52.180 121.080 52.640 ;
        RECT 121.220 52.630 131.260 53.000 ;
        RECT 131.400 52.970 131.630 54.430 ;
        RECT 136.450 52.960 136.850 56.610 ;
        RECT 119.470 51.370 121.080 52.180 ;
        RECT 109.290 50.870 119.330 51.240 ;
        RECT 119.470 51.180 119.700 51.370 ;
        RECT 116.980 49.050 118.030 50.870 ;
        RECT 106.130 48.100 118.090 49.050 ;
        RECT 116.980 46.580 118.030 48.100 ;
        RECT 29.415 45.440 32.465 46.565 ;
        RECT 37.855 45.560 40.905 46.565 ;
        RECT 46.295 45.560 49.345 46.565 ;
        RECT 37.855 45.520 49.345 45.560 ;
        RECT 54.735 45.520 57.785 46.565 ;
        RECT 37.855 45.440 57.785 45.520 ;
        RECT 29.415 45.410 57.785 45.440 ;
        RECT 63.175 45.410 66.225 46.565 ;
        RECT 116.940 46.350 119.440 46.580 ;
        RECT 29.415 44.210 66.225 45.410 ;
        RECT 116.550 44.840 116.780 46.300 ;
        RECT 119.600 45.910 119.830 46.300 ;
        RECT 120.020 45.910 120.580 51.370 ;
        RECT 120.850 51.180 121.080 51.370 ;
        RECT 121.220 50.870 131.260 51.240 ;
        RECT 131.400 51.180 131.630 52.640 ;
        RECT 136.540 52.370 136.770 52.960 ;
        RECT 138.590 52.370 138.820 57.330 ;
        RECT 143.970 57.010 144.200 57.470 ;
        RECT 146.120 56.960 151.800 57.050 ;
        RECT 154.520 57.010 155.580 57.470 ;
        RECT 162.840 57.410 163.300 57.640 ;
        RECT 163.630 57.410 164.090 57.640 ;
        RECT 164.420 57.410 164.880 57.640 ;
        RECT 165.210 57.410 165.670 57.640 ;
        RECT 166.000 57.410 166.460 57.640 ;
        RECT 166.790 57.410 167.250 57.640 ;
        RECT 167.580 57.410 168.040 57.640 ;
        RECT 168.370 57.410 168.830 57.640 ;
        RECT 169.160 57.410 169.620 57.640 ;
        RECT 169.950 57.410 170.410 57.640 ;
        RECT 144.360 56.730 154.360 56.960 ;
        RECT 154.610 56.680 155.580 57.010 ;
        RECT 143.970 56.220 144.200 56.680 ;
        RECT 146.120 56.170 151.800 56.290 ;
        RECT 154.520 56.220 155.580 56.680 ;
        RECT 144.360 55.940 154.360 56.170 ;
        RECT 154.610 55.890 155.580 56.220 ;
        RECT 143.970 55.430 144.200 55.890 ;
        RECT 146.150 55.380 151.830 55.470 ;
        RECT 154.520 55.430 155.580 55.890 ;
        RECT 144.360 55.150 154.360 55.380 ;
        RECT 154.610 55.100 155.580 55.430 ;
        RECT 143.970 54.640 144.200 55.100 ;
        RECT 146.130 54.590 151.810 54.710 ;
        RECT 154.520 54.640 155.580 55.100 ;
        RECT 144.360 54.360 154.360 54.590 ;
        RECT 154.610 52.960 155.580 54.640 ;
        RECT 159.840 52.960 160.260 52.990 ;
        RECT 136.930 52.090 138.430 52.320 ;
        RECT 154.610 52.180 160.260 52.960 ;
        RECT 164.810 52.330 165.270 52.560 ;
        RECT 165.600 52.330 166.060 52.560 ;
        RECT 166.390 52.330 166.850 52.560 ;
        RECT 167.180 52.330 167.640 52.560 ;
        RECT 167.970 52.330 168.430 52.560 ;
        RECT 154.610 51.340 155.580 52.180 ;
        RECT 151.310 51.250 156.990 51.340 ;
        RECT 149.560 51.020 159.560 51.250 ;
        RECT 154.610 50.980 155.580 51.020 ;
        RECT 159.840 50.970 160.260 52.180 ;
        RECT 122.600 49.010 123.650 50.870 ;
        RECT 149.170 50.510 149.400 50.970 ;
        RECT 151.320 50.460 157.000 50.550 ;
        RECT 159.720 50.530 160.260 50.970 ;
        RECT 159.720 50.510 159.950 50.530 ;
        RECT 149.560 50.230 159.560 50.460 ;
        RECT 149.170 49.720 149.400 50.180 ;
        RECT 151.320 49.670 157.000 49.790 ;
        RECT 159.720 49.720 159.950 50.180 ;
        RECT 164.530 49.960 164.760 52.170 ;
        RECT 149.560 49.440 159.560 49.670 ;
        RECT 122.490 48.030 123.780 49.010 ;
        RECT 149.170 48.930 149.400 49.390 ;
        RECT 151.350 48.880 157.030 48.970 ;
        RECT 159.720 48.930 159.950 49.390 ;
        RECT 149.560 48.650 159.560 48.880 ;
        RECT 149.170 48.140 149.400 48.600 ;
        RECT 151.330 48.090 157.010 48.210 ;
        RECT 159.720 48.140 159.950 48.600 ;
        RECT 122.600 47.860 123.700 48.030 ;
        RECT 149.560 47.860 159.560 48.090 ;
        RECT 122.600 46.580 123.650 47.860 ;
        RECT 151.310 46.730 156.990 46.820 ;
        RECT 121.370 46.350 123.870 46.580 ;
        RECT 149.560 46.500 159.560 46.730 ;
        RECT 120.980 45.910 121.210 46.300 ;
        RECT 119.600 45.070 121.210 45.910 ;
        RECT 119.600 44.840 119.830 45.070 ;
        RECT 116.940 44.560 119.440 44.790 ;
        RECT 29.415 44.090 40.905 44.210 ;
        RECT 29.415 43.515 32.465 44.090 ;
        RECT 37.855 43.515 40.905 44.090 ;
        RECT 46.295 44.170 66.225 44.210 ;
        RECT 46.295 43.515 49.345 44.170 ;
        RECT 54.735 44.060 66.225 44.170 ;
        RECT 54.735 43.515 57.785 44.060 ;
        RECT 63.175 43.515 66.225 44.060 ;
        RECT 120.090 43.110 120.780 45.070 ;
        RECT 120.980 44.840 121.210 45.070 ;
        RECT 124.030 44.840 124.260 46.300 ;
        RECT 149.170 45.990 149.400 46.450 ;
        RECT 151.320 45.940 157.000 46.030 ;
        RECT 159.720 45.990 160.280 46.570 ;
        RECT 149.560 45.710 159.560 45.940 ;
        RECT 149.170 45.200 149.400 45.660 ;
        RECT 151.320 45.150 157.000 45.270 ;
        RECT 159.720 45.200 159.950 45.660 ;
        RECT 149.560 44.920 159.560 45.150 ;
        RECT 121.370 44.560 123.870 44.790 ;
        RECT 149.170 44.410 149.400 44.870 ;
        RECT 151.350 44.360 157.030 44.450 ;
        RECT 159.720 44.410 159.950 44.870 ;
        RECT 149.560 44.130 159.560 44.360 ;
        RECT 149.170 43.620 149.400 44.080 ;
        RECT 151.330 43.570 157.010 43.690 ;
        RECT 159.720 43.620 159.950 44.080 ;
        RECT 149.560 43.340 159.560 43.570 ;
        RECT 119.870 42.130 120.950 43.110 ;
        RECT 158.020 42.030 159.340 42.650 ;
        RECT 164.350 33.250 164.780 49.960 ;
        RECT 165.320 49.950 165.550 52.170 ;
        RECT 164.530 32.170 164.760 33.250 ;
        RECT 165.170 33.240 165.600 49.950 ;
        RECT 166.110 49.900 166.340 52.170 ;
        RECT 165.320 32.170 165.550 33.240 ;
        RECT 165.950 33.190 166.380 49.900 ;
        RECT 166.900 49.830 167.130 52.170 ;
        RECT 166.110 32.170 166.340 33.190 ;
        RECT 166.760 33.120 167.190 49.830 ;
        RECT 167.690 49.770 167.920 52.170 ;
        RECT 168.480 50.750 168.710 52.170 ;
        RECT 178.280 50.750 192.040 58.550 ;
        RECT 168.480 49.770 192.040 50.750 ;
        RECT 166.900 32.170 167.130 33.120 ;
        RECT 167.530 33.060 167.960 49.770 ;
        RECT 168.290 49.040 192.040 49.770 ;
        RECT 168.290 33.060 168.720 49.040 ;
        RECT 178.910 49.030 192.040 49.040 ;
        RECT 167.690 32.170 167.920 33.060 ;
        RECT 168.480 32.170 168.710 33.060 ;
        RECT 164.810 31.990 165.270 32.010 ;
        RECT 164.730 31.710 165.360 31.990 ;
        RECT 165.600 31.780 166.060 32.010 ;
        RECT 166.390 31.780 166.850 32.010 ;
        RECT 167.180 31.780 167.640 32.010 ;
        RECT 167.970 31.780 168.430 32.010 ;
      LAYER via ;
        RECT 25.530 155.610 26.850 156.110 ;
        RECT 65.760 153.750 72.430 158.440 ;
        RECT 120.600 164.150 121.170 164.570 ;
        RECT 109.540 162.790 110.050 163.360 ;
        RECT 114.820 162.790 119.720 163.050 ;
        RECT 121.840 162.790 126.740 163.050 ;
        RECT 139.550 162.980 149.190 163.280 ;
        RECT 102.380 161.480 108.350 161.760 ;
        RECT 114.810 161.510 119.710 161.770 ;
        RECT 139.550 162.210 149.190 162.510 ;
        RECT 121.830 161.510 126.730 161.770 ;
        RECT 102.350 159.180 108.320 159.460 ;
        RECT 139.580 161.410 149.220 161.710 ;
        RECT 139.560 160.610 149.200 160.910 ;
        RECT 114.820 160.230 119.720 160.490 ;
        RECT 121.840 160.230 126.740 160.490 ;
        RECT 87.840 152.920 97.800 153.210 ;
        RECT 102.550 156.880 108.520 157.160 ;
        RECT 114.820 158.930 119.720 159.190 ;
        RECT 139.530 159.830 149.170 160.130 ;
        RECT 121.840 158.930 126.740 159.190 ;
        RECT 139.500 159.000 149.140 159.300 ;
        RECT 114.820 157.610 119.710 157.870 ;
        RECT 139.480 158.240 149.120 158.540 ;
        RECT 121.840 157.610 126.730 157.870 ;
        RECT 120.620 155.450 120.940 156.060 ;
        RECT 139.510 157.460 149.150 157.760 ;
        RECT 139.550 156.110 149.190 156.410 ;
        RECT 139.550 155.340 149.190 155.640 ;
        RECT 139.580 154.540 149.220 154.840 ;
        RECT 114.940 153.620 119.560 153.880 ;
        RECT 121.960 153.620 126.580 153.880 ;
        RECT 139.560 153.740 149.200 154.040 ;
        RECT 99.860 152.920 109.820 153.210 ;
        RECT 87.830 151.630 97.790 151.920 ;
        RECT 114.940 152.830 119.560 153.090 ;
        RECT 121.960 152.830 126.580 153.090 ;
        RECT 139.530 152.960 149.170 153.260 ;
        RECT 114.960 152.040 119.580 152.300 ;
        RECT 121.980 152.040 126.600 152.300 ;
        RECT 139.500 152.130 149.140 152.430 ;
        RECT 99.850 151.630 109.810 151.920 ;
        RECT 87.830 150.320 97.810 150.650 ;
        RECT 99.850 150.320 109.830 150.650 ;
        RECT 114.920 151.250 119.540 151.510 ;
        RECT 121.940 151.250 126.560 151.510 ;
        RECT 139.480 151.370 149.120 151.670 ;
        RECT 114.930 150.470 119.550 150.730 ;
        RECT 51.770 145.970 52.610 146.300 ;
        RECT 25.730 143.460 26.280 144.770 ;
        RECT 39.490 124.240 39.750 128.140 ;
        RECT 40.780 124.240 41.040 128.140 ;
        RECT 42.070 124.240 42.330 128.140 ;
        RECT 43.360 124.240 43.620 128.140 ;
        RECT 44.650 124.240 44.910 128.140 ;
        RECT 45.940 124.240 46.200 128.140 ;
        RECT 47.300 124.240 47.560 128.140 ;
        RECT 48.590 124.240 48.850 128.140 ;
        RECT 49.880 124.240 50.140 128.140 ;
        RECT 51.170 124.240 51.430 128.140 ;
        RECT 52.460 124.240 52.720 128.140 ;
        RECT 53.750 124.240 54.010 128.140 ;
        RECT 59.190 125.880 59.460 126.780 ;
        RECT 52.960 123.680 53.660 124.010 ;
        RECT 24.740 110.650 26.430 111.290 ;
        RECT 38.110 110.710 38.370 114.590 ;
        RECT 39.400 110.710 39.660 114.590 ;
        RECT 40.690 110.710 40.950 114.590 ;
        RECT 41.980 110.710 42.240 114.590 ;
        RECT 43.270 110.710 43.530 114.590 ;
        RECT 44.560 110.710 44.820 114.590 ;
        RECT 47.940 110.470 48.200 114.350 ;
        RECT 49.250 110.470 49.510 114.350 ;
        RECT 50.540 110.470 50.800 114.350 ;
        RECT 51.830 110.470 52.090 114.350 ;
        RECT 53.120 110.470 53.380 114.350 ;
        RECT 54.410 110.470 54.670 114.350 ;
        RECT 53.700 109.860 54.320 110.180 ;
        RECT 38.110 104.780 38.370 108.660 ;
        RECT 39.400 104.780 39.660 108.660 ;
        RECT 40.690 104.780 40.950 108.660 ;
        RECT 41.980 104.780 42.240 108.660 ;
        RECT 43.270 104.780 43.530 108.660 ;
        RECT 44.560 104.780 44.820 108.660 ;
        RECT 59.170 109.110 59.450 110.000 ;
        RECT 47.940 104.450 48.200 108.330 ;
        RECT 49.250 104.450 49.510 108.330 ;
        RECT 50.540 104.450 50.800 108.330 ;
        RECT 51.830 104.450 52.090 108.330 ;
        RECT 53.120 104.450 53.380 108.330 ;
        RECT 54.410 104.450 54.670 108.330 ;
        RECT 40.700 95.130 41.180 97.300 ;
        RECT 45.440 95.150 45.830 97.340 ;
        RECT 48.820 92.500 49.260 94.680 ;
        RECT 48.790 89.230 49.310 91.390 ;
        RECT 53.370 89.800 53.630 93.690 ;
        RECT 54.160 89.800 54.420 93.690 ;
        RECT 54.950 89.800 55.210 93.690 ;
        RECT 55.740 89.800 56.000 93.690 ;
        RECT 56.530 89.800 56.790 93.690 ;
        RECT 57.320 89.800 57.580 93.690 ;
        RECT 56.930 89.250 57.290 89.510 ;
        RECT 121.950 150.470 126.570 150.730 ;
        RECT 139.510 150.590 149.150 150.890 ;
        RECT 122.920 147.880 125.090 148.330 ;
        RECT 124.230 144.830 125.390 146.040 ;
        RECT 99.100 143.830 109.060 144.110 ;
        RECT 111.120 143.830 121.080 144.110 ;
        RECT 131.170 144.060 141.710 144.360 ;
        RECT 99.110 142.520 109.040 142.810 ;
        RECT 131.180 143.240 141.720 143.540 ;
        RECT 111.130 142.520 121.060 142.810 ;
        RECT 131.150 142.450 141.690 142.750 ;
        RECT 131.100 141.650 141.640 141.950 ;
        RECT 99.110 141.240 109.040 141.530 ;
        RECT 111.130 141.240 121.060 141.530 ;
        RECT 97.610 139.520 98.050 140.670 ;
        RECT 99.110 139.960 109.040 140.250 ;
        RECT 111.130 139.960 121.060 140.250 ;
        RECT 99.110 138.670 109.040 138.960 ;
        RECT 122.640 139.320 123.210 140.930 ;
        RECT 131.090 140.880 141.630 141.180 ;
        RECT 166.230 164.180 166.580 164.680 ;
        RECT 159.480 162.810 160.020 163.200 ;
        RECT 131.100 140.100 141.640 140.400 ;
        RECT 111.130 138.670 121.060 138.960 ;
        RECT 99.100 137.370 109.030 137.660 ;
        RECT 111.120 137.370 121.050 137.660 ;
        RECT 122.680 137.390 123.760 138.440 ;
        RECT 99.100 136.080 109.030 136.370 ;
        RECT 111.120 136.080 121.050 136.370 ;
        RECT 131.180 139.280 141.720 139.580 ;
        RECT 131.150 138.510 141.690 138.810 ;
        RECT 131.170 137.720 141.710 138.020 ;
        RECT 93.940 129.870 94.560 130.860 ;
        RECT 106.040 132.795 115.970 133.085 ;
        RECT 117.970 132.795 127.900 133.085 ;
        RECT 106.040 131.020 115.970 131.310 ;
        RECT 117.970 131.020 127.900 131.310 ;
        RECT 106.040 129.200 115.970 129.490 ;
        RECT 117.970 129.200 127.900 129.490 ;
        RECT 106.040 127.410 115.970 127.700 ;
        RECT 117.970 127.410 127.900 127.700 ;
        RECT 106.040 125.650 115.970 125.940 ;
        RECT 117.970 125.650 127.900 125.940 ;
        RECT 119.230 122.770 120.420 123.750 ;
        RECT 116.610 116.870 117.590 117.850 ;
        RECT 87.510 107.000 94.550 115.880 ;
        RECT 125.950 114.340 127.680 115.850 ;
        RECT 142.850 132.270 148.430 132.580 ;
        RECT 159.080 134.950 159.450 160.040 ;
        RECT 159.900 134.980 160.270 160.070 ;
        RECT 160.680 134.950 161.050 160.040 ;
        RECT 161.450 134.950 161.820 160.040 ;
        RECT 162.240 134.980 162.610 160.070 ;
        RECT 163.050 134.980 163.420 160.070 ;
        RECT 163.810 135.000 164.180 160.090 ;
        RECT 164.630 134.950 165.000 160.040 ;
        RECT 165.420 134.950 165.790 160.040 ;
        RECT 166.210 134.920 166.580 160.010 ;
        RECT 167.000 134.900 167.370 159.990 ;
        RECT 133.190 127.700 133.490 131.350 ;
        RECT 142.860 131.480 148.440 131.790 ;
        RECT 142.860 130.720 148.440 131.030 ;
        RECT 142.890 129.900 148.470 130.210 ;
        RECT 142.870 129.140 148.450 129.450 ;
        RECT 178.090 128.920 180.190 131.030 ;
        RECT 148.050 125.770 153.630 126.080 ;
        RECT 148.060 124.980 153.640 125.290 ;
        RECT 148.060 124.220 153.640 124.530 ;
        RECT 148.090 123.400 153.670 123.710 ;
        RECT 148.070 122.640 153.650 122.950 ;
        RECT 148.050 121.250 153.630 121.560 ;
        RECT 148.060 120.460 153.640 120.770 ;
        RECT 156.460 120.730 156.920 121.310 ;
        RECT 148.060 119.700 153.640 120.010 ;
        RECT 148.090 118.880 153.670 119.190 ;
        RECT 148.070 118.120 153.650 118.430 ;
        RECT 154.950 116.930 155.850 117.270 ;
        RECT 110.710 105.500 113.230 108.150 ;
        RECT 98.920 97.340 102.320 101.870 ;
        RECT 111.410 101.670 112.200 102.460 ;
        RECT 161.090 107.990 161.420 124.700 ;
        RECT 161.910 107.980 162.240 124.690 ;
        RECT 162.690 107.930 163.020 124.640 ;
        RECT 163.500 107.860 163.830 124.570 ;
        RECT 164.270 107.800 164.600 124.510 ;
        RECT 165.030 107.800 165.360 124.510 ;
        RECT 183.510 124.210 188.370 134.780 ;
        RECT 161.470 106.450 162.000 106.730 ;
        RECT 51.320 84.190 51.650 84.650 ;
        RECT 77.860 84.550 80.420 86.060 ;
        RECT 123.910 89.410 124.480 89.830 ;
        RECT 112.850 88.050 113.360 88.620 ;
        RECT 118.130 88.050 123.030 88.310 ;
        RECT 125.150 88.050 130.050 88.310 ;
        RECT 142.860 88.240 152.500 88.540 ;
        RECT 105.690 86.740 111.660 87.020 ;
        RECT 118.120 86.770 123.020 87.030 ;
        RECT 125.140 86.770 130.040 87.030 ;
        RECT 133.560 87.030 134.440 88.080 ;
        RECT 142.860 87.470 152.500 87.770 ;
        RECT 105.660 84.440 111.630 84.720 ;
        RECT 118.130 85.490 123.030 85.750 ;
        RECT 125.150 85.490 130.050 85.750 ;
        RECT 91.150 78.180 101.110 78.470 ;
        RECT 105.860 82.140 111.830 82.420 ;
        RECT 118.130 84.190 123.030 84.450 ;
        RECT 125.150 84.190 130.050 84.450 ;
        RECT 118.130 82.870 123.020 83.130 ;
        RECT 125.150 82.870 130.040 83.130 ;
        RECT 123.930 80.710 124.250 81.320 ;
        RECT 118.250 78.880 122.870 79.140 ;
        RECT 125.270 78.880 129.890 79.140 ;
        RECT 103.170 78.180 113.130 78.470 ;
        RECT 91.140 76.890 101.100 77.180 ;
        RECT 118.250 78.090 122.870 78.350 ;
        RECT 125.270 78.090 129.890 78.350 ;
        RECT 118.270 77.300 122.890 77.560 ;
        RECT 125.290 77.300 129.910 77.560 ;
        RECT 103.160 76.890 113.120 77.180 ;
        RECT 91.140 75.580 101.120 75.910 ;
        RECT 103.160 75.580 113.140 75.910 ;
        RECT 118.230 76.510 122.850 76.770 ;
        RECT 125.250 76.510 129.870 76.770 ;
        RECT 118.240 75.730 122.860 75.990 ;
        RECT 125.260 75.730 129.880 75.990 ;
        RECT 126.230 73.140 128.400 73.590 ;
        RECT 142.890 86.670 152.530 86.970 ;
        RECT 142.870 85.870 152.510 86.170 ;
        RECT 142.840 85.090 152.480 85.390 ;
        RECT 142.810 84.260 152.450 84.560 ;
        RECT 142.790 83.500 152.430 83.800 ;
        RECT 142.820 82.720 152.460 83.020 ;
        RECT 142.860 81.370 152.500 81.670 ;
        RECT 142.860 80.600 152.500 80.900 ;
        RECT 142.890 79.800 152.530 80.100 ;
        RECT 142.870 79.000 152.510 79.300 ;
        RECT 142.840 78.220 152.480 78.520 ;
        RECT 142.810 77.390 152.450 77.690 ;
        RECT 142.790 76.630 152.430 76.930 ;
        RECT 142.820 75.850 152.460 76.150 ;
        RECT 127.540 70.090 128.700 71.300 ;
        RECT 102.410 69.090 112.370 69.370 ;
        RECT 114.430 69.090 124.390 69.370 ;
        RECT 102.420 67.780 112.350 68.070 ;
        RECT 114.440 67.780 124.370 68.070 ;
        RECT 102.420 66.500 112.350 66.790 ;
        RECT 114.440 66.500 124.370 66.790 ;
        RECT 100.920 64.780 101.360 65.930 ;
        RECT 102.420 65.220 112.350 65.510 ;
        RECT 114.440 65.220 124.370 65.510 ;
        RECT 102.420 63.930 112.350 64.220 ;
        RECT 125.950 64.580 126.520 66.190 ;
        RECT 134.480 69.320 145.020 69.620 ;
        RECT 134.490 68.500 145.030 68.800 ;
        RECT 134.460 67.710 145.000 68.010 ;
        RECT 134.410 66.910 144.950 67.210 ;
        RECT 134.400 66.140 144.940 66.440 ;
        RECT 169.540 89.440 169.890 89.940 ;
        RECT 162.790 88.070 163.330 88.460 ;
        RECT 134.410 65.360 144.950 65.660 ;
        RECT 134.490 64.540 145.030 64.840 ;
        RECT 114.440 63.930 124.370 64.220 ;
        RECT 134.460 63.770 145.000 64.070 ;
        RECT 102.410 62.630 112.340 62.920 ;
        RECT 114.430 62.630 124.360 62.920 ;
        RECT 125.990 62.650 127.070 63.700 ;
        RECT 134.480 62.980 145.020 63.280 ;
        RECT 102.410 61.340 112.340 61.630 ;
        RECT 114.430 61.340 124.360 61.630 ;
        RECT 97.250 55.130 97.870 56.120 ;
        RECT 109.350 58.055 119.280 58.345 ;
        RECT 121.280 58.055 131.210 58.345 ;
        RECT 109.350 56.280 119.280 56.570 ;
        RECT 121.280 56.280 131.210 56.570 ;
        RECT 146.160 57.530 151.740 57.840 ;
        RECT 162.390 60.210 162.760 85.300 ;
        RECT 163.210 60.240 163.580 85.330 ;
        RECT 163.990 60.210 164.360 85.300 ;
        RECT 164.760 60.210 165.130 85.300 ;
        RECT 165.550 60.240 165.920 85.330 ;
        RECT 166.360 60.240 166.730 85.330 ;
        RECT 167.120 60.260 167.490 85.350 ;
        RECT 167.940 60.210 168.310 85.300 ;
        RECT 168.730 60.210 169.100 85.300 ;
        RECT 169.520 60.180 169.890 85.270 ;
        RECT 170.310 60.160 170.680 85.250 ;
        RECT 109.350 54.460 119.280 54.750 ;
        RECT 121.280 54.460 131.210 54.750 ;
        RECT 109.350 52.670 119.280 52.960 ;
        RECT 136.500 52.960 136.800 56.610 ;
        RECT 121.280 52.670 131.210 52.960 ;
        RECT 109.350 50.910 119.280 51.200 ;
        RECT 121.280 50.910 131.210 51.200 ;
        RECT 146.170 56.740 151.750 57.050 ;
        RECT 146.170 55.980 151.750 56.290 ;
        RECT 146.200 55.160 151.780 55.470 ;
        RECT 146.180 54.400 151.760 54.710 ;
        RECT 181.400 54.180 183.500 56.290 ;
        RECT 151.360 51.030 156.940 51.340 ;
        RECT 151.370 50.240 156.950 50.550 ;
        RECT 151.370 49.480 156.950 49.790 ;
        RECT 122.540 48.030 123.730 49.010 ;
        RECT 151.400 48.660 156.980 48.970 ;
        RECT 151.380 47.900 156.960 48.210 ;
        RECT 151.360 46.510 156.940 46.820 ;
        RECT 151.370 45.720 156.950 46.030 ;
        RECT 159.770 45.990 160.230 46.570 ;
        RECT 151.370 44.960 156.950 45.270 ;
        RECT 151.400 44.140 156.980 44.450 ;
        RECT 151.380 43.380 156.960 43.690 ;
        RECT 119.920 42.130 120.900 43.110 ;
        RECT 158.260 42.190 159.160 42.530 ;
        RECT 164.400 33.250 164.730 49.960 ;
        RECT 165.220 33.240 165.550 49.950 ;
        RECT 166.000 33.190 166.330 49.900 ;
        RECT 166.810 33.120 167.140 49.830 ;
        RECT 167.580 33.060 167.910 49.770 ;
        RECT 168.340 33.060 168.670 49.770 ;
        RECT 164.780 31.710 165.310 31.990 ;
      LAYER met2 ;
        RECT 101.070 161.810 103.070 161.820 ;
        RECT 101.070 161.430 108.350 161.810 ;
        RECT 101.070 161.420 103.070 161.430 ;
        RECT 25.050 155.260 27.290 156.480 ;
        RECT 63.710 151.940 74.730 160.230 ;
        RECT 101.070 157.200 101.500 161.420 ;
        RECT 109.430 159.530 110.150 163.480 ;
        RECT 114.070 163.100 114.390 163.170 ;
        RECT 113.930 162.810 119.750 163.100 ;
        RECT 114.070 160.490 114.390 162.810 ;
        RECT 114.790 162.750 119.750 162.810 ;
        RECT 114.780 161.790 119.740 161.820 ;
        RECT 120.460 161.790 121.290 164.700 ;
        RECT 155.570 164.030 157.150 165.480 ;
        RECT 155.570 163.900 160.060 164.030 ;
        RECT 135.920 163.330 136.220 163.340 ;
        RECT 139.510 163.330 149.240 163.340 ;
        RECT 121.810 163.050 126.770 163.100 ;
        RECT 121.810 163.030 127.420 163.050 ;
        RECT 121.810 162.760 127.490 163.030 ;
        RECT 135.870 162.960 149.240 163.330 ;
        RECT 121.810 162.750 126.770 162.760 ;
        RECT 121.800 161.790 126.760 161.820 ;
        RECT 114.780 161.470 126.760 161.790 ;
        RECT 114.790 160.490 119.760 160.530 ;
        RECT 113.930 160.200 119.760 160.490 ;
        RECT 108.160 159.510 110.150 159.530 ;
        RECT 102.350 159.130 110.150 159.510 ;
        RECT 108.160 159.110 110.150 159.130 ;
        RECT 114.070 157.880 114.390 160.200 ;
        RECT 114.790 160.190 119.760 160.200 ;
        RECT 114.790 159.210 119.760 159.240 ;
        RECT 120.140 159.210 120.480 161.470 ;
        RECT 114.790 158.960 120.480 159.210 ;
        RECT 121.250 159.170 121.590 161.470 ;
        RECT 121.810 160.490 126.780 160.530 ;
        RECT 127.200 160.490 127.490 162.760 ;
        RECT 135.920 161.730 136.220 162.960 ;
        RECT 139.510 162.950 149.240 162.960 ;
        RECT 155.580 162.870 160.060 163.900 ;
        RECT 139.510 162.460 149.240 162.550 ;
        RECT 151.640 162.460 152.000 162.480 ;
        RECT 139.510 162.190 152.000 162.460 ;
        RECT 139.510 162.160 149.240 162.190 ;
        RECT 139.530 161.730 149.260 161.750 ;
        RECT 135.920 161.360 149.260 161.730 ;
        RECT 121.810 160.200 127.540 160.490 ;
        RECT 121.810 160.190 126.780 160.200 ;
        RECT 121.810 159.170 126.780 159.240 ;
        RECT 114.790 158.880 119.760 158.960 ;
        RECT 121.250 158.920 126.780 159.170 ;
        RECT 121.810 158.880 126.780 158.920 ;
        RECT 114.790 157.880 119.740 157.910 ;
        RECT 114.070 157.590 119.740 157.880 ;
        RECT 114.790 157.570 119.740 157.590 ;
        RECT 121.810 157.900 126.760 157.910 ;
        RECT 127.200 157.900 127.490 160.200 ;
        RECT 135.920 160.150 136.220 161.360 ;
        RECT 139.500 160.860 149.230 160.940 ;
        RECT 151.640 160.860 152.000 162.190 ;
        RECT 139.500 160.590 152.000 160.860 ;
        RECT 139.500 160.550 149.230 160.590 ;
        RECT 139.480 160.150 149.210 160.170 ;
        RECT 135.910 159.780 149.210 160.150 ;
        RECT 135.920 158.600 136.220 159.780 ;
        RECT 139.450 159.260 149.180 159.330 ;
        RECT 151.640 159.260 152.000 160.590 ;
        RECT 139.450 158.990 152.000 159.260 ;
        RECT 139.450 158.940 149.180 158.990 ;
        RECT 135.920 158.580 139.770 158.600 ;
        RECT 135.920 158.230 149.160 158.580 ;
        RECT 139.430 158.190 149.160 158.230 ;
        RECT 121.810 157.610 127.490 157.900 ;
        RECT 121.810 157.570 126.760 157.610 ;
        RECT 127.200 157.590 127.490 157.610 ;
        RECT 139.460 157.680 149.190 157.780 ;
        RECT 151.640 157.680 152.000 158.990 ;
        RECT 139.460 157.430 152.000 157.680 ;
        RECT 139.460 157.410 151.950 157.430 ;
        RECT 139.460 157.390 149.190 157.410 ;
        RECT 102.550 157.200 108.520 157.210 ;
        RECT 101.070 156.830 108.520 157.200 ;
        RECT 101.070 156.820 103.090 156.830 ;
        RECT 101.110 156.800 103.090 156.820 ;
        RECT 135.860 156.420 136.210 156.430 ;
        RECT 139.510 156.420 149.240 156.470 ;
        RECT 114.260 153.950 114.530 153.960 ;
        RECT 114.200 153.930 115.660 153.950 ;
        RECT 114.200 153.600 119.590 153.930 ;
        RECT 87.220 152.920 97.850 153.280 ;
        RECT 99.240 152.920 109.870 153.280 ;
        RECT 87.250 150.660 87.550 152.920 ;
        RECT 87.780 152.850 97.850 152.920 ;
        RECT 87.770 151.590 97.860 151.950 ;
        RECT 87.780 150.660 97.860 150.680 ;
        RECT 87.250 150.300 97.860 150.660 ;
        RECT 99.270 150.660 99.570 152.920 ;
        RECT 99.800 152.850 109.870 152.920 ;
        RECT 114.260 152.350 114.530 153.600 ;
        RECT 114.910 153.590 119.590 153.600 ;
        RECT 114.910 153.100 119.590 153.130 ;
        RECT 120.530 153.100 121.050 156.240 ;
        RECT 135.840 156.080 149.240 156.420 ;
        RECT 135.840 156.050 139.820 156.080 ;
        RECT 135.860 154.870 136.210 156.050 ;
        RECT 139.510 155.590 149.240 155.680 ;
        RECT 139.510 155.560 151.950 155.590 ;
        RECT 139.510 155.290 151.980 155.560 ;
        RECT 148.950 155.270 151.980 155.290 ;
        RECT 139.530 154.870 149.260 154.880 ;
        RECT 135.860 154.500 149.260 154.870 ;
        RECT 121.930 153.910 126.610 153.930 ;
        RECT 121.310 153.590 126.610 153.910 ;
        RECT 114.910 152.790 121.050 153.100 ;
        RECT 119.430 152.750 121.050 152.790 ;
        RECT 114.170 152.340 115.630 152.350 ;
        RECT 114.170 152.000 119.620 152.340 ;
        RECT 99.790 151.600 110.850 151.950 ;
        RECT 99.790 151.590 109.880 151.600 ;
        RECT 99.800 150.660 109.880 150.680 ;
        RECT 99.270 150.300 109.880 150.660 ;
        RECT 87.780 150.260 97.860 150.300 ;
        RECT 99.800 150.260 109.880 150.300 ;
        RECT 110.090 146.990 110.850 151.600 ;
        RECT 114.260 150.790 114.530 152.000 ;
        RECT 120.530 151.550 121.050 152.750 ;
        RECT 121.340 152.310 121.590 153.590 ;
        RECT 135.860 153.260 136.210 154.500 ;
        RECT 139.530 154.490 149.260 154.500 ;
        RECT 139.500 154.000 149.230 154.070 ;
        RECT 151.590 154.000 151.980 155.270 ;
        RECT 139.500 153.680 152.050 154.000 ;
        RECT 139.480 153.260 149.210 153.300 ;
        RECT 121.930 153.090 126.610 153.130 ;
        RECT 127.050 153.090 127.380 153.110 ;
        RECT 121.930 152.800 127.380 153.090 ;
        RECT 135.840 152.910 149.210 153.260 ;
        RECT 135.840 152.890 139.820 152.910 ;
        RECT 121.930 152.790 126.610 152.800 ;
        RECT 121.960 152.310 126.640 152.340 ;
        RECT 121.320 152.000 126.640 152.310 ;
        RECT 121.320 151.990 122.100 152.000 ;
        RECT 114.890 151.210 121.050 151.550 ;
        RECT 119.460 151.200 121.050 151.210 ;
        RECT 114.260 150.770 115.720 150.790 ;
        RECT 114.260 150.440 119.580 150.770 ;
        RECT 114.900 150.430 119.580 150.440 ;
        RECT 120.530 148.320 121.050 151.200 ;
        RECT 121.340 150.750 121.590 151.990 ;
        RECT 127.050 151.850 127.380 152.800 ;
        RECT 121.910 151.510 126.590 151.550 ;
        RECT 127.050 151.510 129.650 151.850 ;
        RECT 121.910 151.220 129.650 151.510 ;
        RECT 135.860 151.680 136.210 152.890 ;
        RECT 139.450 152.380 149.180 152.460 ;
        RECT 151.590 152.380 151.980 153.680 ;
        RECT 139.450 152.070 152.020 152.380 ;
        RECT 149.020 152.060 152.020 152.070 ;
        RECT 139.430 151.680 149.160 151.710 ;
        RECT 135.860 151.320 149.160 151.680 ;
        RECT 135.860 151.310 139.840 151.320 ;
        RECT 121.910 151.210 126.590 151.220 ;
        RECT 127.130 151.190 129.650 151.220 ;
        RECT 121.920 150.750 126.600 150.770 ;
        RECT 121.340 150.430 126.600 150.750 ;
        RECT 122.860 148.320 125.140 148.400 ;
        RECT 120.530 147.870 125.140 148.320 ;
        RECT 122.860 147.850 125.140 147.870 ;
        RECT 128.940 147.790 129.650 151.190 ;
        RECT 139.460 150.870 149.190 150.910 ;
        RECT 151.590 150.870 151.980 152.060 ;
        RECT 139.460 150.550 152.000 150.870 ;
        RECT 139.460 150.520 149.190 150.550 ;
        RECT 151.590 150.520 151.980 150.550 ;
        RECT 155.580 149.090 157.190 162.870 ;
        RECT 159.480 162.760 160.020 162.870 ;
        RECT 159.840 161.880 160.270 161.900 ;
        RECT 161.400 161.880 161.830 161.920 ;
        RECT 163.020 161.880 163.450 161.940 ;
        RECT 164.590 161.880 165.020 161.930 ;
        RECT 166.150 161.880 166.650 164.800 ;
        RECT 159.840 161.440 166.650 161.880 ;
        RECT 145.800 148.030 157.190 149.090 ;
        RECT 145.800 147.830 147.170 148.030 ;
        RECT 136.170 147.790 147.170 147.830 ;
        RECT 128.940 147.110 147.170 147.790 ;
        RECT 104.670 146.970 112.590 146.990 ;
        RECT 104.670 146.460 112.600 146.970 ;
        RECT 51.750 146.320 52.650 146.330 ;
        RECT 51.740 145.930 52.650 146.320 ;
        RECT 51.750 145.270 52.650 145.930 ;
        RECT 51.750 145.260 57.040 145.270 ;
        RECT 25.350 143.130 26.680 145.040 ;
        RECT 51.750 144.500 57.120 145.260 ;
        RECT 51.770 144.450 57.120 144.500 ;
        RECT 40.740 128.610 46.240 128.630 ;
        RECT 40.740 128.310 46.250 128.610 ;
        RECT 40.740 128.160 41.070 128.310 ;
        RECT 43.320 128.160 43.650 128.310 ;
        RECT 45.920 128.160 46.250 128.310 ;
        RECT 48.550 128.340 54.070 128.590 ;
        RECT 39.460 124.210 39.790 128.160 ;
        RECT 40.740 127.970 41.080 128.160 ;
        RECT 40.750 124.210 41.080 127.970 ;
        RECT 42.040 124.210 42.370 128.160 ;
        RECT 43.320 127.870 43.660 128.160 ;
        RECT 43.330 124.210 43.660 127.870 ;
        RECT 44.620 124.210 44.950 128.160 ;
        RECT 45.910 127.950 46.250 128.160 ;
        RECT 45.910 126.760 46.240 127.950 ;
        RECT 47.270 126.760 47.600 128.160 ;
        RECT 48.550 128.050 48.890 128.340 ;
        RECT 51.150 128.160 51.450 128.340 ;
        RECT 45.910 125.720 47.600 126.760 ;
        RECT 45.910 124.210 46.240 125.720 ;
        RECT 47.270 124.210 47.600 125.720 ;
        RECT 48.560 124.210 48.890 128.050 ;
        RECT 49.850 124.210 50.180 128.160 ;
        RECT 51.140 124.210 51.470 128.160 ;
        RECT 52.430 124.210 52.760 128.160 ;
        RECT 53.720 128.030 54.060 128.340 ;
        RECT 53.720 124.210 54.050 128.030 ;
        RECT 39.490 124.050 39.780 124.210 ;
        RECT 42.060 124.050 42.350 124.210 ;
        RECT 44.640 124.050 44.930 124.210 ;
        RECT 39.490 123.780 44.930 124.050 ;
        RECT 47.290 124.030 47.590 124.210 ;
        RECT 49.880 124.030 50.180 124.210 ;
        RECT 52.450 124.030 52.750 124.210 ;
        RECT 39.520 123.770 44.920 123.780 ;
        RECT 47.290 123.760 52.760 124.030 ;
        RECT 52.910 119.270 53.710 124.040 ;
        RECT 56.120 120.850 57.120 144.450 ;
        RECT 98.440 144.150 99.750 144.190 ;
        RECT 104.670 144.150 105.380 146.460 ;
        RECT 111.890 144.150 112.600 146.460 ;
        RECT 135.870 146.960 147.170 147.110 ;
        RECT 124.230 146.050 125.390 146.090 ;
        RECT 124.230 144.780 125.400 146.050 ;
        RECT 98.440 143.790 109.130 144.150 ;
        RECT 98.450 141.590 98.810 143.790 ;
        RECT 99.050 143.760 109.130 143.790 ;
        RECT 110.510 144.120 110.890 144.150 ;
        RECT 111.070 144.120 121.150 144.150 ;
        RECT 110.510 143.760 121.150 144.120 ;
        RECT 110.510 143.740 111.680 143.760 ;
        RECT 99.050 142.850 109.080 142.890 ;
        RECT 99.050 142.500 109.720 142.850 ;
        RECT 99.050 142.460 109.080 142.500 ;
        RECT 99.040 141.590 109.070 141.600 ;
        RECT 98.420 141.190 109.070 141.590 ;
        RECT 97.460 139.330 98.200 140.850 ;
        RECT 98.450 139.030 98.810 141.190 ;
        RECT 99.040 141.170 109.070 141.190 ;
        RECT 99.050 140.270 109.080 140.330 ;
        RECT 109.300 140.270 109.720 142.500 ;
        RECT 99.050 139.920 109.720 140.270 ;
        RECT 99.050 139.900 109.080 139.920 ;
        RECT 98.420 138.630 109.080 139.030 ;
        RECT 98.450 136.430 98.810 138.630 ;
        RECT 99.050 138.600 109.080 138.630 ;
        RECT 109.300 138.180 109.720 139.920 ;
        RECT 110.510 141.580 110.890 143.740 ;
        RECT 111.070 142.800 121.100 142.890 ;
        RECT 111.070 142.500 121.710 142.800 ;
        RECT 111.070 142.460 121.100 142.500 ;
        RECT 111.060 141.580 121.090 141.600 ;
        RECT 110.510 141.200 121.090 141.580 ;
        RECT 110.510 138.990 110.890 141.200 ;
        RECT 111.060 141.170 121.090 141.200 ;
        RECT 111.070 140.210 121.100 140.330 ;
        RECT 121.330 140.210 121.710 142.500 ;
        RECT 111.070 139.910 121.710 140.210 ;
        RECT 111.070 139.900 121.100 139.910 ;
        RECT 111.070 138.990 121.100 139.030 ;
        RECT 110.510 138.610 121.100 138.990 ;
        RECT 99.050 137.700 109.080 137.730 ;
        RECT 109.300 137.700 109.760 138.180 ;
        RECT 99.050 137.350 109.760 137.700 ;
        RECT 99.050 137.300 109.080 137.350 ;
        RECT 98.450 136.030 109.070 136.430 ;
        RECT 99.040 136.000 109.070 136.030 ;
        RECT 109.300 136.230 109.760 137.350 ;
        RECT 110.510 136.370 110.890 138.610 ;
        RECT 111.070 138.600 121.100 138.610 ;
        RECT 121.330 138.440 121.710 139.910 ;
        RECT 122.440 139.050 123.390 141.220 ;
        RECT 122.680 138.440 123.760 138.490 ;
        RECT 111.070 137.660 121.100 137.730 ;
        RECT 121.330 137.660 123.760 138.440 ;
        RECT 111.070 137.370 123.760 137.660 ;
        RECT 111.070 137.360 121.710 137.370 ;
        RECT 111.070 137.300 121.100 137.360 ;
        RECT 122.680 137.340 123.760 137.370 ;
        RECT 111.060 136.370 121.090 136.430 ;
        RECT 109.300 135.990 109.790 136.230 ;
        RECT 110.510 136.000 121.090 136.370 ;
        RECT 110.510 135.990 111.580 136.000 ;
        RECT 105.480 134.850 106.510 134.900 ;
        RECT 109.330 134.850 109.790 135.990 ;
        RECT 124.240 134.870 125.400 144.780 ;
        RECT 135.870 144.410 136.830 146.960 ;
        RECT 145.800 146.950 147.170 146.960 ;
        RECT 128.450 144.390 128.830 144.400 ;
        RECT 131.130 144.390 141.750 144.410 ;
        RECT 128.450 144.010 141.750 144.390 ;
        RECT 128.450 142.790 128.830 144.010 ;
        RECT 131.130 143.990 141.750 144.010 ;
        RECT 131.120 143.530 141.740 143.610 ;
        RECT 131.120 143.220 144.210 143.530 ;
        RECT 131.120 143.190 141.740 143.220 ;
        RECT 131.120 142.790 141.740 142.800 ;
        RECT 128.450 142.410 141.740 142.790 ;
        RECT 128.450 141.200 128.830 142.410 ;
        RECT 131.120 142.380 141.740 142.410 ;
        RECT 131.030 141.950 141.650 142.020 ;
        RECT 143.400 141.950 144.190 143.220 ;
        RECT 131.030 141.640 144.190 141.950 ;
        RECT 131.030 141.600 141.650 141.640 ;
        RECT 131.030 141.200 141.650 141.250 ;
        RECT 128.450 140.830 141.650 141.200 ;
        RECT 128.450 140.820 131.350 140.830 ;
        RECT 128.450 139.660 128.830 140.820 ;
        RECT 131.040 140.370 141.660 140.460 ;
        RECT 143.400 140.370 144.190 141.640 ;
        RECT 131.040 140.060 144.190 140.370 ;
        RECT 131.040 140.040 141.660 140.060 ;
        RECT 128.450 139.640 131.350 139.660 ;
        RECT 128.450 139.280 141.740 139.640 ;
        RECT 128.450 138.030 128.830 139.280 ;
        RECT 131.120 139.220 141.740 139.280 ;
        RECT 131.110 138.810 141.730 138.860 ;
        RECT 143.400 138.810 144.190 140.060 ;
        RECT 131.110 138.500 144.190 138.810 ;
        RECT 131.110 138.440 141.730 138.500 ;
        RECT 143.400 138.490 144.190 138.500 ;
        RECT 131.120 138.030 141.740 138.070 ;
        RECT 128.450 137.650 141.740 138.030 ;
        RECT 105.480 134.830 109.840 134.850 ;
        RECT 102.770 134.790 109.840 134.830 ;
        RECT 102.730 133.830 109.840 134.790 ;
        RECT 116.320 133.950 125.400 134.870 ;
        RECT 143.420 134.850 144.170 138.490 ;
        RECT 138.690 134.830 144.360 134.850 ;
        RECT 129.400 134.780 144.360 134.830 ;
        RECT 116.320 133.930 125.210 133.950 ;
        RECT 129.350 133.930 144.360 134.780 ;
        RECT 102.730 133.820 106.520 133.830 ;
        RECT 93.850 130.690 94.670 131.000 ;
        RECT 100.720 130.690 101.510 130.710 ;
        RECT 93.850 129.900 101.510 130.690 ;
        RECT 93.850 129.780 94.670 129.900 ;
        RECT 59.150 126.580 59.500 126.830 ;
        RECT 59.140 121.830 59.500 126.580 ;
        RECT 100.720 123.890 101.510 129.900 ;
        RECT 100.720 123.310 101.500 123.890 ;
        RECT 100.680 122.910 101.500 123.310 ;
        RECT 102.730 123.710 104.000 133.820 ;
        RECT 105.300 133.110 105.700 133.140 ;
        RECT 105.980 133.110 116.020 133.125 ;
        RECT 105.300 132.770 116.020 133.110 ;
        RECT 105.300 129.520 105.700 132.770 ;
        RECT 105.980 132.755 116.020 132.770 ;
        RECT 105.980 131.320 116.020 131.350 ;
        RECT 116.320 131.320 116.710 133.930 ;
        RECT 117.380 133.120 117.610 133.180 ;
        RECT 117.910 133.120 127.950 133.125 ;
        RECT 117.330 132.810 127.950 133.120 ;
        RECT 105.980 131.020 116.710 131.320 ;
        RECT 105.980 130.980 116.020 131.020 ;
        RECT 116.220 130.870 116.710 131.020 ;
        RECT 105.980 129.520 116.020 129.530 ;
        RECT 105.300 129.180 116.020 129.520 ;
        RECT 105.300 125.920 105.700 129.180 ;
        RECT 105.980 129.160 116.020 129.180 ;
        RECT 105.980 127.710 116.020 127.740 ;
        RECT 116.220 127.710 116.590 130.870 ;
        RECT 117.380 129.520 117.610 132.810 ;
        RECT 117.910 132.755 127.950 132.810 ;
        RECT 117.910 131.290 127.950 131.350 ;
        RECT 128.220 131.290 128.590 131.310 ;
        RECT 117.910 131.270 128.590 131.290 ;
        RECT 129.350 131.270 130.250 133.930 ;
        RECT 137.620 133.910 144.360 133.930 ;
        RECT 117.910 130.980 130.250 131.270 ;
        RECT 128.220 130.340 130.250 130.980 ;
        RECT 117.910 129.520 127.950 129.530 ;
        RECT 117.330 129.210 127.950 129.520 ;
        RECT 105.980 127.410 116.590 127.710 ;
        RECT 105.980 127.370 116.020 127.410 ;
        RECT 105.980 125.920 116.020 125.980 ;
        RECT 105.300 125.610 116.020 125.920 ;
        RECT 117.380 125.960 117.610 129.210 ;
        RECT 117.910 129.160 127.950 129.210 ;
        RECT 128.220 127.740 128.590 130.340 ;
        RECT 133.190 129.960 133.490 131.400 ;
        RECT 131.430 129.930 133.540 129.960 ;
        RECT 117.910 127.430 128.590 127.740 ;
        RECT 131.410 128.980 133.540 129.930 ;
        RECT 117.910 127.370 127.950 127.430 ;
        RECT 117.910 125.960 127.950 125.980 ;
        RECT 117.380 125.650 127.950 125.960 ;
        RECT 117.910 125.610 127.950 125.650 ;
        RECT 105.300 125.580 106.410 125.610 ;
        RECT 105.300 125.530 105.700 125.580 ;
        RECT 131.410 123.890 132.390 128.980 ;
        RECT 133.190 127.650 133.490 128.980 ;
        RECT 131.450 123.810 132.390 123.890 ;
        RECT 119.230 123.710 120.420 123.800 ;
        RECT 59.140 121.800 62.310 121.830 ;
        RECT 59.140 121.150 62.330 121.800 ;
        RECT 56.230 119.270 56.940 120.850 ;
        RECT 35.310 118.310 56.940 119.270 ;
        RECT 24.460 110.400 26.760 111.610 ;
        RECT 35.310 84.880 36.300 118.310 ;
        RECT 39.310 115.020 44.810 115.100 ;
        RECT 39.310 114.830 44.830 115.020 ;
        RECT 39.330 114.620 39.660 114.830 ;
        RECT 41.920 114.620 42.240 114.830 ;
        RECT 44.500 114.620 44.830 114.830 ;
        RECT 49.190 114.820 54.670 114.850 ;
        RECT 38.070 110.740 38.400 114.620 ;
        RECT 39.330 114.340 39.690 114.620 ;
        RECT 38.050 110.670 38.400 110.740 ;
        RECT 39.360 110.670 39.690 114.340 ;
        RECT 40.650 110.670 40.980 114.620 ;
        RECT 41.920 114.330 42.270 114.620 ;
        RECT 41.940 110.670 42.270 114.330 ;
        RECT 43.230 110.670 43.560 114.620 ;
        RECT 44.500 114.340 44.850 114.620 ;
        RECT 49.190 114.560 54.680 114.820 ;
        RECT 49.190 114.540 52.080 114.560 ;
        RECT 44.520 113.020 44.850 114.340 ;
        RECT 44.520 112.040 44.840 113.020 ;
        RECT 44.520 110.670 44.850 112.040 ;
        RECT 38.050 110.490 38.350 110.670 ;
        RECT 40.660 110.490 40.910 110.670 ;
        RECT 43.230 110.490 43.530 110.670 ;
        RECT 38.050 110.200 43.530 110.490 ;
        RECT 38.050 110.160 38.350 110.200 ;
        RECT 43.230 110.190 43.530 110.200 ;
        RECT 47.920 110.440 48.240 114.390 ;
        RECT 49.200 113.970 49.530 114.540 ;
        RECT 51.820 114.390 52.080 114.540 ;
        RECT 54.380 114.390 54.680 114.560 ;
        RECT 49.210 110.440 49.530 113.970 ;
        RECT 50.500 110.440 50.820 114.390 ;
        RECT 51.790 110.440 52.110 114.390 ;
        RECT 53.080 110.440 53.400 114.390 ;
        RECT 54.370 112.800 54.690 114.390 ;
        RECT 54.370 112.650 54.680 112.800 ;
        RECT 56.230 112.650 56.940 112.720 ;
        RECT 54.370 111.940 57.000 112.650 ;
        RECT 54.370 110.440 54.680 111.940 ;
        RECT 47.920 110.280 48.220 110.440 ;
        RECT 50.520 110.280 50.820 110.440 ;
        RECT 53.120 110.280 53.370 110.440 ;
        RECT 47.920 110.060 53.390 110.280 ;
        RECT 47.930 109.980 53.390 110.060 ;
        RECT 50.530 109.970 53.390 109.980 ;
        RECT 46.220 109.580 53.450 109.600 ;
        RECT 53.660 109.580 54.370 110.220 ;
        RECT 56.310 110.070 56.970 111.940 ;
        RECT 46.220 109.210 54.370 109.580 ;
        RECT 39.310 108.860 44.870 109.170 ;
        RECT 39.310 108.690 39.670 108.860 ;
        RECT 41.920 108.690 42.260 108.860 ;
        RECT 38.070 104.740 38.400 108.690 ;
        RECT 39.310 108.490 39.690 108.690 ;
        RECT 39.360 104.740 39.690 108.490 ;
        RECT 40.650 104.760 40.980 108.690 ;
        RECT 41.920 108.470 42.270 108.690 ;
        RECT 38.070 104.560 38.380 104.740 ;
        RECT 40.640 104.560 40.980 104.760 ;
        RECT 41.940 104.740 42.270 108.470 ;
        RECT 43.230 104.790 43.560 108.690 ;
        RECT 44.500 108.450 44.860 108.860 ;
        RECT 43.220 104.740 43.560 104.790 ;
        RECT 44.520 107.100 44.850 108.450 ;
        RECT 44.520 106.130 44.830 107.100 ;
        RECT 44.520 104.740 44.850 106.130 ;
        RECT 43.220 104.560 43.530 104.740 ;
        RECT 38.070 104.240 43.530 104.560 ;
        RECT 38.080 104.220 43.530 104.240 ;
        RECT 46.220 100.160 46.720 109.210 ;
        RECT 47.110 109.190 54.370 109.210 ;
        RECT 53.660 109.030 54.370 109.190 ;
        RECT 56.200 110.030 59.140 110.070 ;
        RECT 56.200 109.080 59.480 110.030 ;
        RECT 56.200 109.050 59.140 109.080 ;
        RECT 49.220 108.590 54.680 108.860 ;
        RECT 49.240 108.370 49.520 108.590 ;
        RECT 51.810 108.370 52.090 108.590 ;
        RECT 54.410 108.370 54.670 108.590 ;
        RECT 47.920 107.100 48.240 108.370 ;
        RECT 47.940 106.130 48.240 107.100 ;
        RECT 47.920 104.420 48.240 106.130 ;
        RECT 49.210 104.420 49.530 108.370 ;
        RECT 50.500 104.420 50.820 108.370 ;
        RECT 51.790 104.420 52.110 108.370 ;
        RECT 53.080 104.420 53.400 108.370 ;
        RECT 54.370 106.810 54.680 108.370 ;
        RECT 56.310 106.810 56.970 109.050 ;
        RECT 54.370 106.100 56.990 106.810 ;
        RECT 54.370 105.450 54.680 106.100 ;
        RECT 54.370 104.420 54.690 105.450 ;
        RECT 47.950 104.210 48.230 104.420 ;
        RECT 50.540 104.210 50.820 104.420 ;
        RECT 53.090 104.210 53.370 104.420 ;
        RECT 47.940 103.930 53.390 104.210 ;
        RECT 43.090 100.150 46.690 100.160 ;
        RECT 43.080 99.570 46.690 100.150 ;
        RECT 40.650 96.780 41.220 97.330 ;
        RECT 43.080 96.780 43.920 99.570 ;
        RECT 46.220 99.540 46.690 99.570 ;
        RECT 45.280 96.780 45.870 97.370 ;
        RECT 40.650 95.650 45.870 96.780 ;
        RECT 40.650 95.100 41.220 95.650 ;
        RECT 45.280 95.130 45.870 95.650 ;
        RECT 48.780 93.880 49.300 94.710 ;
        RECT 54.120 93.940 57.600 94.150 ;
        RECT 48.780 93.860 50.450 93.880 ;
        RECT 48.780 93.250 50.470 93.860 ;
        RECT 54.120 93.720 54.450 93.940 ;
        RECT 55.690 93.720 56.020 93.940 ;
        RECT 57.270 93.720 57.600 93.940 ;
        RECT 48.780 92.460 49.300 93.250 ;
        RECT 49.960 92.160 50.470 93.250 ;
        RECT 53.320 92.300 53.660 93.720 ;
        RECT 53.300 92.160 53.660 92.300 ;
        RECT 48.740 90.560 49.380 91.420 ;
        RECT 49.960 91.400 53.660 92.160 ;
        RECT 49.960 90.560 50.470 91.400 ;
        RECT 48.740 89.930 50.480 90.560 ;
        RECT 48.740 89.180 49.380 89.930 ;
        RECT 51.150 84.880 51.850 91.400 ;
        RECT 53.300 91.340 53.660 91.400 ;
        RECT 53.320 89.800 53.660 91.340 ;
        RECT 53.320 89.770 53.670 89.800 ;
        RECT 54.110 89.770 54.450 93.720 ;
        RECT 54.900 89.770 55.240 93.720 ;
        RECT 55.690 89.770 56.030 93.720 ;
        RECT 56.480 89.770 56.820 93.720 ;
        RECT 57.270 89.770 57.610 93.720 ;
        RECT 53.360 89.550 53.670 89.770 ;
        RECT 54.920 89.550 55.230 89.770 ;
        RECT 56.500 89.740 56.810 89.770 ;
        RECT 56.500 89.550 56.740 89.740 ;
        RECT 61.790 89.550 62.330 121.150 ;
        RECT 100.680 117.880 101.480 122.910 ;
        RECT 102.730 122.690 120.460 123.710 ;
        RECT 100.680 117.850 110.420 117.880 ;
        RECT 116.610 117.850 117.590 117.900 ;
        RECT 100.680 117.830 117.590 117.850 ;
        RECT 131.450 117.830 132.410 123.810 ;
        RECT 137.620 119.320 138.810 133.910 ;
        RECT 140.500 131.770 140.920 133.910 ;
        RECT 145.840 132.630 147.150 146.950 ;
        RECT 159.080 135.150 159.450 160.090 ;
        RECT 159.840 159.910 160.270 161.440 ;
        RECT 159.050 133.720 159.500 135.150 ;
        RECT 159.900 134.930 160.270 159.910 ;
        RECT 160.680 135.240 161.050 160.090 ;
        RECT 161.400 159.930 161.830 161.440 ;
        RECT 160.630 133.720 161.080 135.240 ;
        RECT 161.450 134.900 161.820 159.930 ;
        RECT 162.240 135.220 162.610 160.120 ;
        RECT 163.020 159.950 163.450 161.440 ;
        RECT 162.200 133.720 162.650 135.220 ;
        RECT 163.050 134.930 163.420 159.950 ;
        RECT 163.810 135.200 164.180 160.140 ;
        RECT 164.590 159.940 165.020 161.440 ;
        RECT 163.740 133.720 164.190 135.200 ;
        RECT 164.630 134.900 165.000 159.940 ;
        RECT 165.420 135.150 165.790 160.090 ;
        RECT 166.150 159.830 166.650 161.440 ;
        RECT 165.320 134.900 165.790 135.150 ;
        RECT 165.320 133.720 165.770 134.900 ;
        RECT 166.210 134.870 166.580 159.830 ;
        RECT 167.000 135.220 167.370 160.040 ;
        RECT 166.950 133.720 167.400 135.220 ;
        RECT 182.950 135.140 188.720 135.150 ;
        RECT 159.050 133.260 167.410 133.720 ;
        RECT 159.050 133.240 159.500 133.260 ;
        RECT 165.320 133.240 165.770 133.260 ;
        RECT 142.850 132.560 148.430 132.630 ;
        RECT 150.650 132.560 151.060 132.610 ;
        RECT 142.850 132.260 151.060 132.560 ;
        RECT 142.850 132.220 148.430 132.260 ;
        RECT 142.860 131.770 148.440 131.840 ;
        RECT 140.500 131.440 148.440 131.770 ;
        RECT 140.500 130.200 140.920 131.440 ;
        RECT 142.860 131.430 148.440 131.440 ;
        RECT 142.860 131.000 148.440 131.080 ;
        RECT 150.650 131.000 151.060 132.260 ;
        RECT 142.860 130.700 151.060 131.000 ;
        RECT 142.860 130.670 148.440 130.700 ;
        RECT 142.890 130.200 148.470 130.260 ;
        RECT 140.500 129.870 148.470 130.200 ;
        RECT 142.890 129.850 148.470 129.870 ;
        RECT 142.870 129.380 148.450 129.500 ;
        RECT 150.650 129.380 151.060 130.700 ;
        RECT 142.870 129.090 151.090 129.380 ;
        RECT 148.310 129.080 151.090 129.090 ;
        RECT 177.430 128.440 180.810 131.620 ;
        RECT 148.050 126.080 153.630 126.130 ;
        RECT 146.210 125.770 153.630 126.080 ;
        RECT 146.260 124.530 146.670 125.770 ;
        RECT 148.050 125.720 153.630 125.770 ;
        RECT 148.060 125.270 153.640 125.340 ;
        RECT 161.890 125.320 162.290 125.390 ;
        RECT 163.490 125.320 163.890 125.370 ;
        RECT 161.840 125.310 165.370 125.320 ;
        RECT 154.980 125.270 155.870 125.280 ;
        RECT 148.060 125.020 155.900 125.270 ;
        RECT 161.840 125.090 165.390 125.310 ;
        RECT 148.060 124.930 153.640 125.020 ;
        RECT 148.060 124.530 153.640 124.580 ;
        RECT 146.240 124.220 153.640 124.530 ;
        RECT 146.260 122.940 146.670 124.220 ;
        RECT 148.060 124.170 153.640 124.220 ;
        RECT 148.090 123.650 153.670 123.760 ;
        RECT 154.980 123.650 155.870 125.020 ;
        RECT 148.090 123.400 155.910 123.650 ;
        RECT 148.090 123.350 153.670 123.400 ;
        RECT 148.070 122.940 153.650 123.000 ;
        RECT 146.260 122.630 153.650 122.940 ;
        RECT 148.070 122.590 153.650 122.630 ;
        RECT 150.150 122.550 151.830 122.590 ;
        RECT 152.530 122.260 152.830 122.270 ;
        RECT 152.530 122.190 153.680 122.260 ;
        RECT 154.980 122.190 155.870 123.400 ;
        RECT 152.530 122.150 155.880 122.190 ;
        RECT 156.460 122.150 156.900 122.180 ;
        RECT 152.530 121.740 156.900 122.150 ;
        RECT 152.530 121.610 153.680 121.740 ;
        RECT 154.980 121.700 155.870 121.740 ;
        RECT 148.050 121.600 153.680 121.610 ;
        RECT 85.710 105.650 96.190 117.350 ;
        RECT 100.680 117.070 132.410 117.830 ;
        RECT 135.790 118.370 138.810 119.320 ;
        RECT 146.360 121.430 153.680 121.600 ;
        RECT 146.360 121.250 153.630 121.430 ;
        RECT 146.360 120.050 147.010 121.250 ;
        RECT 148.050 121.200 153.630 121.250 ;
        RECT 156.460 121.360 156.900 121.740 ;
        RECT 148.060 120.710 153.640 120.820 ;
        RECT 148.060 120.440 156.270 120.710 ;
        RECT 156.460 120.680 156.920 121.360 ;
        RECT 148.060 120.410 153.640 120.440 ;
        RECT 148.060 120.050 153.640 120.060 ;
        RECT 146.360 119.700 153.640 120.050 ;
        RECT 146.360 118.440 147.010 119.700 ;
        RECT 148.060 119.650 153.640 119.700 ;
        RECT 148.090 119.200 153.670 119.240 ;
        RECT 155.070 119.200 155.630 120.440 ;
        RECT 148.090 118.890 156.730 119.200 ;
        RECT 148.090 118.830 153.670 118.890 ;
        RECT 148.070 118.440 153.650 118.480 ;
        RECT 135.790 117.550 144.000 118.370 ;
        RECT 146.340 118.090 153.650 118.440 ;
        RECT 148.070 118.070 153.650 118.090 ;
        RECT 135.790 117.530 138.810 117.550 ;
        RECT 107.070 117.040 132.410 117.070 ;
        RECT 116.610 116.820 132.410 117.040 ;
        RECT 116.980 116.800 132.410 116.820 ;
        RECT 125.360 113.900 128.150 116.310 ;
        RECT 110.070 104.860 113.850 108.640 ;
        RECT 142.850 107.120 143.970 117.550 ;
        RECT 154.720 116.760 156.020 118.890 ;
        RECT 161.090 107.440 161.420 124.750 ;
        RECT 161.890 124.550 162.290 125.090 ;
        RECT 161.910 107.930 162.240 124.550 ;
        RECT 162.690 108.240 163.020 124.690 ;
        RECT 163.490 124.530 163.890 125.090 ;
        RECT 162.680 107.880 163.020 108.240 ;
        RECT 162.680 107.440 163.010 107.880 ;
        RECT 163.500 107.810 163.830 124.530 ;
        RECT 164.270 108.280 164.600 124.560 ;
        RECT 164.990 124.470 165.390 125.090 ;
        RECT 164.270 107.750 164.610 108.280 ;
        RECT 165.030 107.750 165.360 124.470 ;
        RECT 182.950 123.760 188.730 135.140 ;
        RECT 182.950 123.750 188.720 123.760 ;
        RECT 164.280 107.440 164.610 107.750 ;
        RECT 161.090 107.150 164.610 107.440 ;
        RECT 142.850 106.750 160.270 107.120 ;
        RECT 161.090 107.080 164.600 107.150 ;
        RECT 161.470 106.750 162.000 106.780 ;
        RECT 142.850 106.240 162.000 106.750 ;
        RECT 160.180 106.220 162.000 106.240 ;
        RECT 98.430 96.910 102.730 102.340 ;
        RECT 111.150 92.930 112.500 102.820 ;
        RECT 111.150 91.740 134.860 92.930 ;
        RECT 53.340 89.340 56.740 89.550 ;
        RECT 53.360 89.310 53.670 89.340 ;
        RECT 54.920 89.310 55.230 89.340 ;
        RECT 56.890 89.200 62.330 89.550 ;
        RECT 61.790 89.180 62.330 89.200 ;
        RECT 104.380 87.070 106.380 87.080 ;
        RECT 35.310 83.890 51.860 84.880 ;
        RECT 35.310 83.860 36.300 83.890 ;
        RECT 76.960 83.860 81.180 86.750 ;
        RECT 104.380 86.690 111.660 87.070 ;
        RECT 104.380 86.680 106.380 86.690 ;
        RECT 104.380 82.460 104.810 86.680 ;
        RECT 112.740 84.790 113.460 88.740 ;
        RECT 117.380 88.360 117.700 88.430 ;
        RECT 117.240 88.070 123.060 88.360 ;
        RECT 117.380 85.750 117.700 88.070 ;
        RECT 118.100 88.010 123.060 88.070 ;
        RECT 118.090 87.050 123.050 87.080 ;
        RECT 123.770 87.050 124.600 89.960 ;
        RECT 125.120 88.310 130.080 88.360 ;
        RECT 133.400 88.330 134.860 91.740 ;
        RECT 158.880 89.290 160.460 90.740 ;
        RECT 158.880 89.160 163.370 89.290 ;
        RECT 139.230 88.590 139.530 88.600 ;
        RECT 142.820 88.590 152.550 88.600 ;
        RECT 125.120 88.290 130.730 88.310 ;
        RECT 125.120 88.020 130.800 88.290 ;
        RECT 125.120 88.010 130.080 88.020 ;
        RECT 125.110 87.050 130.070 87.080 ;
        RECT 118.090 86.730 130.070 87.050 ;
        RECT 118.100 85.750 123.070 85.790 ;
        RECT 117.240 85.460 123.070 85.750 ;
        RECT 111.470 84.770 113.460 84.790 ;
        RECT 105.660 84.390 113.460 84.770 ;
        RECT 111.470 84.370 113.460 84.390 ;
        RECT 117.380 83.140 117.700 85.460 ;
        RECT 118.100 85.450 123.070 85.460 ;
        RECT 118.100 84.470 123.070 84.500 ;
        RECT 123.450 84.470 123.790 86.730 ;
        RECT 118.100 84.220 123.790 84.470 ;
        RECT 124.560 84.430 124.900 86.730 ;
        RECT 125.120 85.750 130.090 85.790 ;
        RECT 130.510 85.750 130.800 88.020 ;
        RECT 133.350 86.880 134.860 88.330 ;
        RECT 139.180 88.220 152.550 88.590 ;
        RECT 139.230 86.990 139.530 88.220 ;
        RECT 142.820 88.210 152.550 88.220 ;
        RECT 158.890 88.130 163.370 89.160 ;
        RECT 142.820 87.720 152.550 87.810 ;
        RECT 154.950 87.720 155.310 87.740 ;
        RECT 142.820 87.450 155.310 87.720 ;
        RECT 142.820 87.420 152.550 87.450 ;
        RECT 142.840 86.990 152.570 87.010 ;
        RECT 133.350 86.820 134.670 86.880 ;
        RECT 139.230 86.620 152.570 86.990 ;
        RECT 125.120 85.460 130.850 85.750 ;
        RECT 125.120 85.450 130.090 85.460 ;
        RECT 125.120 84.430 130.090 84.500 ;
        RECT 118.100 84.140 123.070 84.220 ;
        RECT 124.560 84.180 130.090 84.430 ;
        RECT 125.120 84.140 130.090 84.180 ;
        RECT 118.100 83.140 123.050 83.170 ;
        RECT 117.380 82.850 123.050 83.140 ;
        RECT 118.100 82.830 123.050 82.850 ;
        RECT 125.120 83.160 130.070 83.170 ;
        RECT 130.510 83.160 130.800 85.460 ;
        RECT 139.230 85.410 139.530 86.620 ;
        RECT 142.810 86.120 152.540 86.200 ;
        RECT 154.950 86.120 155.310 87.450 ;
        RECT 142.810 85.850 155.310 86.120 ;
        RECT 142.810 85.810 152.540 85.850 ;
        RECT 142.790 85.410 152.520 85.430 ;
        RECT 139.220 85.040 152.520 85.410 ;
        RECT 139.230 83.860 139.530 85.040 ;
        RECT 142.760 84.520 152.490 84.590 ;
        RECT 154.950 84.520 155.310 85.850 ;
        RECT 142.760 84.250 155.310 84.520 ;
        RECT 142.760 84.200 152.490 84.250 ;
        RECT 139.230 83.840 143.080 83.860 ;
        RECT 139.230 83.490 152.470 83.840 ;
        RECT 142.740 83.450 152.470 83.490 ;
        RECT 125.120 82.870 130.800 83.160 ;
        RECT 125.120 82.830 130.070 82.870 ;
        RECT 130.510 82.850 130.800 82.870 ;
        RECT 142.770 82.940 152.500 83.040 ;
        RECT 154.950 82.940 155.310 84.250 ;
        RECT 142.770 82.690 155.310 82.940 ;
        RECT 142.770 82.670 155.260 82.690 ;
        RECT 142.770 82.650 152.500 82.670 ;
        RECT 105.860 82.460 111.830 82.470 ;
        RECT 104.380 82.090 111.830 82.460 ;
        RECT 104.380 82.080 106.400 82.090 ;
        RECT 104.420 82.060 106.400 82.080 ;
        RECT 139.170 81.680 139.520 81.690 ;
        RECT 142.820 81.680 152.550 81.730 ;
        RECT 117.570 79.210 117.840 79.220 ;
        RECT 117.510 79.190 118.970 79.210 ;
        RECT 117.510 78.860 122.900 79.190 ;
        RECT 90.530 78.180 101.160 78.540 ;
        RECT 102.550 78.180 113.180 78.540 ;
        RECT 90.560 75.920 90.860 78.180 ;
        RECT 91.090 78.110 101.160 78.180 ;
        RECT 91.080 76.850 101.170 77.210 ;
        RECT 91.090 75.920 101.170 75.940 ;
        RECT 90.560 75.560 101.170 75.920 ;
        RECT 102.580 75.920 102.880 78.180 ;
        RECT 103.110 78.110 113.180 78.180 ;
        RECT 117.570 77.610 117.840 78.860 ;
        RECT 118.220 78.850 122.900 78.860 ;
        RECT 118.220 78.360 122.900 78.390 ;
        RECT 123.840 78.360 124.360 81.500 ;
        RECT 139.150 81.340 152.550 81.680 ;
        RECT 139.150 81.310 143.130 81.340 ;
        RECT 139.170 80.130 139.520 81.310 ;
        RECT 142.820 80.850 152.550 80.940 ;
        RECT 142.820 80.820 155.260 80.850 ;
        RECT 142.820 80.550 155.290 80.820 ;
        RECT 152.260 80.530 155.290 80.550 ;
        RECT 142.840 80.130 152.570 80.140 ;
        RECT 139.170 79.760 152.570 80.130 ;
        RECT 125.240 79.170 129.920 79.190 ;
        RECT 124.620 78.850 129.920 79.170 ;
        RECT 118.220 78.050 124.360 78.360 ;
        RECT 122.740 78.010 124.360 78.050 ;
        RECT 117.480 77.600 118.940 77.610 ;
        RECT 117.480 77.260 122.930 77.600 ;
        RECT 103.100 76.860 114.160 77.210 ;
        RECT 103.100 76.850 113.190 76.860 ;
        RECT 103.110 75.920 113.190 75.940 ;
        RECT 102.580 75.560 113.190 75.920 ;
        RECT 91.090 75.520 101.170 75.560 ;
        RECT 103.110 75.520 113.190 75.560 ;
        RECT 113.400 72.250 114.160 76.860 ;
        RECT 117.570 76.050 117.840 77.260 ;
        RECT 123.840 76.810 124.360 78.010 ;
        RECT 124.650 77.570 124.900 78.850 ;
        RECT 139.170 78.520 139.520 79.760 ;
        RECT 142.840 79.750 152.570 79.760 ;
        RECT 142.810 79.260 152.540 79.330 ;
        RECT 154.900 79.260 155.290 80.530 ;
        RECT 142.810 78.940 155.360 79.260 ;
        RECT 142.790 78.520 152.520 78.560 ;
        RECT 125.240 78.350 129.920 78.390 ;
        RECT 130.360 78.350 130.690 78.370 ;
        RECT 125.240 78.060 130.690 78.350 ;
        RECT 139.150 78.170 152.520 78.520 ;
        RECT 139.150 78.150 143.130 78.170 ;
        RECT 125.240 78.050 129.920 78.060 ;
        RECT 125.270 77.570 129.950 77.600 ;
        RECT 124.630 77.260 129.950 77.570 ;
        RECT 124.630 77.250 125.410 77.260 ;
        RECT 118.200 76.470 124.360 76.810 ;
        RECT 122.770 76.460 124.360 76.470 ;
        RECT 117.570 76.030 119.030 76.050 ;
        RECT 117.570 75.700 122.890 76.030 ;
        RECT 118.210 75.690 122.890 75.700 ;
        RECT 123.840 73.580 124.360 76.460 ;
        RECT 124.650 76.010 124.900 77.250 ;
        RECT 130.360 77.110 130.690 78.060 ;
        RECT 125.220 76.770 129.900 76.810 ;
        RECT 130.360 76.770 132.960 77.110 ;
        RECT 125.220 76.480 132.960 76.770 ;
        RECT 139.170 76.940 139.520 78.150 ;
        RECT 142.760 77.640 152.490 77.720 ;
        RECT 154.900 77.640 155.290 78.940 ;
        RECT 142.760 77.330 155.330 77.640 ;
        RECT 152.330 77.320 155.330 77.330 ;
        RECT 142.740 76.940 152.470 76.970 ;
        RECT 139.170 76.580 152.470 76.940 ;
        RECT 139.170 76.570 143.150 76.580 ;
        RECT 125.220 76.470 129.900 76.480 ;
        RECT 130.440 76.450 132.960 76.480 ;
        RECT 125.230 76.010 129.910 76.030 ;
        RECT 124.650 75.690 129.910 76.010 ;
        RECT 126.170 73.580 128.450 73.660 ;
        RECT 123.840 73.130 128.450 73.580 ;
        RECT 126.170 73.110 128.450 73.130 ;
        RECT 132.250 73.050 132.960 76.450 ;
        RECT 142.770 76.130 152.500 76.170 ;
        RECT 154.900 76.130 155.290 77.320 ;
        RECT 142.770 75.810 155.310 76.130 ;
        RECT 142.770 75.780 152.500 75.810 ;
        RECT 154.900 75.780 155.290 75.810 ;
        RECT 158.890 74.350 160.500 88.130 ;
        RECT 162.790 88.020 163.330 88.130 ;
        RECT 163.150 87.140 163.580 87.160 ;
        RECT 164.710 87.140 165.140 87.180 ;
        RECT 166.330 87.140 166.760 87.200 ;
        RECT 167.900 87.140 168.330 87.190 ;
        RECT 169.460 87.140 169.960 90.060 ;
        RECT 163.150 86.700 169.960 87.140 ;
        RECT 149.110 73.290 160.500 74.350 ;
        RECT 149.110 73.090 150.480 73.290 ;
        RECT 139.480 73.050 150.480 73.090 ;
        RECT 132.250 72.370 150.480 73.050 ;
        RECT 107.980 72.230 115.900 72.250 ;
        RECT 107.980 71.720 115.910 72.230 ;
        RECT 101.750 69.410 103.060 69.450 ;
        RECT 107.980 69.410 108.690 71.720 ;
        RECT 115.200 69.410 115.910 71.720 ;
        RECT 139.180 72.220 150.480 72.370 ;
        RECT 127.540 71.310 128.700 71.350 ;
        RECT 127.540 70.040 128.710 71.310 ;
        RECT 101.750 69.050 112.440 69.410 ;
        RECT 101.760 66.850 102.120 69.050 ;
        RECT 102.360 69.020 112.440 69.050 ;
        RECT 113.820 69.380 114.200 69.410 ;
        RECT 114.380 69.380 124.460 69.410 ;
        RECT 113.820 69.020 124.460 69.380 ;
        RECT 113.820 69.000 114.990 69.020 ;
        RECT 102.360 68.110 112.390 68.150 ;
        RECT 102.360 67.760 113.030 68.110 ;
        RECT 102.360 67.720 112.390 67.760 ;
        RECT 102.350 66.850 112.380 66.860 ;
        RECT 101.730 66.450 112.380 66.850 ;
        RECT 100.770 64.590 101.510 66.110 ;
        RECT 101.760 64.290 102.120 66.450 ;
        RECT 102.350 66.430 112.380 66.450 ;
        RECT 102.360 65.530 112.390 65.590 ;
        RECT 112.610 65.530 113.030 67.760 ;
        RECT 102.360 65.180 113.030 65.530 ;
        RECT 102.360 65.160 112.390 65.180 ;
        RECT 101.730 63.890 112.390 64.290 ;
        RECT 101.760 61.690 102.120 63.890 ;
        RECT 102.360 63.860 112.390 63.890 ;
        RECT 112.610 63.440 113.030 65.180 ;
        RECT 113.820 66.840 114.200 69.000 ;
        RECT 114.380 68.060 124.410 68.150 ;
        RECT 114.380 67.760 125.020 68.060 ;
        RECT 114.380 67.720 124.410 67.760 ;
        RECT 114.370 66.840 124.400 66.860 ;
        RECT 113.820 66.460 124.400 66.840 ;
        RECT 113.820 64.250 114.200 66.460 ;
        RECT 114.370 66.430 124.400 66.460 ;
        RECT 114.380 65.470 124.410 65.590 ;
        RECT 124.640 65.470 125.020 67.760 ;
        RECT 114.380 65.170 125.020 65.470 ;
        RECT 114.380 65.160 124.410 65.170 ;
        RECT 114.380 64.250 124.410 64.290 ;
        RECT 113.820 63.870 124.410 64.250 ;
        RECT 102.360 62.960 112.390 62.990 ;
        RECT 112.610 62.960 113.070 63.440 ;
        RECT 102.360 62.610 113.070 62.960 ;
        RECT 102.360 62.560 112.390 62.610 ;
        RECT 101.760 61.290 112.380 61.690 ;
        RECT 102.350 61.260 112.380 61.290 ;
        RECT 112.610 61.490 113.070 62.610 ;
        RECT 113.820 61.630 114.200 63.870 ;
        RECT 114.380 63.860 124.410 63.870 ;
        RECT 124.640 63.700 125.020 65.170 ;
        RECT 125.750 64.310 126.700 66.480 ;
        RECT 125.990 63.700 127.070 63.750 ;
        RECT 114.380 62.920 124.410 62.990 ;
        RECT 124.640 62.920 127.070 63.700 ;
        RECT 114.380 62.630 127.070 62.920 ;
        RECT 114.380 62.620 125.020 62.630 ;
        RECT 114.380 62.560 124.410 62.620 ;
        RECT 125.990 62.600 127.070 62.630 ;
        RECT 114.370 61.630 124.400 61.690 ;
        RECT 112.610 61.250 113.100 61.490 ;
        RECT 113.820 61.260 124.400 61.630 ;
        RECT 113.820 61.250 114.890 61.260 ;
        RECT 108.790 60.110 109.820 60.160 ;
        RECT 112.640 60.110 113.100 61.250 ;
        RECT 127.550 60.130 128.710 70.040 ;
        RECT 139.180 69.670 140.140 72.220 ;
        RECT 149.110 72.210 150.480 72.220 ;
        RECT 131.760 69.650 132.140 69.660 ;
        RECT 134.440 69.650 145.060 69.670 ;
        RECT 131.760 69.270 145.060 69.650 ;
        RECT 131.760 68.050 132.140 69.270 ;
        RECT 134.440 69.250 145.060 69.270 ;
        RECT 134.430 68.790 145.050 68.870 ;
        RECT 134.430 68.480 147.520 68.790 ;
        RECT 134.430 68.450 145.050 68.480 ;
        RECT 134.430 68.050 145.050 68.060 ;
        RECT 131.760 67.670 145.050 68.050 ;
        RECT 131.760 66.460 132.140 67.670 ;
        RECT 134.430 67.640 145.050 67.670 ;
        RECT 134.340 67.210 144.960 67.280 ;
        RECT 146.710 67.210 147.500 68.480 ;
        RECT 134.340 66.900 147.500 67.210 ;
        RECT 134.340 66.860 144.960 66.900 ;
        RECT 134.340 66.460 144.960 66.510 ;
        RECT 131.760 66.090 144.960 66.460 ;
        RECT 131.760 66.080 134.660 66.090 ;
        RECT 131.760 64.920 132.140 66.080 ;
        RECT 134.350 65.630 144.970 65.720 ;
        RECT 146.710 65.630 147.500 66.900 ;
        RECT 134.350 65.320 147.500 65.630 ;
        RECT 134.350 65.300 144.970 65.320 ;
        RECT 131.760 64.900 134.660 64.920 ;
        RECT 131.760 64.540 145.050 64.900 ;
        RECT 131.760 63.290 132.140 64.540 ;
        RECT 134.430 64.480 145.050 64.540 ;
        RECT 134.420 64.070 145.040 64.120 ;
        RECT 146.710 64.070 147.500 65.320 ;
        RECT 134.420 63.760 147.500 64.070 ;
        RECT 134.420 63.700 145.040 63.760 ;
        RECT 146.710 63.750 147.500 63.760 ;
        RECT 134.430 63.290 145.050 63.330 ;
        RECT 131.760 62.910 145.050 63.290 ;
        RECT 108.790 60.090 113.150 60.110 ;
        RECT 106.080 60.050 113.150 60.090 ;
        RECT 106.040 59.090 113.150 60.050 ;
        RECT 119.630 59.210 128.710 60.130 ;
        RECT 146.730 60.110 147.480 63.750 ;
        RECT 142.000 60.090 147.670 60.110 ;
        RECT 132.710 60.040 147.670 60.090 ;
        RECT 119.630 59.190 128.520 59.210 ;
        RECT 132.660 59.190 147.670 60.040 ;
        RECT 106.040 59.080 109.830 59.090 ;
        RECT 97.160 55.950 97.980 56.260 ;
        RECT 104.030 55.950 104.820 55.970 ;
        RECT 97.160 55.160 104.820 55.950 ;
        RECT 97.160 55.040 97.980 55.160 ;
        RECT 104.030 49.150 104.820 55.160 ;
        RECT 104.030 48.570 104.810 49.150 ;
        RECT 103.990 48.170 104.810 48.570 ;
        RECT 106.040 48.970 107.310 59.080 ;
        RECT 108.610 58.370 109.010 58.400 ;
        RECT 109.290 58.370 119.330 58.385 ;
        RECT 108.610 58.030 119.330 58.370 ;
        RECT 108.610 54.780 109.010 58.030 ;
        RECT 109.290 58.015 119.330 58.030 ;
        RECT 109.290 56.580 119.330 56.610 ;
        RECT 119.630 56.580 120.020 59.190 ;
        RECT 120.690 58.380 120.920 58.440 ;
        RECT 121.220 58.380 131.260 58.385 ;
        RECT 120.640 58.070 131.260 58.380 ;
        RECT 109.290 56.280 120.020 56.580 ;
        RECT 109.290 56.240 119.330 56.280 ;
        RECT 119.530 56.130 120.020 56.280 ;
        RECT 109.290 54.780 119.330 54.790 ;
        RECT 108.610 54.440 119.330 54.780 ;
        RECT 108.610 51.180 109.010 54.440 ;
        RECT 109.290 54.420 119.330 54.440 ;
        RECT 109.290 52.970 119.330 53.000 ;
        RECT 119.530 52.970 119.900 56.130 ;
        RECT 120.690 54.780 120.920 58.070 ;
        RECT 121.220 58.015 131.260 58.070 ;
        RECT 121.220 56.550 131.260 56.610 ;
        RECT 131.530 56.550 131.900 56.570 ;
        RECT 121.220 56.530 131.900 56.550 ;
        RECT 132.660 56.530 133.560 59.190 ;
        RECT 140.930 59.170 147.670 59.190 ;
        RECT 121.220 56.240 133.560 56.530 ;
        RECT 131.530 55.600 133.560 56.240 ;
        RECT 121.220 54.780 131.260 54.790 ;
        RECT 120.640 54.470 131.260 54.780 ;
        RECT 109.290 52.670 119.900 52.970 ;
        RECT 109.290 52.630 119.330 52.670 ;
        RECT 109.290 51.180 119.330 51.240 ;
        RECT 108.610 50.870 119.330 51.180 ;
        RECT 120.690 51.220 120.920 54.470 ;
        RECT 121.220 54.420 131.260 54.470 ;
        RECT 131.530 53.000 131.900 55.600 ;
        RECT 136.500 55.220 136.800 56.660 ;
        RECT 134.740 55.190 136.850 55.220 ;
        RECT 121.220 52.690 131.900 53.000 ;
        RECT 134.720 54.240 136.850 55.190 ;
        RECT 121.220 52.630 131.260 52.690 ;
        RECT 121.220 51.220 131.260 51.240 ;
        RECT 120.690 50.910 131.260 51.220 ;
        RECT 121.220 50.870 131.260 50.910 ;
        RECT 108.610 50.840 109.720 50.870 ;
        RECT 108.610 50.790 109.010 50.840 ;
        RECT 134.720 49.150 135.700 54.240 ;
        RECT 136.500 52.910 136.800 54.240 ;
        RECT 134.760 49.070 135.700 49.150 ;
        RECT 122.540 48.970 123.730 49.060 ;
        RECT 103.990 43.140 104.790 48.170 ;
        RECT 106.040 47.950 123.770 48.970 ;
        RECT 103.990 43.110 113.730 43.140 ;
        RECT 119.920 43.110 120.900 43.160 ;
        RECT 103.990 43.090 120.900 43.110 ;
        RECT 134.760 43.090 135.720 49.070 ;
        RECT 140.930 44.580 142.120 59.170 ;
        RECT 143.810 57.030 144.230 59.170 ;
        RECT 149.150 57.890 150.460 72.210 ;
        RECT 162.390 60.410 162.760 85.350 ;
        RECT 163.150 85.170 163.580 86.700 ;
        RECT 162.360 58.980 162.810 60.410 ;
        RECT 163.210 60.190 163.580 85.170 ;
        RECT 163.990 60.500 164.360 85.350 ;
        RECT 164.710 85.190 165.140 86.700 ;
        RECT 163.940 58.980 164.390 60.500 ;
        RECT 164.760 60.160 165.130 85.190 ;
        RECT 165.550 60.480 165.920 85.380 ;
        RECT 166.330 85.210 166.760 86.700 ;
        RECT 165.510 58.980 165.960 60.480 ;
        RECT 166.360 60.190 166.730 85.210 ;
        RECT 167.120 60.460 167.490 85.400 ;
        RECT 167.900 85.200 168.330 86.700 ;
        RECT 167.050 58.980 167.500 60.460 ;
        RECT 167.940 60.160 168.310 85.200 ;
        RECT 168.730 60.410 169.100 85.350 ;
        RECT 169.460 85.090 169.960 86.700 ;
        RECT 168.630 60.160 169.100 60.410 ;
        RECT 168.630 58.980 169.080 60.160 ;
        RECT 169.520 60.130 169.890 85.090 ;
        RECT 170.310 60.480 170.680 85.300 ;
        RECT 170.260 58.980 170.710 60.480 ;
        RECT 162.360 58.520 170.720 58.980 ;
        RECT 162.360 58.500 162.810 58.520 ;
        RECT 168.630 58.500 169.080 58.520 ;
        RECT 146.160 57.820 151.740 57.890 ;
        RECT 153.960 57.820 154.370 57.870 ;
        RECT 146.160 57.520 154.370 57.820 ;
        RECT 146.160 57.480 151.740 57.520 ;
        RECT 146.170 57.030 151.750 57.100 ;
        RECT 143.810 56.700 151.750 57.030 ;
        RECT 143.810 55.460 144.230 56.700 ;
        RECT 146.170 56.690 151.750 56.700 ;
        RECT 146.170 56.260 151.750 56.340 ;
        RECT 153.960 56.260 154.370 57.520 ;
        RECT 146.170 55.960 154.370 56.260 ;
        RECT 146.170 55.930 151.750 55.960 ;
        RECT 146.200 55.460 151.780 55.520 ;
        RECT 143.810 55.130 151.780 55.460 ;
        RECT 146.200 55.110 151.780 55.130 ;
        RECT 146.180 54.640 151.760 54.760 ;
        RECT 153.960 54.640 154.370 55.960 ;
        RECT 146.180 54.350 154.400 54.640 ;
        RECT 151.620 54.340 154.400 54.350 ;
        RECT 180.740 53.700 184.120 56.880 ;
        RECT 151.360 51.340 156.940 51.390 ;
        RECT 149.520 51.030 156.940 51.340 ;
        RECT 149.570 49.790 149.980 51.030 ;
        RECT 151.360 50.980 156.940 51.030 ;
        RECT 151.370 50.530 156.950 50.600 ;
        RECT 165.200 50.580 165.600 50.650 ;
        RECT 166.800 50.580 167.200 50.630 ;
        RECT 165.150 50.570 168.680 50.580 ;
        RECT 158.290 50.530 159.180 50.540 ;
        RECT 151.370 50.280 159.210 50.530 ;
        RECT 165.150 50.350 168.700 50.570 ;
        RECT 151.370 50.190 156.950 50.280 ;
        RECT 151.370 49.790 156.950 49.840 ;
        RECT 149.550 49.480 156.950 49.790 ;
        RECT 149.570 48.200 149.980 49.480 ;
        RECT 151.370 49.430 156.950 49.480 ;
        RECT 151.400 48.910 156.980 49.020 ;
        RECT 158.290 48.910 159.180 50.280 ;
        RECT 151.400 48.660 159.220 48.910 ;
        RECT 151.400 48.610 156.980 48.660 ;
        RECT 151.380 48.200 156.960 48.260 ;
        RECT 149.570 47.890 156.960 48.200 ;
        RECT 151.380 47.850 156.960 47.890 ;
        RECT 153.460 47.810 155.140 47.850 ;
        RECT 155.840 47.520 156.140 47.530 ;
        RECT 155.840 47.450 156.990 47.520 ;
        RECT 158.290 47.450 159.180 48.660 ;
        RECT 155.840 47.410 159.190 47.450 ;
        RECT 159.770 47.410 160.210 47.440 ;
        RECT 155.840 47.000 160.210 47.410 ;
        RECT 155.840 46.870 156.990 47.000 ;
        RECT 158.290 46.960 159.180 47.000 ;
        RECT 151.360 46.860 156.990 46.870 ;
        RECT 103.990 42.330 135.720 43.090 ;
        RECT 139.100 43.630 142.120 44.580 ;
        RECT 149.670 46.690 156.990 46.860 ;
        RECT 149.670 46.510 156.940 46.690 ;
        RECT 149.670 45.310 150.320 46.510 ;
        RECT 151.360 46.460 156.940 46.510 ;
        RECT 159.770 46.620 160.210 47.000 ;
        RECT 151.370 45.970 156.950 46.080 ;
        RECT 151.370 45.700 159.580 45.970 ;
        RECT 159.770 45.940 160.230 46.620 ;
        RECT 151.370 45.670 156.950 45.700 ;
        RECT 151.370 45.310 156.950 45.320 ;
        RECT 149.670 44.960 156.950 45.310 ;
        RECT 149.670 43.700 150.320 44.960 ;
        RECT 151.370 44.910 156.950 44.960 ;
        RECT 151.400 44.460 156.980 44.500 ;
        RECT 158.380 44.460 158.940 45.700 ;
        RECT 151.400 44.150 160.040 44.460 ;
        RECT 151.400 44.090 156.980 44.150 ;
        RECT 151.380 43.700 156.960 43.740 ;
        RECT 139.100 42.810 147.310 43.630 ;
        RECT 149.650 43.350 156.960 43.700 ;
        RECT 151.380 43.330 156.960 43.350 ;
        RECT 139.100 42.790 142.120 42.810 ;
        RECT 110.380 42.300 135.720 42.330 ;
        RECT 119.920 42.080 135.720 42.300 ;
        RECT 120.290 42.060 135.720 42.080 ;
        RECT 146.160 32.380 147.280 42.810 ;
        RECT 158.030 42.020 159.330 44.150 ;
        RECT 164.400 32.700 164.730 50.010 ;
        RECT 165.200 49.810 165.600 50.350 ;
        RECT 165.220 33.190 165.550 49.810 ;
        RECT 166.000 33.500 166.330 49.950 ;
        RECT 166.800 49.790 167.200 50.350 ;
        RECT 165.990 33.140 166.330 33.500 ;
        RECT 165.990 32.700 166.320 33.140 ;
        RECT 166.810 33.070 167.140 49.790 ;
        RECT 167.580 33.540 167.910 49.820 ;
        RECT 168.300 49.730 168.700 50.350 ;
        RECT 167.580 33.010 167.920 33.540 ;
        RECT 168.340 33.010 168.670 49.730 ;
        RECT 167.590 32.700 167.920 33.010 ;
        RECT 164.400 32.410 167.920 32.700 ;
        RECT 146.160 32.010 163.580 32.380 ;
        RECT 164.400 32.340 167.910 32.410 ;
        RECT 164.780 32.010 165.310 32.040 ;
        RECT 146.160 31.500 165.310 32.010 ;
        RECT 163.490 31.480 165.310 31.500 ;
      LAYER via2 ;
        RECT 155.870 164.810 156.910 165.220 ;
        RECT 25.530 155.610 26.850 156.110 ;
        RECT 65.760 153.750 72.430 158.440 ;
        RECT 25.730 143.460 26.280 144.770 ;
        RECT 97.580 139.500 98.030 140.660 ;
        RECT 24.740 110.650 26.430 111.290 ;
        RECT 178.090 128.920 180.190 131.030 ;
        RECT 136.280 117.860 138.300 118.810 ;
        RECT 87.510 107.000 94.550 115.880 ;
        RECT 125.950 114.340 127.680 115.850 ;
        RECT 110.710 105.500 113.230 108.150 ;
        RECT 183.510 124.210 188.370 134.780 ;
        RECT 98.920 97.340 102.320 101.870 ;
        RECT 77.860 84.550 80.420 86.060 ;
        RECT 159.180 90.070 160.220 90.480 ;
        RECT 100.920 64.780 101.380 65.940 ;
        RECT 181.400 54.180 183.500 56.290 ;
        RECT 139.590 43.120 141.610 44.070 ;
      LAYER met3 ;
        RECT 155.580 164.480 157.170 165.490 ;
        RECT 25.050 155.260 27.290 156.480 ;
        RECT 63.710 151.940 74.730 160.230 ;
        RECT 25.350 143.130 26.680 145.040 ;
        RECT 97.430 139.250 98.170 140.870 ;
        RECT 135.790 117.530 138.810 119.320 ;
        RECT 85.710 111.620 96.190 117.350 ;
        RECT 125.360 113.900 128.150 116.310 ;
        RECT 4.200 110.420 96.190 111.620 ;
        RECT 85.710 105.650 96.190 110.420 ;
        RECT 85.770 105.640 96.160 105.650 ;
        RECT 110.070 104.860 113.850 108.640 ;
        RECT 98.430 96.910 102.730 102.340 ;
        RECT 141.080 98.290 171.480 162.090 ;
        RECT 182.950 135.140 188.720 135.150 ;
        RECT 177.410 128.380 180.810 131.630 ;
        RECT 182.950 123.760 188.730 135.140 ;
        RECT 182.950 123.750 188.720 123.760 ;
        RECT 158.890 89.740 160.480 90.750 ;
        RECT 76.960 83.860 81.180 86.750 ;
        RECT 100.740 64.550 101.530 66.130 ;
        RECT 139.100 42.790 142.120 44.580 ;
        RECT 144.390 23.550 174.790 87.350 ;
        RECT 180.720 53.640 184.120 56.890 ;
      LAYER via3 ;
        RECT 155.870 164.810 156.910 165.220 ;
        RECT 25.530 155.610 26.850 156.110 ;
        RECT 65.760 153.750 72.430 158.440 ;
        RECT 25.730 143.460 26.280 144.770 ;
        RECT 97.580 139.500 98.030 140.660 ;
        RECT 141.220 130.030 171.340 130.350 ;
        RECT 136.280 117.860 138.300 118.810 ;
        RECT 4.400 110.420 5.600 111.620 ;
        RECT 87.510 107.000 94.550 115.880 ;
        RECT 125.950 114.340 127.680 115.850 ;
        RECT 110.710 105.500 113.230 108.150 ;
        RECT 98.920 97.340 102.320 101.870 ;
        RECT 178.070 128.880 180.190 131.030 ;
        RECT 183.510 124.210 188.370 134.780 ;
        RECT 159.180 90.070 160.220 90.480 ;
        RECT 77.860 84.550 80.420 86.060 ;
        RECT 100.920 64.780 101.380 65.940 ;
        RECT 144.530 55.290 174.650 55.610 ;
        RECT 139.590 43.120 141.610 44.070 ;
        RECT 181.380 54.140 183.500 56.290 ;
      LAYER met4 ;
        RECT 4.540 224.760 15.030 225.170 ;
        RECT 15.330 224.760 17.790 225.170 ;
        RECT 18.090 224.760 20.550 225.170 ;
        RECT 20.850 224.760 23.310 225.170 ;
        RECT 23.610 224.760 26.070 225.170 ;
        RECT 26.370 224.760 28.830 225.170 ;
        RECT 29.130 224.760 31.590 225.170 ;
        RECT 31.890 224.760 34.350 225.170 ;
        RECT 34.650 224.760 37.110 225.170 ;
        RECT 37.410 224.760 39.870 225.170 ;
        RECT 40.170 224.760 42.630 225.170 ;
        RECT 42.930 224.760 45.390 225.170 ;
        RECT 45.690 224.760 48.150 225.170 ;
        RECT 48.450 224.760 50.910 225.170 ;
        RECT 51.210 224.760 53.670 225.170 ;
        RECT 53.970 224.760 56.430 225.170 ;
        RECT 56.730 224.760 59.190 225.170 ;
        RECT 59.490 224.760 61.950 225.170 ;
        RECT 62.250 224.760 64.710 225.170 ;
        RECT 65.010 224.760 67.470 225.170 ;
        RECT 67.770 224.760 70.230 225.170 ;
        RECT 70.530 224.760 72.990 225.170 ;
        RECT 73.290 224.760 75.750 225.170 ;
        RECT 76.050 224.760 78.510 225.170 ;
        RECT 78.810 224.760 80.330 225.170 ;
        RECT 4.540 224.270 80.330 224.760 ;
        RECT 4.540 224.250 5.630 224.270 ;
        RECT 4.540 220.780 5.550 224.250 ;
        RECT 4.480 220.760 5.590 220.780 ;
        RECT 155.580 164.750 157.170 165.490 ;
        RECT 155.530 164.480 157.170 164.750 ;
        RECT 155.530 161.695 157.160 164.480 ;
        RECT 63.670 160.230 74.720 160.260 ;
        RECT 63.670 156.460 74.730 160.230 ;
        RECT 9.000 155.260 74.730 156.460 ;
        RECT 63.670 151.940 74.730 155.260 ;
        RECT 63.670 151.870 74.720 151.940 ;
        RECT 25.370 143.130 26.680 145.040 ;
        RECT 25.370 99.690 26.660 143.130 ;
        RECT 97.430 140.670 98.170 140.870 ;
        RECT 97.430 139.420 119.360 140.670 ;
        RECT 97.430 139.250 98.170 139.420 ;
        RECT 85.710 105.650 96.190 117.350 ;
        RECT 110.070 104.860 113.850 108.640 ;
        RECT 98.430 99.690 102.730 102.340 ;
        RECT 25.370 98.120 102.730 99.690 ;
        RECT 98.430 96.910 102.730 98.120 ;
        RECT 76.960 86.670 81.180 86.750 ;
        RECT 39.410 85.610 81.180 86.670 ;
        RECT 39.410 79.580 40.460 85.610 ;
        RECT 76.960 83.860 81.180 85.610 ;
        RECT 39.510 1.000 40.370 79.580 ;
        RECT 100.740 65.920 101.530 66.130 ;
        RECT 58.850 64.650 101.530 65.920 ;
        RECT 58.850 1.000 59.820 64.650 ;
        RECT 100.740 64.550 101.530 64.650 ;
        RECT 111.010 22.750 112.550 104.860 ;
        RECT 39.510 0.000 39.570 1.000 ;
        RECT 58.850 0.000 58.890 1.000 ;
        RECT 59.790 0.000 59.820 1.000 ;
        RECT 77.920 20.590 112.550 22.750 ;
        RECT 77.920 1.000 79.120 20.590 ;
        RECT 118.110 14.750 119.360 139.420 ;
        RECT 141.475 132.085 171.085 161.695 ;
        RECT 182.950 135.140 188.720 135.150 ;
        RECT 177.410 130.530 180.850 131.630 ;
        RECT 170.520 130.430 180.850 130.530 ;
        RECT 141.140 129.950 180.850 130.430 ;
        RECT 170.520 129.710 180.850 129.950 ;
        RECT 177.410 128.390 180.850 129.710 ;
        RECT 141.475 119.400 171.085 128.295 ;
        RECT 182.950 123.760 188.730 135.140 ;
        RECT 182.950 123.750 188.720 123.760 ;
        RECT 138.570 119.320 171.085 119.400 ;
        RECT 135.790 117.530 171.085 119.320 ;
        RECT 138.570 117.490 171.085 117.530 ;
        RECT 125.360 113.900 128.150 116.310 ;
        RECT 77.920 0.000 78.210 1.000 ;
        RECT 79.110 0.000 79.120 1.000 ;
        RECT 97.440 13.410 119.360 14.750 ;
        RECT 97.440 1.000 98.500 13.410 ;
        RECT 126.570 9.670 128.010 113.900 ;
        RECT 141.475 98.685 171.085 117.490 ;
        RECT 158.890 90.010 160.480 90.750 ;
        RECT 158.840 89.740 160.480 90.010 ;
        RECT 158.840 86.955 160.470 89.740 ;
        RECT 144.785 57.345 174.395 86.955 ;
        RECT 180.720 55.790 184.160 56.890 ;
        RECT 173.830 55.690 184.160 55.790 ;
        RECT 144.450 55.210 184.160 55.690 ;
        RECT 173.830 54.970 184.160 55.210 ;
        RECT 180.720 53.650 184.160 54.970 ;
        RECT 144.785 44.660 174.395 53.555 ;
        RECT 141.880 44.580 174.395 44.660 ;
        RECT 139.100 42.790 174.395 44.580 ;
        RECT 141.880 42.750 174.395 42.790 ;
        RECT 144.785 23.945 174.395 42.750 ;
        RECT 97.440 0.040 97.530 1.000 ;
        RECT 98.430 0.040 98.500 1.000 ;
        RECT 116.790 8.520 128.010 9.670 ;
        RECT 116.790 1.000 117.840 8.520 ;
        RECT 185.690 1.050 187.300 123.750 ;
        RECT 136.270 1.000 187.300 1.050 ;
        RECT 116.790 0.170 116.850 1.000 ;
        RECT 117.750 0.170 117.840 1.000 ;
        RECT 137.070 0.000 187.300 1.000 ;
  END
END tt_um_niclemmons_instamp
END LIBRARY

